
# LEF file generated by Abstract Generator version 5.5.12 on Aug 29 09:16:09 2003
#
# Contains LEF for bin Core.
# Options:   [ ] Antenna
#            [x] Geometry
#            [x] Technology

VERSION 5.3 ;
NAMESCASESENSITIVE ON ;
BUSBITCHARS "[]" ;
DIVIDERCHAR "/" ;
UNITS
  DATABASE MICRONS 1000 ;
END UNITS


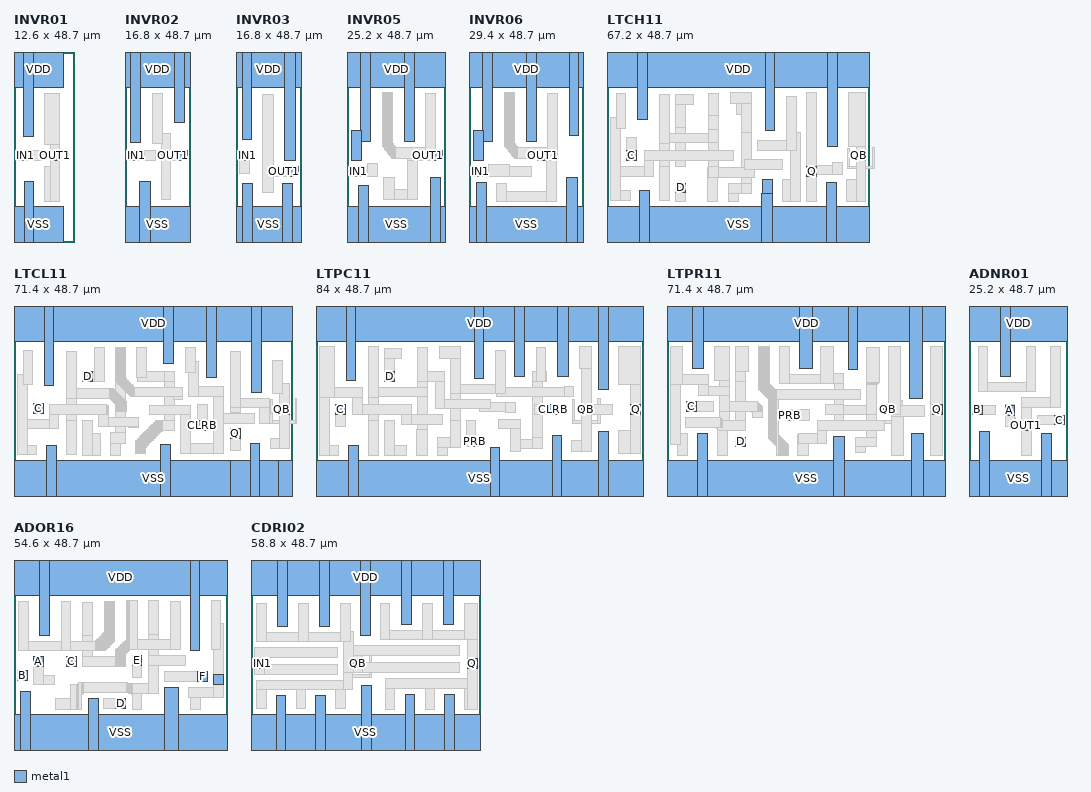
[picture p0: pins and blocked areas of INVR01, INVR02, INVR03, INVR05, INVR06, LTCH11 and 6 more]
macro INVR01
  CLASS  CORE ;
  FOREIGN INVR01 0.000 0.000 ;
  ORIGIN 0.000 0.000 ;
  SIZE 12.600 BY 48.700 ;
  SYMMETRY X Y  ;
  SITE CORE ;
  PIN OUT1
    DIRECTION OUTPUT ;
    PORT
      LAYER metal1 ;
       RECT 9.250 21.000 11.750 23.500 ;
    END
  END OUT1
  PIN VSS
    DIRECTION INOUT ;
    USE GROUND ;
    SHAPE ABUTMENT ;
    PORT
      LAYER metal1 ;
        RECT 2.600 0.000 5.100 15.550 ;
        RECT 0.000 0.000 12.600 9.000 ;
    END
  END VSS
  PIN IN1
    DIRECTION INPUT ;
    PORT
      LAYER metal1 ;
        RECT 0.850 21.000 3.350 23.500 ;
    END
  END IN1
  PIN VDD
    DIRECTION INOUT ;
    USE POWER ;
    SHAPE ABUTMENT ;
    PORT
      LAYER metal1 ;
        RECT 2.550 27.000 5.050 48.700 ;
        RECT 0.000 39.700 12.600 48.700 ;
    END
  END VDD
  OBS 
      
      LAYER metal1 ;
        RECT 0.850 21.000 7.750 23.500 ;
        RECT 7.900 10.500 11.750 19.450 ;
        RECT 9.250 10.500 11.750 38.000 ;
        RECT 7.900 25.050 11.750 38.000 ;
  END 

END INVR01

macro INVR02
  CLASS  CORE ;
  FOREIGN INVR02 0.000 0.000 ;
  ORIGIN 0.000 0.000 ;
  SIZE 16.800 BY 48.700 ;
  SYMMETRY X Y  ;
  SITE CORE ;
  PIN OUT1
    DIRECTION OUTPUT ;
    PORT
      LAYER metal1 ;
        RECT 13.450 21.000 15.950 23.500 ;
    END
  END OUT1
  PIN VSS
    DIRECTION INOUT ;
    USE GROUND ;
    SHAPE ABUTMENT ;
    PORT
      LAYER metal1 ;
        RECT 3.700 0.000 6.450 15.400 ;
        RECT 0.000 0.000 16.800 9.000 ;
    END
  END VSS
  PIN IN1
    DIRECTION INPUT ;
    PORT
      LAYER metal1 ;
        RECT 0.850 21.000 3.350 23.500 ;
    END
  END IN1
  PIN VDD
    DIRECTION INOUT ;
    USE POWER ;
    SHAPE ABUTMENT ;
    PORT
      LAYER metal1 ;
        RECT 1.400 25.600 4.100 48.700 ;
        RECT 0.000 39.700 16.800 48.700 ;
        RECT 12.700 30.600 15.300 48.700 ;
    END
  END VDD
  OBS 
     
      LAYER metal1 ;
        RECT 4.950 21.000 7.750 23.550 ;
        RECT 9.250 21.000 15.950 23.550 ;
        RECT 9.250 10.850 11.750 27.750 ;
        RECT 7.150 25.250 9.700 38.100 ;
  END 
END INVR02




macro INVR03
  CLASS  CORE ;
  FOREIGN INVR03 0.000 0.000 ;
  ORIGIN 0.000 0.000 ;
  SIZE 16.800 BY 48.700 ;
  SYMMETRY X Y  ;
  SITE CORE ;
  PIN OUT1
    DIRECTION OUTPUT ;
    PORT
      LAYER metal1 ;
        RECT 13.450 16.800 15.950 19.300 ;
    END
  END OUT1
  PIN VSS
    DIRECTION INOUT ;
    USE GROUND ;
    SHAPE ABUTMENT ;
    PORT
      LAYER metal1 ;
        RECT 1.600 0.000 4.200 15.100 ;
        RECT 0.000 0.000 16.800 9.000 ;
        RECT 11.950 0.000 14.500 15.100 ;
    END
  END VSS
  PIN IN1
    DIRECTION INPUT ;
    PORT
      LAYER metal1 ;
        RECT 0.850 21.000 3.350 23.500 ;
    END
  END IN1
  PIN VDD
    DIRECTION INOUT ;
    USE POWER ;
    SHAPE ABUTMENT ;
    PORT
      LAYER metal1 ;
        RECT 1.550 26.150 4.100 48.700 ;
        RECT 0.000 39.700 16.800 48.700 ;
        RECT 12.450 20.850 15.250 48.700 ;
    END
  END VDD
  OBS 
     
      LAYER metal1 ;
        RECT 0.850 17.600 3.550 23.500 ;
        RECT 6.800 16.800 15.950 19.300 ;
        RECT 6.800 12.700 9.500 37.850 ;
  END 
END INVR03

macro INVR05
  CLASS  CORE ;
  FOREIGN INVR05 0.000 0.000 ;
  ORIGIN 0.000 0.000 ;
  SIZE 25.200 BY 48.700 ;
  SYMMETRY X Y  ;
  SITE CORE ;
  PIN OUT1
    DIRECTION OUTPUT ;
    PORT
      LAYER metal1 ;
        RECT 21.850 21.000 24.350 23.500 ;
    END
  END OUT1
  PIN VSS
    DIRECTION INOUT ;
    USE GROUND ;
    SHAPE ABUTMENT ;
    PORT
      LAYER metal1 ;
        RECT 2.950 0.000 5.450 14.450 ;
        RECT 0.000 0.000 25.200 9.000 ;
        RECT 21.350 0.000 23.850 16.450 ;
    END
  END VSS
  PIN IN1
    DIRECTION INPUT ;
    PORT
      LAYER metal1 ;
        RECT 0.850 16.800 3.350 19.300 ;
    END
  END IN1
  PIN VDD
    DIRECTION INOUT ;
    USE POWER ;
    SHAPE ABUTMENT ;
    PORT
      LAYER metal1 ;
        RECT 0.000 39.700 25.200 48.700 ;
        RECT 14.750 25.700 17.300 48.700 ;
        RECT 3.500 25.800 6.150 48.700 ;
        RECT 1.250 20.800 3.750 28.550 ;
    END
  END VDD
  OBS 
    
      LAYER metal1 ;
        RECT 0.850 16.800 7.850 19.300 ;
        RECT 5.350 16.800 7.850 20.150 ;
        RECT 9.400 10.900 18.100 13.450 ;
        RECT 9.400 10.900 12.050 16.550 ;
        RECT 15.550 10.900 18.100 24.200 ;
        RECT 15.550 21.000 24.350 23.500 ;
        RECT 12.532 21.450 22.650 24.200 ;
        RECT 20.150 21.000 22.650 38.150 ;
        RECT 11.473 21.450 11.700 38.200 ;
        RECT 11.700 21.450 11.800 25.170 ;
        RECT 11.800 21.450 11.900 25.040 ;
        RECT 11.900 21.450 12.000 24.905 ;
        RECT 12.000 21.450 12.100 24.775 ;
        RECT 12.100 21.450 12.200 24.640 ;
        RECT 12.200 21.450 12.300 24.510 ;
        RECT 12.300 21.450 12.400 24.375 ;
        RECT 12.400 21.450 12.500 24.245 ;
        RECT 12.500 21.450 12.532 24.200 ;
        RECT 9.200 24.470 9.300 38.200 ;
        RECT 9.300 24.335 9.400 38.200 ;
        RECT 9.400 24.205 9.500 38.200 ;
        RECT 9.500 24.070 9.600 38.200 ;
        RECT 9.600 23.938 9.700 38.200 ;
        RECT 9.700 23.805 9.800 38.200 ;
        RECT 9.800 23.670 9.900 38.200 ;
        RECT 9.900 23.540 10.000 38.200 ;
        RECT 10.000 23.405 10.100 38.200 ;
        RECT 10.100 23.275 10.200 38.200 ;
        RECT 10.200 23.140 10.300 38.200 ;
        RECT 10.300 23.010 10.400 38.200 ;
        RECT 10.400 22.875 10.500 38.200 ;
        RECT 10.500 22.740 10.600 38.200 ;
        RECT 10.600 22.610 10.700 38.200 ;
        RECT 10.700 22.475 10.800 38.200 ;
        RECT 10.800 22.345 10.900 38.200 ;
        RECT 10.900 22.210 11.000 38.200 ;
        RECT 11.000 22.078 11.100 38.200 ;
        RECT 11.100 21.945 11.200 38.200 ;
        RECT 11.200 21.813 11.300 38.200 ;
        RECT 11.300 21.680 11.400 38.200 ;
        RECT 11.400 21.545 11.475 38.200 ;
  END 
END INVR05





macro INVR06
  CLASS  CORE ;
  FOREIGN INVR06 0.000 0.000 ;
  ORIGIN 0.000 0.000 ;
  SIZE 29.400 BY 48.700 ;
  SYMMETRY X Y  ;
  SITE CORE ;
  PIN OUT1
    DIRECTION OUTPUT ;
    PORT
      LAYER metal1 ;
        RECT 17.650 21.000 20.150 23.500 ;
    END
  END OUT1
  PIN VSS
    DIRECTION INOUT ;
    USE GROUND ;
    SHAPE ABUTMENT ;
    PORT
      LAYER metal1 ;
        RECT 1.950 0.000 4.450 15.300 ;
        RECT 0.000 0.000 29.400 9.000 ;
        RECT 25.100 0.000 27.900 16.650 ;
    END
  END VSS
  PIN IN1
    DIRECTION INPUT ;
    PORT
      LAYER metal1 ;
        RECT 0.850 16.800 3.350 19.300 ;
    END
  END IN1
  PIN VDD
    DIRECTION INOUT ;
    USE POWER ;
    SHAPE ABUTMENT ;
    PORT
      LAYER metal1 ;
        RECT 0.000 39.700 29.400 48.700 ;
        RECT 25.650 27.300 28.150 48.700 ;
        RECT 14.750 25.700 17.300 48.700 ;
        RECT 3.500 25.800 6.150 48.700 ;
        RECT 1.250 20.800 3.750 28.550 ;
    END
  END VDD
  OBS 
    
      LAYER metal1 ;
        RECT 0.850 16.800 16.050 19.300 ;
        RECT 4.950 16.800 16.050 19.450 ;
        RECT 4.950 16.800 10.450 19.900 ;
        RECT 7.050 10.500 22.400 13.050 ;
        RECT 7.050 10.500 9.550 15.100 ;
        RECT 17.650 21.000 22.650 24.200 ;
        RECT 19.900 10.500 22.400 24.200 ;
        RECT 12.530 21.450 22.650 24.200 ;
        RECT 20.150 21.000 22.650 38.150 ;
        RECT 11.565 21.450 11.700 38.200 ;
        RECT 11.700 21.450 11.800 25.170 ;
        RECT 11.800 21.450 11.900 25.040 ;
        RECT 11.900 21.450 12.000 24.905 ;
        RECT 12.000 21.450 12.100 24.775 ;
        RECT 12.100 21.450 12.200 24.640 ;
        RECT 12.200 21.450 12.300 24.510 ;
        RECT 12.300 21.450 12.400 24.375 ;
        RECT 12.400 21.450 12.500 24.240 ;
        RECT 12.500 21.450 12.530 24.200 ;
        RECT 9.200 24.590 9.300 38.200 ;
        RECT 9.300 24.460 9.400 38.200 ;
        RECT 9.400 24.320 9.500 38.200 ;
        RECT 9.500 24.195 9.600 38.200 ;
        RECT 9.600 24.061 9.700 38.200 ;
        RECT 9.700 23.930 9.800 38.200 ;
        RECT 9.800 23.795 9.900 38.200 ;
        RECT 9.900 23.660 10.000 38.200 ;
        RECT 10.000 23.530 10.100 38.200 ;
        RECT 10.100 23.400 10.200 38.200 ;
        RECT 10.200 23.265 10.300 38.200 ;
        RECT 10.300 23.130 10.400 38.200 ;
        RECT 10.400 22.995 10.500 38.200 ;
        RECT 10.500 22.865 10.600 38.200 ;
        RECT 10.600 22.730 10.700 38.200 ;
        RECT 10.700 22.600 10.800 38.200 ;
        RECT 10.800 22.465 10.900 38.200 ;
        RECT 10.900 22.335 11.000 38.200 ;
        RECT 11.000 22.200 11.100 38.200 ;
        RECT 11.100 22.070 11.200 38.200 ;
        RECT 11.200 21.934 11.300 38.200 ;
        RECT 11.300 21.800 11.400 38.200 ;
        RECT 11.400 21.670 11.500 38.200 ;
        RECT 11.500 21.535 11.564 38.200 ;
  END 
END INVR06

macro LTCH11
  CLASS  CORE ;
  FOREIGN LTCH11 0.000 0.000 ;
  ORIGIN 0.000 0.000 ;
  SIZE 67.200 BY 48.700 ;
  SYMMETRY X Y  ;
  SITE CORE ;
  PIN Q
    DIRECTION OUTPUT ;
    PORT
      LAYER metal1 ;
        RECT 51.250 16.800 53.750 19.300 ;
    END
  END Q
  PIN C
    DIRECTION INPUT ;
    USE CLOCK ;
    PORT
      LAYER metal1 ;
        RECT 5.050 21.000 7.550 23.500 ;
    END
  END C
  PIN D
    DIRECTION INPUT ;
    PORT
      LAYER metal1 ;
        RECT 17.650 12.600 20.150 15.100 ;
    END
  END D
  PIN QB
    DIRECTION OUTPUT ;
    PORT
      LAYER metal1 ;
        RECT 63.850 21.000 66.350 23.500 ;
    END
  END QB
  PIN VSS
    DIRECTION INOUT ;
    USE GROUND ;
    SHAPE ABUTMENT ;
    PORT
      LAYER metal1 ;
        RECT 8.350 0.000 10.850 13.100 ;
        RECT 0.000 0.000 67.200 9.000 ;
        RECT 56.350 0.000 58.850 15.300 ;
        RECT 39.850 0.000 42.350 16.100 ;
        RECT 39.550 0.000 42.350 12.400 ;
    END
  END VSS
  PIN VDD
    DIRECTION INOUT ;
    USE POWER ;
    SHAPE ABUTMENT ;
    PORT
      LAYER metal1 ;
        RECT 7.750 31.500 10.350 48.700 ;
        RECT 0.000 39.700 67.200 48.700 ;
        RECT 56.500 24.500 59.000 48.700 ;
        RECT 40.550 28.500 43.050 48.700 ;
    END
  END VDD
  OBS 
      LAYER metal2 ;
        RECT 13.450 16.800 15.950 27.700 ;
        RECT 26.050 16.800 28.550 35.600 ;
        RECT 34.450 12.600 36.950 31.900 ;
        RECT 17.650 19.303 20.150 31.900 ;
        RECT 61.550 18.800 62.150 24.050 ;
        RECT 61.600 18.800 68.050 19.300 ;
        RECT 68.050 18.800 68.500 24.140 ;
        
      LAYER via1 ;
        
        RECT 13.950 25.700 15.450 27.200 ;
        RECT 13.950 17.300 15.450 18.800 ;
        RECT 18.150 29.900 19.650 31.400 ;
        
        RECT 26.550 33.100 28.050 34.600 ;
        RECT 26.550 17.300 28.050 18.800 ;
        RECT 34.950 28.750 36.450 30.250 ;
        RECT 34.950 13.100 36.450 14.600 ;
        
       
      LAYER metal1 ;
        RECT 5.050 21.000 7.550 26.700 ;
        RECT 13.450 10.600 15.950 19.300 ;
        RECT 17.650 29.400 20.150 37.800 ;
        RECT 17.650 35.300 22.250 37.800 ;
        
        RECT 17.650 10.500 20.150 15.100 ;
        RECT 26.050 32.550 28.550 38.100 ;
        RECT 13.450 25.400 28.550 27.900 ;
        RECT 26.050 25.400 28.550 28.800 ;
        RECT 13.450 25.200 16.050 37.750 ;
        RECT 0.850 10.600 5.950 13.100 ;
        RECT 0.850 16.800 11.950 19.300 ;
        RECT 9.550 16.800 11.950 23.500 ;
        RECT 9.550 21.000 32.550 23.500 ;
        RECT 0.850 10.600 3.350 31.900 ;
        RECT 2.350 29.050 4.850 38.150 ;
        RECT 31.150 10.500 33.650 15.000 ;
        RECT 31.150 12.500 36.950 15.000 ;
        RECT 34.450 12.500 36.950 15.100 ;
        RECT 33.100 32.700 37.050 38.200 ;
        RECT 34.450 28.050 37.050 38.200 ;
        RECT 31.550 35.400 37.050 38.200 ;
        RECT 25.850 16.600 37.850 19.100 ;
        RECT 25.850 10.500 28.350 19.200 ;
        RECT 26.050 16.600 28.550 19.300 ;
        RECT 35.350 18.600 45.000 21.200 ;
        RECT 45.100 10.500 49.550 16.100 ;
        RECT 38.450 23.500 49.550 26.000 ;
        RECT 47.050 10.500 49.550 28.000 ;
        RECT 45.950 23.500 48.650 37.250 ;
        RECT 51.100 10.500 53.750 19.700 ;
        RECT 51.100 17.200 60.400 19.700 ;
        RECT 57.700 17.200 60.400 20.500 ;
        RECT 51.100 10.500 53.600 38.200 ;
        RECT 61.450 10.500 66.350 16.000 ;
        RECT 63.850 10.500 66.350 38.200 ;
        RECT 61.900 24.500 66.350 38.200 ;
  END 
END LTCH11









macro LTCL11
  CLASS  CORE ;
  FOREIGN LTCL11 0.000 0.000 ;
  ORIGIN 0.000 0.000 ;
  SIZE 71.400 BY 48.700 ;
  SYMMETRY X Y  ;
  SITE CORE ;
  PIN Q
    DIRECTION OUTPUT ;
    PORT
      LAYER metal1 ;
        RECT 55.450 14.700 57.950 17.200 ;
    END
  END Q
  PIN C
    DIRECTION INPUT ;
    USE CLOCK ;
    PORT
      LAYER metal1 ;
        RECT 5.050 21.200 7.550 23.700 ;
    END
  END C
  PIN D
    DIRECTION INPUT ;
    PORT
      LAYER metal1 ;
        RECT 17.650 29.400 20.150 31.900 ;
    END
  END D
  PIN QB
    DIRECTION OUTPUT ;
    PORT
      LAYER metal1 ;
        RECT 68.050 21.000 70.550 23.500 ;
    END
  END QB
  PIN VSS
    DIRECTION INOUT ;
    USE GROUND ;
    SHAPE ABUTMENT ;
    PORT
      LAYER metal1 ;
        RECT 8.350 0.000 10.850 13.050 ;
        RECT 0.000 0.000 71.400 9.000 ;
        RECT 55.450 0.000 67.750 9.100 ;
        RECT 60.550 0.000 63.050 13.400 ;
        RECT 37.550 0.000 40.050 13.100 ;
    END
  END VSS
  PIN VDD
    DIRECTION INOUT ;
    USE POWER ;
    SHAPE ABUTMENT ;
    PORT
      LAYER metal1 ;
        RECT 7.750 28.300 10.250 48.700 ;
        RECT 0.000 39.700 71.400 48.700 ;
        RECT 60.850 26.500 63.350 48.700 ;
        RECT 49.450 30.500 51.950 48.700 ;
        RECT 38.400 34.000 40.900 48.700 ;
    END
  END VDD
  PIN CLRB
    DIRECTION INPUT ;
    PORT
      LAYER metal1 ;
        RECT 47.050 16.800 49.550 19.300 ;
    END
  END CLRB
  OBS 
      LAYER metal2 ;
        RECT 13.450 16.800 15.950 27.600 ;
        RECT 26.050 13.500 28.550 32.000 ;
        RECT 38.650 16.800 41.150 32.000 ;
        RECT 55.450 21.400 57.950 27.700 ;
        RECT 65.750 18.700 66.350 24.850 ;
        RECT 65.750 18.700 72.250 19.300 ;
        RECT 72.250 18.700 72.530 24.880 ;
        
        
      LAYER via1 ;
     
        RECT 13.950 25.600 15.450 27.100 ;
        RECT 13.950 17.300 15.450 18.800 ;
       
        RECT 18.150 17.300 19.650 18.800 ;
        RECT 26.550 30.000 28.050 31.500 ;
        RECT 26.550 14.200 28.050 15.700 ;
        RECT 39.150 30.000 40.650 31.500 ;
        RECT 39.150 17.300 40.650 18.800 ;
        
        RECT 55.950 24.950 57.450 26.124 ;
        
      LAYER metal1 ;
        
        RECT 13.450 10.550 15.950 19.300 ;
        RECT 17.650 10.500 22.150 16.000 ;
        RECT 17.650 10.500 20.150 19.300 ;
        RECT 17.650 29.400 23.150 31.900 ;
        RECT 20.650 29.400 23.150 38.150 ;
        RECT 24.750 10.500 27.250 16.200 ;
        RECT 24.750 13.500 28.550 16.200 ;
        RECT 13.450 25.100 24.502 27.500 ;
        RECT 13.450 25.100 15.950 37.050 ;
        RECT 26.250 21.650 26.350 26.698 ;
        RECT 26.350 21.650 26.450 26.598 ;
        RECT 26.450 21.650 26.550 26.498 ;
        RECT 26.550 21.650 26.650 26.398 ;
        RECT 26.650 21.650 26.750 26.298 ;
        RECT 26.750 21.650 26.850 26.198 ;
        RECT 26.850 21.650 26.950 26.098 ;
        RECT 26.950 21.650 27.050 25.998 ;
        RECT 27.050 21.650 27.150 25.898 ;
        RECT 27.150 21.650 27.250 25.798 ;
        RECT 27.250 21.650 27.350 25.698 ;
        RECT 27.350 21.650 27.450 25.598 ;
        RECT 27.450 21.650 27.550 25.498 ;
        RECT 27.550 21.650 27.650 25.398 ;
        RECT 27.650 21.650 27.750 25.298 ;
        RECT 27.750 21.650 27.850 25.198 ;
        RECT 27.850 21.650 27.950 25.098 ;
        RECT 27.950 21.650 28.050 24.998 ;
        RECT 28.050 21.650 28.150 24.898 ;
        RECT 28.150 21.650 28.250 24.798 ;
        RECT 28.250 21.650 28.350 24.698 ;
        RECT 28.350 21.650 28.450 24.598 ;
        RECT 28.450 21.650 28.550 24.498 ;
        RECT 28.550 21.650 28.650 24.398 ;
        RECT 28.650 21.650 28.750 24.298 ;
        RECT 28.750 21.650 28.850 24.198 ;
        RECT 28.850 21.650 28.950 24.098 ;
        RECT 25.600 24.002 25.700 27.348 ;
        RECT 25.700 23.902 25.800 27.248 ;
        RECT 25.800 23.802 25.900 27.148 ;
        RECT 25.900 23.702 26.000 27.048 ;
        RECT 26.000 23.602 26.100 26.948 ;
        RECT 26.100 23.502 26.200 26.848 ;
        RECT 26.200 23.402 26.250 26.798 ;
        RECT 25.550 24.052 25.600 27.450 ;
        RECT 24.502 25.100 24.602 27.500 ;
        RECT 24.602 25.000 24.702 27.500 ;
        RECT 24.702 24.900 24.802 27.500 ;
        RECT 24.802 24.800 24.902 27.500 ;
        RECT 24.902 24.700 25.002 27.500 ;
        RECT 25.002 24.600 25.102 27.500 ;
        RECT 25.102 24.500 25.202 27.500 ;
        RECT 25.202 24.400 25.302 27.500 ;
        RECT 25.302 24.300 25.402 27.500 ;
        RECT 25.402 24.200 25.502 27.500 ;
        RECT 25.502 24.100 25.550 27.500 ;
        RECT 0.850 10.550 5.750 13.050 ;
        RECT 0.850 17.300 11.450 19.700 ;
        RECT 29.450 17.650 31.950 20.150 ;
        RECT 21.650 17.750 31.950 20.150 ;
        RECT 9.050 17.300 11.450 23.500 ;
        RECT 21.650 17.750 24.100 23.100 ;
        RECT 9.050 21.000 24.000 23.200 ;
        RECT 9.050 21.000 23.900 23.300 ;
        RECT 9.050 21.000 23.800 23.400 ;
        RECT 9.050 21.000 23.700 23.500 ;
        RECT 0.850 10.550 3.350 31.050 ;
        RECT 2.350 28.550 4.850 37.300 ;
        RECT 31.750 29.300 41.150 31.800 ;
        RECT 38.650 29.300 41.150 32.000 ;
        RECT 31.450 30.500 33.950 38.150 ;
        RECT 31.150 10.900 31.352 14.250 ;
        RECT 38.098 16.800 41.150 19.300 ;
        RECT 36.350 15.152 36.450 19.300 ;
        RECT 36.450 15.252 36.550 19.300 ;
        RECT 36.550 15.352 36.650 19.300 ;
        RECT 36.650 15.452 36.750 19.300 ;
        RECT 36.750 15.552 36.850 19.300 ;
        RECT 36.850 15.652 36.950 19.300 ;
        RECT 36.950 15.752 37.050 19.300 ;
        RECT 37.050 15.852 37.150 19.300 ;
        RECT 37.150 15.952 37.250 19.300 ;
        RECT 37.250 16.052 37.350 19.300 ;
        RECT 37.350 16.152 37.450 19.300 ;
        RECT 37.450 16.252 37.550 19.300 ;
        RECT 37.550 16.352 37.650 19.300 ;
        RECT 37.650 16.452 37.750 19.300 ;
        RECT 37.750 16.552 37.850 19.300 ;
        RECT 37.850 16.652 37.950 19.300 ;
        RECT 37.950 16.752 38.050 19.300 ;
        RECT 38.050 16.800 38.098 19.300 ;
        RECT 33.650 12.452 33.750 16.548 ;
        RECT 33.750 12.552 33.850 16.648 ;
        RECT 33.850 12.652 33.950 16.748 ;
        RECT 33.950 12.752 34.050 16.848 ;
        RECT 34.050 12.852 34.150 16.948 ;
        RECT 34.150 12.952 34.250 17.048 ;
        RECT 34.250 13.052 34.350 17.148 ;
        RECT 34.350 13.152 34.450 17.248 ;
        RECT 34.450 13.252 34.550 17.348 ;
        RECT 34.550 13.352 34.650 17.448 ;
        RECT 34.650 13.452 34.750 17.548 ;
        RECT 34.750 13.552 34.850 17.648 ;
        RECT 34.850 13.652 34.950 17.748 ;
        RECT 34.950 13.752 35.050 17.848 ;
        RECT 35.050 13.852 35.150 17.948 ;
        RECT 35.150 13.952 35.250 18.048 ;
        RECT 35.250 14.052 35.350 18.148 ;
        RECT 35.350 14.152 35.450 18.248 ;
        RECT 35.450 14.252 35.550 18.348 ;
        RECT 35.550 14.352 35.650 18.448 ;
        RECT 35.650 14.452 35.750 18.548 ;
        RECT 35.750 14.552 35.850 18.648 ;
        RECT 35.850 14.652 35.950 18.748 ;
        RECT 35.950 14.752 36.050 18.848 ;
        RECT 36.050 14.852 36.150 18.948 ;
        RECT 36.150 14.952 36.250 19.048 ;
        RECT 36.250 15.052 36.350 19.148 ;
        RECT 31.352 10.900 31.452 14.250 ;
        RECT 31.452 10.900 31.552 14.350 ;
        RECT 31.552 10.900 31.652 14.450 ;
        RECT 31.652 10.900 31.752 14.550 ;
        RECT 31.752 10.900 31.852 14.650 ;
        RECT 31.852 10.900 31.952 14.750 ;
        RECT 31.952 10.900 32.052 14.850 ;
        RECT 32.052 10.900 32.152 14.950 ;
        RECT 32.152 10.900 32.252 15.050 ;
        RECT 32.252 10.900 32.352 15.150 ;
        RECT 32.352 10.900 32.452 15.250 ;
        RECT 32.452 10.900 32.552 15.350 ;
        RECT 32.552 10.900 32.652 15.450 ;
        RECT 32.652 10.900 32.752 15.550 ;
        RECT 32.752 10.900 32.852 15.650 ;
        RECT 32.852 10.900 32.952 15.750 ;
        RECT 32.952 10.900 33.052 15.850 ;
        RECT 33.052 10.900 33.152 15.950 ;
        RECT 33.152 10.900 33.252 16.050 ;
        RECT 33.252 10.900 33.352 16.150 ;
        RECT 33.352 10.900 33.452 16.250 ;
        RECT 33.452 10.900 33.552 16.350 ;
        RECT 33.552 10.900 33.650 16.450 ;
        RECT 40.800 24.800 43.300 27.800 ;
        RECT 30.948 25.400 43.300 27.800 ;
        RECT 26.350 29.000 26.352 38.150 ;
        RECT 29.950 25.400 30.050 28.698 ;
        RECT 30.050 25.400 30.150 28.598 ;
        RECT 30.150 25.400 30.250 28.498 ;
        RECT 30.250 25.400 30.350 28.398 ;
        RECT 30.350 25.400 30.450 28.298 ;
        RECT 30.450 25.400 30.550 28.198 ;
        RECT 30.550 25.400 30.650 28.098 ;
        RECT 30.650 25.400 30.750 27.998 ;
        RECT 30.750 25.400 30.850 27.898 ;
        RECT 30.850 25.400 30.948 27.800 ;
        RECT 29.800 25.550 29.900 28.848 ;
        RECT 29.900 25.450 29.950 28.798 ;
        RECT 28.550 26.802 28.650 30.098 ;
        RECT 28.650 26.702 28.750 29.998 ;
        RECT 28.750 26.602 28.850 29.898 ;
        RECT 28.850 26.502 28.950 29.798 ;
        RECT 28.950 26.402 29.050 29.698 ;
        RECT 29.050 26.302 29.150 29.598 ;
        RECT 29.150 26.202 29.250 29.498 ;
        RECT 29.250 26.102 29.350 29.398 ;
        RECT 29.350 26.002 29.450 29.298 ;
        RECT 29.450 25.902 29.550 29.198 ;
        RECT 29.550 25.802 29.650 29.098 ;
        RECT 29.650 25.702 29.750 28.998 ;
        RECT 29.750 25.602 29.800 28.948 ;
        RECT 26.352 29.000 26.452 38.150 ;
        RECT 26.452 28.900 26.552 38.150 ;
        RECT 26.552 28.800 26.652 38.150 ;
        RECT 26.652 28.700 26.752 38.150 ;
        RECT 26.752 28.600 26.852 38.150 ;
        RECT 26.852 28.500 26.952 38.150 ;
        RECT 26.952 28.400 27.052 38.150 ;
        RECT 27.052 28.300 27.152 38.150 ;
        RECT 27.152 28.200 27.252 38.150 ;
        RECT 27.252 28.100 27.352 38.150 ;
        RECT 27.352 28.000 27.452 38.150 ;
        RECT 27.452 27.900 27.552 38.150 ;
        RECT 27.552 27.800 27.652 38.150 ;
        RECT 27.652 27.700 27.752 38.150 ;
        RECT 27.752 27.600 27.852 38.150 ;
        RECT 27.852 27.500 27.952 38.150 ;
        RECT 27.952 27.400 28.052 38.150 ;
        RECT 28.052 27.300 28.152 38.150 ;
        RECT 28.152 27.200 28.252 38.150 ;
        RECT 28.252 27.100 28.352 38.150 ;
        RECT 28.352 27.000 28.452 38.150 ;
        RECT 28.452 26.900 28.550 38.150 ;
        RECT 26.050 29.300 26.150 38.150 ;
        RECT 26.150 29.200 26.250 38.150 ;
        RECT 26.250 29.100 26.350 38.150 ;
        RECT 47.050 16.800 49.550 23.500 ;
        RECT 55.450 11.700 57.950 17.200 ;
        RECT 42.750 11.000 53.750 13.500 ;
        RECT 59.050 18.600 61.550 21.100 ;
        RECT 51.250 18.700 61.550 21.100 ;
        RECT 42.750 11.000 45.150 23.300 ;
        RECT 34.850 20.800 45.150 23.300 ;
        RECT 51.250 11.000 53.750 27.950 ;
        RECT 44.800 25.550 53.750 27.950 ;
        RECT 44.800 25.550 47.200 34.400 ;
        RECT 44.050 31.700 46.550 38.150 ;
        RECT 63.050 18.600 66.250 21.100 ;
        RECT 63.050 18.600 65.450 25.000 ;
        RECT 55.450 22.600 65.450 25.000 ;
        RECT 55.450 22.600 57.950 37.100 ;
        RECT 65.650 12.200 70.550 14.700 ;
        RECT 68.050 12.200 70.550 28.950 ;
        RECT 66.250 26.300 68.750 34.800 ;
  END 
END LTCL11











macro LTPC11
  CLASS  CORE ;
  FOREIGN LTPC11 0.000 0.000 ;
  ORIGIN 0.000 0.000 ;
  SIZE 84.000 BY 48.700 ;
  SYMMETRY X Y  ;
  SITE CORE ;
  PIN Q
    DIRECTION OUTPUT ;
    PORT
      LAYER metal1 ;
        RECT 80.650 21.000 83.150 23.500 ;
    END
  END Q
  PIN C
    DIRECTION INPUT ;
    USE CLOCK ;
    PORT
      LAYER metal1 ;
        RECT 5.050 21.000 7.550 23.500 ;
    END
  END C
  PIN D
    DIRECTION INPUT ;
    PORT
      LAYER metal1 ;
        RECT 17.650 29.400 20.150 31.900 ;
    END
  END D
  PIN QB
    DIRECTION OUTPUT ;
    PORT
      LAYER metal1 ;
        RECT 68.050 21.000 70.550 23.500 ;
    END
  END QB
  PIN VSS
    DIRECTION INOUT ;
    USE GROUND ;
    SHAPE ABUTMENT ;
    PORT
      LAYER metal1 ;
        RECT 8.350 0.000 10.850 13.050 ;
        RECT 0.000 0.000 84.000 9.000 ;
        RECT 72.500 0.000 75.050 16.550 ;
        RECT 60.550 0.000 63.050 15.500 ;
        RECT 44.650 0.000 47.150 12.500 ;
    END
  END VSS
  PIN PRB
    DIRECTION INPUT ;
    PORT
      LAYER metal1 ;
        RECT 39.550 12.600 42.050 15.100 ;
    END
  END PRB
  PIN VDD
    DIRECTION INOUT ;
    USE POWER ;
    SHAPE ABUTMENT ;
    PORT
      LAYER metal1 ;
        RECT 7.700 29.700 10.200 48.700 ;
        RECT 0.000 39.700 84.000 48.700 ;
        RECT 72.500 27.200 75.000 48.700 ;
        RECT 61.800 30.700 64.600 48.700 ;
        RECT 51.000 30.700 53.500 48.700 ;
        RECT 40.550 30.150 43.050 48.700 ;
    END
  END VDD
  PIN CLRB
    DIRECTION INPUT ;
    PORT
      LAYER metal1 ;
        RECT 59.650 21.000 62.150 23.500 ;
    END
  END CLRB
  OBS 
      LAYER metal2 ;
        RECT 13.450 16.800 15.950 27.700 ;
        RECT 26.050 13.500 28.550 31.900 ;
        RECT 34.450 16.800 36.950 31.900 ;
        RECT 55.450 12.600 57.950 31.900 ;
        RECT 55.450 29.400 59.000 31.900 ;
        RECT 65.750 18.700 66.350 24.850 ;
        RECT 65.750 18.700 72.850 19.300 ;
        RECT 72.250 18.700 72.850 24.880 ;
        
        
        
        
      LAYER via1 ;
        
        RECT 13.950 25.700 15.450 27.200 ;
        RECT 13.950 17.300 15.450 18.800 ;
       
        RECT 18.150 17.300 19.650 18.800 ;
        RECT 26.550 29.900 28.050 31.400 ;
        RECT 26.550 14.950 28.050 16.450 ;
        RECT 34.950 29.900 36.450 31.400 ;
        RECT 34.950 17.300 36.450 18.800 ;
       
        RECT 55.950 13.100 57.450 14.600 ;
        RECT 56.900 29.900 58.400 31.400 ;
       
        
        
      LAYER metal1 ;
        RECT 5.000 17.850 7.550 22.550 ;
        RECT 5.050 17.850 7.550 23.500 ;
        RECT 13.450 10.500 16.050 19.300 ;
        RECT 17.650 29.400 20.150 37.800 ;
        RECT 17.650 35.300 21.800 37.800 ;
        RECT 17.650 10.500 23.250 13.050 ;
        RECT 17.650 10.500 20.150 19.300 ;
        RECT 13.450 25.200 16.050 27.700 ;
        RECT 13.550 25.400 28.550 27.900 ;
        RECT 13.550 25.200 16.050 38.200 ;
        RECT 25.850 10.500 28.550 16.950 ;
        RECT 0.850 10.500 5.750 13.050 ;
        RECT 30.050 18.300 32.550 20.850 ;
        RECT 21.850 18.450 32.550 20.850 ;
        RECT 21.850 18.450 24.350 23.550 ;
        RECT 9.250 21.000 24.350 23.550 ;
        RECT 0.850 10.500 3.350 38.200 ;
        RECT 9.250 21.000 11.800 27.900 ;
        RECT 0.850 25.200 11.800 27.900 ;
        RECT 0.850 25.200 4.800 38.200 ;
        RECT 31.150 10.500 33.650 15.000 ;
        RECT 31.150 12.500 36.950 15.000 ;
        RECT 34.450 12.500 36.950 19.300 ;
        RECT 38.450 12.600 42.050 15.100 ;
        RECT 38.450 12.600 40.950 19.350 ;
        RECT 41.900 21.550 51.150 23.950 ;
        RECT 48.650 21.400 51.150 23.950 ;
        RECT 30.550 22.350 44.800 24.750 ;
        RECT 30.550 22.350 32.950 31.800 ;
        RECT 26.050 29.400 32.950 31.800 ;
        RECT 26.050 29.400 28.550 38.100 ;
        RECT 49.950 12.100 57.950 14.600 ;
        RECT 55.450 12.100 57.950 15.100 ;
        RECT 49.950 11.300 52.450 19.700 ;
        RECT 46.900 17.200 52.450 19.700 ;
        RECT 56.400 29.400 58.900 38.150 ;
        RECT 55.900 20.900 62.150 23.500 ;
        RECT 46.350 25.450 66.100 27.850 ;
        RECT 63.600 25.450 66.100 27.950 ;
        RECT 34.450 26.250 48.450 28.650 ;
        RECT 45.950 26.250 48.450 37.250 ;
        RECT 34.450 26.250 37.050 38.200 ;
        RECT 31.550 35.150 37.050 38.200 ;
        RECT 65.600 11.450 70.550 14.300 ;
        RECT 68.050 20.900 76.050 23.400 ;
        RECT 68.050 11.450 70.550 38.200 ;
        RECT 67.450 32.700 70.550 38.200 ;
        RECT 77.600 10.800 83.150 16.900 ;
        RECT 80.650 10.800 83.150 38.200 ;
        RECT 77.600 28.700 83.150 38.200 ;
  END 
END LTPC11





macro LTPR11
  CLASS  CORE ;
  FOREIGN LTPR11 0.000 0.000 ;
  ORIGIN 0.000 0.000 ;
  SIZE 71.400 BY 48.700 ;
  SYMMETRY X Y  ;
  SITE CORE ;
  PIN Q
    DIRECTION OUTPUT ;
    PORT
      LAYER metal1 ;
        RECT 68.050 21.000 70.550 23.500 ;
    END
  END Q
  PIN C
    DIRECTION INPUT ;
    USE CLOCK ;
    PORT
      LAYER metal1 ;
        RECT 5.050 21.600 7.550 24.100 ;
    END
  END C
  PIN D
    DIRECTION INPUT ;
    PORT
      LAYER metal1 ;
        RECT 17.650 12.600 20.150 15.100 ;
    END
  END D
  PIN QB
    DIRECTION OUTPUT ;
    PORT
      LAYER metal1 ;
        RECT 55.450 21.000 57.950 23.500 ;
    END
  END QB
  PIN VSS
    DIRECTION INOUT ;
    USE GROUND ;
    SHAPE ABUTMENT ;
    PORT
      LAYER metal1 ;
        RECT 7.850 0.000 10.500 16.000 ;
        RECT 0.000 0.000 71.400 9.000 ;
        RECT 62.550 0.000 65.750 16.050 ;
        RECT 42.700 0.000 45.450 15.350 ;
    END
  END VSS
  PIN PRB
    DIRECTION INPUT ;
    PORT
      LAYER metal1 ;
        RECT 30.250 19.345 32.750 21.845 ;
    END
  END PRB
  PIN VDD
    DIRECTION INOUT ;
    USE POWER ;
    SHAPE ABUTMENT ;
    PORT
      LAYER metal1 ;
        RECT 6.650 32.700 9.400 48.700 ;
        RECT 0.000 39.700 71.400 48.700 ;
        RECT 62.250 25.000 65.550 48.700 ;
        RECT 46.450 32.400 48.950 48.700 ;
        RECT 33.950 32.700 37.300 48.700 ;
    END
  END VDD
  OBS 
      LAYER metal2 ;
        RECT 12.123 29.700 13.450 32.200 ;
        RECT 13.450 16.800 15.950 32.200 ;
        RECT 17.649 19.350 20.150 31.900 ;
        RECT 42.850 16.850 45.350 31.300 ;
        RECT 51.250 12.600 53.750 23.350 ;
        RECT 55.450 18.700 60.250 19.300 ;
        RECT 59.650 18.700 60.250 24.480 ;
       
       
        
      LAYER via1 ;
        
        RECT 12.763 30.200 14.263 31.700 ;
        RECT 13.950 17.300 15.450 18.800 ;
        RECT 18.150 29.900 19.650 31.400 ;
       
        
        RECT 43.350 29.300 44.850 30.800 ;
        RECT 43.350 17.350 44.850 18.850 ;
        RECT 51.750 21.350 53.250 22.850 ;
        RECT 51.750 13.100 53.250 14.600 ;
        
        
      LAYER metal1 ;
        RECT 5.050 21.600 11.950 24.100 ;
        RECT 12.050 29.700 15.950 38.200 ;
        RECT 12.950 10.500 15.450 19.350 ;
        RECT 12.750 17.350 20.150 19.350 ;
        RECT 12.850 17.250 13.600 20.100 ;
        RECT 12.650 17.450 20.150 19.350 ;
        RECT 12.950 16.800 20.150 19.350 ;
        RECT 4.850 17.550 14.300 19.400 ;
        RECT 4.850 17.550 14.200 19.500 ;
        RECT 4.850 17.550 14.100 19.600 ;
        RECT 4.850 17.550 14.000 19.700 ;
        RECT 4.850 17.550 13.900 19.800 ;
        RECT 4.850 17.550 13.800 19.900 ;
        RECT 4.850 17.550 13.700 20.000 ;
        RECT 4.850 17.550 13.600 20.100 ;
        RECT 17.650 29.400 20.150 38.200 ;
        RECT 17.650 31.900 20.900 38.200 ;
        RECT 2.600 10.500 5.350 16.000 ;
        RECT 21.750 21.500 23.092 24.200 ;
        RECT 21.650 21.600 24.350 22.940 ;
        RECT 21.850 20.150 24.350 22.940 ;
        RECT 13.450 21.700 24.292 23.000 ;
        RECT 13.450 21.700 24.192 23.100 ;
        RECT 13.450 21.700 24.092 23.200 ;
        RECT 13.450 21.700 23.992 23.300 ;
        RECT 13.450 21.700 23.892 23.400 ;
        RECT 13.450 21.700 23.792 23.500 ;
        RECT 13.450 21.700 23.692 23.600 ;
        RECT 13.450 21.700 23.592 23.700 ;
        RECT 13.450 21.700 23.492 23.800 ;
        RECT 13.450 21.700 23.392 23.900 ;
        RECT 13.450 21.700 23.292 24.000 ;
        RECT 13.450 21.700 23.192 24.100 ;
        RECT 13.450 21.700 23.092 24.200 ;
        RECT 13.450 21.700 15.950 28.100 ;
        RECT 8.050 25.700 15.950 28.100 ;
        RECT 0.850 13.300 3.350 38.200 ;
        RECT 8.050 25.700 10.550 31.200 ;
        RECT 0.850 28.700 10.550 31.200 ;
        RECT 0.850 28.700 3.900 38.200 ;
       
        
        RECT 30.250 19.350 36.650 22.150 ;
        RECT 28.850 28.800 45.350 31.200 ;
        RECT 39.450 28.800 45.350 31.300 ;
        RECT 28.850 28.800 31.450 38.200 ;
        RECT 39.450 28.800 42.600 38.200 ;
        RECT 27.950 10.500 28.550 27.250 ;
        RECT 46.900 24.750 49.500 27.250 ;
        RECT 27.950 24.850 49.500 27.250 ;
        RECT 28.550 10.500 28.650 15.650 ;
        RECT 28.650 10.500 28.750 15.550 ;
        RECT 28.750 10.500 28.850 15.450 ;
        RECT 28.850 10.500 28.950 15.350 ;
        RECT 28.950 10.500 29.050 15.250 ;
        RECT 29.050 10.500 29.150 15.150 ;
        RECT 29.150 10.500 29.250 15.050 ;
        RECT 29.250 10.500 29.350 14.950 ;
        RECT 29.350 10.500 29.450 14.850 ;
        RECT 29.450 10.500 29.550 14.750 ;
        RECT 29.550 10.500 29.650 14.650 ;
        RECT 29.650 10.500 29.750 14.550 ;
        RECT 29.750 10.500 29.850 14.450 ;
        RECT 29.850 10.500 29.950 14.350 ;
        RECT 29.950 10.500 30.050 14.250 ;
        RECT 30.050 10.500 30.150 14.150 ;
        RECT 30.150 10.500 30.250 14.050 ;
        RECT 30.250 10.500 30.350 13.950 ;
        RECT 30.350 10.500 30.450 13.850 ;
        RECT 30.450 10.500 30.550 13.750 ;
        RECT 30.550 10.500 30.650 13.650 ;
        RECT 30.650 10.500 30.750 13.550 ;
        RECT 30.750 10.500 30.850 13.450 ;
        RECT 30.850 10.500 30.950 13.350 ;
        RECT 30.950 10.500 31.050 13.250 ;
        RECT 31.050 10.500 31.100 13.200 ;
        RECT 27.750 13.098 27.852 27.250 ;
        RECT 27.850 12.998 27.950 27.250 ;
        RECT 26.150 14.700 26.250 28.750 ;
        RECT 26.250 14.600 26.350 28.650 ;
        RECT 26.350 14.500 26.450 28.550 ;
        RECT 26.450 14.400 26.550 28.450 ;
        RECT 26.550 14.300 26.650 28.350 ;
        RECT 26.650 14.200 26.750 28.250 ;
        RECT 26.750 14.100 26.850 28.150 ;
        RECT 26.850 14.000 26.950 28.050 ;
        RECT 26.950 13.900 27.050 27.950 ;
        RECT 27.050 13.800 27.150 27.850 ;
        RECT 27.150 13.700 27.250 27.750 ;
        RECT 27.250 13.600 27.350 27.650 ;
        RECT 27.350 13.500 27.450 27.550 ;
        RECT 27.450 13.400 27.550 27.450 ;
        RECT 27.550 13.300 27.650 27.350 ;
        RECT 27.650 13.200 27.750 27.250 ;
        RECT 27.750 13.100 27.752 27.250 ;
        RECT 25.900 14.950 26.000 38.200 ;
        RECT 26.000 14.850 26.100 38.200 ;
        RECT 26.100 14.750 26.150 38.200 ;
        RECT 23.450 27.350 23.550 38.200 ;
        RECT 23.550 27.250 23.650 38.200 ;
        RECT 23.650 27.150 23.750 38.200 ;
        RECT 23.750 27.050 23.850 38.200 ;
        RECT 23.850 26.950 23.950 38.200 ;
        RECT 23.950 26.850 24.050 38.200 ;
        RECT 24.050 26.750 24.150 38.200 ;
        RECT 24.150 26.650 24.250 38.200 ;
        RECT 24.250 26.550 24.350 38.200 ;
        RECT 24.350 26.450 24.450 38.200 ;
        RECT 24.450 26.350 24.550 38.200 ;
        RECT 24.550 26.250 24.650 38.200 ;
        RECT 24.650 26.150 24.750 38.200 ;
        RECT 24.750 26.050 24.850 38.200 ;
        RECT 24.850 25.950 24.950 38.200 ;
        RECT 24.950 25.850 25.050 38.200 ;
        RECT 25.050 25.750 25.150 38.200 ;
        RECT 25.150 25.650 25.250 38.200 ;
        RECT 25.250 25.550 25.350 38.200 ;
        RECT 25.350 25.450 25.450 38.200 ;
        RECT 25.450 25.350 25.550 38.200 ;
        RECT 25.550 25.250 25.650 38.200 ;
        RECT 25.650 25.150 25.750 38.200 ;
        RECT 25.750 25.050 25.850 38.200 ;
        RECT 25.850 24.950 25.900 38.200 ;
        RECT 48.200 11.150 50.900 15.100 ;
        RECT 48.200 12.600 53.750 15.100 ;
        RECT 40.700 20.850 53.750 23.250 ;
        RECT 40.700 20.850 45.250 23.350 ;
        RECT 51.250 20.850 53.750 38.150 ;
        RECT 51.250 28.500 53.850 38.150 ;
        RECT 51.250 28.600 53.950 38.150 ;
        RECT 51.250 28.700 54.050 38.150 ;
        RECT 51.250 28.800 54.150 38.150 ;
        RECT 51.250 28.900 54.250 38.150 ;
        RECT 51.250 29.000 54.350 38.150 ;
        RECT 33.550 10.500 36.150 15.850 ;
        RECT 33.650 13.500 41.000 15.950 ;
        RECT 33.700 13.500 41.000 16.000 ;
        RECT 38.500 13.500 41.000 19.350 ;
        RECT 38.500 16.850 55.850 19.350 ;
        RECT 57.450 10.500 60.550 23.300 ;
        RECT 57.450 20.300 66.050 23.300 ;
        RECT 55.450 21.000 59.950 23.500 ;
        RECT 56.850 21.000 59.950 38.200 ;
        RECT 67.550 10.500 70.550 38.200 ;
  END 
END LTPR11


macro ADNR01
  CLASS  CORE ;
  FOREIGN ADNR01 0.000 0.000 ;
  ORIGIN 0.000 0.000 ;
  SIZE 25.200 BY 48.700 ;
  SYMMETRY X Y  ;
  SITE CORE ;
  PIN A
    DIRECTION INPUT ;
    PORT
      LAYER metal1 ;
        RECT 9.250 20.700 11.750 23.200 ;
    END
  END A
  PIN B
    DIRECTION INPUT ;
    PORT
      LAYER metal1 ;
        RECT 0.850 20.800 3.350 23.300 ;
    END
  END B
  PIN C
    DIRECTION INPUT ;
    PORT
      LAYER metal1 ;
        RECT 21.850 18.200 24.350 20.700 ;
    END
  END C
  PIN OUT1
    DIRECTION OUTPUT ;
    PORT
      LAYER metal1 ;
        RECT 13.450 16.800 15.950 19.300 ;
    END
  END OUT1
  PIN VSS
    DIRECTION INOUT ;
    USE GROUND ;
    SHAPE ABUTMENT ;
    PORT
      LAYER metal1 ;
        RECT 2.650 0.000 5.150 16.500 ;
        RECT 0.000 0.000 25.200 9.000 ;
        RECT 18.550 0.000 21.050 16.000 ;
    END
  END VSS
  PIN VDD
    DIRECTION INOUT ;
    USE POWER ;
    SHAPE ABUTMENT ;
    PORT
      LAYER metal1 ;
        RECT 8.050 30.700 10.550 48.700 ;
        RECT 0.000 39.700 25.200 48.700 ;
    END
  END VDD
  OBS 
     
      LAYER metal1 ;
        RECT 0.850 20.800 6.850 23.300 ;
        RECT 9.250 17.700 11.950 20.200 ;
        RECT 9.250 17.700 11.750 23.500 ;
        RECT 2.350 26.700 17.150 29.200 ;
        RECT 2.350 26.700 4.850 38.200 ;
        RECT 14.650 26.700 17.150 38.200 ;
        RECT 13.450 10.500 15.950 25.200 ;
        RECT 13.450 22.700 23.350 25.200 ;
        RECT 20.850 22.700 23.350 38.200 ;
        RECT 17.450 18.200 24.350 20.700 ;
  END 
END ADNR01








macro ADOR16
  CLASS  CORE ;
  FOREIGN ADOR16 0.000 0.000 ;
  ORIGIN 0.000 0.000 ;
  SIZE 54.600 BY 48.700 ;
  SYMMETRY X Y  ;
  SITE CORE ;
  PIN A
    DIRECTION INPUT ;
    PORT
      LAYER metal1 ;
        RECT 5.050 21.500 7.550 24.000 ;
    END
  END A
  PIN B
    DIRECTION INPUT ;
    PORT
      LAYER metal1 ;
        RECT 0.850 17.800 3.350 20.300 ;
    END
  END B
  PIN C
    DIRECTION INPUT ;
    PORT
      LAYER metal1 ;
        RECT 13.450 21.500 15.950 24.000 ;
    END
  END C
  PIN D
    DIRECTION INPUT ;
    PORT
      LAYER metal1 ;
        RECT 26.050 10.650 28.550 13.150 ;
    END
  END D
  PIN OUT1
    DIRECTION OUTPUT ;
    PORT
      LAYER metal1 ;
        RECT 51.250 16.800 53.750 19.300 ;
    END
  END OUT1
  PIN E
    DIRECTION INPUT ;
    PORT
      LAYER metal1 ;
        RECT 30.250 21.600 32.750 24.100 ;
    END
  END E
  PIN F
    DIRECTION INPUT ;
    PORT
      LAYER metal1 ;
        RECT 47.050 17.500 49.550 20.000 ;
    END
  END F
  PIN VSS
    DIRECTION INOUT ;
    USE GROUND ;
    SHAPE ABUTMENT ;
    PORT
      LAYER metal1 ;
        RECT 1.650 0.000 4.150 14.950 ;
        RECT 0.000 0.000 54.600 9.000 ;
        RECT 38.550 0.000 42.050 16.000 ;
        RECT 19.050 0.000 21.550 13.250 ;
    END
  END VSS
  PIN VDD
    DIRECTION INOUT ;
    USE POWER ;
    SHAPE ABUTMENT ;
    PORT
      LAYER metal1 ;
        RECT 6.650 29.400 9.150 48.700 ;
        RECT 0.000 39.700 54.600 48.700 ;
        RECT 45.150 25.600 47.650 48.700 ;
    END
  END VDD
  OBS 
      LAYER metal2 ;
        RECT 17.650 21.500 20.150 34.900 ;
        RECT 34.450 21.700 36.950 35.450 ;
        
      LAYER via1 ;
        
        RECT 18.150 32.900 19.650 34.400 ;
        RECT 18.150 22.000 19.650 23.500 ;
        
        RECT 34.950 33.200 36.450 34.700 ;
        RECT 34.950 22.200 36.450 23.700 ;
        
      LAYER metal1 ;
       
        RECT 5.050 16.700 10.400 19.200 ;
        RECT 5.050 16.700 7.550 24.000 ;
        
       
        RECT 17.650 29.400 20.150 37.900 ;
        RECT 1.250 25.500 20.900 27.900 ;
        RECT 12.050 25.500 14.550 38.000 ;
        RECT 1.250 25.500 3.750 38.100 ;
        RECT 23.300 25.500 23.450 38.100 ;
        RECT 23.450 25.600 23.550 38.100 ;
        RECT 23.550 25.700 23.650 38.100 ;
        RECT 23.650 25.800 23.750 38.100 ;
        RECT 23.750 25.900 23.850 38.100 ;
        RECT 23.850 26.000 23.950 38.100 ;
        RECT 23.950 26.100 24.050 38.100 ;
        RECT 24.050 26.200 24.150 38.100 ;
        RECT 24.150 26.300 24.250 38.100 ;
        RECT 24.250 26.400 24.350 38.100 ;
        RECT 24.350 26.500 24.450 38.100 ;
        RECT 24.450 26.600 24.550 38.100 ;
        RECT 24.550 26.700 24.650 38.100 ;
        RECT 24.650 26.800 24.750 38.100 ;
        RECT 24.750 26.900 24.850 38.100 ;
        RECT 24.850 27.000 24.950 38.100 ;
        RECT 24.950 27.100 25.050 38.100 ;
        RECT 25.050 27.200 25.150 38.100 ;
        RECT 25.150 27.300 25.250 38.100 ;
        RECT 25.250 27.400 25.350 38.100 ;
        RECT 25.350 27.500 25.450 38.100 ;
        RECT 25.450 27.600 25.550 38.100 ;
        RECT 25.550 27.700 25.650 38.100 ;
        RECT 25.650 27.800 25.750 38.100 ;
        RECT 25.750 27.900 25.850 38.100 ;
        RECT 20.900 25.500 21.000 27.900 ;
        RECT 21.000 25.500 21.100 28.000 ;
        RECT 21.100 25.500 21.200 28.100 ;
        RECT 21.200 25.500 21.300 28.200 ;
        RECT 21.300 25.500 21.400 28.300 ;
        RECT 21.400 25.500 21.500 28.400 ;
        RECT 21.500 25.500 21.600 28.500 ;
        RECT 21.600 25.500 21.700 28.600 ;
        RECT 21.700 25.500 21.800 28.700 ;
        RECT 21.800 25.500 21.900 28.800 ;
        RECT 21.900 25.500 22.000 28.900 ;
        RECT 22.000 25.500 22.100 29.000 ;
        RECT 22.100 25.500 22.200 29.100 ;
        RECT 22.200 25.500 22.300 29.200 ;
        RECT 22.300 25.500 22.400 29.300 ;
        RECT 22.400 25.500 22.500 29.400 ;
        RECT 22.500 25.500 22.600 29.500 ;
        RECT 22.600 25.500 22.700 29.600 ;
        RECT 22.700 25.500 22.800 29.700 ;
        RECT 22.800 25.500 22.900 29.800 ;
        RECT 22.900 25.500 23.000 29.900 ;
        RECT 23.000 25.500 23.100 30.000 ;
        RECT 23.100 25.500 23.200 30.100 ;
        RECT 23.200 25.500 23.300 30.200 ;
        RECT 23.050 10.650 28.550 13.050 ;
        RECT 23.050 10.650 28.450 13.150 ;
        RECT 30.250 18.600 32.750 24.100 ;
        RECT 34.450 29.700 36.950 38.200 ;
        RECT 17.650 21.500 26.100 24.000 ;
        RECT 29.650 25.700 42.650 28.200 ;
        RECT 40.150 25.700 42.650 38.000 ;
        RECT 29.650 25.700 31.550 38.200 ;
        RECT 28.750 24.900 28.850 38.200 ;
        RECT 28.850 25.000 28.950 38.200 ;
        RECT 28.950 25.100 29.050 38.200 ;
        RECT 29.050 25.200 29.150 38.200 ;
        RECT 29.150 25.300 29.250 38.200 ;
        RECT 29.250 25.400 29.350 38.200 ;
        RECT 29.350 25.500 29.450 38.200 ;
        RECT 29.450 25.600 29.550 38.200 ;
        RECT 29.550 25.700 29.650 38.200 ;
        RECT 28.550 24.700 28.650 28.086 ;
        RECT 28.650 24.800 28.750 28.186 ;
        RECT 26.100 21.500 26.200 25.636 ;
        RECT 26.200 21.500 26.300 25.736 ;
        RECT 26.300 21.500 26.400 25.836 ;
        RECT 26.400 21.500 26.500 25.936 ;
        RECT 26.500 21.500 26.600 26.036 ;
        RECT 26.600 21.500 26.700 26.136 ;
        RECT 26.700 21.500 26.800 26.236 ;
        RECT 26.800 21.500 26.900 26.336 ;
        RECT 26.900 21.500 27.000 26.436 ;
        RECT 27.000 21.500 27.100 26.536 ;
        RECT 27.100 21.500 27.200 26.636 ;
        RECT 27.200 21.500 27.300 26.736 ;
        RECT 27.300 21.500 27.400 26.836 ;
        RECT 27.400 21.500 27.500 26.936 ;
        RECT 27.500 21.500 27.600 27.036 ;
        RECT 27.600 21.500 27.700 27.136 ;
        RECT 27.700 21.500 27.800 27.236 ;
        RECT 27.800 21.500 27.900 27.336 ;
        RECT 27.900 21.500 28.000 27.436 ;
        RECT 28.000 21.500 28.100 27.536 ;
        RECT 28.100 21.500 28.200 27.636 ;
        RECT 28.200 21.500 28.300 27.736 ;
        RECT 28.300 21.500 28.400 27.836 ;
        RECT 28.400 21.500 28.500 27.936 ;
        RECT 28.500 21.500 28.550 28.036 ;
        RECT 10.750 10.500 16.102 13.150 ;
        RECT 30.250 10.500 32.750 16.950 ;
        RECT 14.500 10.500 16.102 16.700 ;
        RECT 30.250 14.450 36.950 16.950 ;
        RECT 16.602 10.500 17.400 17.200 ;
        RECT 17.900 14.750 28.777 17.200 ;
        RECT 34.450 14.450 36.950 24.200 ;
        RECT 34.450 21.700 43.950 24.200 ;
        RECT 30.015 14.372 30.115 16.950 ;
        RECT 30.115 14.341 30.215 16.950 ;
        RECT 30.215 14.311 30.250 16.950 ;
        RECT 29.196 14.622 29.296 17.170 ;
        RECT 29.296 14.592 29.396 17.139 ;
        RECT 29.396 14.561 29.496 17.109 ;
        RECT 29.496 14.531 29.596 17.078 ;
        RECT 29.596 14.500 29.696 17.047 ;
        RECT 29.696 14.469 29.796 17.017 ;
        RECT 29.796 14.439 29.896 16.986 ;
        RECT 29.896 14.408 29.996 16.956 ;
        RECT 29.996 14.378 30.015 16.950 ;
        RECT 28.777 14.750 28.877 17.200 ;
        RECT 28.877 14.720 28.977 17.200 ;
        RECT 28.977 14.689 29.077 17.200 ;
        RECT 29.077 14.658 29.177 17.200 ;
        RECT 29.177 14.628 29.196 17.200 ;
        RECT 17.400 14.350 17.500 17.200 ;
        RECT 17.500 14.450 17.600 17.200 ;
        RECT 17.600 14.550 17.700 17.200 ;
        RECT 17.700 14.650 17.800 17.200 ;
        RECT 17.800 14.750 17.900 17.200 ;
        RECT 16.102 10.500 16.202 16.700 ;
        RECT 16.202 10.500 16.302 16.800 ;
        RECT 16.302 10.500 16.402 16.900 ;
        RECT 16.402 10.500 16.502 17.000 ;
        RECT 16.502 10.500 16.602 17.100 ;
        RECT 38.650 17.500 49.550 20.000 ;
        RECT 45.300 10.500 47.800 16.000 ;
        RECT 44.650 13.500 53.750 16.000 ;
        RECT 51.250 13.500 53.750 32.400 ;
        RECT 50.550 25.850 53.050 38.200 ;
  END 
END ADOR16



macro CDRI02
  CLASS  CORE ;
  FOREIGN CDRI02 0.000 0.000 ;
  ORIGIN 0.000 0.000 ;
  SIZE 58.800 BY 48.700 ;
  SYMMETRY X Y  ;
  SITE CORE ;
  PIN Q
    DIRECTION OUTPUT ;
    PORT
      LAYER metal1 ;
        RECT 55.450 21.000 57.950 23.500 ;
    END
  END Q
  PIN QB
    DIRECTION OUTPUT ;
    PORT
      LAYER metal1 ;
        RECT 26.050 21.000 28.550 23.500 ;
    END
  END QB
  PIN VSS
    DIRECTION INOUT ;
    USE GROUND ;
    SHAPE ABUTMENT ;
    PORT
      LAYER metal1 ;
        RECT 6.450 0.000 8.950 13.850 ;
        RECT 0.000 0.000 58.800 9.000 ;
        RECT 49.700 0.000 52.200 14.250 ;
        RECT 39.500 0.000 42.000 14.250 ;
        RECT 28.200 0.000 30.800 16.450 ;
        RECT 16.650 0.000 19.150 13.900 ;
    END
  END VSS
  PIN IN1
    DIRECTION INPUT ;
    PORT
      LAYER metal1 ;
        RECT 0.850 21.000 3.350 23.500 ;
    END
  END IN1
  PIN VDD
    DIRECTION INOUT ;
    USE POWER ;
    SHAPE ABUTMENT ;
    PORT
      LAYER metal1 ;
        RECT 6.800 31.650 9.300 48.700 ;
        RECT 0.000 39.700 58.800 48.700 ;
        RECT 49.350 32.150 51.850 48.700 ;
        RECT 38.550 32.150 41.050 48.700 ;
        RECT 28.000 29.400 30.600 48.700 ;
        RECT 17.600 31.650 20.100 48.700 ;
    END
  END VDD
  OBS 
      
      LAYER metal2 ;
        RECT 23.750 18.700 24.350 24.230 ;
        RECT 23.750 18.700 30.850 19.300 ;
        RECT 30.250 18.700 30.850 24.250 ;
        
        
      LAYER metal1 ;
        RECT 0.850 19.300 22.050 21.800 ;
        RECT 0.850 19.300 3.350 26.150 ;
        RECT 0.850 23.650 22.050 26.150 ;
        RECT 1.350 10.550 3.850 17.800 ;
        RECT 11.550 10.550 14.050 17.800 ;
        RECT 21.750 10.550 24.250 17.800 ;
        RECT 1.350 15.400 26.050 17.800 ;
        RECT 23.650 15.400 26.050 30.250 ;
        RECT 23.650 19.800 53.500 22.400 ;
        RECT 23.650 19.800 28.550 26.700 ;
        RECT 23.650 24.200 53.550 26.700 ;
        RECT 1.350 27.700 26.200 30.100 ;
        RECT 1.350 27.700 14.700 30.150 ;
        RECT 23.650 19.800 26.200 30.250 ;
        RECT 1.350 27.700 3.850 37.650 ;
        RECT 12.200 27.700 14.700 37.650 ;
        RECT 23.000 27.700 25.500 37.650 ;
        RECT 34.400 10.500 36.900 18.200 ;
        RECT 44.600 10.500 47.100 18.200 ;
        RECT 34.400 15.750 47.100 18.200 ;
        RECT 54.800 10.500 57.950 18.200 ;
        RECT 34.400 15.800 57.950 18.200 ;
        RECT 33.100 28.200 57.950 30.600 ;
        RECT 33.100 28.200 35.600 37.650 ;
        RECT 43.950 28.200 46.450 37.650 ;
        RECT 55.450 10.500 57.950 37.650 ;
        RECT 54.750 28.200 57.950 37.650 ;
  END 
END CDRI02










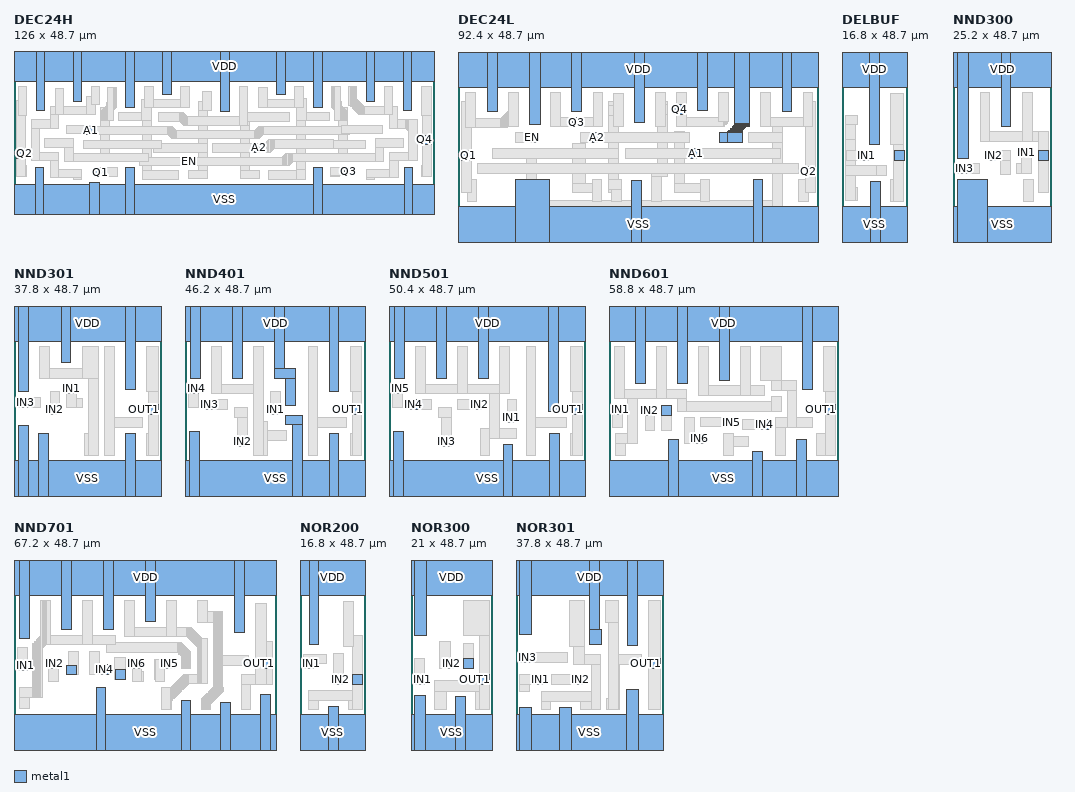
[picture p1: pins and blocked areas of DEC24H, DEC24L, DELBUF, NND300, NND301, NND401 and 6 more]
macro DEC24H
  CLASS  CORE ;
  FOREIGN DEC24H 0.000 0.000 ;
  ORIGIN 0.000 0.000 ;
  SIZE 126.000 BY 48.700 ;
  SYMMETRY X Y  ;
  SITE CORE ;
  PIN A1
    DIRECTION INPUT ;
    PORT
      LAYER metal1 ;
        RECT 21.850 23.850 24.350 26.350 ;
    END
  END A1
  PIN Q1
    DIRECTION OUTPUT ;
    PORT
      LAYER metal1 ;
        RECT 24.550 11.350 27.050 13.850 ;
    END
  END Q1
  PIN EN
    DIRECTION INPUT ;
    PORT
      LAYER metal1 ;
        RECT 51.250 14.600 53.750 17.100 ;
    END
  END EN
  PIN A2
    DIRECTION INPUT ;
    PORT
      LAYER metal1 ;
        RECT 72.250 18.595 74.750 21.095 ;
    END
  END A2
  PIN Q2
    DIRECTION OUTPUT ;
    PORT
      LAYER metal1 ;
        RECT 0.850 16.800 3.350 19.300 ;
    END
  END Q2
  PIN VSS
    DIRECTION INOUT ;
    USE GROUND ;
    SHAPE ABUTMENT ;
    PORT
      LAYER metal1 ;
        RECT 6.350 0.000 8.850 13.850 ;
        RECT 0.000 0.000 126.000 9.000 ;
        RECT 117.150 0.000 119.650 13.850 ;
        RECT 89.950 0.000 92.450 13.850 ;
        RECT 33.550 0.000 36.050 13.850 ;
        RECT 22.600 0.000 25.700 9.550 ;
    END
  END VSS
  PIN Q3
    DIRECTION OUTPUT ;
    PORT
      LAYER metal1 ;
        RECT 99.100 11.500 101.600 14.000 ;
        
    END
  END Q3
  PIN Q4
    DIRECTION OUTPUT ;
    PORT
      LAYER metal1 ;
        RECT 122.650 21.000 125.150 23.500 ;
    END
  END Q4
  PIN VDD
    DIRECTION INOUT ;
    USE POWER ;
    SHAPE ABUTMENT ;
    PORT
      LAYER metal1 ;
        RECT 6.650 31.000 9.150 48.700 ;
        RECT 0.000 39.700 126.000 48.700 ;
        RECT 116.850 31.000 119.350 48.700 ;
        RECT 105.750 33.800 108.250 48.700 ;
        RECT 89.950 32.000 92.450 48.700 ;
        RECT 78.850 35.750 81.350 48.700 ;
        RECT 62.050 30.800 64.650 48.700 ;
        RECT 44.650 35.750 47.150 48.700 ;
        RECT 33.550 32.000 36.050 48.700 ;
        RECT 17.750 33.800 20.250 48.700 ;
    END
  END VDD
  OBS 
      LAYER metal2 ;
        RECT 26.050 18.053 28.550 31.900 ;
        RECT 38.650 10.500 41.150 30.500 ;
        RECT 55.450 10.600 57.950 33.850 ;
        RECT 68.050 10.550 70.550 29.500 ;
        RECT 84.850 10.900 87.350 30.500 ;
        RECT 97.450 18.200 99.950 31.90 ;
        
      LAYER via1 ;
        
        RECT 26.550 28.550 28.050 30.050 ;
        
        RECT 39.150 28.500 40.650 30.000 ;
        RECT 39.150 11.000 40.650 12.500 ;
        
        RECT 55.950 31.700 57.450 33.200 ;
        RECT 55.950 19.100 57.450 20.600 ;
        RECT 55.950 11.100 57.450 12.600 ;
        
        RECT 68.550 27.200 70.050 28.700 ;
        RECT 68.550 11.100 70.050 12.600 ;
        
        RECT 85.350 28.500 86.850 30.000 ;
        RECT 85.350 11.400 86.850 12.900 ;
        
        RECT 97.950 28.700 99.450 30.200 ;
        
        
      LAYER metal1 ;
        RECT 0.850 11.350 3.750 14.700 ;
        RECT 0.850 11.350 3.350 33.950 ;
        RECT 1.250 29.500 3.750 38.150 ;
        RECT 17.850 10.500 20.350 13.450 ;
        RECT 10.800 10.950 20.350 13.450 ;
        RECT 10.800 10.950 13.300 18.500 ;
        RECT 5.100 15.950 13.300 18.500 ;
        RECT 5.100 15.950 7.600 28.300 ;
        RECT 5.100 25.800 13.350 28.300 ;
        RECT 10.850 25.800 13.350 32.300 ;
        RECT 10.850 29.800 24.350 32.300 ;
        RECT 21.850 29.800 24.350 35.200 ;
        RECT 12.350 29.800 14.850 37.700 ;
        RECT 23.150 32.700 25.650 38.200 ;
        RECT 29.750 31.198 29.850 37.950 ;
        RECT 29.850 31.298 29.950 37.950 ;
        RECT 29.950 31.398 30.050 37.950 ;
        RECT 30.050 31.498 30.150 37.950 ;
        RECT 30.150 31.598 30.250 37.950 ;
        RECT 30.250 31.698 30.350 37.950 ;
        RECT 30.350 31.798 30.450 37.950 ;
        RECT 30.450 31.898 30.550 37.950 ;
        RECT 30.550 31.998 30.650 37.950 ;
        RECT 27.650 28.050 27.750 33.399 ;
        RECT 27.750 28.050 27.850 33.499 ;
        RECT 27.850 28.050 27.950 33.599 ;
        RECT 27.950 28.050 28.050 33.699 ;
        RECT 28.050 28.050 28.150 33.799 ;
        RECT 26.050 28.050 26.150 30.750 ;
        RECT 26.150 28.050 26.250 30.850 ;
        RECT 26.250 28.050 26.350 30.950 ;
        RECT 26.350 28.050 26.450 31.050 ;
        RECT 26.450 28.050 26.550 31.150 ;
        RECT 26.550 28.050 26.650 31.250 ;
        RECT 26.650 28.050 26.750 31.350 ;
        RECT 26.750 28.050 26.850 31.450 ;
        RECT 26.850 28.050 26.950 31.550 ;
        RECT 26.950 28.050 27.050 31.650 ;
        RECT 27.050 28.050 27.150 31.750 ;
        RECT 27.150 28.050 27.250 31.850 ;
        RECT 27.250 28.050 27.350 31.950 ;
        RECT 27.350 28.050 27.450 32.050 ;
        RECT 27.450 28.050 27.550 32.150 ;
        RECT 27.550 28.050 27.650 32.250 ;
        RECT 28.150 28.050 29.750 37.950 ;
        RECT 24.550 11.350 30.950 13.850 ;
        RECT 38.650 10.500 49.450 13.000 ;
        RECT 31.350 28.000 41.150 30.500 ;
        RECT 38.300 31.850 52.550 34.250 ;
        RECT 38.300 28.000 41.150 34.500 ;
        RECT 39.250 31.850 41.750 38.100 ;
        RECT 50.050 31.850 52.550 38.150 ;
        RECT 41.900 18.600 57.950 21.100 ;
        RECT 20.700 19.650 44.350 22.150 ;
        RECT 52.450 10.600 57.950 13.100 ;
        RECT 55.450 31.200 59.100 33.700 ;
        RECT 56.600 31.200 59.100 36.800 ;
        RECT 68.050 10.600 73.550 13.100 ;
        RECT 51.900 26.700 70.550 29.200 ;
        RECT 43.350 27.850 49.714 30.350 ;
        RECT 67.500 27.850 82.650 30.350 ;
        RECT 67.500 26.700 70.000 38.150 ;
        RECT 50.850 26.700 50.950 30.150 ;
        RECT 50.950 26.700 51.050 30.050 ;
        RECT 51.050 26.700 51.150 29.950 ;
        RECT 51.150 26.700 51.250 29.850 ;
        RECT 51.250 26.700 51.350 29.750 ;
        RECT 51.350 26.700 51.450 29.650 ;
        RECT 51.450 26.700 51.550 29.550 ;
        RECT 51.550 26.700 51.650 29.450 ;
        RECT 51.650 26.700 51.750 29.350 ;
        RECT 51.750 26.700 51.850 29.250 ;
        RECT 51.850 26.700 51.900 29.200 ;
        RECT 50.750 26.814 50.850 30.250 ;
        RECT 49.714 27.850 49.814 30.350 ;
        RECT 49.814 27.750 49.914 30.350 ;
        RECT 49.914 27.650 50.014 30.350 ;
        RECT 50.014 27.550 50.114 30.350 ;
        RECT 50.114 27.450 50.214 30.350 ;
        RECT 50.214 27.350 50.314 30.350 ;
        RECT 50.314 27.250 50.414 30.350 ;
        RECT 50.414 27.150 50.514 30.350 ;
        RECT 50.514 27.050 50.614 30.350 ;
        RECT 50.614 26.950 50.714 30.350 ;
        RECT 50.714 26.850 50.750 30.350 ;
        RECT 76.350 10.500 87.350 13.000 ;
        RECT 84.850 10.500 87.350 13.400 ;
        RECT 84.850 28.000 94.650 30.500 ;
        RECT 73.450 31.850 87.650 34.250 ;
        RECT 84.850 28.000 87.650 34.550 ;
        RECT 73.450 31.850 75.950 38.050 ;
        RECT 84.250 31.850 86.750 38.150 ;
        RECT 98.350 28.200 98.450 32.200 ;
        RECT 98.450 28.200 98.550 32.100 ;
        RECT 98.550 28.200 98.650 32.000 ;
        RECT 98.650 28.200 98.750 31.900 ;
        RECT 98.750 28.200 98.850 31.800 ;
        RECT 98.850 28.200 98.950 31.700 ;
        RECT 98.950 28.200 99.050 31.600 ;
        RECT 99.050 28.200 99.150 31.500 ;
        RECT 99.150 28.200 99.250 31.400 ;
        RECT 99.250 28.200 99.350 31.300 ;
        RECT 99.350 28.200 99.450 31.200 ;
        RECT 99.450 28.200 99.550 31.100 ;
        RECT 99.550 28.200 99.650 31.000 ;
        RECT 99.650 28.200 99.750 30.900 ;
        RECT 99.750 28.200 99.850 30.800 ;
        RECT 99.850 28.200 99.950 30.700 ;
        RECT 97.850 28.200 97.950 33.949 ;
        RECT 97.950 28.200 98.050 33.849 ;
        RECT 98.050 28.200 98.150 33.749 ;
        RECT 98.150 28.200 98.250 33.649 ;
        RECT 98.250 28.200 98.350 33.549 ;
        RECT 95.350 31.948 95.450 38.100 ;
        RECT 95.450 31.848 95.550 38.100 ;
        RECT 95.550 31.748 95.650 38.100 ;
        RECT 95.650 31.648 95.750 38.100 ;
        RECT 95.750 31.548 95.850 38.100 ;
        RECT 95.850 31.448 95.950 38.100 ;
        RECT 95.950 31.348 96.050 38.100 ;
        RECT 96.050 31.248 96.150 38.100 ;
        RECT 96.150 31.148 96.250 38.100 ;
        RECT 96.250 28.200 97.850 38.100 ;
        RECT 95.050 11.350 97.550 14.000 ;
        RECT 95.050 11.500 101.600 14.000 ;
        RECT 59.650 18.600 75.150 21.100 ;
        RECT 78.100 19.650 105.300 22.150 ;
        RECT 76.300 18.600 77.050 22.250 ;
        RECT 78.100 19.650 95.750 22.250 ;
        RECT 77.050 18.700 77.150 22.250 ;
        RECT 77.150 18.800 77.250 22.250 ;
        RECT 77.250 18.900 77.350 22.250 ;
        RECT 77.350 19.000 77.450 22.250 ;
        RECT 77.450 19.100 77.550 22.250 ;
        RECT 77.550 19.200 77.650 22.250 ;
        RECT 77.650 19.300 77.750 22.250 ;
        RECT 77.750 19.400 77.850 22.250 ;
        RECT 77.850 19.500 77.950 22.250 ;
        RECT 77.950 19.600 78.050 22.250 ;
        RECT 78.050 19.650 78.100 22.250 ;
        RECT 75.150 18.600 75.250 21.100 ;
        RECT 75.250 18.600 75.350 21.200 ;
        RECT 75.350 18.600 75.450 21.300 ;
        RECT 75.450 18.600 75.550 21.400 ;
        RECT 75.550 18.600 75.650 21.500 ;
        RECT 75.650 18.600 75.750 21.600 ;
        RECT 75.750 18.600 75.850 21.700 ;
        RECT 75.850 18.600 75.950 21.800 ;
        RECT 75.950 18.600 76.050 21.900 ;
        RECT 76.050 18.600 76.150 22.000 ;
        RECT 76.150 18.600 76.250 22.100 ;
        RECT 76.250 18.600 76.300 22.200 ;
        RECT 48.650 22.600 72.200 25.100 ;
        RECT 20.900 23.850 46.164 26.350 ;
        RECT 73.450 22.600 73.550 26.350 ;
        RECT 74.800 23.850 100.750 26.350 ;
        RECT 15.600 24.050 23.500 26.550 ;
        RECT 98.150 24.050 110.400 26.550 ;
        RECT 73.550 22.700 73.650 26.350 ;
        RECT 73.650 22.800 73.750 26.350 ;
        RECT 73.750 22.900 73.850 26.350 ;
        RECT 73.850 23.000 73.950 26.350 ;
        RECT 73.950 23.100 74.050 26.350 ;
        RECT 74.050 23.200 74.150 26.350 ;
        RECT 74.150 23.300 74.250 26.350 ;
        RECT 74.250 23.400 74.350 26.350 ;
        RECT 74.350 23.500 74.450 26.350 ;
        RECT 74.450 23.600 74.550 26.350 ;
        RECT 74.550 23.700 74.650 26.350 ;
        RECT 74.650 23.800 74.750 26.350 ;
        RECT 74.750 23.850 74.800 26.350 ;
        RECT 72.200 22.600 72.300 25.100 ;
        RECT 72.300 22.600 72.400 25.200 ;
        RECT 72.400 22.600 72.500 25.300 ;
        RECT 72.500 22.600 72.600 25.400 ;
        RECT 72.600 22.600 72.700 25.500 ;
        RECT 72.700 22.600 72.800 25.600 ;
        RECT 72.800 22.600 72.900 25.700 ;
        RECT 72.900 22.600 73.000 25.800 ;
        RECT 73.000 22.600 73.100 25.900 ;
        RECT 73.100 22.600 73.200 26.000 ;
        RECT 73.200 22.600 73.300 26.100 ;
        RECT 73.300 22.600 73.400 26.200 ;
        RECT 73.400 22.600 73.450 26.300 ;
        RECT 47.414 22.600 47.514 26.236 ;
        RECT 47.514 22.600 47.614 26.136 ;
        RECT 47.614 22.600 47.714 26.036 ;
        RECT 47.714 22.600 47.814 25.936 ;
        RECT 47.814 22.600 47.914 25.836 ;
        RECT 47.914 22.600 48.014 25.736 ;
        RECT 48.014 22.600 48.114 25.636 ;
        RECT 48.114 22.600 48.214 25.536 ;
        RECT 48.214 22.600 48.314 25.436 ;
        RECT 48.314 22.600 48.414 25.336 ;
        RECT 48.414 22.600 48.514 25.236 ;
        RECT 48.514 22.600 48.614 25.136 ;
        RECT 48.614 22.600 48.650 25.100 ;
        RECT 47.400 22.614 47.414 26.336 ;
        RECT 46.164 23.850 46.264 26.350 ;
        RECT 46.264 23.750 46.364 26.350 ;
        RECT 46.364 23.650 46.464 26.350 ;
        RECT 46.464 23.550 46.564 26.350 ;
        RECT 46.564 23.450 46.664 26.350 ;
        RECT 46.664 23.350 46.764 26.350 ;
        RECT 46.764 23.250 46.864 26.350 ;
        RECT 46.864 23.150 46.964 26.350 ;
        RECT 46.964 23.050 47.064 26.350 ;
        RECT 47.064 22.950 47.164 26.350 ;
        RECT 47.164 22.850 47.264 26.350 ;
        RECT 47.264 22.750 47.364 26.350 ;
        RECT 47.364 22.650 47.400 26.350 ;
        RECT 37.650 14.600 80.551 17.100 ;
        RECT 15.200 15.650 40.300 18.150 ;
        RECT 81.601 14.600 82.499 18.150 ;
        RECT 83.450 15.650 110.800 18.150 ;
        RECT 108.300 15.650 110.800 22.550 ;
        RECT 15.200 15.650 17.700 22.550 ;
        RECT 9.250 20.050 17.700 22.550 ;
        RECT 108.300 20.050 116.750 22.550 ;
        RECT 82.499 14.700 82.599 18.150 ;
        RECT 82.599 14.800 82.699 18.150 ;
        RECT 82.699 14.900 82.799 18.150 ;
        RECT 82.799 15.000 82.899 18.150 ;
        RECT 82.899 15.100 82.999 18.150 ;
        RECT 82.999 15.200 83.099 18.150 ;
        RECT 83.099 15.300 83.199 18.150 ;
        RECT 83.199 15.400 83.299 18.150 ;
        RECT 83.299 15.500 83.399 18.150 ;
        RECT 83.399 15.551 83.450 18.150 ;
        RECT 80.551 14.600 80.651 17.100 ;
        RECT 80.651 14.600 80.751 17.200 ;
        RECT 80.751 14.600 80.851 17.300 ;
        RECT 80.851 14.600 80.951 17.400 ;
        RECT 80.951 14.600 81.051 17.500 ;
        RECT 81.051 14.600 81.151 17.600 ;
        RECT 81.151 14.600 81.251 17.700 ;
        RECT 81.251 14.600 81.351 17.800 ;
        RECT 81.351 14.600 81.451 17.900 ;
        RECT 81.451 14.600 81.551 18.000 ;
        RECT 81.551 14.600 81.601 18.100 ;
        RECT 105.650 10.500 108.150 13.450 ;
        RECT 105.650 10.950 115.200 13.450 ;
        RECT 112.700 10.950 115.200 18.500 ;
        RECT 112.700 15.950 120.900 18.500 ;
        RECT 112.650 25.800 117.449 28.300 ;
        RECT 118.400 15.950 120.900 28.300 ;
        RECT 105.000 29.800 115.150 32.300 ;
        RECT 112.650 25.800 115.150 32.350 ;
        RECT 100.350 32.600 100.800 38.200 ;
        RECT 111.150 29.800 113.650 38.200 ;
        RECT 117.449 25.800 117.549 28.300 ;
        RECT 117.549 25.700 117.649 28.300 ;
        RECT 117.649 25.600 117.749 28.300 ;
        RECT 117.749 25.500 117.849 28.300 ;
        RECT 117.849 25.400 117.949 28.300 ;
        RECT 117.949 25.300 118.049 28.300 ;
        RECT 118.049 25.200 118.149 28.300 ;
        RECT 118.149 25.100 118.249 28.300 ;
        RECT 118.249 25.000 118.349 28.300 ;
        RECT 118.349 24.900 118.400 28.300 ;
        RECT 103.600 29.800 103.700 33.600 ;
        RECT 103.700 29.800 103.800 33.500 ;
        RECT 103.800 29.800 103.900 33.400 ;
        RECT 103.900 29.800 104.000 33.300 ;
        RECT 104.000 29.800 104.100 33.200 ;
        RECT 104.100 29.800 104.200 33.100 ;
        RECT 104.200 29.800 104.300 33.000 ;
        RECT 104.300 29.800 104.400 32.900 ;
        RECT 104.400 29.800 104.500 32.800 ;
        RECT 104.500 29.800 104.600 32.700 ;
        RECT 104.600 29.800 104.700 32.600 ;
        RECT 104.700 29.800 104.800 32.500 ;
        RECT 104.800 29.800 104.900 32.400 ;
        RECT 104.900 29.800 105.000 32.300 ;
        RECT 102.850 30.550 102.950 34.350 ;
        RECT 102.950 30.450 103.050 34.250 ;
        RECT 103.050 30.350 103.150 34.150 ;
        RECT 103.150 30.250 103.250 34.050 ;
        RECT 103.250 30.150 103.350 33.950 ;
        RECT 103.350 30.050 103.450 33.850 ;
        RECT 103.450 29.950 103.550 33.750 ;
        RECT 103.550 29.850 103.600 33.700 ;
        RECT 100.800 32.600 100.900 38.200 ;
        RECT 100.900 32.500 101.000 38.200 ;
        RECT 101.000 32.400 101.100 38.200 ;
        RECT 101.100 32.300 101.200 38.200 ;
        RECT 101.200 32.200 101.300 38.200 ;
        RECT 101.300 32.100 101.400 38.200 ;
        RECT 101.400 32.000 101.500 38.200 ;
        RECT 101.500 31.900 101.600 38.200 ;
        RECT 101.600 31.800 101.700 38.200 ;
        RECT 101.700 31.700 101.800 38.200 ;
        RECT 101.800 31.600 101.900 38.200 ;
        RECT 101.900 31.500 102.000 38.200 ;
        RECT 102.000 31.400 102.100 38.200 ;
        RECT 102.100 31.300 102.200 38.200 ;
        RECT 102.200 31.200 102.300 38.200 ;
        RECT 102.300 31.100 102.400 38.200 ;
        RECT 102.400 31.000 102.500 38.200 ;
        RECT 102.500 30.900 102.600 38.200 ;
        RECT 102.600 30.800 102.700 38.200 ;
        RECT 102.700 30.700 102.800 38.200 ;
        RECT 102.800 30.600 102.850 38.200 ;
        RECT 122.250 11.350 125.150 14.700 ;
        RECT 122.650 11.350 125.150 38.150 ;
        RECT 122.250 29.550 125.150 38.150 ;
  END 
END DEC24H








macro DEC24L
  CLASS  CORE ;
  FOREIGN DEC24L 0.000 0.000 ;
  ORIGIN 0.000 0.000 ;
  SIZE 92.400 BY 48.700 ;
  SYMMETRY X Y  ;
  SITE CORE ;
  PIN EN
    DIRECTION INPUT ;
    PORT
      LAYER metal1 ;
        RECT 17.650 25.550 20.150 28.050 ;
    END
  END EN
  
  PIN A1
    DIRECTION INPUT ;
    PORT
      LAYER metal1 ;
        RECT 59.650 21.500 62.150 24.000 ;
    END
  END A1
  PIN Q1
    DIRECTION OUTPUT ;
    PORT
      LAYER metal1 ;
        RECT 0.850 21.000 3.350 23.500 ;
    END
  END Q1
  PIN A2
    DIRECTION INPUT ;
    PORT
      LAYER metal1 ;
        RECT 34.450 25.500 36.950 28.000 ;
    END
  END A2
  PIN Q2
    DIRECTION OUTPUT ;
    PORT
      LAYER metal1 ;
        RECT 89.050 16.800 91.550 19.300 ;
    END
  END Q2
  PIN VSS
    DIRECTION INOUT ;
    USE GROUND ;
    SHAPE ABUTMENT ;
    PORT
      LAYER metal1 ;
        RECT 14.850 0.000 23.500 16.000 ;
        RECT 0.000 0.000 92.400 9.000 ;
        RECT 75.650 0.000 78.150 16.000 ;
        RECT 44.450 0.000 46.950 15.700 ;
    END
  END VSS
  PIN Q3
    DIRECTION OUTPUT ;
    PORT
      LAYER metal1 ;
        RECT 29.250 29.500 31.750 32.000 ;
        
    END
  END Q3
  PIN Q4
    DIRECTION OUTPUT ;
    PORT
      LAYER metal1 ;
        RECT 55.450 32.700 57.950 35.200 ;
    END
  END Q4
  PIN VDD
    DIRECTION INOUT ;
    USE POWER ;
    SHAPE ABUTMENT ;
    PORT
      LAYER metal1 ;
        RECT 0.000 39.700 92.400 48.700 ;
        RECT 83.050 33.400 85.550 48.700 ;
        RECT 70.950 29.500 74.750 48.700 ;
        RECT 70.400 29.450 73.700 29.500 ;
        RECT 70.400 29.350 73.600 29.500 ;
        RECT 70.300 29.250 73.500 29.350 ;
        RECT 70.250 29.150 73.400 29.300 ;
        RECT 70.150 29.050 73.300 29.200 ;
        RECT 70.050 28.950 73.200 29.100 ;
        RECT 69.950 28.850 73.100 29.000 ;
        RECT 69.850 28.750 73.000 28.900 ;
        RECT 69.750 25.500 72.900 28.800 ;
        RECT 70.862 29.500 74.750 30.283 ;
        RECT 70.762 29.500 74.750 30.042 ;
        RECT 70.700 29.500 74.750 29.949 ;
        RECT 70.600 29.500 74.750 29.799 ;
        RECT 70.500 29.500 74.750 29.650 ;
        RECT 69.650 25.500 72.900 28.700 ;
        RECT 69.550 25.500 72.900 28.600 ;
        RECT 69.450 25.500 72.900 28.500 ;
        RECT 69.350 25.500 72.900 28.400 ;
        RECT 69.250 25.500 72.900 28.300 ;
        RECT 69.150 25.500 72.900 28.200 ;
        RECT 69.050 25.500 72.900 28.100 ;
        RECT 67.150 25.500 72.900 28.000 ;
        RECT 61.450 33.600 63.950 48.700 ;
        RECT 45.250 30.650 47.750 48.700 ;
        RECT 29.150 33.500 31.650 48.700 ;
        RECT 18.350 30.100 21.150 48.700 ;
        RECT 7.550 33.400 10.050 48.700 ;
    END
  END VDD
  OBS 
      LAYER metal2 ;
      
        RECT 17.650 8.098 20.150 21.349 ;
        RECT 17.650 8.098 83.150 10.598 ;
        RECT 29.250 12.600 32.750 25.300 ;
        RECT 80.650 8.098 83.150 31.900 ;
        RECT 38.650 32.500 41.300 35.000 ;
        RECT 38.650 12.600 41.150 36.100 ;
        RECT 51.250 16.800 53.750 36.100 ;
        RECT 55.450 12.600 57.950 28.399 ;
        
      LAYER via1 ;
        
        
        
        RECT 29.750 13.100 31.250 14.600 ;
        
        RECT 39.150 22.000 40.650 23.500 ;
        RECT 39.150 14.000 40.650 15.500 ;
        RECT 39.300 33.000 40.800 34.500 ;
        RECT 51.750 33.200 53.250 34.700 ;
        RECT 51.750 17.300 53.250 18.800 ;
       
        RECT 55.950 13.100 57.450 14.600 ;
        
        RECT 81.150 26.000 82.650 27.500 ;
      
      LAYER metal1 ;
        RECT 2.350 10.500 4.850 16.000 ;
        RECT 0.850 29.300 11.000 31.700 ;
        RECT 12.947 29.700 15.400 33.600 ;
        RECT 0.850 12.650 3.350 36.100 ;
        RECT 2.050 29.300 4.550 38.200 ;
        RECT 12.950 29.700 15.400 38.200 ;
        RECT 15.400 29.750 15.450 38.200 ;
        RECT 12.900 29.700 12.947 33.600 ;
        RECT 12.547 29.400 12.647 33.247 ;
        RECT 12.647 29.500 12.747 33.347 ;
        RECT 12.747 29.600 12.847 33.447 ;
        RECT 12.847 29.653 12.900 33.547 ;
        RECT 11.000 29.300 11.100 31.700 ;
        RECT 11.100 29.300 11.200 31.800 ;
        RECT 11.200 29.300 11.300 31.900 ;
        RECT 11.300 29.300 11.400 32.000 ;
        RECT 11.400 29.300 11.500 32.100 ;
        RECT 11.500 29.300 11.600 32.200 ;
        RECT 11.600 29.300 11.700 32.300 ;
        RECT 11.700 29.300 11.800 32.400 ;
        RECT 11.800 29.300 11.900 32.500 ;
        RECT 11.900 29.300 12.000 32.600 ;
        RECT 12.000 29.300 12.100 32.700 ;
        RECT 12.100 29.300 12.200 32.800 ;
        RECT 12.200 29.300 12.300 32.900 ;
        RECT 12.300 29.300 12.400 33.000 ;
        RECT 12.400 29.300 12.500 33.100 ;
        RECT 12.500 29.300 12.547 33.200 ;
        RECT 14.650 25.550 20.150 28.050 ;
        RECT 29.250 12.600 36.850 15.100 ;
        RECT 34.350 10.500 36.850 16.000 ;
        RECT 29.250 29.500 31.750 32.000 ;
        RECT 23.750 29.600 37.150 32.000 ;
        RECT 23.750 29.600 26.250 38.200 ;
        RECT 34.650 29.600 37.150 38.200 ;
        RECT 8.850 21.500 41.150 24.000 ;
        RECT 39.350 10.500 41.850 16.000 ;
        RECT 38.650 13.500 41.850 16.000 ;
        RECT 38.650 32.500 42.300 35.000 ;
        RECT 39.800 29.500 42.300 38.100 ;
        RECT 50.700 32.700 53.750 35.200 ;
        RECT 50.700 29.600 53.200 38.200 ;
        RECT 31.450 25.500 59.300 28.000 ;
        RECT 55.450 12.600 64.550 15.100 ;
        RECT 62.050 10.500 64.550 16.000 ;
        RECT 55.950 29.700 68.200 32.000 ;
        RECT 55.950 29.800 68.300 32.000 ;
        RECT 55.950 29.900 68.400 32.000 ;
        RECT 55.950 30.000 68.500 32.000 ;
        RECT 55.950 30.100 68.600 32.000 ;
        RECT 55.950 30.200 68.700 32.000 ;
        RECT 55.950 30.300 68.800 32.000 ;
        RECT 55.950 30.400 68.900 32.000 ;
        RECT 55.950 30.500 69.000 32.000 ;
        RECT 55.950 30.600 69.100 32.000 ;
        RECT 55.950 30.700 69.200 32.000 ;
        RECT 55.950 30.800 69.300 32.000 ;
        RECT 55.950 29.600 68.100 32.000 ;
        RECT 55.450 32.600 58.450 35.200 ;
        RECT 55.950 29.600 58.450 38.200 ;
        RECT 66.850 30.850 69.350 38.200 ;
        RECT 42.850 21.500 82.700 24.000 ;
        RECT 74.400 25.500 83.150 28.000 ;
        RECT 49.550 10.500 52.050 20.000 ;
        RECT 49.550 16.800 53.750 20.000 ;
        RECT 4.950 17.500 87.300 20.000 ;
        RECT 87.300 10.500 89.800 16.000 ;
        RECT 77.650 29.500 91.550 31.900 ;
        RECT 89.050 12.600 91.550 36.050 ;
        RECT 77.650 29.500 80.150 38.200 ;
        RECT 88.450 29.500 90.950 38.200 ;
  END 
END DEC24L















macro DELBUF
  CLASS  CORE ;
  FOREIGN DELBUF 0.000 0.000 ;
  ORIGIN 0.000 0.000 ;
  SIZE 16.800 BY 48.700 ;
  SYMMETRY X Y  ;
  SITE CORE ;
  PIN OUT1
    DIRECTION OUTPUT ;
    PORT
      LAYER metal1 ;
        RECT 13.450 21.000 15.950 23.500 ;
    END
  END OUT1
  PIN VSS
    DIRECTION INOUT ;
    USE GROUND ;
    SHAPE ABUTMENT ;
    PORT
      LAYER metal1 ;
        RECT 7.250 0.000 9.800 15.600 ;
        RECT 0.000 0.000 16.800 9.000 ;
    END
  END VSS
  PIN IN1
    DIRECTION INPUT ;
    PORT
      LAYER metal1 ;
        RECT 5.050 21.000 7.550 23.500 ;
    END
  END IN1
  PIN VDD
    DIRECTION INOUT ;
    USE POWER ;
    SHAPE ABUTMENT ;
    PORT
      LAYER metal1 ;
        RECT 7.050 25.000 9.600 48.700 ;
        RECT 0.000 39.700 16.800 48.700 ;
    END
  END VDD
  OBS 
      LAYER metal2 ;
        RECT 0.850 15.150 3.350 28.900 ;
      LAYER via1 ;
      
        RECT 1.350 26.900 2.850 28.400 ;
        RECT 1.350 15.650 2.850 17.150 ;
      LAYER metal1 ;
        RECT 0.850 26.400 3.350 32.550 ;
        RECT 0.850 30.050 3.900 32.550 ;
        RECT 1.050 21.000 7.550 23.500 ;
        RECT 0.850 10.650 4.100 13.900 ;
        RECT 0.850 10.650 3.350 19.500 ;
        RECT 0.850 17.100 11.350 19.500 ;
        RECT 8.850 17.100 11.350 19.700 ;
        RECT 12.400 10.500 15.700 16.000 ;
        RECT 13.100 21.000 15.950 23.500 ;
        RECT 13.100 10.500 15.700 38.150 ;
        RECT 12.450 24.900 15.700 38.150 ;
  END 
END DELBUF






macro NND300
  CLASS  CORE ;
  FOREIGN NND300 0.000 0.000 ;
  ORIGIN 0.000 0.000 ;
  SIZE 25.200 BY 48.700 ;
  SYMMETRY X Y  ;
  SITE CORE ;
  PIN OUT1
    DIRECTION OUTPUT ;
    PORT
      LAYER metal1 ;
        RECT 21.850 21.000 24.350 23.500 ;
    END
  END OUT1
  PIN VSS
    DIRECTION INOUT ;
    USE GROUND ;
    SHAPE ABUTMENT ;
    PORT
      LAYER metal1 ;
        RECT 1.250 0.000 8.750 16.000 ;
        RECT 0.000 0.000 25.200 9.000 ;
    END
  END VSS
  PIN IN1
    DIRECTION INPUT ;
    PORT
      LAYER metal1 ;
        RECT 17.650 21.800 20.150 24.300 ;
    END
  END IN1
  PIN IN2
    DIRECTION INPUT ;
    PORT
      LAYER metal1 ;
        RECT 9.250 21.000 11.750 23.500 ;
    END
  END IN2
  PIN IN3
    DIRECTION INPUT ;
    PORT
      LAYER metal1 ;
        RECT 0.850 17.500 3.350 20.000 ;
    END
  END IN3
  PIN VDD
    DIRECTION INOUT ;
    USE POWER ;
    SHAPE ABUTMENT ;
    PORT
      LAYER metal1 ;
        RECT 1.250 21.500 4.050 48.700 ;
        RECT 0.000 39.700 25.200 48.700 ;
        RECT 12.350 29.700 14.850 48.700 ;
    END
  END VDD
  OBS 
      
       
      LAYER metal1 ;
        RECT 0.850 17.500 6.750 20.000 ;
        RECT 12.150 17.200 14.650 23.500 ;
        RECT 9.250 21.000 14.650 23.500 ;
        RECT 16.350 17.600 20.150 20.100 ;
        RECT 17.650 17.600 20.150 24.300 ;
        RECT 18.050 10.500 20.550 16.000 ;
        
        RECT 6.950 25.800 24.350 28.200 ;
        RECT 21.850 12.600 24.350 28.300 ;
        
        RECT 6.950 25.800 9.450 38.200 ;
        RECT 17.750 25.800 20.250 38.200 ;
  END 
END NND300




macro NND301
  CLASS  CORE ;
  FOREIGN NND301 0.000 0.000 ;
  ORIGIN 0.000 0.000 ;
  SIZE 37.800 BY 48.700 ;
  SYMMETRY X Y  ;
  SITE CORE ;
  PIN OUT1
    DIRECTION OUTPUT ;
    PORT
      LAYER metal1 ;
        RECT 34.450 21.000 36.950 23.500 ;
    END
  END OUT1
  PIN VSS
    DIRECTION INOUT ;
    USE GROUND ;
    SHAPE ABUTMENT ;
    PORT
      LAYER metal1 ;
        RECT 1.250 0.000 3.750 18.050 ;
        RECT 0.000 0.000 37.800 9.000 ;
        RECT 28.550 0.000 31.050 16.000 ;
        RECT 6.250 0.000 8.750 16.000 ;
    END
  END VSS
  PIN IN1
    DIRECTION INPUT ;
    PORT
      LAYER metal1 ;
        RECT 13.450 26.200 15.950 28.700 ;
    END
  END IN1
  PIN IN2
    DIRECTION INPUT ;
    PORT
      LAYER metal1 ;
        RECT 9.250 21.000 11.750 23.500 ;
    END
  END IN2
  PIN IN3
    DIRECTION INPUT ;
    PORT
      LAYER metal1 ;
        RECT 0.850 22.700 3.350 25.200 ;
    END
  END IN3
  PIN VDD
    DIRECTION INOUT ;
    USE POWER ;
    SHAPE ABUTMENT ;
    PORT
      LAYER metal1 ;
        RECT 1.250 26.700 3.750 48.700 ;
        RECT 0.000 39.700 37.800 48.700 ;
        RECT 28.550 27.200 31.050 48.700 ;
        RECT 12.050 34.200 14.550 48.700 ;
    END
  END VDD
  OBS 
      
      LAYER metal1 ;
        RECT 0.850 22.700 6.750 25.200 ;
        RECT 9.250 21.000 11.750 26.900 ;
        RECT 13.450 22.600 17.650 25.100 ;
        RECT 13.450 22.600 15.950 28.700 ;
        RECT 18.050 10.500 21.650 16.000 ;
        RECT 6.650 30.200 21.650 32.700 ;
        RECT 6.650 30.200 9.150 38.200 ;
        RECT 19.150 10.500 21.650 38.200 ;
        RECT 17.450 30.200 21.650 38.200 ;
        RECT 23.150 17.500 32.950 20.000 ;
        RECT 23.150 10.500 25.650 38.200 ;
        RECT 33.950 10.500 36.950 16.000 ;
        RECT 34.450 10.500 36.950 38.200 ;
        RECT 33.950 26.700 36.950 38.200 ;
  END 
END NND301






macro NND401
  CLASS  CORE ;
  FOREIGN NND401 0.000 0.000 ;
  ORIGIN 0.000 0.000 ;
  SIZE 46.200 BY 48.700 ;
  SYMMETRY X Y  ;
  SITE CORE ;
  PIN OUT1
    DIRECTION OUTPUT ;
    PORT
      LAYER metal1 ;
        RECT 42.850 21.000 45.350 23.500 ;
    END
  END OUT1
  PIN VSS
    DIRECTION INOUT ;
    USE GROUND ;
    SHAPE ABUTMENT ;
    PORT
      LAYER metal1 ;
        RECT 0.000 0.000 46.200 9.000 ;
        RECT 36.950 0.000 39.450 16.000 ;
        RECT 25.850 18.200 30.050 20.700 ;
        RECT 27.550 0.000 30.050 20.700 ;
        RECT 1.250 0.000 3.750 16.500 ;
    END
  END VSS
  PIN IN1
    DIRECTION INPUT ;
    PORT
      LAYER metal1 ;
        RECT 21.850 21.000 24.350 23.500 ;
    END
  END IN1
  PIN IN2
    DIRECTION INPUT ;
    PORT
      LAYER metal1 ;
        RECT 13.450 12.600 15.950 15.100 ;
    END
  END IN2
  PIN IN3
    DIRECTION INPUT ;
    PORT
      LAYER metal1 ;
        RECT 5.050 22.200 7.550 24.700 ;
    END
  END IN3
  PIN IN4
    DIRECTION INPUT ;
    PORT
      LAYER metal1 ;
        RECT 0.850 26.200 3.350 28.700 ;
    END
  END IN4
  PIN VDD
    DIRECTION INOUT ;
    USE POWER ;
    SHAPE ABUTMENT ;
    PORT
      LAYER metal1 ;
        RECT 0.000 39.700 46.200 48.700 ;
        RECT 36.950 26.700 39.450 48.700 ;
        RECT 23.050 30.200 28.350 32.700 ;
        RECT 25.850 23.200 28.350 32.700 ;
        RECT 23.050 30.200 25.550 48.700 ;
        RECT 12.250 30.200 14.750 48.700 ;
        RECT 1.450 30.200 3.950 48.700 ;
    END
  END VDD
  OBS 
    
      LAYER metal1 ;
        RECT 0.850 22.800 3.350 28.700 ;
        RECT 5.050 22.200 10.950 24.700 ;
        RECT 13.450 12.600 15.950 22.700 ;
        RECT 12.650 20.200 15.950 22.700 ;
        RECT 21.850 21.000 24.350 26.900 ;
        RECT 17.650 14.200 26.050 16.700 ;
        RECT 17.650 10.500 21.050 19.000 ;
        RECT 6.850 26.200 20.150 28.700 ;
        RECT 6.850 26.200 9.350 38.200 ;
        RECT 17.650 10.500 20.150 38.200 ;
        RECT 31.550 17.500 41.350 20.000 ;
        RECT 31.550 10.500 34.050 38.200 ;
        RECT 42.350 10.500 45.350 16.000 ;
        RECT 42.850 10.500 45.350 38.200 ;
        RECT 42.350 26.700 45.350 38.200 ;
  END 
END NND401




macro NND501
  CLASS  CORE ;
  FOREIGN NND501 0.000 0.000 ;
  ORIGIN 0.000 0.000 ;
  SIZE 50.400 BY 48.700 ;
  SYMMETRY X Y  ;
  SITE CORE ;
  PIN OUT1
    DIRECTION OUTPUT ;
    PORT
      LAYER metal1 ;
        RECT 47.050 21.000 49.550 23.500 ;
    END
  END OUT1
  PIN VSS
    DIRECTION INOUT ;
    USE GROUND ;
    SHAPE ABUTMENT ;
    PORT
      LAYER metal1 ;
        RECT 1.250 0.000 3.750 16.450 ;
        RECT 0.000 0.000 50.400 9.000 ;
        RECT 41.150 0.000 43.650 16.000 ;
        RECT 29.250 0.000 31.750 13.300 ;
    END
  END VSS
  PIN IN1
    DIRECTION INPUT ;
    PORT
      LAYER metal1 ;
        RECT 30.250 18.800 32.750 21.300 ;
    END
  END IN1
  PIN IN2
    DIRECTION INPUT ;
    PORT
      LAYER metal1 ;
        RECT 21.850 22.200 24.350 24.700 ;
    END
  END IN2
  PIN IN3
    DIRECTION INPUT ;
    PORT
      LAYER metal1 ;
        RECT 13.450 12.600 15.950 15.100 ;
    END
  END IN3
  PIN IN4
    DIRECTION INPUT ;
    PORT
      LAYER metal1 ;
        RECT 5.050 22.200 7.550 24.700 ;
    END
  END IN4
  PIN IN5
    DIRECTION INPUT ;
    PORT
      LAYER metal1 ;
        RECT 0.850 26.200 3.350 28.700 ;
    END
  END IN5
  PIN VDD
    DIRECTION INOUT ;
    USE POWER ;
    SHAPE ABUTMENT ;
    PORT
      LAYER metal1 ;
        RECT 1.450 30.200 3.950 48.700 ;
        RECT 0.000 39.700 50.400 48.700 ;
        RECT 40.850 21.700 43.350 48.700 ;
        RECT 23.050 30.200 25.550 48.700 ;
        RECT 12.250 30.200 14.750 48.700 ;
    END
  END VDD
  OBS 
    
      LAYER metal1 ;
        RECT 0.850 22.800 3.350 28.700 ;
        RECT 5.050 22.200 10.950 24.700 ;
        RECT 13.450 12.600 15.950 22.700 ;
        RECT 12.650 20.200 15.950 22.700 ;
        RECT 17.450 22.200 24.350 24.700 ;
        RECT 30.250 18.800 32.750 24.700 ;
        RECT 23.350 14.800 32.750 17.300 ;
        RECT 23.350 10.500 25.850 17.350 ;
        RECT 25.850 14.800 28.350 28.700 ;
        RECT 6.850 26.200 30.950 28.700 ;
        RECT 6.850 26.200 9.350 38.200 ;
        RECT 17.650 26.200 20.150 38.200 ;
        RECT 28.450 26.200 30.950 38.200 ;
        RECT 35.150 17.500 45.550 20.000 ;
        RECT 35.150 10.500 37.650 38.200 ;
        RECT 46.550 10.500 49.550 16.000 ;
        RECT 47.050 10.500 49.550 38.200 ;
        RECT 46.550 26.700 49.550 38.200 ;
  END 
END NND501






macro NND601
  CLASS  CORE ;
  FOREIGN NND601 0.000 0.000 ;
  ORIGIN 0.000 0.000 ;
  SIZE 58.800 BY 48.700 ;
  SYMMETRY X Y  ;
  SITE CORE ;
  PIN OUT1
    DIRECTION OUTPUT ;
    PORT
      LAYER metal1 ;
        RECT 55.450 21.000 57.950 23.500 ;
    END
  END OUT1
  PIN VSS
    DIRECTION INOUT ;
    USE GROUND ;
    SHAPE ABUTMENT ;
    PORT
      LAYER metal1 ;
        RECT 15.350 0.000 17.850 14.500 ;
        RECT 0.000 0.000 58.800 9.000 ;
        RECT 48.050 0.000 50.550 14.500 ;
        RECT 36.850 0.000 39.350 11.500 ;
    END
  END VSS
  PIN IN1
    DIRECTION INPUT ;
    PORT
      LAYER metal1 ;
        RECT 0.850 20.900 3.350 23.400 ;
    END
  END IN1
  PIN IN2
    DIRECTION INPUT ;
    PORT
      LAYER metal1 ;
        RECT 9.250 20.600 11.750 23.100 ;
    END
  END IN2
  PIN IN3
    DIRECTION INPUT ;
    PORT
      LAYER metal1 ;
        RECT 13.450 20.600 15.950 23.100 ;
    END
  END IN3
  PIN IN4
    DIRECTION INPUT ;
    PORT
      LAYER metal1 ;
        RECT 38.650 17.000 41.150 19.500 ;
    END
  END IN4
  PIN IN5
    DIRECTION INPUT ;
    PORT
      LAYER metal1 ;
        RECT 30.250 17.700 32.750 20.200 ;
    END
  END IN5
  PIN IN6
    DIRECTION INPUT ;
    PORT
      LAYER metal1 ;
        RECT 21.850 13.500 24.350 16.000 ;
    END
  END IN6
  PIN VDD
    DIRECTION INOUT ;
    USE POWER ;
    SHAPE ABUTMENT ;
    PORT
      LAYER metal1 ;
        RECT 6.750 28.800 9.250 48.700 ;
        RECT 0.000 39.700 58.800 48.700 ;
        RECT 49.550 27.200 52.050 48.700 ;
        RECT 28.350 29.700 30.850 48.700 ;
        RECT 17.550 28.800 20.050 48.700 ;
    END
  END VDD
  OBS 
     
      LAYER metal1 ;
        RECT 0.850 17.500 3.350 23.400 ;
        RECT 9.250 16.800 11.750 23.100 ;
        RECT 13.450 16.800 15.950 23.100 ;
        RECT 19.350 13.500 24.350 16.000 ;
        RECT 19.350 13.500 21.850 20.200 ;
        RECT 23.550 17.700 32.750 20.200 ;
        RECT 29.450 12.800 35.650 15.300 ;
        RECT 29.450 10.500 31.950 16.000 ;
        RECT 22.950 25.700 39.950 28.200 ;
        RECT 22.950 25.700 25.450 38.200 ;
        RECT 33.750 25.700 36.250 38.200 ;
        RECT 34.250 17.000 41.150 19.500 ;
        RECT 1.650 10.500 4.150 16.000 ;
        RECT 1.650 13.500 7.250 16.000 ;
        RECT 17.450 21.700 44.150 24.200 ;
        RECT 4.850 13.500 7.250 27.300 ;
        RECT 41.650 21.700 44.150 25.600 ;
        RECT 17.450 21.700 19.850 27.300 ;
        RECT 1.350 24.900 19.850 27.300 ;
        RECT 1.350 24.900 3.850 38.200 ;
        RECT 12.150 24.900 14.650 38.200 ;
        RECT 42.650 10.500 45.150 20.000 ;
        RECT 42.650 17.500 52.250 20.000 ;
        RECT 45.650 17.500 48.050 29.500 ;
        RECT 41.750 27.100 48.050 29.500 ;
        RECT 41.750 27.100 44.250 38.200 ;
        RECT 38.750 29.700 44.250 38.200 ;
        RECT 53.150 10.500 57.950 16.000 ;
        RECT 55.450 10.500 57.950 38.200 ;
        RECT 54.950 26.700 57.950 38.200 ;
  END 
END NND601










macro NND701
  CLASS  CORE ;
  FOREIGN NND701 0.000 0.000 ;
  ORIGIN 0.000 0.000 ;
  SIZE 67.200 BY 48.700 ;
  SYMMETRY X Y  ;
  SITE CORE ;
  PIN OUT1
    DIRECTION OUTPUT ;
    PORT
      LAYER metal1 ;
        RECT 63.850 21.000 66.350 23.500 ;
    END
  END OUT1
  PIN VSS
    DIRECTION INOUT ;
    USE GROUND ;
    SHAPE ABUTMENT ;
    PORT
      LAYER metal1 ;
        RECT 21.050 0.000 23.550 16.050 ;
        RECT 0.000 0.000 67.200 9.000 ;
        RECT 63.200 0.000 65.700 14.250 ;
        RECT 53.050 0.000 55.550 12.250 ;
        RECT 42.850 0.000 45.350 12.600 ;
    END
  END VSS
  PIN IN1
    DIRECTION INPUT ;
    PORT
      LAYER metal1 ;
        RECT 0.850 20.400 3.350 22.900 ;
    END
  END IN1
  PIN IN2
    DIRECTION INPUT ;
    PORT
      LAYER metal1 ;
        RECT 9.250 20.900 11.750 23.400 ;
    END
  END IN2
  PIN IN3
    DIRECTION INPUT ;
    PORT
      LAYER metal1 ;
        RECT 13.450 19.250 15.950 21.750 ;
    END
  END IN3
  PIN IN4
    DIRECTION INPUT ;
    PORT
      LAYER metal1 ;
        RECT 21.850 19.300 24.350 21.800 ;
    END
  END IN4
  PIN IN5
    DIRECTION INPUT ;
    PORT
      LAYER metal1 ;
        RECT 38.650 21.000 41.150 23.500 ;
    END
  END IN5
  PIN IN6
    DIRECTION INPUT ;
    PORT
      LAYER metal1 ;
        RECT 30.250 21.000 32.750 23.500 ;
    END
  END IN6
  PIN VDD
    DIRECTION INOUT ;
    USE POWER ;
    SHAPE ABUTMENT ;
    PORT
      LAYER metal1 ;
        RECT 1.350 28.500 3.850 48.700 ;
        RECT 0.000 39.700 67.200 48.700 ;
        RECT 56.550 30.200 59.050 48.700 ;
        RECT 33.750 32.900 36.250 48.700 ;
        RECT 22.950 30.950 25.450 48.700 ;
        RECT 12.150 30.950 14.650 48.700 ;
    END
  END VDD
  PIN IN7
    DIRECTION INPUT ;
    PORT
      LAYER metal1 ;
        RECT 26.050 18.100 28.550 20.600 ;
    END
  END IN7
  OBS 
   
      LAYER metal1 ;
        RECT 0.850 20.400 3.350 26.300 ;
        RECT 8.900 17.500 11.400 22.050 ;
        RECT 9.250 20.900 11.750 23.400 ;
        RECT 13.450 19.250 16.550 21.750 ;
        RECT 14.050 19.250 16.550 25.350 ;
        RECT 19.300 19.300 24.350 21.800 ;
        RECT 19.300 19.300 21.850 23.150 ;
        RECT 19.350 19.300 21.850 25.200 ;
        RECT 25.850 18.100 28.550 23.600 ;
        RECT 30.250 17.500 33.250 20.000 ;
        RECT 30.250 17.500 32.750 23.500 ;
        RECT 35.950 18.050 38.650 23.300 ;
        RECT 36.150 17.500 38.650 23.300 ;
        RECT 38.650 20.800 41.150 23.500 ;
        RECT 1.350 10.550 3.850 16.050 ;
        RECT 1.350 13.550 4.850 16.050 ;
        RECT 45.267 20.900 45.350 25.150 ;
        RECT 23.600 25.100 41.783 27.500 ;
        RECT 42.850 20.900 42.917 27.500 ;
        RECT 8.217 27.050 26.000 29.450 ;
        RECT 6.750 13.550 7.400 38.200 ;
        RECT 8.217 27.050 9.250 38.200 ;
        RECT 17.550 27.050 20.050 38.200 ;
        RECT 42.917 20.900 43.017 27.400 ;
        RECT 43.017 20.900 43.117 27.300 ;
        RECT 43.117 20.900 43.217 27.200 ;
        RECT 43.217 20.900 43.317 27.100 ;
        RECT 43.317 20.900 43.417 27.000 ;
        RECT 43.417 20.900 43.517 26.900 ;
        RECT 43.517 20.900 43.617 26.800 ;
        RECT 43.617 20.900 43.717 26.700 ;
        RECT 43.717 20.900 43.817 26.600 ;
        RECT 43.817 20.900 43.917 26.500 ;
        RECT 43.917 20.900 44.017 26.400 ;
        RECT 44.017 20.900 44.117 26.300 ;
        RECT 44.117 20.900 44.217 26.200 ;
        RECT 44.217 20.900 44.317 26.100 ;
        RECT 44.317 20.900 44.417 26.000 ;
        RECT 44.417 20.900 44.517 25.900 ;
        RECT 44.517 20.900 44.617 25.800 ;
        RECT 44.617 20.900 44.717 25.700 ;
        RECT 44.717 20.900 44.817 25.600 ;
        RECT 44.817 20.900 44.917 25.500 ;
        RECT 44.917 20.900 45.017 25.400 ;
        RECT 45.017 20.900 45.117 25.300 ;
        RECT 45.117 20.900 45.217 25.200 ;
        RECT 45.217 20.900 45.267 25.150 ;
        RECT 41.783 25.100 41.883 27.500 ;
        RECT 41.883 25.000 41.983 27.500 ;
        RECT 41.983 24.900 42.083 27.500 ;
        RECT 42.083 24.800 42.183 27.500 ;
        RECT 42.183 24.700 42.283 27.500 ;
        RECT 42.283 24.600 42.383 27.500 ;
        RECT 42.383 24.500 42.483 27.500 ;
        RECT 42.483 24.400 42.583 27.500 ;
        RECT 42.583 24.300 42.683 27.500 ;
        RECT 42.683 24.200 42.783 27.500 ;
        RECT 42.783 24.100 42.850 27.500 ;
        RECT 7.400 26.333 7.500 38.200 ;
        RECT 7.500 26.433 7.600 38.200 ;
        RECT 7.600 26.533 7.700 38.200 ;
        RECT 7.700 26.633 7.800 38.200 ;
        RECT 7.800 26.733 7.900 38.200 ;
        RECT 7.900 26.833 8.000 38.200 ;
        RECT 8.000 26.933 8.100 38.200 ;
        RECT 8.100 27.033 8.200 38.200 ;
        RECT 8.200 27.050 8.217 38.200 ;
        RECT 4.850 13.550 4.950 27.217 ;
        RECT 4.950 13.550 5.050 27.317 ;
        RECT 5.050 13.550 5.150 27.417 ;
        RECT 5.150 13.550 5.250 27.517 ;
        RECT 5.250 13.550 5.350 27.617 ;
        RECT 5.350 13.550 5.450 27.717 ;
        RECT 5.450 13.550 5.550 27.817 ;
        RECT 5.550 13.550 5.650 27.917 ;
        RECT 5.650 13.550 5.750 28.017 ;
        RECT 5.750 13.550 5.850 28.117 ;
        RECT 5.850 13.550 5.950 28.217 ;
        RECT 5.950 13.550 6.050 28.317 ;
        RECT 6.050 13.550 6.150 28.417 ;
        RECT 6.150 13.550 6.250 28.517 ;
        RECT 6.250 13.550 6.350 28.617 ;
        RECT 6.350 13.550 6.450 28.717 ;
        RECT 6.450 13.550 6.550 28.817 ;
        RECT 6.550 13.550 6.650 28.917 ;
        RECT 6.650 13.550 6.750 29.017 ;
        RECT 37.850 10.500 40.233 16.000 ;
        RECT 44.767 17.000 47.100 19.400 ;
        RECT 48.167 21.050 49.600 23.550 ;
        RECT 48.167 17.000 49.500 28.700 ;
        RECT 28.350 29.000 44.333 31.400 ;
        RECT 28.350 29.000 30.850 38.200 ;
        RECT 39.150 29.000 41.650 38.200 ;
        RECT 47.100 17.000 47.200 29.667 ;
        RECT 47.200 17.000 47.300 29.567 ;
        RECT 47.300 17.000 47.400 29.467 ;
        RECT 47.400 17.000 47.500 29.367 ;
        RECT 47.500 17.000 47.600 29.267 ;
        RECT 47.600 17.000 47.700 29.167 ;
        RECT 47.700 17.000 47.800 29.067 ;
        RECT 47.800 17.000 47.900 28.967 ;
        RECT 47.900 17.000 48.000 28.867 ;
        RECT 48.000 17.000 48.100 28.767 ;
        RECT 48.100 17.000 48.167 28.700 ;
        RECT 45.500 27.833 45.600 31.267 ;
        RECT 45.600 27.733 45.700 31.167 ;
        RECT 45.700 27.633 45.800 31.067 ;
        RECT 45.800 27.533 45.900 30.967 ;
        RECT 45.900 27.433 46.000 30.867 ;
        RECT 46.000 27.333 46.100 30.767 ;
        RECT 46.100 27.233 46.200 30.667 ;
        RECT 46.200 27.133 46.300 30.567 ;
        RECT 46.300 27.033 46.400 30.467 ;
        RECT 46.400 26.933 46.500 30.367 ;
        RECT 46.500 26.833 46.600 30.267 ;
        RECT 46.600 26.733 46.700 30.167 ;
        RECT 46.700 26.633 46.800 30.067 ;
        RECT 46.800 26.533 46.900 29.967 ;
        RECT 46.900 26.433 47.000 29.867 ;
        RECT 47.000 26.333 47.100 29.767 ;
        RECT 44.333 29.000 44.433 31.400 ;
        RECT 44.433 28.900 44.533 31.400 ;
        RECT 44.533 28.800 44.633 31.400 ;
        RECT 44.633 28.700 44.733 31.400 ;
        RECT 44.733 28.600 44.833 31.400 ;
        RECT 44.833 28.500 44.933 31.400 ;
        RECT 44.933 28.400 45.033 31.400 ;
        RECT 45.033 28.300 45.133 31.400 ;
        RECT 45.133 28.200 45.233 31.400 ;
        RECT 45.233 28.100 45.333 31.400 ;
        RECT 45.333 28.000 45.433 31.400 ;
        RECT 45.433 27.900 45.500 31.400 ;
        RECT 43.600 15.933 43.700 19.400 ;
        RECT 43.700 16.033 43.800 19.400 ;
        RECT 43.800 16.133 43.900 19.400 ;
        RECT 43.900 16.233 44.000 19.400 ;
        RECT 44.000 16.333 44.100 19.400 ;
        RECT 44.100 16.433 44.200 19.400 ;
        RECT 44.200 16.533 44.300 19.400 ;
        RECT 44.300 16.633 44.400 19.400 ;
        RECT 44.400 16.733 44.500 19.400 ;
        RECT 44.500 16.833 44.600 19.400 ;
        RECT 44.600 16.933 44.700 19.400 ;
        RECT 44.700 17.000 44.767 19.400 ;
        RECT 40.350 12.683 40.450 16.117 ;
        RECT 40.450 12.783 40.550 16.217 ;
        RECT 40.550 12.883 40.650 16.317 ;
        RECT 40.650 12.983 40.750 16.417 ;
        RECT 40.750 13.083 40.850 16.517 ;
        RECT 40.850 13.183 40.950 16.617 ;
        RECT 40.950 13.283 41.050 16.717 ;
        RECT 41.050 13.383 41.150 16.817 ;
        RECT 41.150 13.483 41.250 16.917 ;
        RECT 41.250 13.583 41.350 17.017 ;
        RECT 41.350 13.683 41.450 17.117 ;
        RECT 41.450 13.783 41.550 17.217 ;
        RECT 41.550 13.883 41.650 17.317 ;
        RECT 41.650 13.983 41.750 17.417 ;
        RECT 41.750 14.083 41.850 17.517 ;
        RECT 41.850 14.183 41.950 17.617 ;
        RECT 41.950 14.283 42.050 17.717 ;
        RECT 42.050 14.383 42.150 17.817 ;
        RECT 42.150 14.483 42.250 17.917 ;
        RECT 42.250 14.583 42.350 18.017 ;
        RECT 42.350 14.683 42.450 18.117 ;
        RECT 42.450 14.783 42.550 18.217 ;
        RECT 42.550 14.883 42.650 18.317 ;
        RECT 42.650 14.983 42.750 18.417 ;
        RECT 42.750 15.083 42.850 18.517 ;
        RECT 42.850 15.183 42.950 18.617 ;
        RECT 42.950 15.283 43.050 18.717 ;
        RECT 43.050 15.383 43.150 18.817 ;
        RECT 43.150 15.483 43.250 18.917 ;
        RECT 43.250 15.583 43.350 19.017 ;
        RECT 43.350 15.683 43.450 19.117 ;
        RECT 43.450 15.783 43.550 19.217 ;
        RECT 43.550 15.833 43.600 19.317 ;
        RECT 40.233 10.500 40.333 16.000 ;
        RECT 40.333 10.500 40.350 16.100 ;
        RECT 47.950 10.500 48.033 13.000 ;
        RECT 53.500 21.650 60.000 24.150 ;
        RECT 47.150 32.700 51.100 35.400 ;
        RECT 47.150 32.700 49.650 38.200 ;
        RECT 53.500 15.033 53.600 15.951 ;
        RECT 53.600 15.133 53.700 15.851 ;
        RECT 51.100 12.633 51.200 35.400 ;
        RECT 51.200 12.733 51.300 35.400 ;
        RECT 51.300 12.833 51.400 35.400 ;
        RECT 51.400 12.933 51.500 35.400 ;
        RECT 51.500 13.033 51.600 35.400 ;
        RECT 51.600 13.133 51.700 35.400 ;
        RECT 51.700 13.233 51.800 35.400 ;
        RECT 51.800 13.333 51.900 35.400 ;
        RECT 51.900 13.433 52.000 35.400 ;
        RECT 52.000 13.533 52.100 35.400 ;
        RECT 52.100 13.633 52.200 35.400 ;
        RECT 52.200 13.733 52.300 35.400 ;
        RECT 52.300 13.833 52.400 35.400 ;
        RECT 52.400 13.933 52.500 35.400 ;
        RECT 52.500 14.033 52.600 35.400 ;
        RECT 52.600 14.133 52.700 35.400 ;
        RECT 52.700 14.233 52.800 35.400 ;
        RECT 52.800 14.333 52.900 35.400 ;
        RECT 52.900 14.433 53.000 35.400 ;
        RECT 53.000 14.533 53.100 35.400 ;
        RECT 53.100 14.633 53.200 35.400 ;
        RECT 53.200 14.733 53.300 35.400 ;
        RECT 53.300 14.833 53.400 35.400 ;
        RECT 53.400 14.933 53.500 35.400 ;
        RECT 50.450 11.983 50.550 15.417 ;
        RECT 50.550 12.083 50.650 15.517 ;
        RECT 50.650 12.183 50.750 15.617 ;
        RECT 50.750 12.283 50.850 15.717 ;
        RECT 50.850 12.383 50.950 15.817 ;
        RECT 50.950 12.483 51.050 15.917 ;
        RECT 51.050 12.533 51.100 16.017 ;
        RECT 48.033 10.500 48.133 13.000 ;
        RECT 48.133 10.500 48.233 13.100 ;
        RECT 48.233 10.500 48.333 13.200 ;
        RECT 48.333 10.500 48.433 13.300 ;
        RECT 48.433 10.500 48.533 13.400 ;
        RECT 48.533 10.500 48.633 13.500 ;
        RECT 48.633 10.500 48.733 13.600 ;
        RECT 48.733 10.500 48.833 13.700 ;
        RECT 48.833 10.500 48.933 13.800 ;
        RECT 48.933 10.500 49.033 13.900 ;
        RECT 49.033 10.500 49.133 14.000 ;
        RECT 49.133 10.500 49.233 14.100 ;
        RECT 49.233 10.500 49.333 14.200 ;
        RECT 49.333 10.500 49.433 14.300 ;
        RECT 49.433 10.500 49.533 14.400 ;
        RECT 49.533 10.500 49.633 14.500 ;
        RECT 49.633 10.500 49.733 14.600 ;
        RECT 49.733 10.500 49.833 14.700 ;
        RECT 49.833 10.500 49.933 14.800 ;
        RECT 49.933 10.500 50.033 14.900 ;
        RECT 50.033 10.500 50.133 15.000 ;
        RECT 50.133 10.500 50.233 15.100 ;
        RECT 50.233 10.500 50.333 15.200 ;
        RECT 50.333 10.500 50.433 15.300 ;
        RECT 50.433 10.500 50.450 15.400 ;
        RECT 58.200 10.500 60.700 19.300 ;
        RECT 58.200 16.800 66.350 19.300 ;
        RECT 61.950 16.800 66.350 27.700 ;
        RECT 61.950 16.800 64.750 37.550 ;
  END 
END NND701





macro NOR200
  CLASS  CORE ;
  FOREIGN NOR200 0.000 0.000 ;
  ORIGIN 0.000 0.000 ;
  SIZE 16.800 BY 48.700 ;
  SYMMETRY X Y  ;
  SITE CORE ;
  PIN OUT1
    DIRECTION OUTPUT ;
    PORT
      LAYER metal1 ;
        RECT 13.450 16.800 15.950 19.300 ;
    END
  END OUT1
  PIN VSS
    DIRECTION INOUT ;
    USE GROUND ;
    SHAPE ABUTMENT ;
    PORT
      LAYER metal1 ;
        RECT 7.300 0.000 9.800 11.250 ;
        RECT 0.000 0.000 16.800 9.000 ;
    END
  END VSS
  PIN IN1
    DIRECTION INPUT ;
    PORT
      LAYER metal1 ;
        RECT 0.850 21.000 3.350 23.500 ;
    END
  END IN1
  PIN IN2
    DIRECTION INPUT ;
    PORT
      LAYER metal1 ;
        RECT 9.250 16.800 11.750 19.300 ;
    END
  END IN2
  PIN VDD
    DIRECTION INOUT ;
    USE POWER ;
    SHAPE ABUTMENT ;
    PORT
      LAYER metal1 ;
        RECT 2.350 27.000 4.850 48.700 ;
        RECT 0.000 39.700 16.800 48.700 ;
    END
  END VDD
  OBS 
      
      LAYER metal1 ;
        RECT 0.850 21.000 3.350 24.600 ;
        RECT 0.850 22.100 6.850 24.600 ;
        RECT 8.550 16.800 11.750 19.300 ;
        RECT 8.550 16.800 11.050 24.800 ;
        RECT 2.200 10.500 4.700 15.200 ;
        RECT 12.400 10.500 15.950 15.200 ;
        RECT 2.200 12.800 15.950 15.200 ;
        RECT 13.450 10.500 15.950 29.450 ;
        RECT 11.250 26.500 13.750 38.000 ;
  END 
END NOR200



macro NOR300
  CLASS  CORE ;
  FOREIGN NOR300 0.000 0.000 ;
  ORIGIN 0.000 0.000 ;
  SIZE 21.000 BY 48.700 ;
  SYMMETRY X Y  ;
  SITE CORE ;
  PIN OUT1
    DIRECTION OUTPUT ;
    PORT
      LAYER metal1 ;
        RECT 17.650 16.800 20.150 19.300 ;
    END
  END OUT1
  PIN VSS
    DIRECTION INOUT ;
    USE GROUND ;
    SHAPE ABUTMENT ;
    PORT
      LAYER metal1 ;
        RECT 0.850 0.000 3.750 14.050 ;
        RECT 0.000 0.000 21.000 9.000 ;
        RECT 11.450 0.000 13.950 13.600 ;
    END
  END VSS
  PIN IN1
    DIRECTION INPUT ;
    PORT
      LAYER metal1 ;
        RECT 0.850 16.800 3.350 19.300 ;
    END
  END IN1
  PIN IN2
    DIRECTION INPUT ;
    PORT
      LAYER metal1 ;
        RECT 9.250 21.000 11.750 23.500 ;
    END
  END IN2
  PIN IN3
    DIRECTION INPUT ;
    PORT
      LAYER metal1 ;
        RECT 13.450 21.000 15.950 23.500 ;
    END
  END IN3
  PIN VDD
    DIRECTION INOUT ;
    USE POWER ;
    SHAPE ABUTMENT ;
    PORT
      LAYER metal1 ;
        RECT 0.850 29.400 4.050 48.700 ;
        RECT 0.000 39.700 21.000 48.700 ;
    END
  END VDD
  OBS 
     
      LAYER metal1 ;
        RECT 0.850 16.800 3.350 23.500 ;
        RECT 7.300 21.000 11.750 23.500 ;
        RECT 7.300 21.000 10.050 27.700 ;
        RECT 13.450 21.000 15.950 27.200 ;
        RECT 6.050 10.500 9.200 17.900 ;
        RECT 16.550 10.500 20.150 17.900 ;
        RECT 6.050 15.100 20.150 17.900 ;
        RECT 17.650 10.500 20.150 38.200 ;
        RECT 13.450 29.400 20.150 38.200 ;
  END 
END NOR300








macro NOR301
  CLASS  CORE ;
  FOREIGN NOR301 0.000 0.000 ;
  ORIGIN 0.000 0.000 ;
  SIZE 37.800 BY 48.700 ;
  SYMMETRY X Y  ;
  SITE CORE ;
  PIN OUT1
    DIRECTION OUTPUT ;
    PORT
      LAYER metal1 ;
        RECT 34.450 21.000 36.950 23.500 ;
    END
  END OUT1
  PIN VSS
    DIRECTION INOUT ;
    USE GROUND ;
    SHAPE ABUTMENT ;
    PORT
      LAYER metal1 ;
        RECT 0.850 0.000 3.850 11.000 ;
        RECT 0.000 0.000 37.800 9.000 ;
        RECT 28.400 0.000 31.350 15.500 ;
        RECT 11.250 0.000 14.300 11.000 ;
    END
  END VSS
  PIN IN1
    DIRECTION INPUT ;
    PORT
      LAYER metal1 ;
        RECT 5.050 16.800 7.550 19.300 ;
    END
  END IN1
  PIN IN2
    DIRECTION INPUT ;
    PORT
      LAYER metal1 ;
        RECT 15.300 16.800 17.800 19.300 ;
    END
  END IN2
  PIN IN3
    DIRECTION INPUT ;
    PORT
      LAYER metal1 ;
        RECT 0.850 22.550 3.350 25.050 ;
    END
  END IN3
  PIN VDD
    DIRECTION INOUT ;
    USE POWER ;
    SHAPE ABUTMENT ;
    PORT
      LAYER metal1 ;
        RECT 0.000 39.700 37.800 48.700 ;
        RECT 28.550 26.700 31.050 48.700 ;
        RECT 18.950 27.150 21.950 31.000 ;
        RECT 18.950 27.150 21.350 48.700 ;
        RECT 0.850 29.550 3.850 48.700 ;
    END
  END VDD
  OBS 
      
      LAYER metal1 ;
        RECT 0.950 14.900 3.550 19.300 ;
        RECT 0.950 16.800 7.550 19.300 ;
        RECT 0.850 22.550 13.150 25.050 ;
        RECT 9.050 16.800 17.800 19.300 ;
        RECT 6.450 10.500 8.950 15.000 ;
        RECT 16.650 10.500 21.750 15.000 ;
        RECT 6.450 12.500 21.750 15.000 ;
        RECT 19.300 10.500 21.750 24.400 ;
        RECT 14.650 21.850 21.750 24.400 ;
        RECT 14.650 21.850 17.450 38.200 ;
        RECT 13.750 26.550 17.450 38.200 ;
        RECT 23.300 10.500 26.550 13.250 ;
        RECT 23.800 10.500 26.550 24.450 ;
        RECT 23.800 21.850 32.100 24.450 ;
        RECT 23.800 10.500 26.300 38.200 ;
        RECT 22.850 32.700 26.300 38.200 ;
        RECT 33.950 10.500 36.950 38.200 ;
  END 
END NOR301




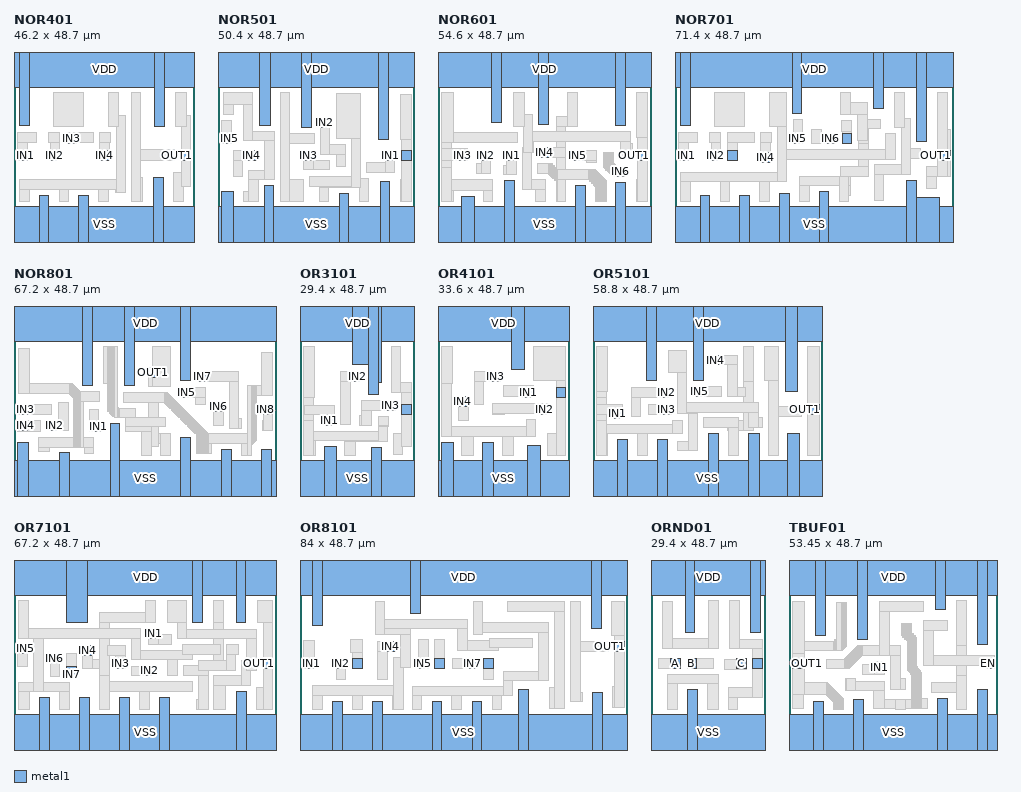
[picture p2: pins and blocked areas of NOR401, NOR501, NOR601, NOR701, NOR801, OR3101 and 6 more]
macro NOR401
  CLASS  CORE ;
  FOREIGN NOR401 0.000 0.000 ;
  ORIGIN 0.000 0.000 ;
  SIZE 46.200 BY 48.700 ;
  SYMMETRY X Y  ;
  SITE CORE ;
  PIN OUT1
    DIRECTION OUTPUT ;
    PORT
      LAYER metal1 ;
        RECT 42.850 21.000 45.350 23.500 ;
    END
  END OUT1
  PIN VSS
    DIRECTION INOUT ;
    USE GROUND ;
    SHAPE ABUTMENT ;
    PORT
      LAYER metal1 ;
        RECT 6.450 0.000 8.950 12.000 ;
        RECT 0.000 0.000 46.200 9.000 ;
        RECT 35.850 0.000 38.350 16.500 ;
        RECT 16.650 0.000 19.150 12.000 ;
    END
  END VSS
  PIN IN1
    DIRECTION INPUT ;
    PORT
      LAYER metal1 ;
        RECT 0.850 21.000 3.350 23.500 ;
    END
  END IN1
  PIN IN2
    DIRECTION INPUT ;
    PORT
      LAYER metal1 ;
        RECT 9.250 21.000 11.750 23.500 ;
    END
  END IN2
  PIN IN3
    DIRECTION INPUT ;
    PORT
      LAYER metal1 ;
        RECT 13.450 25.200 15.950 27.700 ;
    END
  END IN3
  PIN IN4
    DIRECTION INPUT ;
    PORT
      LAYER metal1 ;
        RECT 21.850 21.000 24.350 23.500 ;
    END
  END IN4
  PIN VDD
    DIRECTION INOUT ;
    USE POWER ;
    SHAPE ABUTMENT ;
    PORT
      LAYER metal1 ;
        RECT 1.350 29.750 3.850 48.700 ;
        RECT 0.000 39.700 46.200 48.700 ;
        RECT 35.950 29.700 38.450 48.700 ;
    END
  END VDD
  OBS 
      
      LAYER metal1 ;
        RECT 0.850 21.000 3.350 28.050 ;
        RECT 0.850 25.550 5.850 28.050 ;
        RECT 9.250 21.000 11.750 28.050 ;
        RECT 8.900 25.550 11.750 28.050 ;
        RECT 10.250 29.700 17.750 38.200 ;
        RECT 13.450 25.200 15.950 28.050 ;
        RECT 13.450 25.550 20.350 28.050 ;
        RECT 21.850 21.000 24.350 28.050 ;
        RECT 21.850 25.550 24.650 28.050 ;
        RECT 1.350 10.500 3.850 15.900 ;
        RECT 11.550 10.500 14.050 15.900 ;
        RECT 21.750 10.500 24.250 15.900 ;
        RECT 26.050 12.600 28.550 15.900 ;
        RECT 1.350 13.500 28.550 15.900 ;
        RECT 26.150 12.600 28.550 32.550 ;
        RECT 24.150 29.700 26.750 38.200 ;
        RECT 30.050 10.500 33.050 16.500 ;
        RECT 30.050 21.000 41.100 23.700 ;
        RECT 30.050 10.500 32.550 38.200 ;
        RECT 40.950 10.500 43.550 17.700 ;
        RECT 42.850 14.200 45.350 32.300 ;
        RECT 41.350 29.700 44.100 38.200 ;
  END 
END NOR401








macro NOR501
  CLASS  CORE ;
  FOREIGN NOR501 0.000 0.000 ;
  ORIGIN 0.000 0.000 ;
  SIZE 50.400 BY 48.700 ;
  SYMMETRY X Y  ;
  SITE CORE ;
  PIN OUT1
    DIRECTION OUTPUT ;
    PORT
      LAYER metal1 ;
        RECT 47.050 21.000 49.550 23.500 ;
    END
  END OUT1
  PIN VSS
    DIRECTION INOUT ;
    USE GROUND ;
    SHAPE ABUTMENT ;
    PORT
      LAYER metal1 ;
        RECT 0.950 0.000 3.850 13.000 ;
        RECT 0.000 0.000 50.400 9.000 ;
        RECT 41.550 0.000 44.050 15.500 ;
        RECT 31.050 0.000 33.550 12.500 ;
        RECT 11.850 0.000 14.350 14.500 ;
    END
  END VSS
  PIN IN1
    DIRECTION INPUT ;
    PORT
      LAYER metal1 ;
        RECT 42.850 21.000 45.350 23.500 ;
    END
  END IN1
  PIN IN2
    DIRECTION INPUT ;
    PORT
      LAYER metal1 ;
        RECT 26.050 29.400 28.550 31.900 ;
    END
  END IN2
  PIN IN3
    DIRECTION INPUT ;
    PORT
      LAYER metal1 ;
        RECT 21.850 21.000 24.350 23.500 ;
    END
  END IN3
  PIN IN4
    DIRECTION INPUT ;
    PORT
      LAYER metal1 ;
        RECT 7.250 21.000 9.750 23.500 ;
    END
  END IN4
  PIN IN5
    DIRECTION INPUT ;
    PORT
      LAYER metal1 ;
        RECT 0.850 25.200 3.350 27.700 ;
    END
  END IN5
  PIN VDD
    DIRECTION INOUT ;
    USE POWER ;
    SHAPE ABUTMENT ;
    PORT
      LAYER metal1 ;
        RECT 10.550 29.800 13.350 48.700 ;
        RECT 0.000 39.700 50.400 48.700 ;
        RECT 41.250 26.200 43.750 48.700 ;
        RECT 21.350 29.250 23.850 48.700 ;
    END
  END VDD
  OBS 
      
      LAYER metal1 ;
        RECT 0.850 25.200 3.350 31.100 ;
        RECT 3.850 16.800 6.350 23.500 ;
        RECT 3.850 21.000 9.750 23.500 ;
        RECT 6.450 10.500 10.300 13.000 ;
        RECT 7.900 10.500 10.300 18.400 ;
        RECT 7.900 16.000 14.450 18.400 ;
        RECT 11.950 16.000 14.450 28.300 ;
        RECT 6.450 25.900 14.450 28.300 ;
        RECT 1.350 32.700 3.850 38.200 ;
        RECT 6.450 25.900 8.950 38.200 ;
        RECT 1.350 35.300 8.950 38.200 ;
        RECT 15.950 10.500 21.950 16.000 ;
        RECT 15.950 25.200 24.650 27.750 ;
        RECT 15.950 10.500 18.450 38.200 ;
        RECT 21.850 18.500 28.550 21.000 ;
        RECT 21.850 18.500 24.350 23.500 ;
        RECT 30.250 19.300 32.750 24.900 ;
        RECT 26.150 22.500 32.750 24.900 ;
        RECT 26.150 22.500 28.550 31.900 ;
        RECT 26.050 29.400 28.550 31.900 ;
        RECT 25.950 10.500 28.450 16.700 ;
        RECT 36.150 10.500 38.650 16.400 ;
        RECT 25.950 14.000 36.650 16.700 ;
        RECT 23.450 14.200 36.650 16.700 ;
        RECT 34.250 14.000 36.650 38.100 ;
        RECT 30.250 26.600 36.650 38.100 ;
        RECT 38.150 17.900 45.350 20.400 ;
        RECT 42.850 17.900 45.350 23.500 ;
        RECT 46.650 10.500 49.550 16.000 ;
        RECT 47.050 10.500 49.550 37.700 ;
        RECT 46.650 26.200 49.550 37.700 ;
  END 
END NOR501







macro NOR601
  CLASS  CORE ;
  FOREIGN NOR601 0.000 0.000 ;
  ORIGIN 0.000 0.000 ;
  SIZE 54.600 BY 48.700 ;
  SYMMETRY X Y  ;
  SITE CORE ;
  PIN OUT1
    DIRECTION OUTPUT ;
    PORT
      LAYER metal1 ;
        RECT 51.250 21.000 53.750 23.500 ;
    END
  END OUT1
  PIN VSS
    DIRECTION INOUT ;
    USE GROUND ;
    SHAPE ABUTMENT ;
    PORT
      LAYER metal1 ;
        RECT 6.100 0.000 9.300 11.550 ;
        RECT 0.000 0.000 54.600 9.000 ;
        RECT 45.550 0.000 48.050 15.200 ;
        RECT 35.350 0.000 37.850 14.500 ;
        RECT 17.150 0.000 19.650 15.700 ;
    END
  END VSS
  PIN IN1
    DIRECTION INPUT ;
    PORT
      LAYER metal1 ;
        RECT 17.650 21.000 20.150 23.500 ;
    END
  END IN1
  PIN IN2
    DIRECTION INPUT ;
    PORT
      LAYER metal1 ;
        RECT 11.050 21.000 13.550 23.500 ;
    END
  END IN2
  PIN IN3
    DIRECTION INPUT ;
    PORT
      LAYER metal1 ;
        RECT 5.050 21.000 7.550 23.500 ;
    END
  END IN3
  PIN IN4
    DIRECTION INPUT ;
    PORT
      LAYER metal1 ;
        RECT 26.050 21.600 28.550 24.100 ;
    END
  END IN4
  PIN IN5
    DIRECTION INPUT ;
    PORT
      LAYER metal1 ;
        RECT 34.450 21.000 36.950 23.500 ;
    END
  END IN5
  PIN IN6
    DIRECTION INPUT ;
    PORT
      LAYER metal1 ;
        RECT 45.550 16.800 48.050 19.300 ;
    END
  END IN6
  PIN VDD
    DIRECTION INOUT ;
    USE POWER ;
    SHAPE ABUTMENT ;
    PORT
      LAYER metal1 ;
        RECT 13.750 30.600 16.250 48.700 ;
        RECT 0.000 39.700 54.600 48.700 ;
        RECT 45.450 29.900 48.150 48.700 ;
        RECT 25.800 30.200 28.300 48.700 ;
    END
  END VDD
  OBS 
      LAYER metal2 ;
        RECT 0.850 16.050 3.350 29.400 ;
        RECT 30.250 13.950 32.750 32.200 ;
      LAYER via1 ;
        RECT 1.350 27.200 2.850 28.700 ;
        RECT 1.350 17.000 2.850 18.500 ;
        
        
        
        
        RECT 30.750 30.200 32.250 31.700 ;
        RECT 30.750 14.450 32.250 15.950 ;
       
        
      LAYER metal1 ;
        RECT 0.850 21.000 7.550 24.000 ;
        RECT 9.900 17.500 13.550 20.000 ;
        RECT 11.050 17.500 13.550 23.500 ;
        RECT 0.850 10.500 3.850 16.000 ;
        RECT 11.550 10.500 14.050 16.000 ;
        RECT 0.850 13.250 14.050 16.000 ;
        RECT 0.850 10.500 3.350 19.000 ;
        RECT 16.750 17.200 20.150 19.700 ;
        RECT 17.650 17.200 20.150 23.500 ;
        RECT 0.850 25.500 20.350 28.000 ;
        RECT 0.850 25.500 3.850 38.200 ;
        RECT 26.050 21.600 32.750 24.100 ;
        RECT 30.250 29.700 35.800 32.200 ;
        RECT 33.300 29.700 35.800 38.200 ;
        RECT 38.150 20.500 40.650 23.500 ;
        RECT 34.450 21.000 40.650 23.500 ;
        RECT 30.550 10.500 32.750 18.700 ;
        RECT 30.550 16.000 38.550 18.700 ;
        RECT 25.550 17.500 28.300 20.000 ;
        RECT 40.450 10.500 40.550 18.350 ;
        RECT 40.550 10.500 40.650 18.250 ;
        RECT 40.650 10.500 40.750 18.150 ;
        RECT 40.750 10.500 40.850 18.050 ;
        RECT 40.850 10.500 40.950 17.950 ;
        RECT 40.950 10.500 41.050 17.850 ;
        RECT 41.050 10.500 41.150 17.750 ;
        RECT 41.150 10.500 41.250 17.650 ;
        RECT 41.250 10.500 41.350 17.550 ;
        RECT 41.350 10.500 41.450 17.450 ;
        RECT 41.450 10.500 41.550 17.350 ;
        RECT 41.550 10.500 41.650 17.250 ;
        RECT 41.650 10.500 41.750 17.150 ;
        RECT 41.750 10.500 41.850 17.050 ;
        RECT 41.850 10.500 41.950 16.950 ;
        RECT 41.950 10.500 42.050 16.850 ;
        RECT 42.050 10.500 42.150 16.750 ;
        RECT 42.150 10.500 42.250 16.650 ;
        RECT 42.250 10.500 42.350 16.550 ;
        RECT 42.350 10.500 42.450 16.450 ;
        RECT 42.450 10.500 42.550 16.350 ;
        RECT 42.550 10.500 42.650 16.250 ;
        RECT 42.650 10.500 42.750 16.150 ;
        RECT 42.750 10.500 42.850 16.050 ;
        RECT 42.850 10.500 42.950 15.950 ;
        RECT 42.950 10.500 43.050 15.850 ;
        RECT 43.050 10.500 43.150 15.750 ;
        RECT 40.200 14.350 40.300 18.600 ;
        RECT 40.300 14.250 40.400 18.500 ;
        RECT 40.400 14.150 40.450 18.450 ;
        RECT 38.550 16.000 38.650 18.700 ;
        RECT 38.650 15.900 38.750 18.700 ;
        RECT 38.750 15.800 38.850 18.700 ;
        RECT 38.850 15.700 38.950 18.700 ;
        RECT 38.950 15.600 39.050 18.700 ;
        RECT 39.050 15.500 39.150 18.700 ;
        RECT 39.150 15.400 39.250 18.700 ;
        RECT 39.250 15.300 39.350 18.700 ;
        RECT 39.350 15.200 39.450 18.700 ;
        RECT 39.450 15.100 39.550 18.700 ;
        RECT 39.550 15.000 39.650 18.700 ;
        RECT 39.650 14.900 39.750 18.700 ;
        RECT 39.750 14.800 39.850 18.700 ;
        RECT 39.850 14.700 39.950 18.700 ;
        RECT 39.950 14.600 40.050 18.700 ;
        RECT 40.050 14.500 40.150 18.700 ;
        RECT 40.150 14.400 40.200 18.700 ;
        RECT 30.250 10.500 30.350 18.900 ;
        RECT 30.350 10.500 30.450 18.800 ;
        RECT 30.450 10.500 30.550 18.700 ;
        RECT 29.250 16.550 29.350 19.900 ;
        RECT 29.350 16.450 29.450 19.800 ;
        RECT 29.450 16.350 29.550 19.700 ;
        RECT 29.550 16.250 29.650 19.600 ;
        RECT 29.650 16.150 29.750 19.500 ;
        RECT 29.750 16.050 29.850 19.400 ;
        RECT 29.850 15.950 29.950 19.300 ;
        RECT 29.950 15.850 30.050 19.200 ;
        RECT 30.050 15.750 30.150 19.100 ;
        RECT 30.150 15.650 30.250 19.000 ;
        RECT 28.300 17.500 28.400 20.000 ;
        RECT 28.400 17.400 28.500 20.000 ;
        RECT 28.500 17.300 28.600 20.000 ;
        RECT 28.600 17.200 28.700 20.000 ;
        RECT 28.700 17.100 28.800 20.000 ;
        RECT 28.800 17.000 28.900 20.000 ;
        RECT 28.900 16.900 29.000 20.000 ;
        RECT 29.000 16.800 29.100 20.000 ;
        RECT 29.100 16.700 29.200 20.000 ;
        RECT 29.200 16.600 29.250 20.000 ;
        RECT 45.900 16.800 48.100 19.300 ;
        RECT 44.700 16.800 45.000 23.050 ;
        RECT 45.000 16.800 45.100 20.100 ;
        RECT 45.100 16.800 45.200 20.000 ;
        RECT 45.200 16.800 45.300 19.900 ;
        RECT 45.300 16.800 45.400 19.800 ;
        RECT 45.400 16.800 45.500 19.700 ;
        RECT 45.500 16.800 45.600 19.600 ;
        RECT 45.600 16.800 45.700 19.500 ;
        RECT 45.700 16.800 45.800 19.400 ;
        RECT 45.800 16.800 45.900 19.300 ;
        RECT 42.350 19.150 42.450 23.050 ;
        RECT 42.450 19.050 42.550 23.050 ;
        RECT 42.550 18.950 42.650 23.050 ;
        RECT 42.650 18.850 42.750 23.050 ;
        RECT 42.750 18.750 42.850 23.050 ;
        RECT 42.850 18.650 42.950 23.050 ;
        RECT 42.950 18.550 43.050 23.050 ;
        RECT 43.050 18.450 43.150 23.050 ;
        RECT 43.150 18.350 43.250 23.050 ;
        RECT 43.250 18.250 43.350 23.050 ;
        RECT 43.350 18.150 43.450 23.050 ;
        RECT 43.450 18.050 43.550 23.050 ;
        RECT 43.550 17.950 43.650 23.050 ;
        RECT 43.650 17.850 43.750 23.050 ;
        RECT 43.750 17.750 43.850 23.050 ;
        RECT 43.850 17.650 43.950 23.050 ;
        RECT 43.950 17.550 44.050 23.050 ;
        RECT 44.050 17.450 44.150 23.050 ;
        RECT 44.150 17.350 44.250 23.050 ;
        RECT 44.250 17.250 44.350 23.050 ;
        RECT 44.350 17.150 44.450 23.050 ;
        RECT 44.450 17.050 44.550 23.050 ;
        RECT 44.550 16.950 44.650 23.050 ;
        RECT 44.650 16.850 44.700 23.050 ;
        RECT 25.000 10.500 27.650 16.000 ;
        RECT 21.650 13.500 27.650 16.000 ;
        RECT 21.650 13.500 24.050 24.300 ;
        RECT 46.900 21.300 49.750 25.350 ;
        RECT 21.850 23.000 24.350 28.200 ;
        RECT 46.900 21.300 49.300 28.200 ;
        RECT 21.850 25.700 49.300 28.200 ;
        RECT 21.850 23.000 24.300 32.750 ;
        RECT 19.450 29.700 22.150 38.200 ;
        RECT 50.850 10.500 53.750 16.000 ;
        RECT 51.250 10.500 53.750 38.200 ;
        RECT 50.850 26.700 53.750 38.200 ;
  END 
END NOR601









macro NOR701
  CLASS  CORE ;
  FOREIGN NOR701 0.000 0.000 ;
  ORIGIN 0.000 0.000 ;
  SIZE 71.400 BY 48.700 ;
  SYMMETRY X Y  ;
  SITE CORE ;
  PIN OUT1
    DIRECTION OUTPUT ;
    PORT
      LAYER metal1 ;
        RECT 68.050 21.000 70.550 23.500 ;
    END
  END OUT1
  PIN VSS
    DIRECTION INOUT ;
    USE GROUND ;
    SHAPE ABUTMENT ;
    PORT
      LAYER metal1 ;
        RECT 6.450 0.000 8.950 12.000 ;
        RECT 0.000 0.000 71.400 9.000 ;
        RECT 59.350 0.000 67.850 11.450 ;
        RECT 59.350 0.000 61.850 15.850 ;
        RECT 36.950 0.000 39.450 13.000 ;
        RECT 26.750 0.000 29.250 12.450 ;
        RECT 16.650 0.000 19.150 12.000 ;
    END
  END VSS
  PIN IN1
    DIRECTION INPUT ;
    PORT
      LAYER metal1 ;
        RECT 0.850 21.000 3.350 23.500 ;
    END
  END IN1
  PIN IN2
    DIRECTION INPUT ;
    PORT
      LAYER metal1 ;
        RECT 9.250 21.000 11.750 23.500 ;
    END
  END IN2
  PIN IN3
    DIRECTION INPUT ;
    PORT
      LAYER metal1 ;
        RECT 13.450 21.000 15.950 23.500 ;
    END
  END IN3
  PIN IN4
    DIRECTION INPUT ;
    PORT
      LAYER metal1 ;
        RECT 21.850 20.500 24.350 23.000 ;
    END
  END IN4
  PIN IN5
    DIRECTION INPUT ;
    PORT
      LAYER metal1 ;
        RECT 30.250 25.200 32.750 27.700 ;
    END
  END IN5
  PIN IN6
    DIRECTION INPUT ;
    PORT
      LAYER metal1 ;
        RECT 38.650 25.200 41.150 27.700 ;
    END
  END IN6
  PIN VDD
    DIRECTION INOUT ;
    USE POWER ;
    SHAPE ABUTMENT ;
    PORT
      LAYER metal1 ;
        RECT 1.350 29.750 3.850 48.700 ;
        RECT 0.000 39.700 71.400 48.700 ;
        RECT 61.950 25.700 64.450 48.700 ;
        RECT 50.850 34.200 53.350 48.700 ;
        RECT 30.050 32.900 32.550 48.700 ;
    END
  END VDD
  PIN IN7
    DIRECTION INPUT ;
    PORT
      LAYER metal1 ;
        RECT 42.850 25.200 45.350 27.700 ;
    END
  END IN7
  OBS 
      LAYER metal2 ;
        RECT 47.050 16.800 49.550 27.700 ;
      LAYER via1 ;       
     
        RECT 47.550 25.700 49.050 27.200 ;
        RECT 47.550 17.300 49.050 18.800 ;
        
      LAYER metal1 ;
        RECT 0.850 21.000 3.350 28.050 ;
        RECT 0.850 25.550 5.850 28.050 ;
        RECT 9.250 21.000 11.750 28.050 ;
        RECT 8.900 25.550 11.750 28.050 ;
        RECT 10.250 29.700 17.750 38.200 ;
        RECT 13.450 21.000 15.950 28.050 ;
        RECT 13.450 25.550 20.350 28.050 ;
        RECT 21.850 20.500 24.350 28.050 ;
        RECT 21.850 25.550 24.650 28.050 ;
        RECT 30.250 25.200 32.750 31.400 ;
        RECT 34.950 25.200 41.150 27.700 ;
        RECT 34.950 25.200 37.450 28.900 ;
        RECT 42.850 25.200 45.350 31.200 ;
        RECT 42.550 28.350 45.350 31.200 ;
        RECT 31.850 10.500 34.350 16.900 ;
        RECT 42.450 12.000 44.950 19.300 ;
        RECT 31.850 14.500 44.950 16.900 ;
        RECT 42.050 10.500 44.550 16.900 ;
        RECT 42.450 16.800 49.550 19.300 ;
        RECT 47.050 25.200 49.550 31.500 ;
        RECT 46.850 29.000 52.650 31.500 ;
        RECT 46.850 26.050 49.350 35.700 ;
        RECT 42.450 32.700 49.350 35.700 ;
        RECT 42.450 32.700 44.950 38.200 ;
        RECT 1.350 10.500 3.850 17.850 ;
        RECT 11.550 10.500 14.050 17.850 ;
        RECT 21.750 10.500 24.250 17.850 ;
        RECT 1.350 15.450 28.550 17.850 ;
        RECT 26.150 21.250 56.550 23.650 ;
        RECT 54.050 21.250 56.550 27.800 ;
        RECT 26.150 15.450 28.550 38.200 ;
        RECT 24.150 29.700 28.550 38.200 ;
        RECT 51.050 10.650 53.550 19.750 ;
        RECT 51.050 17.350 60.450 19.750 ;
        RECT 58.050 21.500 62.900 24.000 ;
        RECT 58.050 17.350 60.450 31.750 ;
        RECT 56.250 29.300 58.750 38.200 ;
        RECT 64.450 13.800 66.950 19.300 ;
        RECT 64.450 16.800 70.550 19.300 ;
        RECT 67.350 16.800 70.550 28.900 ;
        RECT 67.350 16.800 69.850 38.200 ;
  END 
END NOR701









macro NOR801
  CLASS  CORE ;
  FOREIGN NOR801 0.000 0.000 ;
  ORIGIN 0.000 0.000 ;
  SIZE 67.200 BY 48.700 ;
  SYMMETRY X Y  ;
  SITE CORE ;
  PIN OUT1
    DIRECTION OUTPUT ;
    PORT
      LAYER metal1 ;
        RECT 34.450 30.450 36.950 32.950 ;
        
    END
  END OUT1
  PIN VSS
    DIRECTION INOUT ;
    USE GROUND ;
    SHAPE ABUTMENT ;
    PORT
      LAYER metal1 ;
        RECT 0.850 0.000 3.750 13.800 ;
        RECT 0.000 0.000 67.200 9.000 ;
        RECT 63.450 0.000 65.950 12.000 ;
        RECT 53.250 0.000 55.750 12.000 ;
        RECT 42.750 0.000 45.250 15.000 ;
        RECT 24.650 0.000 27.150 18.500 ;
        RECT 11.750 0.000 14.250 11.050 ;
    END
  END VSS
  PIN IN1
    DIRECTION INPUT ;
    PORT
      LAYER metal1 ;
        RECT 20.450 16.500 22.950 19.000 ;
    END
  END IN1
  PIN IN2
    DIRECTION INPUT ;
    PORT
      LAYER metal1 ;
        RECT 9.250 16.800 11.750 19.300 ;
    END
  END IN2
  PIN IN3
    DIRECTION INPUT ;
    PORT
      LAYER metal1 ;
        RECT 0.850 21.000 3.350 23.500 ;
    END
  END IN3
  PIN IN4
    DIRECTION INPUT ;
    PORT
      LAYER metal1 ;
        RECT 0.850 16.800 3.350 19.300 ;
    END
  END IN4
  PIN IN5
    DIRECTION INPUT ;
    PORT
      LAYER metal1 ;
        RECT 42.850 25.200 45.350 27.700 ;
    END
  END IN5
  PIN IN6
    DIRECTION INPUT ;
    PORT
      LAYER metal1 ;
        RECT 51.250 21.600 53.750 24.100 ;
    END
  END IN6
  PIN VDD
    DIRECTION INOUT ;
    USE POWER ;
    SHAPE ABUTMENT ;
    PORT
      LAYER metal1 ;
        RECT 17.650 28.300 20.150 48.700 ;
        RECT 0.000 39.700 67.200 48.700 ;
        RECT 42.750 29.650 45.250 48.700 ;
        RECT 28.450 28.300 30.950 48.700 ;
    END
  END VDD
  PIN IN7
    DIRECTION INPUT ;
    PORT
      LAYER metal1 ;
        RECT 47.050 29.400 49.550 31.900 ;
    END
  END IN7
  PIN IN8
    DIRECTION INPUT ;
    PORT
      LAYER metal1 ;
        RECT 63.850 21.000 66.350 23.500 ;
    END
  END IN8
  OBS 
  
     LAYER metal2 ;
        RECT 34.450 12.600 36.950 26.247 ;
        RECT 36.950 13.500 40.150 16.000 ;
        
      LAYER via1 ;
        
        RECT 38.150 14.000 39.650 15.500 ;
        
      LAYER metal1 ;
        RECT 0.850 16.500 6.750 19.300 ;
        RECT 0.850 20.800 9.650 23.500 ;
        RECT 9.250 16.800 13.850 19.300 ;
        RECT 11.350 16.800 13.850 24.000 ;
        RECT 6.350 11.300 9.100 15.000 ;
        RECT 18.000 10.850 20.500 14.950 ;
        RECT 17.000 12.550 20.500 14.950 ;
        RECT 6.350 12.550 15.350 15.000 ;
        RECT 17.000 12.550 17.750 26.800 ;
        RECT 17.000 24.100 21.950 26.800 ;
        RECT 1.250 26.200 14.100 28.950 ;
        RECT 1.250 26.200 4.000 37.700 ;
        RECT 15.350 12.550 15.450 28.350 ;
        RECT 15.450 12.550 15.550 28.250 ;
        RECT 15.550 12.550 15.650 28.150 ;
        RECT 15.650 12.550 15.750 28.050 ;
        RECT 15.750 12.550 15.850 27.950 ;
        RECT 15.850 12.550 15.950 27.850 ;
        RECT 15.950 12.550 16.050 27.750 ;
        RECT 16.050 12.550 16.150 27.650 ;
        RECT 16.150 12.550 16.250 27.550 ;
        RECT 16.250 12.550 16.350 27.450 ;
        RECT 16.350 12.550 16.450 27.350 ;
        RECT 16.450 12.550 16.550 27.250 ;
        RECT 16.550 12.550 16.650 27.150 ;
        RECT 16.650 12.550 16.750 27.050 ;
        RECT 16.750 12.550 16.850 26.950 ;
        RECT 16.850 12.550 16.950 26.850 ;
        RECT 16.950 12.550 17.000 26.800 ;
        RECT 14.850 25.450 14.950 28.850 ;
        RECT 14.950 25.350 15.050 28.750 ;
        RECT 15.050 25.250 15.150 28.650 ;
        RECT 15.150 25.150 15.250 28.550 ;
        RECT 15.250 25.050 15.350 28.450 ;
        RECT 14.100 26.200 14.200 28.950 ;
        RECT 14.200 26.100 14.300 28.950 ;
        RECT 14.300 26.000 14.400 28.950 ;
        RECT 14.400 25.900 14.500 28.950 ;
        RECT 14.500 25.800 14.600 28.950 ;
        RECT 14.600 25.700 14.700 28.950 ;
        RECT 14.700 25.600 14.800 28.950 ;
        RECT 14.800 25.500 14.850 28.950 ;
        RECT 19.250 16.450 22.950 19.000 ;
        RECT 19.250 16.450 21.750 22.050 ;
        RECT 32.650 10.500 35.200 20.200 ;
        RECT 28.650 16.600 35.200 20.200 ;
        RECT 28.650 17.700 38.850 20.200 ;
        RECT 27.100 20.000 31.050 22.400 ;
        RECT 23.050 28.900 23.950 38.200 ;
        RECT 25.800 20.000 26.450 38.200 ;
        RECT 26.450 20.000 26.550 22.950 ;
        RECT 26.550 20.000 26.650 22.850 ;
        RECT 26.650 20.000 26.750 22.750 ;
        RECT 26.750 20.000 26.850 22.650 ;
        RECT 26.850 20.000 26.950 22.550 ;
        RECT 26.950 20.000 27.050 22.450 ;
        RECT 27.050 20.000 27.100 22.400 ;
        RECT 23.950 21.850 24.050 38.200 ;
        RECT 24.050 21.750 24.150 38.200 ;
        RECT 24.150 21.650 24.250 38.200 ;
        RECT 24.250 21.550 24.350 38.200 ;
        RECT 24.350 21.450 24.450 38.200 ;
        RECT 24.450 21.350 24.550 38.200 ;
        RECT 24.550 21.250 24.650 38.200 ;
        RECT 24.650 21.150 24.750 38.200 ;
        RECT 24.750 21.050 24.850 38.200 ;
        RECT 24.850 20.950 24.950 38.200 ;
        RECT 24.950 20.850 25.050 38.200 ;
        RECT 25.050 20.750 25.150 38.200 ;
        RECT 25.150 20.650 25.250 38.200 ;
        RECT 25.250 20.550 25.350 38.200 ;
        RECT 25.350 20.450 25.450 38.200 ;
        RECT 25.450 20.350 25.550 38.200 ;
        RECT 25.550 20.250 25.650 38.200 ;
        RECT 25.650 20.150 25.750 38.200 ;
        RECT 25.750 20.050 25.800 38.200 ;
        RECT 34.450 28.000 40.050 32.950 ;
        RECT 35.600 28.000 40.050 38.200 ;
        RECT 37.650 10.500 40.150 16.000 ;
        RECT 46.550 23.450 49.050 27.700 ;
        RECT 42.850 25.200 49.050 27.700 ;
        RECT 51.250 18.000 53.750 24.100 ;
        RECT 55.250 17.400 58.250 19.950 ;
        RECT 55.250 17.400 57.650 31.900 ;
        RECT 47.050 29.400 57.650 31.900 ;
        RECT 49.950 11.000 50.650 15.900 ;
        RECT 58.350 10.500 60.850 15.900 ;
        RECT 49.950 13.500 60.850 15.900 ;
        RECT 27.950 24.000 38.450 26.500 ;
        RECT 59.750 10.500 60.850 28.400 ;
        RECT 62.150 25.800 66.350 28.400 ;
        RECT 63.450 25.800 66.350 36.800 ;
        RECT 60.850 13.000 60.950 28.400 ;
        RECT 60.950 13.100 61.050 28.400 ;
        RECT 61.050 13.200 61.150 28.400 ;
        RECT 61.150 13.300 61.250 28.400 ;
        RECT 61.250 13.400 61.350 28.400 ;
        RECT 61.350 13.500 61.450 28.400 ;
        RECT 61.450 13.600 61.550 28.400 ;
        RECT 61.550 13.700 61.650 28.400 ;
        RECT 61.650 13.800 61.750 28.400 ;
        RECT 61.750 13.900 61.850 28.400 ;
        RECT 61.850 14.000 61.950 28.400 ;
        RECT 61.950 14.100 62.050 28.400 ;
        RECT 62.050 14.200 62.150 28.400 ;
        RECT 46.900 11.000 47.000 18.850 ;
        RECT 47.000 11.000 47.100 18.750 ;
        RECT 47.100 11.000 47.200 18.650 ;
        RECT 47.200 11.000 47.300 18.550 ;
        RECT 47.300 11.000 47.400 18.450 ;
        RECT 47.400 11.000 47.500 18.350 ;
        RECT 47.500 11.000 47.600 18.250 ;
        RECT 47.600 11.000 47.700 18.150 ;
        RECT 47.700 11.000 47.800 18.050 ;
        RECT 47.800 11.000 47.900 17.950 ;
        RECT 47.900 11.000 48.000 17.850 ;
        RECT 48.000 11.000 48.100 17.750 ;
        RECT 48.100 11.000 48.200 17.650 ;
        RECT 48.200 11.000 48.300 17.550 ;
        RECT 48.300 11.000 48.400 17.450 ;
        RECT 48.400 11.000 48.500 17.350 ;
        RECT 48.500 11.000 48.600 17.250 ;
        RECT 48.600 11.000 48.700 17.150 ;
        RECT 48.700 11.000 48.800 17.050 ;
        RECT 48.800 11.000 48.900 16.950 ;
        RECT 48.900 11.000 49.000 16.850 ;
        RECT 49.000 11.000 49.100 16.750 ;
        RECT 49.100 11.000 49.200 16.650 ;
        RECT 49.200 11.000 49.300 16.550 ;
        RECT 49.300 11.000 49.400 16.450 ;
        RECT 49.400 11.000 49.500 16.350 ;
        RECT 49.500 11.000 49.600 16.250 ;
        RECT 49.600 11.000 49.700 16.150 ;
        RECT 49.700 11.000 49.800 16.050 ;
        RECT 49.800 11.000 49.900 15.950 ;
        RECT 49.900 11.000 49.950 15.900 ;
        RECT 39.350 23.100 39.450 26.400 ;
        RECT 39.450 23.000 39.550 26.300 ;
        RECT 39.550 22.900 39.650 26.200 ;
        RECT 39.650 22.800 39.750 26.100 ;
        RECT 39.750 22.700 39.850 26.000 ;
        RECT 39.850 22.600 39.950 25.900 ;
        RECT 39.950 22.500 40.050 25.800 ;
        RECT 40.050 22.400 40.150 25.700 ;
        RECT 40.150 22.300 40.250 25.600 ;
        RECT 40.250 22.200 40.350 25.500 ;
        RECT 40.350 22.100 40.450 25.400 ;
        RECT 40.450 22.000 40.550 25.300 ;
        RECT 40.550 21.900 40.650 25.200 ;
        RECT 40.650 21.800 40.750 25.100 ;
        RECT 40.750 21.700 40.850 25.000 ;
        RECT 40.850 21.600 40.950 24.900 ;
        RECT 40.950 21.500 41.050 24.800 ;
        RECT 41.050 21.400 41.150 24.700 ;
        RECT 41.150 21.300 41.250 24.600 ;
        RECT 41.250 21.200 41.350 24.500 ;
        RECT 41.350 21.100 41.450 24.400 ;
        RECT 41.450 21.000 41.550 24.300 ;
        RECT 41.550 20.900 41.650 24.200 ;
        RECT 41.650 20.800 41.750 24.100 ;
        RECT 41.750 20.700 41.850 24.000 ;
        RECT 41.850 20.600 41.950 23.900 ;
        RECT 41.950 20.500 42.050 23.800 ;
        RECT 42.050 20.400 42.150 23.700 ;
        RECT 42.150 20.300 42.250 23.600 ;
        RECT 42.250 20.200 42.350 23.500 ;
        RECT 42.350 20.100 42.450 23.400 ;
        RECT 42.450 20.000 42.550 23.300 ;
        RECT 42.550 19.900 42.650 23.200 ;
        RECT 42.650 19.800 42.750 23.100 ;
        RECT 42.750 19.700 42.850 23.000 ;
        RECT 42.850 19.600 42.950 22.900 ;
        RECT 42.950 19.500 43.050 22.800 ;
        RECT 43.050 19.400 43.150 22.700 ;
        RECT 43.150 19.300 43.250 22.600 ;
        RECT 43.250 19.200 43.350 22.500 ;
        RECT 43.350 19.100 43.450 22.400 ;
        RECT 43.450 19.000 43.550 22.300 ;
        RECT 43.550 18.900 43.650 22.200 ;
        RECT 43.650 18.800 43.750 22.100 ;
        RECT 43.750 18.700 43.850 22.000 ;
        RECT 43.850 18.600 43.950 21.900 ;
        RECT 43.950 18.500 44.050 21.800 ;
        RECT 44.050 18.400 44.150 21.700 ;
        RECT 44.150 18.300 44.250 21.600 ;
        RECT 44.250 18.200 44.350 21.500 ;
        RECT 44.350 18.100 44.450 21.400 ;
        RECT 44.450 18.000 44.550 21.300 ;
        RECT 44.550 17.900 44.650 21.200 ;
        RECT 44.650 17.800 44.750 21.100 ;
        RECT 44.750 17.700 44.850 21.000 ;
        RECT 44.850 17.600 44.950 20.900 ;
        RECT 44.950 17.500 45.050 20.800 ;
        RECT 45.050 17.400 45.150 20.700 ;
        RECT 45.150 17.300 45.250 20.600 ;
        RECT 45.250 17.200 45.350 20.500 ;
        RECT 45.350 17.100 45.450 20.400 ;
        RECT 45.450 17.000 45.550 20.300 ;
        RECT 45.550 16.900 45.650 20.200 ;
        RECT 45.650 16.800 45.750 20.100 ;
        RECT 45.750 16.700 45.850 20.000 ;
        RECT 45.850 16.600 45.950 19.900 ;
        RECT 45.950 16.500 46.050 19.800 ;
        RECT 46.050 16.400 46.150 19.700 ;
        RECT 46.150 16.300 46.250 19.600 ;
        RECT 46.250 16.200 46.350 19.500 ;
        RECT 46.350 16.100 46.450 19.400 ;
        RECT 46.450 16.000 46.550 19.300 ;
        RECT 46.550 15.900 46.650 19.200 ;
        RECT 46.650 15.800 46.750 19.100 ;
        RECT 46.750 15.700 46.850 19.000 ;
        RECT 46.850 15.600 46.900 18.950 ;
        RECT 38.450 24.000 38.550 26.500 ;
        RECT 38.550 23.900 38.650 26.500 ;
        RECT 38.650 23.800 38.750 26.500 ;
        RECT 38.750 23.700 38.850 26.500 ;
        RECT 38.850 23.600 38.950 26.500 ;
        RECT 38.950 23.500 39.050 26.500 ;
        RECT 39.050 23.400 39.150 26.500 ;
        RECT 39.150 23.300 39.250 26.500 ;
        RECT 39.250 23.200 39.350 26.500 ;
        RECT 63.650 16.800 66.350 19.300 ;
        RECT 63.850 16.800 66.350 23.500 ;
  END 
END NOR801



macro OR3101
  CLASS  CORE ;
  FOREIGN OR3101 0.000 0.000 ;
  ORIGIN 0.000 0.000 ;
  SIZE 29.400 BY 48.700 ;
  SYMMETRY X Y  ;
  SITE CORE ;
  PIN OUT1
    DIRECTION OUTPUT ;
    PORT
      LAYER metal1 ;
        RECT 26.050 21.000 28.550 23.500 ;
    END
  END OUT1
  PIN VSS
    DIRECTION INOUT ;
    USE GROUND ;
    SHAPE ABUTMENT ;
    PORT
      LAYER metal1 ;
        RECT 6.350 0.000 9.250 12.600 ;
        RECT 0.000 0.000 29.400 9.000 ;
        RECT 18.350 0.000 21.000 12.550 ;
    END
  END VSS
  PIN IN1
    DIRECTION INPUT ;
    PORT
      LAYER metal1 ;
        RECT 6.350 18.000 8.850 20.500 ;
    END
  END IN1
  PIN IN2
    DIRECTION INPUT ;
    PORT
      LAYER metal1 ;
        RECT 13.450 29.400 15.950 31.900 ;
    END
  END IN2
  PIN IN3
    DIRECTION INPUT ;
    PORT
      LAYER metal1 ;
        RECT 21.850 21.950 24.350 24.450 ;
    END
  END IN3
  PIN VDD
    DIRECTION INOUT ;
    USE POWER ;
    SHAPE ABUTMENT ;
    PORT
      LAYER metal1 ;
        RECT 17.650 26.050 20.150 48.700 ;
        RECT 0.000 39.700 29.400 48.700 ;
        RECT 13.450 33.600 20.800 48.700 ;
        RECT 17.650 29.200 20.800 48.700 ;
    END
  END VDD
  OBS 
      LAYER metal2 ;
        RECT 0.850 16.800 3.350 31.900 ;
      LAYER via1 ;
        RECT 1.350 29.900 2.850 31.400 ;
        RECT 1.350 17.300 2.850 18.800 ;
       
      LAYER metal1 ;
        RECT 0.850 25.200 3.750 38.200 ;
        RECT 6.350 18.000 8.850 23.300 ;
        RECT 1.050 20.800 8.850 23.300 ;
        RECT 10.500 18.300 13.000 31.900 ;
        RECT 10.500 29.400 15.950 31.900 ;
        RECT 11.450 10.500 14.250 16.500 ;
        RECT 0.850 10.500 4.050 16.500 ;
        RECT 11.450 14.050 22.400 16.500 ;
        RECT 0.850 14.100 22.400 16.500 ;
        RECT 20.000 14.050 22.400 20.350 ;
        RECT 20.000 17.700 22.500 20.350 ;
        RECT 20.000 17.800 22.600 20.350 ;
        RECT 20.000 17.900 22.700 20.350 ;
        RECT 0.850 10.500 3.350 19.300 ;
        RECT 20.000 17.950 22.750 20.350 ;
        RECT 15.200 18.050 18.200 20.650 ;
        RECT 15.650 18.050 18.200 24.450 ;
        RECT 15.650 21.950 24.350 24.450 ;
        RECT 23.900 10.600 26.400 16.100 ;
        RECT 26.050 12.600 28.550 29.050 ;
        RECT 23.350 26.550 28.550 29.050 ;
        RECT 23.350 26.550 25.850 38.200 ;
  END 
END OR3101






macro OR4101
  CLASS  CORE ;
  FOREIGN OR4101 0.000 0.000 ;
  ORIGIN 0.000 0.000 ;
  SIZE 33.600 BY 48.700 ;
  SYMMETRY X Y  ;
  SITE CORE ;
  PIN OUT1
    DIRECTION OUTPUT ;
    PORT
      LAYER metal1 ;
        RECT 30.250 25.200 32.750 27.700 ;
    END
  END OUT1
  PIN VSS
    DIRECTION INOUT ;
    USE GROUND ;
    SHAPE ABUTMENT ;
    PORT
      LAYER metal1 ;
        RECT 0.850 0.000 4.000 13.800 ;
        RECT 0.000 0.000 33.600 9.000 ;
        RECT 23.000 0.000 26.150 13.000 ;
        RECT 11.450 0.000 14.350 13.800 ;
    END
  END VSS
  PIN IN1
    DIRECTION INPUT ;
    PORT
      LAYER metal1 ;
        RECT 21.850 25.200 24.350 27.700 ;
    END
  END IN1
  PIN IN2
    DIRECTION INPUT ;
    PORT
      LAYER metal1 ;
        RECT 26.050 21.000 28.550 23.500 ;
    END
  END IN2
  PIN IN3
    DIRECTION INPUT ;
    PORT
      LAYER metal1 ;
        RECT 13.450 29.400 15.950 31.900 ;
    END
  END IN3
  PIN IN4
    DIRECTION INPUT ;
    PORT
      LAYER metal1 ;
        RECT 5.050 23.000 7.550 25.500 ;
    END
  END IN4
  PIN VDD
    DIRECTION INOUT ;
    USE POWER ;
    SHAPE ABUTMENT ;
    PORT
      LAYER metal1 ;
        RECT 18.750 32.300 22.150 48.700 ;
        RECT 0.000 39.700 33.600 48.700 ;
    END
  END VDD
  OBS 
     
      LAYER metal1 ;
        RECT 5.250 19.300 7.750 25.500 ;
        RECT 5.050 23.000 7.750 25.500 ;
        RECT 9.250 23.500 11.750 31.900 ;
        RECT 9.250 29.400 15.950 31.900 ;
        RECT 21.400 25.200 24.350 28.200 ;
        RECT 16.850 25.600 24.350 28.200 ;
        RECT 6.150 10.500 9.100 17.800 ;
        RECT 16.550 10.500 19.400 17.800 ;
        RECT 0.850 15.300 19.400 17.800 ;
        RECT 0.850 15.350 25.100 17.800 ;
        RECT 22.600 15.350 25.100 19.700 ;
        RECT 0.850 15.300 3.350 38.200 ;
        RECT 0.850 28.800 3.750 38.200 ;
        RECT 13.850 21.000 16.950 23.650 ;
        RECT 26.050 21.000 28.550 23.650 ;
        RECT 13.850 21.250 28.550 23.650 ;
        RECT 28.100 10.500 32.750 16.000 ;
        RECT 30.250 10.500 32.750 38.200 ;
        RECT 24.550 29.700 32.750 38.200 ;
  END 
END OR4101









macro OR5101
  CLASS  CORE ;
  FOREIGN OR5101 0.000 0.000 ;
  ORIGIN 0.000 0.000 ;
  SIZE 58.800 BY 48.700 ;
  SYMMETRY X Y  ;
  SITE CORE ;
  PIN OUT1
    DIRECTION OUTPUT ;
    PORT
      LAYER metal1 ;
        RECT 55.450 21.000 57.950 23.500 ;
    END
  END OUT1
  PIN VSS
    DIRECTION INOUT ;
    USE GROUND ;
    SHAPE ABUTMENT ;
    PORT
      LAYER metal1 ;
        RECT 6.350 0.000 8.850 14.500 ;
        RECT 0.000 0.000 58.800 9.000 ;
        RECT 49.900 0.000 52.950 16.100 ;
        RECT 39.850 0.000 42.750 16.000 ;
        RECT 29.650 0.000 32.150 16.000 ;
        RECT 16.550 0.000 19.050 14.500 ;
    END
  END VSS
  PIN IN1
    DIRECTION INPUT ;
    PORT
      LAYER metal1 ;
        RECT 5.050 19.900 7.550 22.400 ;
    END
  END IN1
  PIN IN2
    DIRECTION INPUT ;
    PORT
      LAYER metal1 ;
        RECT 17.650 25.200 20.150 27.700 ;
    END
  END IN2
  PIN IN3
    DIRECTION INPUT ;
    PORT
      LAYER metal1 ;
        RECT 17.650 21.000 20.150 23.500 ;
    END
  END IN3
  PIN IN4
    DIRECTION INPUT ;
    PORT
      LAYER metal1 ;
        RECT 30.250 33.600 32.750 36.100 ;
    END
  END IN4
  PIN IN5
    DIRECTION INPUT ;
    PORT
      LAYER metal1 ;
        RECT 26.050 25.600 28.550 28.100 ;
    END
  END IN5
  PIN VDD
    DIRECTION INOUT ;
    USE POWER ;
    SHAPE ABUTMENT ;
    PORT
      LAYER metal1 ;
        RECT 13.650 29.700 16.150 48.700 ;
        RECT 0.000 39.700 58.800 48.700 ;
        RECT 49.350 26.700 52.350 48.700 ;
        RECT 25.850 29.700 28.350 48.700 ;
    END
  END VDD
  OBS 
      LAYER metal2 ;
        RECT 0.850 16.800 3.350 28.250 ;
        RECT 34.450 16.800 41.150 19.300 ;
        RECT 38.650 16.800 41.150 31.900 ;
      LAYER via1 ;
        RECT 1.350 26.250 2.850 27.750 ;
        RECT 1.350 17.300 2.850 18.800 ;
      
        RECT 35.250 17.300 36.750 18.800 ;
        RECT 39.150 29.900 40.650 31.400 ;
        
      LAYER metal1 ;
        RECT 0.850 25.200 3.350 38.200 ;
        RECT 0.850 26.700 3.750 38.200 ;
        RECT 5.050 19.900 7.550 23.500 ;
        RECT 0.850 21.000 7.550 23.500 ;
        RECT 9.750 20.500 12.250 27.700 ;
        RECT 9.750 25.200 20.150 27.700 ;
        RECT 14.150 21.000 20.150 23.500 ;
        RECT 0.850 10.500 3.750 18.400 ;
        RECT 11.450 10.500 13.950 18.400 ;
        RECT 0.850 16.000 22.850 18.400 ;
        RECT 0.850 10.500 3.350 19.300 ;
        RECT 20.350 16.000 22.850 19.300 ;
        RECT 26.050 25.600 33.050 28.100 ;
        RECT 34.750 10.500 37.250 20.000 ;
        RECT 28.250 17.500 37.250 20.000 ;
        RECT 34.600 25.400 39.150 27.900 ;
        RECT 34.600 25.400 37.150 36.100 ;
        RECT 30.250 33.600 37.150 36.100 ;
        RECT 38.650 29.400 41.150 38.200 ;
        RECT 21.550 11.550 26.750 14.050 ;
        RECT 39.950 17.500 43.350 20.000 ;
        RECT 24.350 11.550 26.750 23.900 ;
        RECT 21.650 21.050 26.750 23.900 ;
        RECT 39.950 17.500 42.450 23.900 ;
        RECT 21.650 21.500 42.450 23.900 ;
        RECT 21.650 21.050 24.050 37.200 ;
        RECT 19.350 31.700 24.050 37.200 ;
        RECT 44.950 20.400 53.450 23.000 ;
        RECT 44.950 10.500 47.450 38.200 ;
        RECT 43.950 29.600 47.450 38.200 ;
        RECT 55.050 10.500 57.950 38.200 ;
  END 
END OR5101





macro OR7101
  CLASS  CORE ;
  FOREIGN OR7101 0.000 0.000 ;
  ORIGIN 0.000 0.000 ;
  SIZE 67.200 BY 48.700 ;
  SYMMETRY X Y  ;
  SITE CORE ;
  PIN OUT1
    DIRECTION OUTPUT ;
    PORT
      LAYER metal1 ;
        RECT 63.850 21.000 66.350 23.500 ;
    END
  END OUT1
  PIN VSS
    DIRECTION INOUT ;
    USE GROUND ;
    SHAPE ABUTMENT ;
    PORT
      LAYER metal1 ;
        RECT 6.550 0.000 9.050 13.500 ;
        RECT 0.000 0.000 67.200 9.000 ;
        RECT 57.050 0.000 59.550 15.000 ;
        RECT 37.350 0.000 39.850 13.500 ;
        RECT 27.150 0.000 29.650 13.500 ;
        RECT 16.750 0.000 19.250 13.500 ;
    END
  END VSS
  PIN IN1
    DIRECTION INPUT ;
    PORT
      LAYER metal1 ;
        RECT 34.450 28.700 36.950 31.200 ;
        
    END
  END IN1
  PIN IN2
    DIRECTION INPUT ;
    PORT
      LAYER metal1 ;
        RECT 33.450 19.000 35.950 21.500 ;
       
    END
  END IN2
  PIN IN3
    DIRECTION INPUT ;
    PORT
      LAYER metal1 ;
        RECT 26.050 20.800 28.550 23.300 ;
    END
  END IN3
  PIN IN4
    DIRECTION INPUT ;
    PORT
      LAYER metal1 ;
        RECT 17.650 24.200 20.150 26.700 ;
    END
  END IN4
  PIN IN5
    DIRECTION INPUT ;
    PORT
      LAYER metal1 ;
        RECT 0.850 24.700 3.350 27.200 ;
    END
  END IN5
  PIN IN6
    DIRECTION INPUT ;
    PORT
      LAYER metal1 ;
        RECT 9.250 22.300 11.750 24.800 ;
    END
  END IN6
  PIN VDD
    DIRECTION INOUT ;
    USE POWER ;
    SHAPE ABUTMENT ;
    PORT
      LAYER metal1 ;
        RECT 13.450 32.700 18.950 48.700 ;
        RECT 0.000 39.700 67.200 48.700 ;
        RECT 56.950 32.700 59.450 48.700 ;
        RECT 45.750 32.700 48.250 48.700 ;
    END
  END VDD
  PIN IN7
    DIRECTION INPUT ;
    PORT
      LAYER metal1 ;
        RECT 13.450 18.900 15.950 21.400 ;
    END
  END IN7
  OBS 
      LAYER metal2 ;
        RECT 21.850 16.500 24.350 35.200 ;
        RECT 51.250 20.500 53.750 35.200 ;
      LAYER via1 ;
        
        RECT 22.350 33.200 23.850 34.700 ;
        RECT 22.350 17.000 23.850 18.500 ;
        
        
        RECT 51.750 33.200 53.250 34.700 ;
        RECT 51.750 21.000 53.250 22.500 ;
       
      LAYER metal1 ;
        RECT 0.850 21.300 3.350 27.200 ;
        RECT 9.250 18.900 11.750 24.800 ;
        RECT 13.450 18.900 15.950 24.800 ;
        RECT 17.650 20.800 21.850 23.300 ;
        RECT 17.650 20.800 20.150 26.700 ;
        RECT 26.050 20.800 28.550 26.700 ;
        RECT 23.850 24.200 28.550 26.700 ;
        RECT 30.050 19.000 35.950 21.500 ;
        RECT 21.850 32.700 36.250 35.200 ;
        RECT 33.750 32.700 36.250 38.200 ;
        RECT 34.450 27.100 40.350 29.600 ;
        RECT 34.450 27.100 36.950 31.200 ;
        RECT 32.250 10.500 34.750 17.500 ;
        RECT 21.850 15.000 45.750 17.500 ;
        RECT 21.850 10.500 24.350 19.000 ;
        RECT 1.250 10.500 3.950 17.400 ;
        RECT 11.650 10.500 14.150 17.400 ;
        RECT 1.250 15.000 14.150 17.400 ;
        RECT 39.350 19.000 41.850 25.600 ;
        RECT 30.050 23.200 45.750 25.600 ;
        RECT 43.250 24.500 52.850 27.000 ;
        RECT 5.050 15.000 7.550 31.200 ;
        RECT 30.050 23.200 32.550 31.200 ;
        RECT 1.250 28.700 32.550 31.200 ;
        RECT 1.250 28.700 3.750 38.200 ;
        RECT 51.250 32.700 53.750 38.200 ;
        RECT 46.650 10.500 49.750 13.000 ;
        RECT 47.250 10.500 49.750 23.000 ;
        RECT 43.550 19.200 49.750 21.700 ;
        RECT 47.250 20.500 56.750 23.000 ;
        RECT 54.350 20.500 56.750 27.000 ;
        RECT 54.350 24.500 57.550 27.000 ;
        RECT 51.250 10.500 54.150 19.000 ;
        RECT 51.250 16.500 60.650 19.000 ;
        RECT 58.250 16.500 60.650 23.000 ;
        RECT 59.550 20.500 62.050 31.000 ;
        RECT 41.850 28.500 62.050 31.000 ;
        RECT 41.850 28.500 44.250 38.200 ;
        RECT 39.450 32.700 44.250 38.200 ;
        RECT 62.150 10.500 66.350 16.000 ;
        RECT 63.850 10.500 66.350 38.200 ;
        RECT 62.350 32.700 66.350 38.200 ;
  END 
END OR7101



macro OR8101
  CLASS  CORE ;
  FOREIGN OR8101 0.000 0.000 ;
  ORIGIN 0.000 0.000 ;
  SIZE 84.000 BY 48.700 ;
  SYMMETRY X Y  ;
  SITE CORE ;
  PIN OUT1
    DIRECTION OUTPUT ;
    PORT
      LAYER metal1 ;
        RECT 80.650 25.200 83.150 27.700 ;
    END
  END OUT1
  PIN VSS
    DIRECTION INOUT ;
    USE GROUND ;
    SHAPE ABUTMENT ;
    PORT
      LAYER metal1 ;
        RECT 8.350 0.000 10.850 12.500 ;
        RECT 0.000 0.000 84.000 9.000 ;
        RECT 75.050 0.000 77.550 14.700 ;
        RECT 56.000 0.000 58.500 15.550 ;
        RECT 44.100 0.000 46.600 12.500 ;
        RECT 33.850 0.000 36.350 12.500 ;
        RECT 18.600 0.000 21.100 12.500 ;
    END
  END VSS
  PIN IN1
    DIRECTION INPUT ;
    PORT
      LAYER metal1 ;
        RECT 0.850 21.000 3.350 23.500 ;
    END
  END IN1
  PIN IN2
    DIRECTION INPUT ;
    PORT
      LAYER metal1 ;
        RECT 9.250 21.000 11.750 23.500 ;
    END
  END IN2
  PIN IN3
    DIRECTION INPUT ;
    PORT
      LAYER metal1 ;
        RECT 13.450 21.000 15.950 23.500 ;
    END
  END IN3
  PIN IN4
    DIRECTION INPUT ;
    PORT
      LAYER metal1 ;
        RECT 21.850 25.200 24.350 27.700 ;
    END
  END IN4
  PIN IN5
    DIRECTION INPUT ;
    PORT
      LAYER metal1 ;
        RECT 30.250 21.000 32.750 23.500 ;
    END
  END IN5
  PIN IN6
    DIRECTION INPUT ;
    PORT
      LAYER metal1 ;
        RECT 34.450 21.000 36.950 23.500 ;
    END
  END IN6
  PIN VDD
    DIRECTION INOUT ;
    USE POWER ;
    SHAPE ABUTMENT ;
    PORT
      LAYER metal1 ;
        RECT 3.250 32.000 5.750 48.700 ;
        RECT 0.000 39.700 84.000 48.700 ;
        RECT 74.700 31.100 77.200 48.700 ;
        RECT 28.400 35.000 30.900 48.700 ;
    END
  END VDD
  PIN IN7
    DIRECTION INPUT ;
    PORT
      LAYER metal1 ;
        RECT 42.850 21.000 45.350 23.500 ;
    END
  END IN7
  PIN IN8
    DIRECTION INPUT ;
    PORT
      LAYER metal1 ;
        RECT 47.050 21.000 49.550 23.500 ;
    END
  END IN8
  OBS 
      
      LAYER metal1 ;
        RECT 0.850 21.000 3.600 28.150 ;
        RECT 9.250 18.000 11.750 23.500 ;
        RECT 13.450 21.000 15.950 28.300 ;
        RECT 12.950 25.100 15.950 28.300 ;
        RECT 19.900 18.050 22.400 27.700 ;
        RECT 19.900 25.200 24.350 27.700 ;
        RECT 30.250 21.000 32.900 28.300 ;
        RECT 34.450 21.000 37.100 23.500 ;
        RECT 34.600 21.000 37.100 28.250 ;
        RECT 39.150 21.000 45.350 23.500 ;
        RECT 47.050 18.000 49.550 23.500 ;
        RECT 3.250 10.500 5.750 16.450 ;
        RECT 13.450 10.500 15.950 16.450 ;
        RECT 23.750 10.500 26.500 16.450 ;
        RECT 3.250 14.050 26.500 16.450 ;
        RECT 24.000 10.500 26.500 23.700 ;
        RECT 40.400 25.550 50.950 27.950 ;
        RECT 48.450 26.150 59.650 28.650 ;
        RECT 25.850 21.250 28.350 33.450 ;
        RECT 19.250 29.500 28.350 33.450 ;
        RECT 40.400 25.550 42.850 33.450 ;
        RECT 19.250 31.050 42.850 33.450 ;
        RECT 19.250 29.500 21.750 38.000 ;
        RECT 28.750 10.500 31.250 16.400 ;
        RECT 38.950 10.500 41.450 16.400 ;
        RECT 49.250 10.500 51.750 16.400 ;
        RECT 28.750 14.000 54.450 16.400 ;
        RECT 52.050 14.000 54.450 20.100 ;
        RECT 52.050 17.700 63.750 20.100 ;
        RECT 61.250 17.700 63.750 32.600 ;
        RECT 44.400 30.150 63.750 32.600 ;
        RECT 44.400 29.500 46.900 38.000 ;
        RECT 64.000 10.550 67.800 16.100 ;
        RECT 65.250 10.550 67.800 38.100 ;
        RECT 53.300 35.400 67.800 38.100 ;
        RECT 69.300 12.350 72.400 14.850 ;
        RECT 69.300 25.200 78.950 27.700 ;
        RECT 69.300 12.350 71.800 38.100 ;
        RECT 80.150 10.850 83.150 16.350 ;
        RECT 80.650 10.850 83.150 38.100 ;
        RECT 79.900 29.250 83.150 38.100 ;
  END 
END OR8101









macro ORND01
  CLASS  CORE ;
  FOREIGN ORND01 0.000 0.000 ;
  ORIGIN 0.000 0.000 ;
  SIZE 29.400 BY 48.700 ;
  SYMMETRY X Y  ;
  SITE CORE ;
  PIN A
    DIRECTION INPUT ;
    PORT
      LAYER metal1 ;
        RECT 5.050 21.000 7.550 23.500 ;
    END
  END A
  PIN B
    DIRECTION INPUT ;
    PORT
      LAYER metal1 ;
        RECT 9.250 21.000 11.750 23.500 ;
    END
  END B
  PIN C
    DIRECTION INPUT ;
    PORT
      LAYER metal1 ;
        RECT 21.850 21.000 24.350 23.500 ;
    END
  END C
  PIN OUT1
    DIRECTION OUTPUT ;
    PORT
      LAYER metal1 ;
        RECT 26.050 21.000 28.550 23.500 ;
    END
  END OUT1
  PIN VSS
    DIRECTION INOUT ;
    USE GROUND ;
    SHAPE ABUTMENT ;
    PORT
      LAYER metal1 ;
        RECT 9.350 0.000 11.950 15.500 ;
        RECT 0.000 0.000 29.400 9.000 ;
    END
  END VSS
  PIN VDD
    DIRECTION INOUT ;
    USE POWER ;
    SHAPE ABUTMENT ;
    PORT
      LAYER metal1 ;
        RECT 8.750 30.000 11.250 48.700 ;
        RECT 0.000 39.700 29.400 48.700 ;
        RECT 25.550 30.000 28.050 48.700 ;
    END
  END VDD
  OBS 
      
      LAYER metal1 ;
        RECT 1.950 21.000 7.550 23.500 ;
        RECT 9.250 21.000 16.000 23.500 ;
        RECT 4.250 10.500 6.750 19.400 ;
        RECT 14.600 10.500 17.200 19.400 ;
        RECT 4.250 17.000 17.200 19.400 ;
        RECT 3.050 26.100 17.250 28.500 ;
        RECT 3.050 26.100 5.550 38.100 ;
        RECT 14.750 26.100 17.250 38.200 ;
        RECT 18.800 20.600 24.350 23.100 ;
        RECT 21.850 20.600 24.350 23.500 ;
        RECT 19.750 10.500 22.250 16.050 ;
        RECT 19.750 13.450 28.550 16.050 ;
        RECT 26.050 13.450 28.550 28.400 ;
        RECT 20.150 26.000 28.550 28.400 ;
        RECT 20.150 26.000 22.650 38.200 ;
  END 
END ORND01





macro TBUF01
  CLASS  CORE ;
  FOREIGN TBUF01 0.000 0.000 ;
  ORIGIN 0.000 0.000 ;
  SIZE 53.450 BY 48.700 ;
  SYMMETRY X Y  ;
  SITE CORE ;
  PIN OUT1
    DIRECTION OUTPUT TRISTATE ;
    PORT
      LAYER metal1 ;
        RECT 0.850 21.000 3.350 23.500 ;
    END
  END OUT1
  PIN EN
    DIRECTION INPUT ;
    PORT
      LAYER metal1 ;
        RECT 50.100 21.000 52.600 23.500 ;
    END
  END EN
  PIN VSS
    DIRECTION INOUT ;
    USE GROUND ;
    SHAPE ABUTMENT ;
    PORT
      LAYER metal1 ;
        RECT 6.350 0.000 8.850 12.450 ;
        RECT 0.000 0.000 53.450 9.000 ;
        RECT 48.350 0.000 50.850 15.550 ;
        RECT 38.000 0.000 40.500 13.100 ;
        RECT 16.500 0.000 19.050 13.000 ;
    END
  END VSS
  PIN IN1
    DIRECTION INPUT ;
    PORT
      LAYER metal1 ;
        RECT 21.850 20.000 24.350 22.500 ;
    END
  END IN1
  PIN VDD
    DIRECTION INOUT ;
    USE POWER ;
    SHAPE ABUTMENT ;
    PORT
      LAYER metal1 ;
        RECT 6.800 29.400 9.300 48.700 ;
        RECT 0.000 39.700 53.450 48.700 ;
        RECT 48.400 27.000 50.900 48.700 ;
        RECT 37.500 36.000 40.000 48.700 ;
        RECT 17.600 28.200 20.100 48.700 ;
    END
  END VDD
  OBS 
      LAYER metal2 ;
        RECT 43.000 16.500 45.550 26.700 ;
        RECT 43.000 16.500 45.500 29.200 ;
      LAYER via1 ;
        
        RECT 43.500 27.200 45.000 28.700 ;
        RECT 43.550 17.000 45.050 18.500 ;
        
      LAYER metal1 ;
        RECT 0.850 10.700 3.750 38.050 ;
        RECT 0.850 14.200 9.500 17.350 ;
        RECT 0.850 14.200 3.850 38.050 ;
        RECT 0.850 25.400 11.448 27.900 ;
        RECT 12.200 25.400 13.500 37.700 ;
        RECT 0.850 24.800 3.900 38.050 ;
        RECT 13.500 25.500 13.600 37.700 ;
        RECT 13.600 25.600 13.700 37.700 ;
        RECT 13.700 25.700 13.800 37.700 ;
        RECT 13.800 25.800 13.900 37.700 ;
        RECT 13.900 25.900 14.000 37.700 ;
        RECT 14.000 26.000 14.100 37.700 ;
        RECT 14.100 26.100 14.200 37.700 ;
        RECT 14.200 26.200 14.300 37.700 ;
        RECT 14.300 26.300 14.400 37.700 ;
        RECT 14.400 26.400 14.500 37.700 ;
        RECT 14.500 26.500 14.600 37.700 ;
        RECT 14.600 26.600 14.700 37.700 ;
        RECT 11.450 10.500 11.550 15.550 ;
        RECT 11.550 10.500 11.650 15.450 ;
        RECT 11.650 10.500 11.750 15.350 ;
        RECT 11.750 10.500 11.850 15.250 ;
        RECT 11.850 10.500 11.950 15.150 ;
        RECT 11.950 10.500 12.050 15.050 ;
        RECT 12.050 10.500 12.150 14.950 ;
        RECT 12.150 10.500 12.250 14.850 ;
        RECT 12.250 10.500 12.350 14.750 ;
        RECT 12.350 10.500 12.450 14.650 ;
        RECT 12.450 10.500 12.550 14.550 ;
        RECT 12.550 10.500 12.650 14.450 ;
        RECT 12.650 10.500 12.750 14.350 ;
        RECT 12.750 10.500 12.850 14.250 ;
        RECT 12.850 10.500 12.950 14.150 ;
        RECT 12.950 10.500 13.050 14.050 ;
        RECT 13.050 10.500 13.150 13.950 ;
        RECT 13.150 10.500 13.250 13.850 ;
        RECT 13.250 10.500 13.350 13.750 ;
        RECT 13.350 10.500 13.450 13.650 ;
        RECT 13.450 10.500 13.550 13.550 ;
        RECT 13.550 10.500 13.650 13.450 ;
        RECT 13.650 10.500 13.750 13.350 ;
        RECT 13.750 10.500 13.850 13.250 ;
        RECT 13.850 10.500 13.950 13.150 ;
        RECT 11.448 25.400 11.548 27.900 ;
        RECT 11.548 25.400 11.648 28.000 ;
        RECT 11.648 25.400 11.748 28.100 ;
        RECT 11.748 25.400 11.848 28.200 ;
        RECT 11.848 25.400 11.948 28.300 ;
        RECT 11.948 25.400 12.048 28.400 ;
        RECT 12.048 25.400 12.148 28.500 ;
        RECT 12.148 25.400 12.200 28.600 ;
        RECT 9.750 13.950 9.850 17.250 ;
        RECT 9.850 13.850 9.950 17.150 ;
        RECT 9.950 13.750 10.050 17.050 ;
        RECT 10.050 13.650 10.150 16.950 ;
        RECT 10.150 13.550 10.250 16.850 ;
        RECT 10.250 13.450 10.350 16.750 ;
        RECT 10.350 13.350 10.450 16.650 ;
        RECT 10.450 13.250 10.550 16.550 ;
        RECT 10.550 13.150 10.650 16.450 ;
        RECT 10.650 13.050 10.750 16.350 ;
        RECT 10.750 12.950 10.850 16.250 ;
        RECT 10.850 12.850 10.950 16.150 ;
        RECT 10.950 12.750 11.050 16.050 ;
        RECT 11.050 12.650 11.150 15.950 ;
        RECT 11.150 12.550 11.250 15.850 ;
        RECT 11.250 12.450 11.350 15.750 ;
        RECT 11.350 12.350 11.450 15.650 ;
        RECT 9.500 14.200 9.600 17.350 ;
        RECT 9.600 14.100 9.700 17.350 ;
        RECT 9.700 14.000 9.750 17.350 ;
        RECT 18.800 19.450 24.350 21.950 ;
        RECT 21.850 19.450 24.350 22.600 ;
        RECT 26.050 15.600 29.850 18.200 ;
        RECT 9.600 20.800 14.200 23.300 ;
        RECT 26.050 15.600 28.550 26.700 ;
        RECT 18.801 24.300 28.550 26.700 ;
        RECT 23.300 24.300 25.800 38.100 ;
        RECT 23.300 35.600 34.600 38.100 ;
        RECT 17.600 23.199 17.700 26.700 ;
        RECT 17.700 23.299 17.800 26.700 ;
        RECT 17.800 23.399 17.900 26.700 ;
        RECT 17.900 23.499 18.000 26.700 ;
        RECT 18.000 23.599 18.100 26.700 ;
        RECT 18.100 23.699 18.200 26.700 ;
        RECT 18.200 23.799 18.300 26.700 ;
        RECT 18.300 23.899 18.400 26.700 ;
        RECT 18.400 23.999 18.500 26.700 ;
        RECT 18.500 24.099 18.600 26.700 ;
        RECT 18.600 24.199 18.700 26.700 ;
        RECT 18.700 24.299 18.800 26.700 ;
        RECT 18.800 24.300 18.801 26.700 ;
        RECT 15.301 20.900 15.401 24.401 ;
        RECT 15.401 21.000 15.501 24.501 ;
        RECT 15.501 21.100 15.601 24.601 ;
        RECT 15.601 21.200 15.701 24.701 ;
        RECT 15.701 21.300 15.801 24.801 ;
        RECT 15.801 21.400 15.901 24.901 ;
        RECT 15.901 21.500 16.001 25.001 ;
        RECT 16.001 21.600 16.101 25.101 ;
        RECT 16.101 21.700 16.201 25.201 ;
        RECT 16.201 21.800 16.301 25.301 ;
        RECT 16.301 21.900 16.401 25.401 ;
        RECT 16.401 22.000 16.501 25.501 ;
        RECT 16.501 22.100 16.601 25.601 ;
        RECT 16.601 22.200 16.701 25.701 ;
        RECT 16.701 22.300 16.801 25.801 ;
        RECT 16.801 22.400 16.901 25.901 ;
        RECT 16.901 22.500 17.001 26.001 ;
        RECT 17.001 22.600 17.101 26.101 ;
        RECT 17.101 22.700 17.201 26.201 ;
        RECT 17.201 22.800 17.301 26.301 ;
        RECT 17.301 22.900 17.401 26.401 ;
        RECT 17.401 23.000 17.501 26.501 ;
        RECT 17.501 23.099 17.600 26.601 ;
        RECT 14.200 20.800 14.300 23.300 ;
        RECT 14.300 20.800 14.400 23.400 ;
        RECT 14.400 20.800 14.500 23.500 ;
        RECT 14.500 20.800 14.600 23.600 ;
        RECT 14.600 20.800 14.700 23.700 ;
        RECT 14.700 20.800 14.800 23.800 ;
        RECT 14.800 20.800 14.900 23.900 ;
        RECT 14.900 20.800 15.000 24.000 ;
        RECT 15.000 20.800 15.100 24.100 ;
        RECT 15.100 20.800 15.200 24.200 ;
        RECT 15.200 20.800 15.300 24.300 ;
        RECT 15.300 20.800 15.301 24.400 ;
        RECT 21.550 10.550 31.500 12.950 ;
        RECT 27.300 10.500 29.800 13.000 ;
        RECT 33.867 10.600 35.400 13.100 ;
        RECT 21.550 10.550 24.450 17.650 ;
        RECT 14.650 15.150 24.450 17.650 ;
        RECT 14.650 15.150 16.950 18.350 ;
        RECT 33.867 10.600 34.000 19.950 ;
        RECT 32.950 10.600 33.050 21.116 ;
        RECT 33.050 10.600 33.150 20.974 ;
        RECT 33.150 10.600 33.250 20.831 ;
        RECT 33.250 10.600 33.350 20.688 ;
        RECT 33.350 10.600 33.450 20.545 ;
        RECT 33.450 10.600 33.550 20.403 ;
        RECT 33.550 10.600 33.650 20.260 ;
        RECT 33.650 10.600 33.750 20.117 ;
        RECT 33.750 10.600 33.850 19.974 ;
        RECT 33.850 10.600 33.867 19.950 ;
        RECT 32.750 10.550 32.850 21.402 ;
        RECT 32.850 10.550 32.950 21.259 ;
        RECT 31.500 10.550 31.600 29.950 ;
        RECT 31.600 10.550 31.700 29.850 ;
        RECT 31.700 10.550 31.800 29.750 ;
        RECT 31.800 10.550 31.900 29.650 ;
        RECT 31.900 10.550 32.000 29.550 ;
        RECT 32.000 10.550 32.100 29.450 ;
        RECT 32.100 10.550 32.200 29.350 ;
        RECT 32.200 10.550 32.300 29.250 ;
        RECT 32.300 10.550 32.400 29.150 ;
        RECT 32.400 10.550 32.500 29.050 ;
        RECT 32.500 10.550 32.600 28.950 ;
        RECT 32.600 10.550 32.700 28.850 ;
        RECT 32.700 10.550 32.750 28.800 ;
        RECT 31.300 19.257 31.400 30.150 ;
        RECT 31.400 19.114 31.500 30.050 ;
        RECT 30.250 20.756 30.350 32.400 ;
        RECT 30.350 20.613 30.450 32.400 ;
        RECT 30.450 20.471 30.550 32.400 ;
        RECT 30.550 20.328 30.650 32.400 ;
        RECT 30.650 20.185 30.750 32.400 ;
        RECT 30.750 20.042 30.850 32.400 ;
        RECT 30.850 19.900 30.950 32.400 ;
        RECT 30.950 19.757 31.050 32.400 ;
        RECT 31.050 19.614 31.150 32.400 ;
        RECT 31.150 19.471 31.250 32.400 ;
        RECT 31.250 19.329 31.300 32.400 ;
        RECT 28.800 29.350 28.900 32.400 ;
        RECT 28.900 29.250 29.000 32.400 ;
        RECT 29.000 29.150 29.100 32.400 ;
        RECT 29.100 29.050 29.200 32.400 ;
        RECT 29.200 28.950 29.300 32.400 ;
        RECT 29.300 28.850 29.400 32.400 ;
        RECT 29.400 28.750 29.500 32.400 ;
        RECT 29.500 28.650 29.600 32.400 ;
        RECT 29.600 28.550 29.700 32.400 ;
        RECT 29.700 28.450 29.800 32.400 ;
        RECT 29.800 28.350 29.900 32.400 ;
        RECT 29.900 28.250 30.000 32.400 ;
        RECT 30.000 28.150 30.100 32.400 ;
        RECT 30.100 28.050 30.200 32.400 ;
        RECT 30.200 27.950 30.250 32.400 ;
        RECT 14.450 15.350 14.550 18.350 ;
        RECT 14.550 15.250 14.650 18.350 ;
        RECT 43.000 26.700 45.550 38.200 ;
        RECT 36.650 14.700 45.550 17.250 ;
        RECT 43.000 10.500 45.550 19.000 ;
        RECT 50.100 21.000 52.600 24.250 ;
        RECT 34.450 21.750 52.600 24.250 ;
        RECT 34.450 21.750 36.950 33.100 ;
        RECT 34.450 30.600 40.600 33.100 ;
  END 
END TBUF01








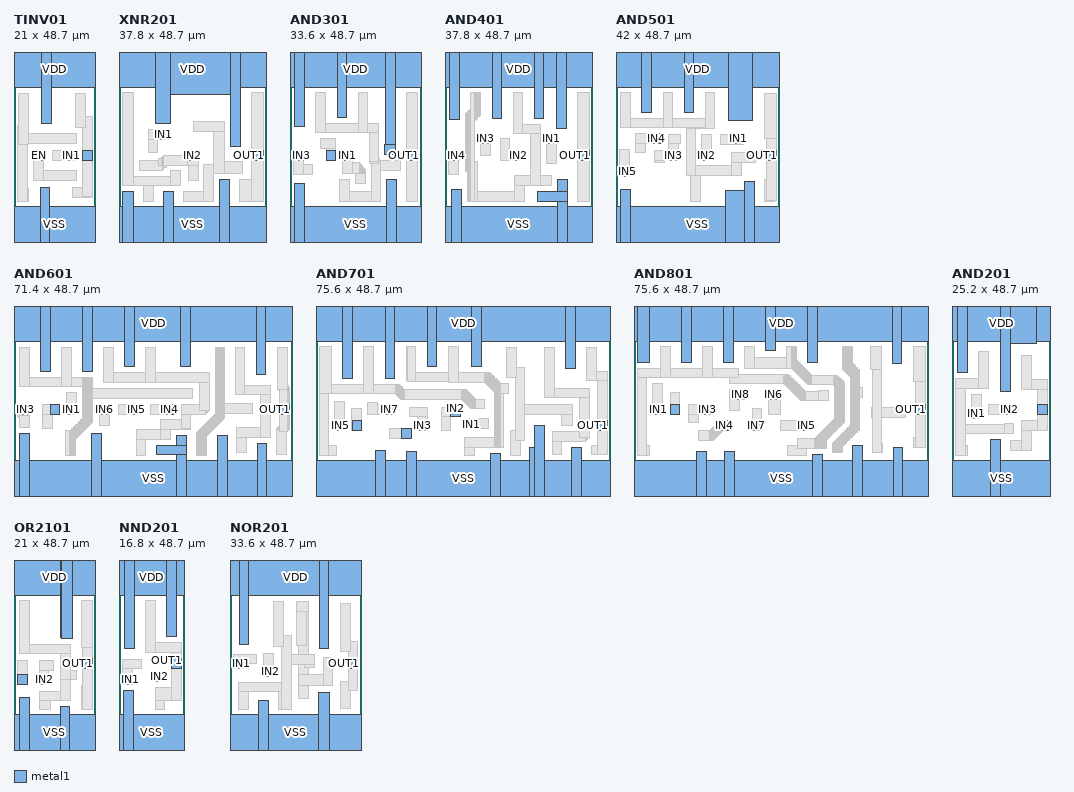
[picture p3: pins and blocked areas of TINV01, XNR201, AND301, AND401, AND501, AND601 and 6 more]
macro TINV01
  CLASS  CORE ;
  FOREIGN TINV01 0.000 0.000 ;
  ORIGIN 0.000 0.000 ;
  SIZE 21.000 BY 48.700 ;
  SYMMETRY X Y  ;
  SITE CORE ;
  PIN OUT1
    DIRECTION OUTPUT TRISTATE ;
    PORT
      LAYER metal1 ;
        RECT 17.650 21.000 20.150 23.500 ;
    END
  END OUT1
  PIN EN
    DIRECTION INPUT ;
    PORT
      LAYER metal1 ;
        RECT 5.050 21.000 7.550 23.500 ;
    END
  END EN
  PIN VSS
    DIRECTION INOUT ;
    USE GROUND ;
    SHAPE ABUTMENT ;
    PORT
      LAYER metal1 ;
        RECT 6.700 0.000 9.200 14.050 ;
        RECT 0.000 0.000 21.000 9.000 ;
    END
  END VSS
  PIN IN1
    DIRECTION INPUT ;
    PORT
      LAYER metal1 ;
        RECT 13.450 21.000 15.950 23.500 ;
    END
  END IN1
  PIN VDD
    DIRECTION INOUT ;
    USE POWER ;
    SHAPE ABUTMENT ;
    PORT
      LAYER metal1 ;
        RECT 7.000 30.300 9.500 48.700 ;
        RECT 0.000 39.700 21.000 48.700 ;
    END
  END VDD
  OBS 
      
      LAYER metal1 ;
        RECT 0.800 10.500 3.750 13.650 ;
        RECT 0.800 25.200 15.950 27.700 ;
        RECT 0.800 10.500 3.350 29.750 ;
        RECT 1.250 25.050 3.750 38.000 ;
        RECT 9.950 21.000 15.950 23.500 ;
        RECT 5.050 15.700 15.950 18.200 ;
        RECT 5.050 15.700 7.550 23.500 ;
        RECT 15.000 11.500 20.100 14.000 ;
        RECT 17.650 11.700 20.150 32.100 ;
        RECT 15.700 29.400 18.200 38.000 ;
  END 
END TINV01




macro XNR201
  CLASS  CORE ;
  FOREIGN XNR201 0.000 0.000 ;
  ORIGIN 0.000 0.000 ;
  SIZE 37.800 BY 48.700 ;
  SYMMETRY X Y  ;
  SITE CORE ;
  PIN OUT1
    DIRECTION OUTPUT ;
    PORT
      LAYER metal1 ;
        RECT 34.450 21.000 36.950 23.500 ;
    END
  END OUT1
  PIN VSS
    DIRECTION INOUT ;
    USE GROUND ;
    SHAPE ABUTMENT ;
    PORT
      LAYER metal1 ;
        RECT 0.850 0.000 3.750 13.000 ;
        RECT 0.000 0.000 37.800 9.000 ;
        RECT 25.750 0.000 28.250 16.000 ;
        RECT 11.450 0.000 13.950 13.000 ;
    END
  END VSS
  PIN IN1
    DIRECTION INPUT ;
    PORT
      LAYER metal1 ;
        RECT 10.150 26.400 12.650 28.900 ;
    END
  END IN1
  PIN IN2
    DIRECTION INPUT ;
    PORT
      LAYER metal1 ;
        RECT 17.650 21.000 20.150 23.500 ;
    END
  END IN2
  PIN VDD
    DIRECTION INOUT ;
    USE POWER ;
    SHAPE ABUTMENT ;
    PORT
      LAYER metal1 ;
        RECT 9.400 30.400 13.300 48.700 ;
        RECT 0.000 39.700 37.800 48.700 ;
        RECT 9.400 37.900 31.150 48.700 ;
        RECT 28.650 24.500 31.150 48.700 ;
    END
  END VDD
  OBS
      
      LAYER metal1 ;
        RECT 7.450 23.000 9.950 28.900 ;
        RECT 7.450 26.400 12.650 28.900 ;
        RECT 6.350 10.500 8.850 16.900 ;
        RECT 0.850 14.500 15.650 16.900 ;
        RECT 13.150 14.500 15.650 18.200 ;
        RECT 0.850 14.500 3.750 38.200 ;
        RECT 5.300 19.200 12.250 20.900 ;
        RECT 5.300 19.650 12.350 20.900 ;
        RECT 5.300 18.400 11.050 20.900 ;
        RECT 10.150 19.700 20.250 21.300 ;
        RECT 10.950 19.700 20.250 21.750 ;
        RECT 11.050 18.600 11.450 22.000 ;
        RECT 11.450 19.700 20.250 22.200 ;
        RECT 17.700 15.700 20.250 23.500 ;
        RECT 17.650 19.700 20.250 23.500 ;
        RECT 16.550 10.500 24.250 13.000 ;
        RECT 21.750 10.500 24.250 19.900 ;
        RECT 24.200 17.500 31.650 20.750 ;
        RECT 24.200 17.500 27.100 30.800 ;
        RECT 19.100 28.250 27.100 30.800 ;
        RECT 30.850 10.500 36.950 16.000 ;
        RECT 33.850 10.500 36.950 38.200 ;
  END
END XNR201

macro AND301
  CLASS  CORE ;
  FOREIGN AND301 0.000 0.000 ;
  ORIGIN 0.000 0.000 ;
  SIZE 33.600 BY 48.700 ;
  SYMMETRY X Y  ;
  SITE CORE ;
  PIN OUT1
    DIRECTION OUTPUT ;
    PORT
      LAYER metal1 ;
        RECT 30.250 21.000 32.750 23.500 ;
    END
  END OUT1
  PIN VSS
    DIRECTION INOUT ;
    USE GROUND ;
    SHAPE ABUTMENT ;
    PORT
      LAYER metal1 ;
        RECT 1.250 0.000 3.750 14.900 ;
        RECT 0.000 0.000 33.600 9.000 ;
        RECT 24.750 0.000 27.250 16.000 ;
    END
  END VSS
  PIN IN1
    DIRECTION INPUT ;
    PORT
      LAYER metal1 ;
        RECT 13.450 21.000 15.950 23.500 ;
    END
  END IN1
  PIN IN2
    DIRECTION INPUT ;
    PORT
      LAYER metal1 ;
        RECT 9.250 21.000 11.750 23.500 ;
    END
  END IN2
  PIN IN3
    DIRECTION INPUT ;
    PORT
      LAYER metal1 ;
        RECT 0.850 21.000 3.350 23.500 ;
    END
  END IN3
  PIN VDD
    DIRECTION INOUT ;
    USE POWER ;
    SHAPE ABUTMENT ;
    PORT
      LAYER metal1 ;
        RECT 0.000 39.700 33.600 48.700 ;
        RECT 24.450 22.500 26.950 48.700 ;
        RECT 24.150 22.500 26.950 25.000 ;
        RECT 12.050 31.900 14.550 48.700 ;
        RECT 1.250 29.700 3.800 48.700 ;
    END
  END VDD
  OBS 
      
      LAYER metal1 ;
        RECT 0.850 17.250 5.750 19.750 ;
        RECT 0.850 17.250 3.350 23.500 ;
        RECT 9.250 21.000 11.750 26.500 ;
        RECT 7.850 24.000 11.750 26.500 ;
        RECT 16.750 15.000 19.250 18.699 ;
        RECT 13.450 17.500 19.211 18.741 ;
        RECT 13.450 17.500 19.111 18.848 ;
        RECT 13.450 17.500 19.011 18.956 ;
        RECT 13.450 17.500 18.911 19.063 ;
        RECT 13.450 17.500 18.811 19.170 ;
        RECT 13.450 17.500 18.711 19.277 ;
        RECT 13.450 17.500 18.611 19.385 ;
        RECT 13.450 17.500 18.511 19.492 ;
        RECT 13.450 17.500 18.411 19.599 ;
        RECT 13.450 17.500 18.311 19.706 ;
        RECT 13.450 17.500 18.211 19.814 ;
        RECT 13.450 17.500 18.111 19.921 ;
        RECT 13.450 17.500 18.011 20.028 ;
        RECT 13.450 17.500 17.911 20.136 ;
        RECT 13.450 17.500 17.811 20.243 ;
        RECT 13.450 17.500 17.711 20.350 ;
        RECT 13.450 17.500 15.950 23.500 ;
        RECT 12.750 10.500 23.250 13.000 ;
        RECT 12.750 10.500 15.250 16.000 ;
        RECT 20.553 20.242 22.650 30.400 ;
        RECT 20.453 20.362 28.350 20.800 ;
        RECT 20.653 20.123 22.650 30.400 ;
        RECT 20.353 20.481 28.350 20.800 ;
        RECT 20.850 18.300 28.350 20.800 ;
        RECT 20.850 10.500 23.250 20.886 ;
        RECT 20.250 20.600 23.150 21.005 ;
        RECT 20.250 20.600 23.050 21.124 ;
        RECT 20.250 20.600 22.950 21.243 ;
        RECT 20.250 20.600 22.850 21.362 ;
        RECT 20.250 20.600 22.750 21.481 ;
        RECT 20.753 20.004 22.650 30.400 ;
        RECT 20.250 20.600 22.650 30.400 ;
        RECT 6.650 28.000 22.650 30.400 ;
        RECT 6.650 28.000 9.150 38.200 ;
        RECT 17.450 28.000 19.950 38.200 ;
        RECT 29.850 10.500 32.750 38.200 ;
  END 
END AND301


macro AND401
  CLASS  CORE ;
  FOREIGN AND401 0.000 0.000 ;
  ORIGIN 0.000 0.000 ;
  SIZE 37.800 BY 48.700 ;
  SYMMETRY X Y  ;
  SITE CORE ;
  PIN OUT1
    DIRECTION OUTPUT ;
    PORT
      LAYER metal1 ;
        RECT 34.450 21.000 36.950 23.500 ;
    END
  END OUT1
  PIN VSS
    DIRECTION INOUT ;
    USE GROUND ;
    SHAPE ABUTMENT ;
    PORT
      LAYER metal1 ;
        RECT 0.000 0.000 37.800 9.000 ;
        RECT 28.850 0.000 31.350 16.000 ;
        RECT 23.800 10.500 31.350 13.000 ;
        RECT 1.750 0.000 4.250 13.500 ;
    END
  END VSS
  PIN IN1
    DIRECTION INPUT ;
    PORT
      LAYER metal1 ;
        RECT 26.050 25.200 28.550 27.700 ;
    END
  END IN1
  PIN IN2
    DIRECTION INPUT ;
    PORT
      LAYER metal1 ;
        RECT 17.650 21.000 20.150 23.500 ;
    END
  END IN2
  PIN IN3
    DIRECTION INPUT ;
    PORT
      LAYER metal1 ;
        RECT 9.250 25.200 11.750 27.700 ;
    END
  END IN3
  PIN IN4
    DIRECTION INPUT ;
    PORT
      LAYER metal1 ;
        RECT 0.850 21.000 3.350 23.500 ;
    END
  END IN4
  PIN VDD
    DIRECTION INOUT ;
    USE POWER ;
    SHAPE ABUTMENT ;
    PORT
      LAYER metal1 ;
        RECT 1.250 31.450 3.750 48.700 ;
        RECT 0.000 39.700 37.800 48.700 ;
        RECT 28.550 29.200 31.050 48.700 ;
        RECT 22.850 31.700 25.350 48.700 ;
        RECT 12.050 31.700 14.550 48.700 ;
    END
  END VDD
  OBS 
     
      LAYER metal1 ;
        RECT 0.850 17.300 3.350 23.500 ;
        RECT 9.150 22.150 11.750 27.700 ;
        RECT 14.100 21.000 20.150 23.500 ;
        RECT 14.100 21.000 16.600 26.500 ;
        RECT 6.650 10.500 20.350 13.000 ;
        RECT 17.850 10.500 20.350 17.100 ;
        RECT 17.850 14.500 27.350 17.100 ;
        RECT 6.650 10.500 8.250 20.550 ;
        RECT 21.850 14.500 24.350 30.200 ;
        RECT 17.450 27.800 24.350 30.200 ;
        RECT 6.650 10.500 7.650 38.200 ;
        RECT 17.450 27.800 19.950 38.200 ;
        RECT 7.650 31.247 7.750 38.200 ;
        RECT 7.750 31.347 7.850 38.200 ;
        RECT 7.850 31.447 7.950 38.200 ;
        RECT 7.950 31.547 8.050 38.200 ;
        RECT 8.050 31.647 8.150 38.200 ;
        RECT 8.150 31.747 8.250 38.200 ;
        RECT 8.250 31.847 8.350 38.200 ;
        RECT 8.350 31.947 8.450 38.200 ;
        RECT 8.450 32.047 8.550 38.200 ;
        RECT 8.550 32.147 8.650 38.200 ;
        RECT 8.650 32.247 8.750 38.200 ;
        RECT 8.750 32.347 8.850 38.200 ;
        RECT 8.850 32.447 8.950 38.200 ;
        RECT 8.950 32.547 9.050 38.200 ;
        RECT 9.050 32.647 9.150 38.200 ;
        RECT 5.800 10.500 5.900 33.450 ;
        RECT 5.900 10.500 6.000 33.550 ;
        RECT 6.000 10.500 6.100 33.650 ;
        RECT 6.100 10.500 6.200 33.750 ;
        RECT 6.200 10.500 6.300 33.850 ;
        RECT 6.300 10.500 6.400 33.950 ;
        RECT 6.400 10.500 6.500 34.050 ;
        RECT 6.500 10.500 6.600 34.150 ;
        RECT 6.600 10.500 6.650 34.250 ;
        RECT 5.250 18.050 5.350 32.900 ;
        RECT 5.350 18.050 5.450 33.000 ;
        RECT 5.450 18.050 5.550 33.100 ;
        RECT 5.550 18.050 5.650 33.200 ;
        RECT 5.650 18.050 5.750 33.300 ;
        RECT 5.750 18.050 5.800 33.400 ;
        RECT 26.050 20.200 28.550 27.700 ;
        RECT 33.950 10.500 36.950 38.200 ;
  END 
END AND401



macro AND501
  CLASS  CORE ;
  FOREIGN AND501 0.000 0.000 ;
  ORIGIN 0.000 0.000 ;
  SIZE 42.000 BY 48.700 ;
  SYMMETRY X Y  ;
  SITE CORE ;
  PIN OUT1
    DIRECTION OUTPUT ;
    PORT
      LAYER metal1 ;
        RECT 38.650 21.000 41.150 23.500 ;
    END
  END OUT1
  PIN VSS
    DIRECTION INOUT ;
    USE GROUND ;
    SHAPE ABUTMENT ;
    PORT
      LAYER metal1 ;
        RECT 1.250 0.000 3.800 13.500 ;
        RECT 0.000 0.000 42.000 9.000 ;
        RECT 33.050 0.000 35.550 15.550 ;
        RECT 27.950 0.000 35.550 13.100 ;
    END
  END VSS
  PIN IN1
    DIRECTION INPUT ;
    PORT
      LAYER metal1 ;
        RECT 30.250 25.200 32.750 27.700 ;
    END
  END IN1
  PIN IN2
    DIRECTION INPUT ;
    PORT
      LAYER metal1 ;
        RECT 21.850 21.000 24.350 23.500 ;
    END
  END IN2
  PIN IN3
    DIRECTION INPUT ;
    PORT
      LAYER metal1 ;
        RECT 13.450 21.000 15.950 23.500 ;
    END
  END IN3
  PIN IN4
    DIRECTION INPUT ;
    PORT
      LAYER metal1 ;
        RECT 9.250 25.200 11.750 27.700 ;
    END
  END IN4
  PIN IN5
    DIRECTION INPUT ;
    PORT
      LAYER metal1 ;
        RECT 0.850 16.800 3.350 19.300 ;
    END
  END IN5
  PIN VDD
    DIRECTION INOUT ;
    USE POWER ;
    SHAPE ABUTMENT ;
    PORT
      LAYER metal1 ;
        RECT 6.650 33.200 9.150 48.700 ;
        RECT 0.000 39.700 42.000 48.700 ;
        RECT 28.850 31.250 34.950 48.700 ;
        RECT 17.450 33.150 19.950 48.700 ;
    END
  END VDD
  OBS 
      
      LAYER metal1 ;
        RECT 0.850 16.800 3.350 23.700 ;
        RECT 5.100 22.950 7.600 27.700 ;
        RECT 5.100 25.200 11.750 27.700 ;
        RECT 9.900 20.400 12.400 23.500 ;
        RECT 9.900 21.000 15.950 23.500 ;
        RECT 13.450 21.000 15.950 27.650 ;
        RECT 13.450 25.150 16.450 27.650 ;
        RECT 21.850 21.000 24.350 27.500 ;
        RECT 26.850 25.000 32.750 27.500 ;
        RECT 30.250 25.000 32.750 27.700 ;
        RECT 19.150 10.500 21.650 19.500 ;
        RECT 17.950 17.100 32.050 19.500 ;
        RECT 29.550 17.100 32.050 22.900 ;
        RECT 29.550 20.400 35.850 22.900 ;
        RECT 17.950 17.100 20.350 31.650 ;
        RECT 17.950 29.150 25.350 31.650 ;
        RECT 1.250 29.250 25.350 31.650 ;
        RECT 1.250 29.250 3.750 38.200 ;
        RECT 12.050 29.250 14.550 38.200 ;
        RECT 22.850 29.150 25.350 38.200 ;
        RECT 38.150 10.500 40.650 16.100 ;
        RECT 38.650 10.550 41.150 38.150 ;
        RECT 38.150 26.650 41.150 38.150 ;
  END 
END AND501



macro AND601
  CLASS  CORE ;
  FOREIGN AND601 0.000 0.000 ;
  ORIGIN 0.000 0.000 ;
  SIZE 71.400 BY 48.700 ;
  SYMMETRY X Y  ;
  SITE CORE ;
  PIN OUT1
    DIRECTION OUTPUT ;
    PORT
      LAYER metal1 ;
        RECT 68.050 21.000 70.550 23.500 ;
    END
  END OUT1
  PIN VSS
    DIRECTION INOUT ;
    USE GROUND ;
    SHAPE ABUTMENT ;
    PORT
      LAYER metal1 ;
        RECT 0.000 0.000 71.400 9.000 ;
        RECT 62.300 0.000 64.800 13.550 ;
        RECT 52.150 0.000 54.650 15.500 ;
        RECT 41.650 0.000 44.150 15.500 ;
        RECT 36.550 10.550 44.150 13.050 ;
        RECT 19.800 0.000 22.300 16.000 ;
        RECT 1.350 0.000 3.850 16.000 ;
    END
  END VSS
  PIN IN1
    DIRECTION INPUT ;
    PORT
      LAYER metal1 ;
        RECT 13.450 21.000 15.950 23.500 ;
    END
  END IN1
  PIN IN2
    DIRECTION INPUT ;
    PORT
      LAYER metal1 ;
        RECT 9.250 21.000 11.750 23.500 ;
    END
  END IN2
  PIN IN3
    DIRECTION INPUT ;
    PORT
      LAYER metal1 ;
        RECT 0.850 21.000 3.350 23.500 ;
    END
  END IN3
  PIN IN4
    DIRECTION INPUT ;
    PORT
      LAYER metal1 ;
        RECT 38.650 21.000 41.150 23.500 ;
    END
  END IN4
  PIN IN5
    DIRECTION INPUT ;
    PORT
      LAYER metal1 ;
        RECT 30.250 21.000 32.750 23.500 ;
    END
  END IN5
  PIN IN6
    DIRECTION INPUT ;
    PORT
      LAYER metal1 ;
        RECT 21.850 21.000 24.350 23.500 ;
    END
  END IN6
  PIN VDD
    DIRECTION INOUT ;
    USE POWER ;
    SHAPE ABUTMENT ;
    PORT
      LAYER metal1 ;
        RECT 6.800 32.000 9.300 48.700 ;
        RECT 0.000 39.700 71.400 48.700 ;
        RECT 62.050 31.150 64.550 48.700 ;
        RECT 42.650 33.150 45.150 48.700 ;
        RECT 28.400 33.150 30.900 48.700 ;
        RECT 17.600 32.000 20.100 48.700 ;
    END
  END VDD
  OBS 
     
      LAYER metal1 ;
        RECT 1.150 20.250 3.900 21.036 ;
        RECT 1.250 20.150 3.350 23.500 ;
        RECT 1.050 20.350 3.900 21.036 ;
        RECT 1.350 20.050 3.350 23.500 ;
        RECT 0.950 20.450 3.900 21.036 ;
        RECT 1.400 17.600 3.900 21.036 ;
        RECT 0.850 20.550 3.850 21.086 ;
        RECT 0.850 20.550 3.750 21.186 ;
        RECT 0.850 20.550 3.650 21.286 ;
        RECT 0.850 20.550 3.550 21.386 ;
        RECT 0.850 20.550 3.450 21.486 ;
        RECT 0.850 20.550 3.350 23.500 ;
        RECT 7.250 17.200 9.750 23.500 ;
        RECT 7.250 21.000 11.750 23.500 ;
        RECT 13.450 21.000 15.950 26.550 ;
        RECT 21.850 17.950 24.350 23.500 ;
        RECT 26.850 21.000 32.750 23.500 ;
        RECT 35.000 21.000 41.150 23.500 ;
        RECT 13.150 10.500 14.350 16.700 ;
        RECT 20.150 25.050 45.650 27.550 ;
        RECT 1.350 28.050 17.650 30.450 ;
        RECT 1.350 28.050 3.850 38.150 ;
        RECT 12.200 28.050 14.700 38.150 ;
        RECT 17.650 16.494 17.750 30.450 ;
        RECT 17.750 16.594 17.850 30.450 ;
        RECT 17.850 16.694 17.950 30.450 ;
        RECT 17.950 16.794 18.050 30.450 ;
        RECT 18.050 16.894 18.150 30.450 ;
        RECT 18.150 16.994 18.250 30.450 ;
        RECT 18.250 17.094 18.350 30.450 ;
        RECT 18.350 17.194 18.450 30.450 ;
        RECT 18.450 17.294 18.550 30.450 ;
        RECT 18.550 17.394 18.650 30.450 ;
        RECT 18.650 17.494 18.750 30.450 ;
        RECT 18.750 17.594 18.850 30.450 ;
        RECT 18.850 17.694 18.950 30.450 ;
        RECT 18.950 17.794 19.050 30.450 ;
        RECT 19.050 17.894 19.150 30.450 ;
        RECT 19.150 17.994 19.250 30.450 ;
        RECT 19.250 18.094 19.350 30.450 ;
        RECT 19.350 18.194 19.450 30.450 ;
        RECT 19.450 18.294 19.550 30.450 ;
        RECT 19.550 18.394 19.650 30.450 ;
        RECT 19.650 18.494 19.750 30.450 ;
        RECT 19.750 18.594 19.850 30.450 ;
        RECT 19.850 18.694 19.950 30.450 ;
        RECT 19.950 18.794 20.050 30.450 ;
        RECT 20.050 18.894 20.150 30.450 ;
        RECT 15.650 14.494 15.750 18.000 ;
        RECT 15.750 14.594 15.850 18.100 ;
        RECT 15.850 14.694 15.950 18.200 ;
        RECT 15.950 14.794 16.050 18.300 ;
        RECT 16.050 14.894 16.150 18.400 ;
        RECT 16.150 14.994 16.250 18.500 ;
        RECT 16.250 15.094 16.350 18.600 ;
        RECT 16.350 15.194 16.450 18.700 ;
        RECT 16.450 15.294 16.550 18.800 ;
        RECT 16.550 15.394 16.650 18.900 ;
        RECT 16.650 15.494 16.750 19.000 ;
        RECT 16.750 15.594 16.850 19.100 ;
        RECT 16.850 15.694 16.950 19.200 ;
        RECT 16.950 15.794 17.050 19.300 ;
        RECT 17.050 15.894 17.150 19.400 ;
        RECT 17.150 15.994 17.250 19.500 ;
        RECT 17.250 16.094 17.350 19.600 ;
        RECT 17.350 16.194 17.450 19.700 ;
        RECT 17.450 16.294 17.550 19.800 ;
        RECT 17.550 16.394 17.650 19.900 ;
        RECT 14.350 10.500 14.450 16.700 ;
        RECT 14.450 10.500 14.550 16.800 ;
        RECT 14.550 10.500 14.650 16.900 ;
        RECT 14.650 10.500 14.750 17.000 ;
        RECT 14.750 10.500 14.850 17.100 ;
        RECT 14.850 10.500 14.950 17.200 ;
        RECT 14.950 10.500 15.050 17.300 ;
        RECT 15.050 10.500 15.150 17.400 ;
        RECT 15.150 10.500 15.250 17.500 ;
        RECT 15.250 10.500 15.350 17.600 ;
        RECT 15.350 10.500 15.450 17.700 ;
        RECT 15.450 10.500 15.550 17.800 ;
        RECT 15.550 10.500 15.650 17.900 ;
        RECT 31.300 10.500 33.800 17.000 ;
        RECT 31.300 14.600 40.100 17.000 ;
        RECT 37.650 14.600 40.100 19.500 ;
        RECT 37.650 17.200 45.286 19.500 ;
        RECT 37.650 17.100 45.186 19.500 ;
        RECT 42.850 17.264 45.350 23.400 ;
        RECT 42.850 21.100 49.186 23.400 ;
        RECT 42.850 21.200 49.286 23.400 ;
        RECT 42.850 21.300 49.386 23.400 ;
        RECT 42.850 21.400 49.486 23.400 ;
        RECT 42.850 21.500 49.586 23.400 ;
        RECT 42.850 21.600 49.686 23.400 ;
        RECT 42.850 21.700 49.786 23.400 ;
        RECT 42.850 21.800 49.886 23.400 ;
        RECT 42.850 21.900 49.986 23.400 ;
        RECT 42.850 21.000 49.086 23.400 ;
        RECT 47.550 21.964 50.050 31.550 ;
        RECT 23.000 29.050 50.050 31.550 ;
        RECT 23.000 29.050 25.500 38.150 ;
        RECT 33.800 29.050 36.300 38.150 ;
        RECT 51.550 17.564 51.650 38.150 ;
        RECT 51.650 17.664 51.750 38.150 ;
        RECT 51.750 17.764 51.850 38.150 ;
        RECT 51.850 17.864 51.950 38.150 ;
        RECT 51.950 17.964 52.050 38.150 ;
        RECT 52.050 18.064 52.150 38.150 ;
        RECT 52.150 18.164 52.250 38.150 ;
        RECT 52.250 18.264 52.350 38.150 ;
        RECT 52.350 18.364 52.450 38.150 ;
        RECT 52.450 18.464 52.550 38.150 ;
        RECT 52.550 18.564 52.650 38.150 ;
        RECT 52.650 18.664 52.750 38.150 ;
        RECT 52.750 18.764 52.850 38.150 ;
        RECT 52.850 18.864 52.950 38.150 ;
        RECT 52.950 18.964 53.050 38.150 ;
        RECT 53.050 19.064 53.150 38.150 ;
        RECT 53.150 19.164 53.250 38.150 ;
        RECT 53.250 19.264 53.350 38.150 ;
        RECT 53.350 19.364 53.450 38.150 ;
        RECT 53.450 19.464 53.550 38.150 ;
        RECT 53.550 19.564 53.650 38.150 ;
        RECT 53.650 19.664 53.750 38.150 ;
        RECT 53.750 19.764 53.850 38.150 ;
        RECT 53.850 19.864 53.950 38.150 ;
        RECT 53.950 19.964 54.050 38.150 ;
        RECT 49.250 15.264 49.350 18.700 ;
        RECT 49.350 15.364 49.450 18.800 ;
        RECT 49.450 15.464 49.550 18.900 ;
        RECT 49.550 15.564 49.650 19.000 ;
        RECT 49.650 15.664 49.750 19.100 ;
        RECT 49.750 15.764 49.850 19.200 ;
        RECT 49.850 15.864 49.950 19.300 ;
        RECT 49.950 15.964 50.050 19.400 ;
        RECT 50.050 16.064 50.150 19.500 ;
        RECT 50.150 16.164 50.250 19.600 ;
        RECT 50.250 16.264 50.350 19.700 ;
        RECT 50.350 16.364 50.450 19.800 ;
        RECT 50.450 16.464 50.550 19.900 ;
        RECT 50.550 16.564 50.650 20.000 ;
        RECT 50.650 16.664 50.750 20.100 ;
        RECT 50.750 16.764 50.850 20.200 ;
        RECT 50.850 16.864 50.950 20.300 ;
        RECT 50.950 16.964 51.050 20.400 ;
        RECT 51.050 17.064 51.150 20.500 ;
        RECT 51.150 17.164 51.250 20.600 ;
        RECT 51.250 17.264 51.350 20.700 ;
        RECT 51.350 17.364 51.450 20.800 ;
        RECT 51.450 17.464 51.550 20.900 ;
        RECT 46.750 10.500 46.850 16.200 ;
        RECT 46.850 10.500 46.950 16.300 ;
        RECT 46.950 10.500 47.050 16.400 ;
        RECT 47.050 10.500 47.150 16.500 ;
        RECT 47.150 10.500 47.250 16.600 ;
        RECT 47.250 10.500 47.350 16.700 ;
        RECT 47.350 10.500 47.450 16.800 ;
        RECT 47.450 10.500 47.550 16.900 ;
        RECT 47.550 10.500 47.650 17.000 ;
        RECT 47.650 10.500 47.750 17.100 ;
        RECT 47.750 10.500 47.850 17.200 ;
        RECT 47.850 10.500 47.950 17.300 ;
        RECT 47.950 10.500 48.050 17.400 ;
        RECT 48.050 10.500 48.150 17.500 ;
        RECT 48.150 10.500 48.250 17.600 ;
        RECT 48.250 10.500 48.350 17.700 ;
        RECT 48.350 10.500 48.450 17.800 ;
        RECT 48.450 10.500 48.550 17.900 ;
        RECT 48.550 10.500 48.650 18.000 ;
        RECT 48.650 10.500 48.750 18.100 ;
        RECT 48.750 10.500 48.850 18.200 ;
        RECT 48.850 10.500 48.950 18.300 ;
        RECT 48.950 10.500 49.050 18.400 ;
        RECT 49.050 10.500 49.150 18.500 ;
        RECT 49.150 10.500 49.250 18.600 ;
        RECT 54.050 21.200 61.100 23.750 ;
        RECT 57.150 11.150 59.650 17.500 ;
        RECT 57.150 15.100 65.750 17.500 ;
        RECT 63.250 15.100 65.750 28.450 ;
        RECT 56.650 25.950 65.750 28.450 ;
        RECT 56.650 25.950 59.150 38.150 ;
        RECT 67.400 16.564 70.000 17.350 ;
        RECT 67.400 10.650 69.900 17.350 ;
        RECT 67.500 17.114 70.550 17.450 ;
        RECT 67.600 17.114 70.550 17.550 ;
        RECT 67.700 17.114 70.550 17.650 ;
        RECT 67.800 17.114 70.550 17.750 ;
        RECT 67.900 17.114 70.550 17.850 ;
        RECT 68.000 17.114 70.550 17.950 ;
        RECT 67.850 27.100 70.050 38.150 ;
        RECT 67.750 27.200 70.550 27.936 ;
        RECT 67.950 27.000 70.050 38.150 ;
        RECT 67.650 27.300 70.550 27.936 ;
        RECT 68.050 17.114 70.550 27.936 ;
        RECT 68.050 17.014 70.450 28.036 ;
        RECT 68.050 16.914 70.350 28.136 ;
        RECT 68.050 16.814 70.250 28.236 ;
        RECT 68.050 16.714 70.150 28.336 ;
        RECT 68.050 16.614 70.050 38.150 ;
        RECT 67.550 27.400 70.050 38.150 ;
  END 
END AND601





macro AND701
  CLASS  CORE ;
  FOREIGN AND701 0.000 0.000 ;
  ORIGIN 0.000 0.000 ;
  SIZE 75.600 BY 48.700 ;
  SYMMETRY X Y  ;
  SITE CORE ;
  PIN OUT1
    DIRECTION OUTPUT ;
    PORT
      LAYER metal1 ;
        RECT 72.250 16.800 74.750 19.300 ;
    END
  END OUT1
  PIN VSS
    DIRECTION INOUT ;
    USE GROUND ;
    SHAPE ABUTMENT ;
    PORT
      LAYER metal1 ;
        RECT 15.300 0.000 17.900 11.600 ;
        RECT 0.000 0.000 75.600 9.000 ;
        RECT 65.600 0.000 68.100 12.550 ;
        RECT 56.050 0.000 58.550 18.050 ;
        RECT 54.600 0.000 58.550 12.550 ;
        RECT 44.800 0.000 47.300 10.850 ;
        RECT 23.150 0.000 25.650 11.500 ;
    END
  END VSS
  PIN IN1
    DIRECTION INPUT ;
    PORT
      LAYER metal1 ;
        RECT 38.650 17.200 41.150 19.700 ;
    END
  END IN1
  PIN IN2
    DIRECTION INPUT ;
    PORT
      LAYER metal1 ;
        RECT 34.450 20.300 36.950 22.800 ;
    END
  END IN2
  PIN IN3
    DIRECTION INPUT ;
    PORT
      LAYER metal1 ;
        RECT 26.050 16.800 28.550 19.300 ;
    END
  END IN3
  PIN IN4
    DIRECTION INPUT ;
    PORT
      LAYER metal1 ;
        RECT 21.850 14.750 24.350 17.250 ;
    END
  END IN4
  PIN IN5
    DIRECTION INPUT ;
    PORT
      LAYER metal1 ;
        RECT 5.050 16.800 7.550 19.300 ;
    END
  END IN5
  PIN IN6
    DIRECTION INPUT ;
    PORT
      LAYER metal1 ;
        RECT 9.250 16.800 11.750 19.300 ;
    END
  END IN6
  PIN VDD
    DIRECTION INOUT ;
    USE POWER ;
    SHAPE ABUTMENT ;
    PORT
      LAYER metal1 ;
        RECT 6.900 30.200 9.400 48.700 ;
        RECT 0.000 39.700 75.600 48.700 ;
        RECT 64.050 32.650 66.550 48.700 ;
        RECT 39.900 33.150 42.400 48.700 ;
        RECT 28.500 33.200 31.000 48.700 ;
        RECT 17.700 30.200 20.200 48.700 ;
    END
  END VDD
  PIN IN7
    DIRECTION INPUT ;
    PORT
      LAYER metal1 ;
        RECT 17.650 21.000 20.150 23.500 ;
    END
  END IN7
  OBS 
    
      LAYER metal1 ;
        RECT 4.800 16.800 7.550 19.300 ;
        RECT 4.800 16.800 7.300 24.200 ;
        RECT 9.100 16.800 11.750 19.600 ;
        RECT 9.100 16.800 11.600 22.350 ;
        RECT 13.200 21.000 20.150 23.500 ;
        RECT 13.200 21.000 15.800 24.000 ;
        RECT 18.850 14.750 24.350 17.250 ;
        RECT 26.050 16.800 28.550 22.800 ;
        RECT 23.950 20.300 28.550 22.800 ;
        RECT 32.050 16.800 34.550 22.800 ;
        RECT 32.050 20.250 36.950 22.800 ;
        RECT 0.850 10.500 5.350 13.050 ;
        RECT 40.894 22.350 43.300 24.850 ;
        RECT 0.850 10.500 3.250 38.200 ;
        RECT 22.794 24.800 37.300 27.200 ;
        RECT 0.850 26.300 20.250 28.700 ;
        RECT 0.850 26.300 4.000 38.200 ;
        RECT 12.300 26.300 14.800 38.200 ;
        RECT 39.750 22.350 39.850 25.894 ;
        RECT 39.850 22.350 39.950 25.794 ;
        RECT 39.950 22.350 40.050 25.694 ;
        RECT 40.050 22.350 40.150 25.594 ;
        RECT 40.150 22.350 40.250 25.494 ;
        RECT 40.250 22.350 40.350 25.394 ;
        RECT 40.350 22.350 40.450 25.294 ;
        RECT 40.450 22.350 40.550 25.194 ;
        RECT 40.550 22.350 40.650 25.094 ;
        RECT 40.650 22.350 40.750 24.994 ;
        RECT 40.750 22.350 40.850 24.894 ;
        RECT 40.850 22.350 40.894 24.850 ;
        RECT 38.544 23.556 38.644 27.100 ;
        RECT 38.644 23.456 38.744 27.000 ;
        RECT 38.744 23.356 38.844 26.900 ;
        RECT 38.844 23.256 38.944 26.800 ;
        RECT 38.944 23.156 39.044 26.700 ;
        RECT 39.044 23.056 39.144 26.600 ;
        RECT 39.144 22.956 39.244 26.500 ;
        RECT 39.244 22.856 39.344 26.400 ;
        RECT 39.344 22.756 39.444 26.300 ;
        RECT 39.444 22.656 39.544 26.200 ;
        RECT 39.544 22.556 39.644 26.100 ;
        RECT 39.644 22.456 39.744 26.000 ;
        RECT 39.744 22.356 39.750 25.994 ;
        RECT 37.300 24.800 37.400 27.200 ;
        RECT 37.400 24.700 37.500 27.200 ;
        RECT 37.500 24.600 37.600 27.200 ;
        RECT 37.600 24.500 37.700 27.200 ;
        RECT 37.700 24.400 37.800 27.200 ;
        RECT 37.800 24.300 37.900 27.200 ;
        RECT 37.900 24.200 38.000 27.200 ;
        RECT 38.000 24.100 38.100 27.200 ;
        RECT 38.100 24.000 38.200 27.200 ;
        RECT 38.200 23.900 38.300 27.200 ;
        RECT 38.300 23.800 38.400 27.200 ;
        RECT 38.400 23.700 38.500 27.200 ;
        RECT 38.500 23.600 38.544 27.200 ;
        RECT 21.750 24.800 21.850 28.144 ;
        RECT 21.850 24.800 21.950 28.044 ;
        RECT 21.950 24.800 22.050 27.944 ;
        RECT 22.050 24.800 22.150 27.844 ;
        RECT 22.150 24.800 22.250 27.744 ;
        RECT 22.250 24.800 22.350 27.644 ;
        RECT 22.350 24.800 22.450 27.544 ;
        RECT 22.450 24.800 22.550 27.444 ;
        RECT 22.550 24.800 22.650 27.344 ;
        RECT 22.650 24.800 22.750 27.244 ;
        RECT 22.750 24.800 22.794 27.200 ;
        RECT 21.294 25.256 21.394 28.600 ;
        RECT 21.394 25.156 21.494 28.500 ;
        RECT 21.494 25.056 21.594 28.400 ;
        RECT 21.594 24.956 21.694 28.300 ;
        RECT 21.694 24.856 21.750 28.244 ;
        RECT 20.250 26.300 20.350 28.700 ;
        RECT 20.350 26.200 20.450 28.700 ;
        RECT 20.450 26.100 20.550 28.700 ;
        RECT 20.550 26.000 20.650 28.700 ;
        RECT 20.650 25.900 20.750 28.700 ;
        RECT 20.750 25.800 20.850 28.700 ;
        RECT 20.850 25.700 20.950 28.700 ;
        RECT 20.950 25.600 21.050 28.700 ;
        RECT 21.050 25.500 21.150 28.700 ;
        RECT 21.150 25.400 21.250 28.700 ;
        RECT 21.250 25.300 21.294 28.700 ;
        RECT 38.650 17.200 44.150 19.750 ;
        RECT 38.000 10.500 40.600 14.950 ;
        RECT 38.000 12.450 45.650 14.950 ;
        RECT 47.286 12.450 48.050 28.900 ;
        RECT 47.286 26.400 49.450 28.900 ;
        RECT 33.900 29.200 43.200 31.600 ;
        RECT 23.550 29.250 36.400 31.700 ;
        RECT 23.550 29.250 25.600 38.200 ;
        RECT 33.900 29.200 36.400 38.200 ;
        RECT 45.650 12.450 45.750 30.436 ;
        RECT 45.750 12.450 45.850 30.336 ;
        RECT 45.850 12.450 45.950 30.236 ;
        RECT 45.950 12.450 46.050 30.136 ;
        RECT 46.050 12.450 46.150 30.036 ;
        RECT 46.150 12.450 46.250 29.936 ;
        RECT 46.250 12.450 46.350 29.836 ;
        RECT 46.350 12.450 46.450 29.736 ;
        RECT 46.450 12.450 46.550 29.636 ;
        RECT 46.550 12.450 46.650 29.536 ;
        RECT 46.650 12.450 46.750 29.436 ;
        RECT 46.750 12.450 46.850 29.336 ;
        RECT 46.850 12.450 46.950 29.236 ;
        RECT 46.950 12.450 47.050 29.136 ;
        RECT 47.050 12.450 47.150 29.036 ;
        RECT 47.150 12.450 47.250 28.936 ;
        RECT 47.250 12.450 47.286 28.900 ;
        RECT 44.586 27.814 44.686 31.500 ;
        RECT 44.686 27.714 44.786 31.400 ;
        RECT 44.786 27.614 44.886 31.300 ;
        RECT 44.886 27.514 44.986 31.200 ;
        RECT 44.986 27.414 45.086 31.100 ;
        RECT 45.086 27.314 45.186 31.000 ;
        RECT 45.186 27.214 45.286 30.900 ;
        RECT 45.286 27.114 45.386 30.800 ;
        RECT 45.386 27.014 45.486 30.700 ;
        RECT 45.486 26.914 45.586 30.600 ;
        RECT 45.586 26.814 45.650 30.536 ;
        RECT 43.200 29.200 43.300 31.600 ;
        RECT 43.300 29.100 43.400 31.600 ;
        RECT 43.400 29.000 43.500 31.600 ;
        RECT 43.500 28.900 43.600 31.600 ;
        RECT 43.600 28.800 43.700 31.600 ;
        RECT 43.700 28.700 43.800 31.600 ;
        RECT 43.800 28.600 43.900 31.600 ;
        RECT 43.900 28.500 44.000 31.600 ;
        RECT 44.000 28.400 44.100 31.600 ;
        RECT 44.100 28.300 44.200 31.600 ;
        RECT 44.200 28.200 44.300 31.600 ;
        RECT 44.300 28.100 44.400 31.600 ;
        RECT 44.400 28.000 44.500 31.600 ;
        RECT 44.500 27.900 44.586 31.600 ;
        RECT 23.100 29.700 23.200 38.200 ;
        RECT 23.200 29.600 23.300 38.200 ;
        RECT 23.300 29.500 23.400 38.200 ;
        RECT 23.400 29.400 23.500 38.200 ;
        RECT 23.500 29.300 23.550 38.200 ;
        RECT 49.900 10.500 52.400 16.750 ;
        RECT 62.800 17.950 65.800 23.500 ;
        RECT 51.100 21.000 65.800 23.500 ;
        RECT 51.100 14.300 53.550 32.900 ;
        RECT 48.800 30.400 51.300 38.150 ;
        RECT 60.500 10.550 63.000 16.450 ;
        RECT 60.500 14.150 69.094 16.450 ;
        RECT 60.500 14.250 69.194 16.450 ;
        RECT 60.500 14.350 69.294 16.450 ;
        RECT 60.500 14.450 69.394 16.450 ;
        RECT 60.500 14.550 69.494 16.450 ;
        RECT 60.500 14.650 69.594 16.450 ;
        RECT 60.500 14.750 69.694 16.450 ;
        RECT 60.500 14.850 69.794 16.450 ;
        RECT 60.500 14.950 69.894 16.450 ;
        RECT 60.500 15.050 69.994 16.450 ;
        RECT 60.500 14.050 68.994 16.450 ;
        RECT 67.450 15.056 70.000 27.650 ;
        RECT 58.600 25.150 70.000 27.650 ;
        RECT 58.600 25.150 61.150 38.150 ;
        RECT 70.700 10.550 74.750 13.050 ;
        RECT 72.250 10.550 74.750 31.900 ;
        RECT 69.450 29.500 74.750 31.900 ;
        RECT 69.450 29.500 71.950 38.150 ;
  END 
END AND701



macro AND801
  CLASS  CORE ;
  FOREIGN AND801 0.000 0.000 ;
  ORIGIN 0.000 0.000 ;
  SIZE 75.600 BY 48.700 ;
  SYMMETRY X Y  ;
  SITE CORE ;
  PIN OUT1
    DIRECTION OUTPUT ;
    PORT
      LAYER metal1 ;
        RECT 72.250 21.000 74.750 23.500 ;
    END
  END OUT1
  PIN VSS
    DIRECTION INOUT ;
    USE GROUND ;
    SHAPE ABUTMENT ;
    PORT
      LAYER metal1 ;
        RECT 16.050 0.000 18.550 11.500 ;
        RECT 0.000 0.000 75.600 9.000 ;
        RECT 66.400 0.000 68.900 12.550 ;
        RECT 56.000 0.000 58.500 13.050 ;
        RECT 45.750 0.000 48.250 10.700 ;
        RECT 23.200 0.000 25.700 11.500 ;
    END
  END VSS
  PIN IN1
    DIRECTION INPUT ;
    PORT
      LAYER metal1 ;
        RECT 5.050 21.000 7.550 23.500 ;
    END
  END IN1
  PIN IN2
    DIRECTION INPUT ;
    PORT
      LAYER metal1 ;
        RECT 9.250 21.000 11.750 23.500 ;
    END
  END IN2
  PIN IN3
    DIRECTION INPUT ;
    PORT
      LAYER metal1 ;
        RECT 17.650 21.000 20.150 23.500 ;
    END
  END IN3
  PIN IN4
    DIRECTION INPUT ;
    PORT
      LAYER metal1 ;
        RECT 21.850 16.800 24.350 19.300 ;
    END
  END IN4
  PIN IN5
    DIRECTION INPUT ;
    PORT
      LAYER metal1 ;
        RECT 42.850 16.800 45.350 19.300 ;
    END
  END IN5
  PIN IN6
    DIRECTION INPUT ;
    PORT
      LAYER metal1 ;
        RECT 34.450 24.700 36.950 27.200 ;
    END
  END IN6
  PIN VDD
    DIRECTION INOUT ;
    USE POWER ;
    SHAPE ABUTMENT ;
    PORT
      LAYER metal1 ;
        RECT 0.850 34.300 3.850 48.700 ;
        RECT 0.000 39.700 75.600 48.700 ;
        RECT 66.150 33.850 68.650 48.700 ;
        RECT 44.550 34.300 47.050 48.700 ;
        RECT 33.750 37.250 36.300 48.700 ;
        RECT 22.950 34.300 25.450 48.700 ;
        RECT 12.150 34.300 14.650 48.700 ;
    END
  END VDD
  PIN IN7
    DIRECTION INPUT ;
    PORT
      LAYER metal1 ;
        RECT 30.250 16.800 32.750 19.300 ;
    END
  END IN7
  PIN IN8
    DIRECTION INPUT ;
    PORT
      LAYER metal1 ;
        RECT 26.050 24.800 28.550 27.300 ;
    END
  END IN8
  OBS 
    
      LAYER metal1 ;
        RECT 4.800 21.000 7.550 23.500 ;
        RECT 4.800 21.000 7.300 28.850 ;
        RECT 9.250 21.000 11.750 26.500 ;
        RECT 14.000 18.750 16.500 23.500 ;
        RECT 14.000 21.000 20.150 23.500 ;
        RECT 16.600 14.250 19.350 16.750 ;
        RECT 22.936 16.800 24.350 19.300 ;
        RECT 21.850 15.814 21.950 19.300 ;
        RECT 21.950 15.914 22.050 19.300 ;
        RECT 22.050 16.014 22.150 19.300 ;
        RECT 22.150 16.114 22.250 19.300 ;
        RECT 22.250 16.214 22.350 19.300 ;
        RECT 22.350 16.314 22.450 19.300 ;
        RECT 22.450 16.414 22.550 19.300 ;
        RECT 22.550 16.514 22.650 19.300 ;
        RECT 22.650 16.614 22.750 19.300 ;
        RECT 22.750 16.714 22.850 19.300 ;
        RECT 22.850 16.800 22.936 19.300 ;
        RECT 20.386 14.350 20.486 17.786 ;
        RECT 20.486 14.450 20.586 17.886 ;
        RECT 20.586 14.550 20.686 17.986 ;
        RECT 20.686 14.650 20.786 18.086 ;
        RECT 20.786 14.750 20.886 18.186 ;
        RECT 20.886 14.850 20.986 18.286 ;
        RECT 20.986 14.950 21.086 18.386 ;
        RECT 21.086 15.050 21.186 18.486 ;
        RECT 21.186 15.150 21.286 18.586 ;
        RECT 21.286 15.250 21.386 18.686 ;
        RECT 21.386 15.350 21.486 18.786 ;
        RECT 21.486 15.450 21.586 18.886 ;
        RECT 21.586 15.550 21.686 18.986 ;
        RECT 21.686 15.650 21.786 19.086 ;
        RECT 21.786 15.714 21.850 19.186 ;
        RECT 19.350 14.250 19.450 16.750 ;
        RECT 19.450 14.250 19.550 16.850 ;
        RECT 19.550 14.250 19.650 16.950 ;
        RECT 19.650 14.250 19.750 17.050 ;
        RECT 19.750 14.250 19.850 17.150 ;
        RECT 19.850 14.250 19.950 17.250 ;
        RECT 19.950 14.250 20.050 17.350 ;
        RECT 20.050 14.250 20.150 17.450 ;
        RECT 20.150 14.250 20.250 17.550 ;
        RECT 20.250 14.250 20.350 17.650 ;
        RECT 20.350 14.250 20.386 17.750 ;
        RECT 24.500 21.800 27.000 27.300 ;
        RECT 24.500 24.800 28.550 27.300 ;
        RECT 30.250 16.800 32.750 22.350 ;
        RECT 34.450 21.000 37.450 27.250 ;
        RECT 37.600 16.800 45.350 19.300 ;
        RECT 0.850 10.500 3.850 13.000 ;
        RECT 43.894 24.500 49.750 26.900 ;
        RECT 47.250 24.450 49.750 26.950 ;
        RECT 0.850 10.500 3.250 32.800 ;
        RECT 24.400 28.800 38.393 31.200 ;
        RECT 0.850 30.400 26.850 32.800 ;
        RECT 6.750 30.400 9.250 38.200 ;
        RECT 17.550 30.400 20.050 38.200 ;
        RECT 42.693 24.500 42.793 28.001 ;
        RECT 42.793 24.500 42.893 27.901 ;
        RECT 42.893 24.500 42.993 27.801 ;
        RECT 42.993 24.500 43.093 27.701 ;
        RECT 43.093 24.500 43.193 27.601 ;
        RECT 43.193 24.500 43.293 27.501 ;
        RECT 43.293 24.500 43.393 27.401 ;
        RECT 43.393 24.500 43.493 27.301 ;
        RECT 43.493 24.500 43.593 27.201 ;
        RECT 43.593 24.500 43.693 27.101 ;
        RECT 43.693 24.500 43.793 27.001 ;
        RECT 43.793 24.500 43.893 26.901 ;
        RECT 43.893 24.500 43.894 26.900 ;
        RECT 39.594 27.599 39.694 31.100 ;
        RECT 39.694 27.499 39.794 31.000 ;
        RECT 39.794 27.399 39.894 30.900 ;
        RECT 39.894 27.299 39.994 30.800 ;
        RECT 39.994 27.199 40.094 30.700 ;
        RECT 40.094 27.099 40.194 30.600 ;
        RECT 40.194 26.999 40.294 30.500 ;
        RECT 40.294 26.899 40.394 30.400 ;
        RECT 40.394 26.799 40.494 30.300 ;
        RECT 40.494 26.699 40.594 30.200 ;
        RECT 40.594 26.599 40.694 30.100 ;
        RECT 40.694 26.499 40.794 30.000 ;
        RECT 40.794 26.399 40.894 29.900 ;
        RECT 40.894 26.299 40.994 29.800 ;
        RECT 40.994 26.199 41.094 29.700 ;
        RECT 41.094 26.099 41.194 29.600 ;
        RECT 41.194 25.999 41.294 29.500 ;
        RECT 41.294 25.899 41.394 29.400 ;
        RECT 41.394 25.799 41.494 29.300 ;
        RECT 41.494 25.699 41.594 29.200 ;
        RECT 41.594 25.599 41.694 29.100 ;
        RECT 41.694 25.499 41.794 29.000 ;
        RECT 41.794 25.399 41.894 28.900 ;
        RECT 41.894 25.299 41.994 28.800 ;
        RECT 41.994 25.199 42.094 28.700 ;
        RECT 42.094 25.099 42.194 28.600 ;
        RECT 42.194 24.999 42.294 28.500 ;
        RECT 42.294 24.899 42.394 28.400 ;
        RECT 42.394 24.799 42.494 28.300 ;
        RECT 42.494 24.699 42.594 28.200 ;
        RECT 42.594 24.599 42.693 28.101 ;
        RECT 38.393 28.800 38.493 31.200 ;
        RECT 38.493 28.700 38.593 31.200 ;
        RECT 38.593 28.600 38.693 31.200 ;
        RECT 38.693 28.500 38.793 31.200 ;
        RECT 38.793 28.400 38.893 31.200 ;
        RECT 38.893 28.300 38.993 31.200 ;
        RECT 38.993 28.200 39.093 31.200 ;
        RECT 39.093 28.100 39.193 31.200 ;
        RECT 39.193 28.000 39.293 31.200 ;
        RECT 39.293 27.900 39.393 31.200 ;
        RECT 39.393 27.800 39.493 31.200 ;
        RECT 39.493 27.700 39.593 31.200 ;
        RECT 39.593 27.600 39.594 31.200 ;
        RECT 39.350 10.500 44.200 13.000 ;
        RECT 41.800 12.200 46.182 14.650 ;
        RECT 45.606 28.500 51.050 30.900 ;
        RECT 28.350 32.700 40.400 35.550 ;
        RECT 28.350 32.700 30.850 38.200 ;
        RECT 39.150 32.700 40.400 38.200 ;
        RECT 53.936 19.000 53.950 29.150 ;
        RECT 52.186 17.336 52.286 30.800 ;
        RECT 52.286 17.436 52.386 30.700 ;
        RECT 52.386 17.536 52.486 30.600 ;
        RECT 52.486 17.636 52.586 30.500 ;
        RECT 52.586 17.736 52.686 30.400 ;
        RECT 52.686 17.836 52.786 30.300 ;
        RECT 52.786 17.936 52.886 30.200 ;
        RECT 52.886 18.036 52.986 30.100 ;
        RECT 52.986 18.136 53.086 30.000 ;
        RECT 53.086 18.236 53.186 29.900 ;
        RECT 53.186 18.336 53.286 29.800 ;
        RECT 53.286 18.436 53.386 29.700 ;
        RECT 53.386 18.536 53.486 29.600 ;
        RECT 53.486 18.636 53.586 29.500 ;
        RECT 53.586 18.736 53.686 29.400 ;
        RECT 53.686 18.836 53.786 29.300 ;
        RECT 53.786 18.936 53.886 29.200 ;
        RECT 53.886 18.986 53.936 29.150 ;
        RECT 51.450 16.600 51.550 30.900 ;
        RECT 51.550 16.700 51.650 30.900 ;
        RECT 51.650 16.800 51.750 30.900 ;
        RECT 51.750 16.900 51.850 30.900 ;
        RECT 51.850 17.000 51.950 30.900 ;
        RECT 51.950 17.100 52.050 30.900 ;
        RECT 52.050 17.200 52.150 30.900 ;
        RECT 52.150 17.236 52.186 30.900 ;
        RECT 49.300 14.450 49.400 17.768 ;
        RECT 49.400 14.550 49.500 17.868 ;
        RECT 49.500 14.650 49.600 17.968 ;
        RECT 49.600 14.750 49.700 18.068 ;
        RECT 49.700 14.850 49.800 18.168 ;
        RECT 49.800 14.950 49.900 18.268 ;
        RECT 49.900 15.050 50.000 18.368 ;
        RECT 50.000 15.150 50.100 18.468 ;
        RECT 50.100 15.250 50.200 18.568 ;
        RECT 50.200 15.350 50.300 18.668 ;
        RECT 50.300 15.450 50.400 18.768 ;
        RECT 50.400 15.550 50.500 18.868 ;
        RECT 50.500 15.650 50.600 18.968 ;
        RECT 50.600 15.750 50.700 19.068 ;
        RECT 50.700 15.850 50.800 19.168 ;
        RECT 50.800 15.950 50.900 19.268 ;
        RECT 50.900 16.050 51.000 19.368 ;
        RECT 51.000 16.150 51.100 19.468 ;
        RECT 51.100 16.250 51.200 19.568 ;
        RECT 51.200 16.350 51.300 19.668 ;
        RECT 51.300 16.450 51.400 19.768 ;
        RECT 51.400 16.500 51.450 19.868 ;
        RECT 51.050 28.500 51.150 30.900 ;
        RECT 51.150 28.400 51.250 30.900 ;
        RECT 51.250 28.300 51.350 30.900 ;
        RECT 51.350 28.200 51.450 30.900 ;
        RECT 46.182 12.200 46.282 14.650 ;
        RECT 46.282 12.200 46.382 14.750 ;
        RECT 46.382 12.200 46.482 14.850 ;
        RECT 46.482 12.200 46.582 14.950 ;
        RECT 46.582 12.200 46.682 15.050 ;
        RECT 46.682 12.200 46.782 15.150 ;
        RECT 46.782 12.200 46.882 15.250 ;
        RECT 46.882 12.200 46.982 15.350 ;
        RECT 46.982 12.200 47.082 15.450 ;
        RECT 47.082 12.200 47.182 15.550 ;
        RECT 47.182 12.200 47.282 15.650 ;
        RECT 47.282 12.200 47.382 15.750 ;
        RECT 47.382 12.200 47.482 15.850 ;
        RECT 47.482 12.200 47.582 15.950 ;
        RECT 47.582 12.200 47.682 16.050 ;
        RECT 47.682 12.200 47.782 16.150 ;
        RECT 47.782 12.200 47.882 16.250 ;
        RECT 47.882 12.200 47.982 16.350 ;
        RECT 47.982 12.200 48.082 16.450 ;
        RECT 48.082 12.200 48.182 16.550 ;
        RECT 48.182 12.200 48.282 16.650 ;
        RECT 48.282 12.200 48.382 16.750 ;
        RECT 48.382 12.200 48.482 16.850 ;
        RECT 48.482 12.200 48.582 16.950 ;
        RECT 48.582 12.200 48.682 17.050 ;
        RECT 48.682 12.200 48.782 17.150 ;
        RECT 48.782 12.200 48.882 17.250 ;
        RECT 48.882 12.200 48.982 17.350 ;
        RECT 48.982 12.200 49.082 17.450 ;
        RECT 49.082 12.200 49.182 17.550 ;
        RECT 49.182 12.200 49.282 17.650 ;
        RECT 49.282 12.200 49.300 17.750 ;
        RECT 44.600 28.500 44.700 31.806 ;
        RECT 44.700 28.500 44.800 31.706 ;
        RECT 44.800 28.500 44.900 31.606 ;
        RECT 44.900 28.500 45.000 31.506 ;
        RECT 45.000 28.500 45.100 31.406 ;
        RECT 45.100 28.500 45.200 31.306 ;
        RECT 45.200 28.500 45.300 31.206 ;
        RECT 45.300 28.500 45.400 31.106 ;
        RECT 45.400 28.500 45.500 31.006 ;
        RECT 45.500 28.500 45.600 30.906 ;
        RECT 45.600 28.500 45.606 30.900 ;
        RECT 41.650 31.450 41.750 34.756 ;
        RECT 41.750 31.350 41.850 34.656 ;
        RECT 41.850 31.250 41.950 34.556 ;
        RECT 41.950 31.150 42.050 34.456 ;
        RECT 42.050 31.050 42.150 34.356 ;
        RECT 42.150 30.950 42.250 34.256 ;
        RECT 42.250 30.850 42.350 34.156 ;
        RECT 42.350 30.750 42.450 34.056 ;
        RECT 42.450 30.650 42.550 33.956 ;
        RECT 42.550 30.550 42.650 33.856 ;
        RECT 42.650 30.450 42.750 33.756 ;
        RECT 42.750 30.350 42.850 33.656 ;
        RECT 42.850 30.250 42.950 33.556 ;
        RECT 42.950 30.150 43.050 33.456 ;
        RECT 43.050 30.050 43.150 33.356 ;
        RECT 43.150 29.950 43.250 33.256 ;
        RECT 43.250 29.850 43.350 33.156 ;
        RECT 43.350 29.750 43.450 33.056 ;
        RECT 43.450 29.650 43.550 32.956 ;
        RECT 43.550 29.550 43.650 32.856 ;
        RECT 43.650 29.450 43.750 32.756 ;
        RECT 43.750 29.350 43.850 32.656 ;
        RECT 43.850 29.250 43.950 32.556 ;
        RECT 43.950 29.150 44.050 32.456 ;
        RECT 44.050 29.050 44.150 32.356 ;
        RECT 44.150 28.950 44.250 32.256 ;
        RECT 44.250 28.850 44.350 32.156 ;
        RECT 44.350 28.750 44.450 32.056 ;
        RECT 44.450 28.650 44.550 31.956 ;
        RECT 44.550 28.550 44.600 31.906 ;
        RECT 40.400 32.700 40.500 38.200 ;
        RECT 40.500 32.600 40.600 38.200 ;
        RECT 40.600 32.500 40.700 38.200 ;
        RECT 40.700 32.400 40.800 38.200 ;
        RECT 40.800 32.300 40.900 38.200 ;
        RECT 40.900 32.200 41.000 38.200 ;
        RECT 41.000 32.100 41.100 38.200 ;
        RECT 41.100 32.000 41.200 38.200 ;
        RECT 41.200 31.900 41.300 38.200 ;
        RECT 41.300 31.800 41.400 38.200 ;
        RECT 41.400 31.700 41.500 38.200 ;
        RECT 41.500 31.600 41.600 38.200 ;
        RECT 41.600 31.500 41.650 38.200 ;
        RECT 50.850 11.050 50.920 13.550 ;
        RECT 57.900 25.200 58.450 27.700 ;
        RECT 56.000 15.300 56.100 33.944 ;
        RECT 56.100 15.400 56.200 33.844 ;
        RECT 56.200 15.500 56.300 33.744 ;
        RECT 56.300 15.600 56.400 33.644 ;
        RECT 56.400 15.700 56.500 33.544 ;
        RECT 56.500 15.800 56.600 33.444 ;
        RECT 56.600 15.900 56.700 33.344 ;
        RECT 56.700 16.000 56.800 33.244 ;
        RECT 56.800 16.100 56.900 33.144 ;
        RECT 56.900 16.200 57.000 33.044 ;
        RECT 57.000 16.300 57.100 32.944 ;
        RECT 57.100 16.400 57.200 32.844 ;
        RECT 57.200 16.500 57.300 32.744 ;
        RECT 57.300 16.600 57.400 32.644 ;
        RECT 57.400 16.700 57.500 32.544 ;
        RECT 57.500 16.800 57.600 32.444 ;
        RECT 57.600 16.900 57.700 32.344 ;
        RECT 57.700 17.000 57.800 32.244 ;
        RECT 57.800 17.100 57.900 32.144 ;
        RECT 55.500 14.800 55.600 38.200 ;
        RECT 55.600 14.900 55.700 38.200 ;
        RECT 55.700 15.000 55.800 38.200 ;
        RECT 55.800 15.100 55.900 38.200 ;
        RECT 55.900 15.200 56.000 38.200 ;
        RECT 53.350 12.650 53.450 15.980 ;
        RECT 53.450 12.750 53.550 16.080 ;
        RECT 53.550 12.850 53.650 16.180 ;
        RECT 53.650 12.950 53.750 16.280 ;
        RECT 53.750 13.050 53.850 16.380 ;
        RECT 53.850 13.150 53.950 16.480 ;
        RECT 53.950 13.250 54.050 16.580 ;
        RECT 54.050 13.350 54.150 16.680 ;
        RECT 54.150 13.450 54.250 16.780 ;
        RECT 54.250 13.550 54.350 16.880 ;
        RECT 54.350 13.650 54.450 16.980 ;
        RECT 54.450 13.750 54.550 17.080 ;
        RECT 54.550 13.850 54.650 17.180 ;
        RECT 54.650 13.950 54.750 17.280 ;
        RECT 54.750 14.050 54.850 17.380 ;
        RECT 54.850 14.150 54.950 17.480 ;
        RECT 54.950 14.250 55.050 17.580 ;
        RECT 55.050 14.350 55.150 17.680 ;
        RECT 55.150 14.450 55.250 17.780 ;
        RECT 55.250 14.550 55.350 17.880 ;
        RECT 55.350 14.650 55.450 17.980 ;
        RECT 55.450 14.700 55.500 18.080 ;
        RECT 53.500 32.450 53.600 38.200 ;
        RECT 53.600 32.350 53.700 38.200 ;
        RECT 53.700 32.250 53.800 38.200 ;
        RECT 53.800 32.150 53.900 38.200 ;
        RECT 53.900 32.050 54.000 38.200 ;
        RECT 54.000 31.950 54.100 38.200 ;
        RECT 54.100 31.850 54.200 38.200 ;
        RECT 54.200 31.750 54.300 38.200 ;
        RECT 54.300 31.650 54.400 38.200 ;
        RECT 54.400 31.550 54.500 38.200 ;
        RECT 54.500 31.450 54.600 38.200 ;
        RECT 54.600 31.350 54.700 38.200 ;
        RECT 54.700 31.250 54.800 38.200 ;
        RECT 54.800 31.150 54.900 38.200 ;
        RECT 54.900 31.050 55.000 38.200 ;
        RECT 55.000 30.950 55.100 38.200 ;
        RECT 55.100 30.850 55.200 38.200 ;
        RECT 55.200 30.750 55.300 38.200 ;
        RECT 55.300 30.650 55.400 38.200 ;
        RECT 55.400 30.550 55.500 38.200 ;
        RECT 50.920 11.050 51.020 13.550 ;
        RECT 51.020 11.050 51.120 13.650 ;
        RECT 51.120 11.050 51.220 13.750 ;
        RECT 51.220 11.050 51.320 13.850 ;
        RECT 51.320 11.050 51.420 13.950 ;
        RECT 51.420 11.050 51.520 14.050 ;
        RECT 51.520 11.050 51.620 14.150 ;
        RECT 51.620 11.050 51.720 14.250 ;
        RECT 51.720 11.050 51.820 14.350 ;
        RECT 51.820 11.050 51.920 14.450 ;
        RECT 51.920 11.050 52.020 14.550 ;
        RECT 52.020 11.050 52.120 14.650 ;
        RECT 52.120 11.050 52.220 14.750 ;
        RECT 52.220 11.050 52.320 14.850 ;
        RECT 52.320 11.050 52.420 14.950 ;
        RECT 52.420 11.050 52.520 15.050 ;
        RECT 52.520 11.050 52.620 15.150 ;
        RECT 52.620 11.050 52.720 15.250 ;
        RECT 52.720 11.050 52.820 15.350 ;
        RECT 52.820 11.050 52.920 15.450 ;
        RECT 52.920 11.050 53.020 15.550 ;
        RECT 53.020 11.050 53.120 15.650 ;
        RECT 53.120 11.050 53.220 15.750 ;
        RECT 53.220 11.050 53.320 15.850 ;
        RECT 53.320 11.050 53.350 15.950 ;
        RECT 61.050 11.050 63.800 13.550 ;
        RECT 61.000 20.150 69.700 22.650 ;
        RECT 61.050 11.050 63.550 38.200 ;
        RECT 60.700 32.300 63.550 38.200 ;
        RECT 71.600 12.550 74.750 15.050 ;
        RECT 72.250 12.550 74.750 38.200 ;
        RECT 71.600 29.450 74.750 38.200 ;
  END 
END AND801





macro AND201
  CLASS  CORE ;
  FOREIGN AND201 0.000 0.000 ;
  ORIGIN 0.000 0.000 ;
  SIZE 25.200 BY 48.700 ;
  SYMMETRY X Y  ;
  SITE CORE ;
  PIN OUT1
    DIRECTION OUTPUT ;
    PORT
      LAYER metal1 ;
        RECT 21.850 21.000 24.350 23.500 ;
    END
  END OUT1
  PIN VSS
    DIRECTION INOUT ;
    USE GROUND ;
    SHAPE ABUTMENT ;
    PORT
      LAYER metal1 ;
        RECT 9.950 0.000 12.450 14.450 ;
        RECT 0.000 0.000 25.200 9.000 ;
    END
  END VSS
  PIN IN1
    DIRECTION INPUT ;
    PORT
      LAYER metal1 ;
        RECT 5.050 19.850 7.550 22.350 ;
    END
  END IN1
  PIN IN2
    DIRECTION INPUT ;
    PORT
      LAYER metal1 ;
        RECT 13.450 21.000 15.950 23.500 ;
    END
  END IN2
  PIN VDD
    DIRECTION INOUT ;
    USE POWER ;
    SHAPE ABUTMENT ;
    PORT
      LAYER metal1 ;
        RECT 1.350 31.550 3.850 48.700 ;
        RECT 0.000 39.700 25.200 48.700 ;
        RECT 12.450 39.150 21.750 48.700 ;
        RECT 12.450 26.750 14.950 48.700 ;
    END
  END VDD
  OBS 
      
      LAYER metal1 ;
        RECT 5.050 19.850 7.550 25.950 ;
        RECT 0.850 10.500 3.850 13.000 ;
        RECT 0.850 15.950 15.850 18.350 ;
        RECT 13.350 15.950 15.850 18.650 ;
        RECT 0.850 10.500 3.350 30.050 ;
        RECT 0.850 27.650 9.250 30.050 ;
        RECT 6.750 27.650 9.250 37.100 ;
        RECT 9.250 21.000 15.950 23.500 ;
        RECT 15.050 11.700 20.350 14.200 ;
        RECT 17.850 11.700 20.350 19.300 ;
        RECT 17.850 16.800 24.350 19.300 ;
        RECT 21.850 16.800 24.350 29.950 ;
        RECT 17.850 27.300 24.350 29.950 ;
        RECT 17.850 27.300 20.350 35.900 ;
  END 
END AND201

macro OR2101
  CLASS  CORE ;
  FOREIGN OR2101 0.000 0.000 ;
  ORIGIN 0.000 0.000 ;
  SIZE 21.000 BY 48.700 ;
  SYMMETRY X Y  ;
  SITE CORE ;
  PIN OUT1
    DIRECTION OUTPUT ;
    PORT
      LAYER metal1 ;
        RECT 17.650 21.000 20.150 23.500 ;
    END
  END OUT1
  PIN VSS
    DIRECTION INOUT ;
    USE GROUND ;
    SHAPE ABUTMENT ;
    PORT
      LAYER metal1 ;
        RECT 1.350 0.000 3.850 13.500 ;
        RECT 0.000 0.000 21.000 9.000 ;
        RECT 11.850 0.000 14.350 11.100 ;
    END
  END VSS
  PIN IN1
    DIRECTION INPUT ;
    PORT
      LAYER metal1 ;
        RECT 0.850 16.800 3.350 19.300 ;
    END
  END IN1
  PIN IN2
    DIRECTION INPUT ;
    PORT
      LAYER metal1 ;
        RECT 6.450 16.800 8.950 19.300 ;
    END
  END IN2
  PIN VDD
    DIRECTION INOUT ;
    USE POWER ;
    SHAPE ABUTMENT ;
    PORT
      LAYER metal1 ;
        RECT 12.050 28.754 14.950 48.700 ;
        RECT 0.000 39.700 21.000 48.700 ;
        RECT 11.850 28.954 14.950 48.700 ;
        RECT 12.104 28.700 14.950 48.700 ;
        RECT 11.950 28.854 14.950 48.700 ;
    END
  END VDD
  OBS 
      
      LAYER metal1 ;
        RECT 0.850 16.800 3.350 23.000 ;
        RECT 6.450 16.800 8.950 22.850 ;
        RECT 6.450 20.350 10.050 22.850 ;
        RECT 6.450 10.500 9.250 15.100 ;
        RECT 6.450 12.600 14.400 15.100 ;
        RECT 11.950 12.600 14.400 27.100 ;
        RECT 11.950 18.000 16.000 20.500 ;
        RECT 11.950 18.000 14.450 27.100 ;
        RECT 1.350 24.700 14.450 27.100 ;
        RECT 1.350 24.700 3.850 38.200 ;
        RECT 17.250 10.500 20.150 16.450 ;
        RECT 17.650 10.500 20.150 38.200 ;
        RECT 17.250 26.400 20.150 38.200 ;
  END 
END OR2101

macro NND201
  CLASS  CORE ;
  FOREIGN NND201 0.000 0.000 ;
  ORIGIN 0.000 0.000 ;
  SIZE 16.800 BY 48.700 ;
  SYMMETRY X Y  ;
  SITE CORE ;
  PIN OUT1
    DIRECTION OUTPUT ;
    PORT
      LAYER metal1 ;
        RECT 13.450 21.000 15.950 23.500 ;
    END
  END OUT1
  PIN VSS
    DIRECTION INOUT ;
    USE GROUND ;
    SHAPE ABUTMENT ;
    PORT
      LAYER metal1 ;
        RECT 1.250 0.000 3.750 15.300 ;
        RECT 0.000 0.000 16.800 9.000 ;
    END
  END VSS
  PIN IN1
    DIRECTION INPUT ;
    PORT
      LAYER metal1 ;
        RECT 0.850 16.800 3.350 19.300 ;
    END
  END IN1
  PIN IN2
    DIRECTION INPUT ;
    PORT
      LAYER metal1 ;
        RECT 9.250 17.500 11.750 20.000 ;
    END
  END IN2
  PIN VDD
    DIRECTION INOUT ;
    USE POWER ;
    SHAPE ABUTMENT ;
    PORT
      LAYER metal1 ;
        RECT 1.350 26.000 3.850 48.700 ;
        RECT 0.000 39.700 16.800 48.700 ;
        RECT 12.150 29.000 14.650 48.700 ;
    END
  END VDD
  OBS 
     
      LAYER metal1 ;
        RECT 0.850 16.800 3.350 23.300 ;
        RECT 0.850 20.800 5.850 23.300 ;
        RECT 9.250 10.500 11.750 16.000 ;
        RECT 9.250 12.600 15.950 16.000 ;
        RECT 13.450 12.600 15.950 27.500 ;
        RECT 6.750 25.000 15.950 27.500 ;
        RECT 6.750 25.000 9.250 38.200 ;
        
  END 
END NND201


macro NOR201
  CLASS  CORE ;
  FOREIGN NOR201 0.000 0.000 ;
  ORIGIN 0.000 0.000 ;
  SIZE 33.600 BY 48.700 ;
  SYMMETRY X Y  ;
  SITE CORE ;
  PIN OUT1
    DIRECTION OUTPUT ;
    PORT
      LAYER metal1 ;
        RECT 30.250 21.000 32.750 23.500 ;
    END
  END OUT1
  PIN VSS
    DIRECTION INOUT ;
    USE GROUND ;
    SHAPE ABUTMENT ;
    PORT
      LAYER metal1 ;
        RECT 7.300 0.000 9.800 12.750 ;
        RECT 0.000 0.000 33.600 9.000 ;
        RECT 22.750 0.000 25.600 14.650 ;
    END
  END VSS
  PIN IN1
    DIRECTION INPUT ;
    PORT
      LAYER metal1 ;
        RECT 0.850 21.000 3.350 23.500 ;
    END
  END IN1
  PIN IN2
    DIRECTION INPUT ;
    PORT
      LAYER metal1 ;
        RECT 9.250 18.800 11.750 21.300 ;
    END
  END IN2
  PIN VDD
    DIRECTION INOUT ;
    USE POWER ;
    SHAPE ABUTMENT ;
    PORT
      LAYER metal1 ;
        RECT 2.350 27.000 4.850 48.700 ;
        RECT 0.000 39.700 33.600 48.700 ;
        RECT 22.850 26.050 25.350 48.700 ;
    END
  END VDD
  OBS 
      LAYER metal2 ;
        RECT 17.650 15.750 20.150 38.100 ;
      LAYER via1 ;
      
        RECT 18.150 36.100 19.650 37.600 ;
        RECT 18.150 17.450 19.650 18.950 ;
        
      LAYER metal1 ;
        RECT 0.850 21.000 3.350 24.600 ;
        RECT 0.850 22.100 6.850 24.600 ;
        RECT 8.550 18.800 11.750 21.300 ;
        RECT 8.550 18.800 11.050 24.800 ;
        RECT 17.150 26.800 19.650 38.100 ;
        RECT 17.150 35.600 20.150 38.100 ;
        RECT 2.200 10.500 4.700 17.300 ;
        RECT 12.400 10.500 15.650 17.300 ;
        RECT 2.200 14.900 15.650 17.300 ;
        RECT 19.150 21.150 21.650 24.500 ;
        RECT 13.250 22.000 21.650 24.500 ;
        RECT 13.250 10.500 15.650 29.350 ;
        RECT 11.250 26.500 13.750 38.000 ;
        RECT 17.600 13.200 20.150 19.450 ;
        RECT 17.600 16.550 26.400 19.450 ;
        RECT 23.900 16.550 26.400 23.700 ;
        RECT 28.300 10.650 31.000 17.500 ;
        RECT 30.250 15.150 32.750 27.700 ;
        RECT 28.250 25.250 30.950 37.500 ;
  END 
END NOR201

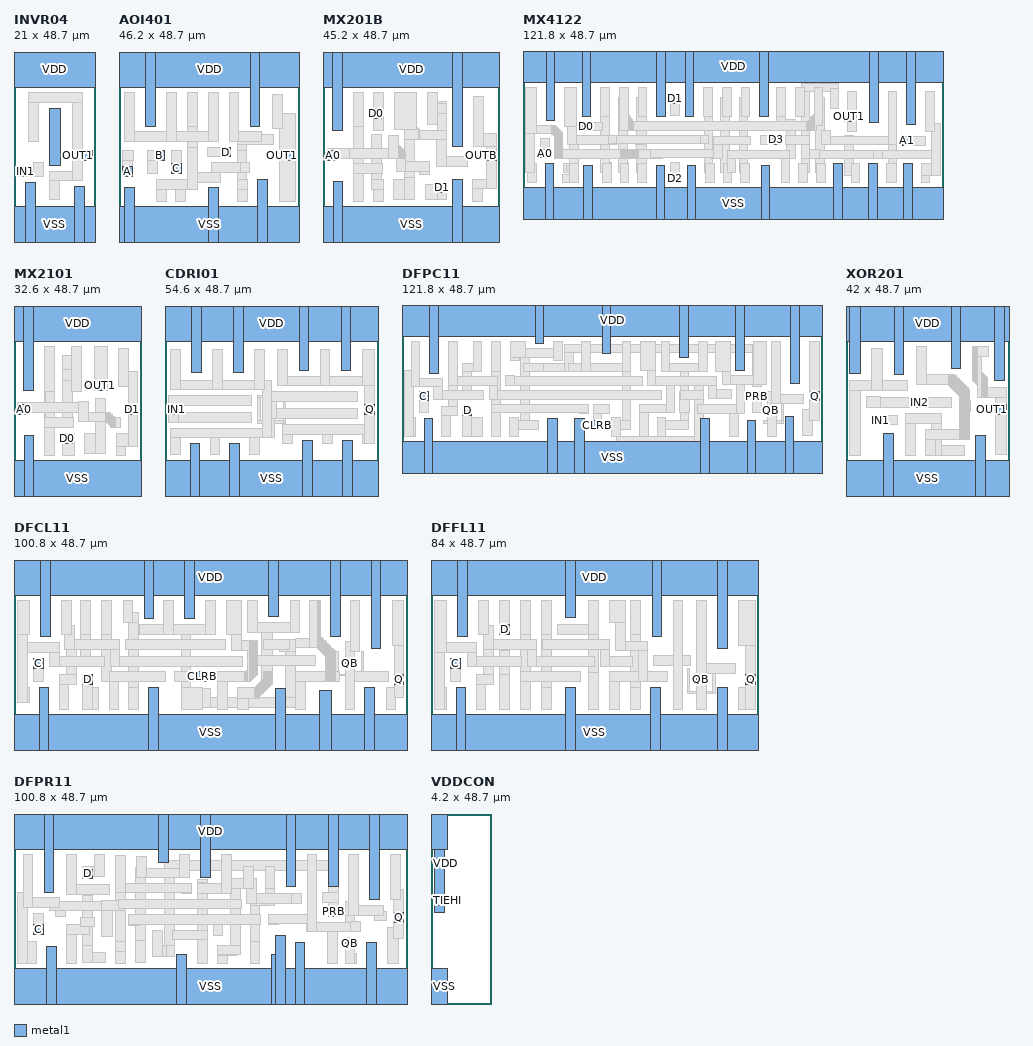
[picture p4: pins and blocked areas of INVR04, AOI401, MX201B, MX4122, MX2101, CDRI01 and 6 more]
macro INVR04
  CLASS  CORE ;
  FOREIGN INVR04 0.000 0.000 ;
  ORIGIN 0.000 0.000 ;
  SIZE 21.000 BY 48.700 ;
  SYMMETRY X Y  ;
  SITE CORE ;
  PIN OUT1
    DIRECTION OUTPUT ;
    PORT
      LAYER metal1 ;
        RECT 17.650 21.000 20.150 23.500 ;
    END
  END OUT1
  PIN VSS
    DIRECTION INOUT ;
    USE GROUND ;
    SHAPE ABUTMENT ;
    PORT
      LAYER metal1 ;
        RECT 2.950 0.000 5.450 15.300 ;
        RECT 0.000 0.000 21.000 9.000 ;
        RECT 15.500 0.000 18.000 14.250 ;
    END
  END VSS
  PIN IN1
    DIRECTION INPUT ;
    PORT
      LAYER metal1 ;
        RECT 0.850 16.800 3.350 19.300 ;
    END
  END IN1
  PIN VDD
    DIRECTION INOUT ;
    USE POWER ;
    SHAPE ABUTMENT ;
    PORT
      LAYER metal1 ;
        RECT 9.200 19.650 11.850 34.200 ;
        RECT 0.000 39.700 21.000 48.700 ;
    END
  END VDD
  OBS 
      
      LAYER metal1 ;
        RECT 0.850 16.800 7.650 19.300 ;
        RECT 4.900 16.800 7.650 20.350 ;
        RECT 9.200 10.950 11.700 18.150 ;
        RECT 9.200 15.750 17.600 18.150 ;
        RECT 15.100 21.000 20.150 23.500 ;
        RECT 3.700 25.650 6.200 38.200 ;
        RECT 15.100 15.750 17.600 38.200 ;
        RECT 3.700 35.700 17.600 38.200 ;
  END 
END INVR04

macro AOI401
  CLASS  CORE ;
  FOREIGN AOI401 0.000 0.000 ;
  ORIGIN 0.000 0.000 ;
  SIZE 46.200 BY 48.700 ;
  SYMMETRY X Y  ;
  SITE CORE ;
  PIN A
    DIRECTION INPUT ;
    PORT
      LAYER metal1 ;
        RECT 0.850 16.800 3.350 19.300 ;
    END
  END A
  PIN B
    DIRECTION INPUT ;
    PORT
      LAYER metal1 ;
        RECT 9.250 21.000 11.750 23.500 ;
    END
  END B
  PIN C
    DIRECTION INPUT ;
    PORT
      LAYER metal1 ;
        RECT 13.450 17.500 15.950 20.000 ;
    END
  END C
  PIN D
    DIRECTION INPUT ;
    PORT
      LAYER metal1 ;
        RECT 26.050 21.800 28.550 24.300 ;
    END
  END D
  PIN OUT1
    DIRECTION OUTPUT ;
    PORT
      LAYER metal1 ;
        RECT 42.850 21.000 45.350 23.500 ;
    END
  END OUT1
  PIN VSS
    DIRECTION INOUT ;
    USE GROUND ;
    SHAPE ABUTMENT ;
    PORT
      LAYER metal1 ;
        RECT 1.350 0.000 3.850 13.850 ;
        RECT 0.000 0.000 46.200 9.000 ;
        RECT 35.450 0.000 37.950 16.000 ;
        RECT 22.950 0.000 25.450 13.850 ;
    END
  END VSS
  PIN VDD
    DIRECTION INOUT ;
    USE POWER ;
    SHAPE ABUTMENT ;
    PORT
      LAYER metal1 ;
        RECT 6.850 29.700 9.350 48.700 ;
        RECT 0.000 39.700 46.200 48.700 ;
        RECT 33.600 29.700 36.100 48.700 ;
    END
  END VDD
  OBS 
     LAYER metal2 ;
        RECT 17.650 21.800 20.150 35.200 ;
        RECT 30.250 13.500 32.750 26.050 ;
      LAYER via1 ;
      
        RECT 18.150 33.200 19.650 34.700 ;
        RECT 18.150 22.300 19.650 23.800 ;
        
        RECT 30.750 24.050 32.250 25.550 ;
        RECT 30.750 14.000 32.250 15.500 ;
        
      LAYER metal1 ;
        RECT 0.850 16.800 3.350 23.500 ;
        RECT 0.850 21.000 3.600 23.500 ;
        RECT 7.300 17.550 9.800 20.050 ;
        RECT 7.350 17.550 9.800 23.500 ;
        RECT 7.350 21.000 11.750 23.500 ;
        RECT 13.450 17.500 15.950 23.500 ;
        RECT 17.650 29.700 20.150 38.200 ;
        RECT 1.450 25.800 25.550 28.200 ;
        RECT 1.450 25.800 3.950 38.200 ;
        RECT 12.250 25.800 14.750 38.200 ;
        RECT 23.050 25.800 25.550 38.200 ;
        RECT 22.650 21.800 28.550 24.300 ;
        RECT 30.350 10.500 32.850 16.000 ;
        RECT 30.250 13.500 32.850 16.000 ;
        RECT 9.650 10.500 12.150 16.000 ;
        RECT 14.600 10.500 17.150 16.000 ;
        RECT 9.650 13.500 20.150 16.000 ;
        RECT 17.650 15.350 26.050 17.900 ;
        RECT 23.650 17.900 33.550 20.300 ;
        RECT 31.050 17.900 33.550 20.450 ;
        RECT 17.650 13.500 20.150 24.300 ;
        RECT 30.250 23.550 32.750 28.200 ;
        RECT 30.250 25.000 39.500 27.500 ;
        RECT 28.200 25.800 36.650 28.200 ;
        RECT 28.200 25.800 30.700 38.200 ;
        RECT 41.050 10.500 45.350 32.900 ;
        RECT 39.300 29.200 41.800 37.700 ;
  END 
END AOI401



macro MX201B
  CLASS  CORE ;
  FOREIGN MX201B 0.000 0.000 ;
  ORIGIN 0.000 0.000 ;
  SIZE 45.200 BY 48.700 ;
  SYMMETRY X Y  ;
  SITE CORE ;
  PIN D0
    DIRECTION INPUT ;
    PORT
      LAYER metal1 ;
        RECT 12.450 31.700 14.950 34.200 ;
    END
  END D0
  PIN D1
    DIRECTION INPUT ;
    PORT
      LAYER metal1 ;
        RECT 29.250 12.600 31.750 15.100 ; 
    END
  END D1
  PIN A0
    DIRECTION INPUT ;
    PORT
      LAYER metal1 ;
        RECT 0.850 21.000 3.350 23.500 ;
    END
  END A0
  PIN OUTB
    DIRECTION OUTPUT ;
    PORT
      LAYER metal1 ;
        RECT 41.850 21.000 44.350 23.500 ;
    END
  END OUTB
  PIN VSS
    DIRECTION INOUT ;
    USE GROUND ;
    SHAPE ABUTMENT ;
    PORT
      LAYER metal1 ;
        RECT 2.600 0.000 5.100 15.550 ;
        RECT 0.000 0.000 45.200 9.000 ;
        RECT 33.300 0.000 35.800 16.000 ;
    END
  END VSS
  PIN VDD
    DIRECTION INOUT ;
    USE POWER ;
    SHAPE ABUTMENT ;
    PORT
      LAYER metal1 ;
        RECT 2.550 28.650 5.050 48.700 ;
        RECT 0.000 39.700 45.200 48.700 ;
        RECT 33.250 24.500 35.750 48.700 ;
    END
  END VDD
  OBS 
      LAYER metal2 ;
        RECT 7.900 16.500 10.400 32.200 ;
        RECT 7.900 29.700 10.450 32.200 ;
        RECT 12.450 13.500 14.950 27.502 ;
        RECT 20.850 14.150 23.350 28.650 ;
        RECT 29.250 19.298 31.75 36.100 ;
        
        
      LAYER via1 ;
      
        RECT 8.400 17.000 9.900 18.500 ;
        RECT 8.450 30.200 9.950 31.700 ;
        
        RECT 12.950 14.000 14.450 15.500 ;
        RECT 21.350 26.650 22.850 28.150 ;
        RECT 21.350 14.650 22.850 16.150 ;
        RECT 29.750 33.500 31.250 35.000 ;
        
        
      LAYER metal1 ;
        RECT 7.900 29.700 10.450 38.200 ;
        RECT 7.900 10.500 10.450 20.000 ;
        RECT 7.900 17.500 15.350 20.000 ;
        RECT 12.450 31.700 15.450 34.200 ;
        RECT 12.950 28.700 15.450 38.200 ;
        RECT 12.950 10.500 15.450 16.000 ;
        RECT 12.450 13.500 15.450 16.000 ;
        RECT 18.050 10.950 23.550 14.550 ;
        RECT 18.050 10.950 23.350 16.000 ;
        RECT 20.850 10.950 23.350 16.650 ;
        RECT 24.850 17.200 27.350 20.550 ;
        RECT 18.850 18.150 27.350 20.550 ;
        RECT 0.850 21.000 3.350 23.500 ;
        RECT 18.850 18.150 21.250 23.000 ;
        RECT 0.850 21.500 21.150 23.100 ;
        RECT 0.850 21.500 21.050 23.200 ;
        RECT 0.850 21.500 20.950 23.300 ;
        RECT 0.850 21.500 20.850 23.400 ;
        RECT 0.850 21.500 20.750 23.500 ;
        RECT 1.200 21.500 20.650 23.600 ;
        RECT 1.200 21.500 20.550 23.700 ;
        RECT 1.200 21.500 20.450 23.800 ;
        RECT 1.200 21.500 20.350 23.900 ;
        RECT 1.200 21.500 6.750 24.000 ;
        RECT 16.850 21.500 20.250 24.000 ;
        RECT 16.850 21.500 20.150 24.100 ;
        RECT 16.850 21.500 20.050 24.200 ;
        RECT 16.850 21.500 19.950 24.300 ;
        RECT 16.850 21.500 19.850 24.400 ;
        RECT 16.850 21.500 19.750 24.500 ;
        RECT 16.850 21.500 19.650 24.600 ;
        RECT 16.850 21.500 19.550 24.700 ;
        RECT 16.850 21.500 19.450 24.800 ;
        RECT 16.850 21.500 19.350 27.350 ;
        RECT 26.750 33.000 31.750 35.500 ;
        RECT 26.750 30.050 29.250 38.200 ;
        RECT 26.150 11.000 31.750 14.650 ;
        RECT 29.250 11.000 31.750 15.100 ;
        RECT 34.650 19.300 37.150 21.800 ;
        RECT 29.050 19.400 37.150 21.800 ;
        RECT 29.050 19.400 31.750 28.550 ;
        RECT 20.850 26.150 31.750 28.550 ;
        RECT 20.850 26.150 24.850 28.600 ;
        RECT 20.850 26.150 24.750 28.700 ;
        RECT 20.850 26.150 24.650 28.800 ;
        RECT 20.850 26.150 24.550 28.900 ;
        RECT 18.350 28.850 24.450 29.000 ;
        RECT 18.350 28.850 24.350 29.100 ;
        RECT 18.350 28.850 24.250 29.200 ;
        RECT 18.350 28.850 24.150 29.300 ;
        RECT 18.350 28.850 24.050 29.400 ;
        RECT 18.350 28.850 23.950 29.500 ;
        RECT 18.350 28.850 23.850 38.200 ;
        RECT 38.400 10.500 40.900 16.000 ;
        RECT 38.400 13.600 44.350 16.000 ;
        RECT 41.850 13.600 44.350 27.700 ;
        RECT 38.650 24.500 44.350 27.700 ;
        RECT 38.650 24.500 41.150 37.200 ;
  END 
END MX201B


macro MX4122
  CLASS  CORE ;
  FOREIGN MX4122 0.000 0.000 ;
  ORIGIN 0.000 0.000 ;
  SIZE 121.800 BY 48.700 ;
  SYMMETRY X Y  ;
  SITE CORE ;
  PIN D0
    DIRECTION INPUT ;
    PORT
      LAYER metal1 ;
        RECT 17.150 25.600 19.650 28.100 ;
        
    END
  END D0
  PIN OUT1
    DIRECTION OUTPUT ;
    PORT
      LAYER metal1 ;
        RECT 93.250 28.400 95.750 30.900 ;
        
    END
  END OUT1
  PIN A0
    DIRECTION INPUT ;
    PORT
      LAYER metal1 ;
        RECT 5.050 17.800 7.550 20.300 ;
    END
  END A0
  PIN D1
    DIRECTION INPUT ;
    PORT
      LAYER metal1 ;
        RECT 42.850 33.600 45.350 36.100 ;
    END
  END D1
  PIN D2
    DIRECTION INPUT ;
    PORT
      LAYER metal1 ;
        RECT 42.850 10.500 45.350 13.000 ;
    END
  END D2
  PIN A1
    DIRECTION INPUT ;
    PORT
      LAYER metal1 ;
        RECT 110.050 21.400 112.550 23.900 ;
    END
  END A1
  PIN D3
    DIRECTION INPUT ;
    PORT
      LAYER metal1 ;
       
        RECT 72.250 21.700 74.750 24.200 ;
    END
  END D3
  PIN VSS
    DIRECTION INOUT ;
    USE GROUND ;
    SHAPE ABUTMENT ;
    PORT
      LAYER metal1 ;
        RECT 6.450 0.000 8.950 16.000 ;
        RECT 0.000 0.000 121.800 9.000 ;
        RECT 110.400 0.000 112.900 16.000 ;
        RECT 100.300 0.000 102.800 16.000 ;
        RECT 90.100 0.000 92.600 16.000 ;
        RECT 69.050 0.000 71.550 15.550 ;
        RECT 47.600 0.000 50.100 15.550 ;
        RECT 38.650 0.000 41.150 15.550 ;
        RECT 17.650 0.000 20.150 15.550 ;
    END
  END VSS
  PIN VDD
    DIRECTION INOUT ;
    USE POWER ;
    SHAPE ABUTMENT ;
    PORT
      LAYER metal1 ;
        RECT 6.750 28.700 9.250 48.700 ;
        RECT 0.000 39.700 121.800 48.700 ;
        RECT 111.300 27.350 113.800 48.700 ;
        RECT 100.450 27.900 102.950 48.700 ;
        RECT 68.650 29.700 71.150 48.700 ;
        RECT 47.050 29.700 49.550 48.700 ;
        RECT 38.750 29.700 41.250 48.700 ;
        RECT 17.150 29.600 19.650 48.700 ;
    END
  END VDD
  OBS 
      LAYER metal2 ;
        RECT 11.803 13.550 13.450 16.050 ;
        RECT 13.450 13.550 15.950 24.100 ;
        RECT 22.600 13.500 25.550 16.250 ;
        RECT 22.600 13.500 25.100 35.100 ;
        RECT 22.550 32.100 25.100 35.100 ;
        RECT 27.700 13.500 30.650 16.250 ;
        RECT 27.700 13.500 30.200 35.200 ;
        RECT 27.700 32.700 30.450 35.200 ;
        RECT 32.800 13.500 35.750 35.100 ;
        RECT 33.350 32.700 35.850 35.200 ;
        RECT 52.500 13.500 55.500 16.000 ;
        RECT 52.500 13.500 55.000 35.200 ;
        RECT 52.450 32.100 55.000 35.200 ;
        RECT 57.300 13.500 60.600 16.000 ;
        RECT 57.300 13.500 59.800 35.200 ;
        RECT 57.300 32.700 60.350 35.200 ;
        RECT 62.700 13.500 65.700 16.000 ;
        RECT 62.700 13.500 65.200 35.200 ;
        RECT 62.700 32.700 65.750 35.200 ;
        RECT 74.900 13.500 77.400 20.000 ;
        RECT 76.450 17.500 78.950 28.800 ;
        RECT 73.650 26.300 78.950 28.800 ;
        RECT 73.650 26.300 76.150 35.200 ;
        RECT 84.850 13.500 87.600 16.000 ;
        RECT 84.850 13.500 87.350 35.200 ;
        RECT 80.000 13.600 83.150 16.100 ;
        RECT 79.050 32.700 83.150 35.200 ;
        RECT 80.650 13.600 83.150 39.400 ;
        RECT 89.050 35.400 91.550 39.400 ;
        RECT 80.650 36.900 91.550 39.400 ;
        
        RECT 93.250 12.600 95.750 24.199 ;
        RECT 95.750 13.500 97.700 16.000 ;
        
        RECT 105.850 13.500 108.350 30.900 ;
      LAYER via1 ;
        
        RECT 13.950 22.100 15.450 23.600 ;
        RECT 12.533 14.050 14.033 15.550 ;
        
        RECT 23.050 33.100 24.550 34.600 ;
        RECT 23.550 14.000 25.050 15.500 ;
        RECT 28.450 33.200 29.950 34.700 ;
        RECT 28.650 14.000 30.150 15.500 ;
        RECT 33.750 14.000 35.250 15.500 ;
        RECT 33.850 33.200 35.350 34.700 ;
       
        
        RECT 52.950 33.200 54.450 34.700 ;
        RECT 53.500 14.000 55.000 15.500 ;
        RECT 58.350 33.200 59.850 34.700 ;
        RECT 58.600 14.000 60.100 15.500 ;
        RECT 63.700 14.000 65.200 15.500 ;
        RECT 63.750 33.200 65.250 34.700 ;
      
        RECT 74.150 33.200 75.650 34.700 ;
        RECT 75.400 14.000 76.900 15.500 ;
        RECT 79.550 33.200 81.050 34.700 ;
        RECT 80.500 14.100 82.000 15.600 ;
        RECT 85.350 33.200 86.850 34.700 ;
        RECT 85.600 14.000 87.100 15.500 ;
        RECT 89.550 35.900 91.050 37.400 ;
      
        RECT 95.700 14.000 97.200 15.500 ;
        RECT 106.350 28.900 107.850 30.400 ;
        RECT 106.350 14.000 107.850 15.500 ;
        
      LAYER metal1 ;
        RECT 5.050 17.800 7.550 23.300 ;
        RECT 11.550 10.500 15.950 13.000 ;
        RECT 13.450 10.500 15.950 16.050 ;
        RECT 17.150 25.600 23.050 28.100 ;
        RECT 22.550 29.600 25.050 38.100 ;
        RECT 23.050 10.500 25.550 16.000 ;
        RECT 28.150 10.500 30.650 16.000 ;
        RECT 33.250 10.500 35.750 16.000 ;
        RECT 33.350 29.700 35.850 38.200 ;
        RECT 42.850 30.150 45.350 36.100 ;
        RECT 42.850 10.500 45.350 16.400 ;
        RECT 32.700 21.700 35.200 24.200 ;
        RECT 12.950 21.600 27.050 24.100 ;
        RECT 24.650 21.800 53.850 24.200 ;
        RECT 24.650 21.800 27.150 24.300 ;
        RECT 51.350 21.800 53.850 24.300 ;
        RECT 12.950 21.600 15.450 38.200 ;
        RECT 12.150 26.700 15.450 38.200 ;
        RECT 52.450 29.700 54.950 38.200 ;
        RECT 53.000 10.500 55.500 16.000 ;
        RECT 57.850 29.700 60.350 38.200 ;
        RECT 63.200 10.500 65.700 16.000 ;
        RECT 63.250 29.700 65.750 38.200 ;
        RECT 1.350 10.500 3.850 16.000 ;
        RECT 33.600 17.600 40.500 20.098 ;
        RECT 11.450 17.600 28.250 20.100 ;
        RECT 54.450 17.600 57.750 20.300 ;
        RECT 37.000 17.900 57.750 20.300 ;
        RECT 55.350 17.600 57.750 24.050 ;
        RECT 55.350 21.550 65.950 24.050 ;
        RECT 0.850 13.500 3.400 38.200 ;
        RECT 0.850 24.800 8.202 27.200 ;
        RECT 9.050 17.600 9.350 27.200 ;
        RECT 0.850 24.800 3.850 38.200 ;
        RECT 28.250 17.596 28.350 20.098 ;
        RECT 28.350 17.596 28.450 20.098 ;
        RECT 28.450 17.596 28.550 20.098 ;
        RECT 28.550 17.596 28.650 20.098 ;
        RECT 28.650 17.596 28.750 20.098 ;
        RECT 28.750 17.596 28.850 20.098 ;
        RECT 28.850 17.596 28.950 20.098 ;
        RECT 28.950 17.596 29.050 20.098 ;
        RECT 29.050 17.596 29.150 20.098 ;
        RECT 29.150 17.596 29.250 20.098 ;
        RECT 29.250 17.596 29.350 20.098 ;
        RECT 29.350 17.596 29.450 20.098 ;
        RECT 29.450 17.596 29.550 20.098 ;
        RECT 29.550 17.596 29.650 20.098 ;
        RECT 29.650 17.596 29.750 20.098 ;
        RECT 29.750 17.596 29.850 20.098 ;
        RECT 29.850 17.596 29.950 20.098 ;
        RECT 29.950 17.596 30.050 20.098 ;
        RECT 30.050 17.596 30.150 20.098 ;
        RECT 30.150 17.596 30.250 20.098 ;
        RECT 30.250 17.597 30.350 20.098 ;
        RECT 30.350 17.597 30.450 20.098 ;
        RECT 30.450 17.597 30.550 20.098 ;
        RECT 30.550 17.597 30.650 20.098 ;
        RECT 30.650 17.597 30.750 20.098 ;
        RECT 30.750 17.597 30.850 20.098 ;
        RECT 30.850 17.597 30.950 20.098 ;
        RECT 30.950 17.597 31.050 20.098 ;
        RECT 31.050 17.597 31.150 20.098 ;
        RECT 31.150 17.597 31.250 20.098 ;
        RECT 31.250 17.597 31.350 20.098 ;
        RECT 31.350 17.597 31.450 20.098 ;
        RECT 31.450 17.597 31.550 20.098 ;
        RECT 31.550 17.597 31.650 20.098 ;
        RECT 31.650 17.597 31.750 20.098 ;
        RECT 31.750 17.597 31.850 20.098 ;
        RECT 31.850 17.597 31.950 20.098 ;
        RECT 31.950 17.597 32.050 20.098 ;
        RECT 32.050 17.597 32.150 20.098 ;
        RECT 32.150 17.597 32.250 20.098 ;
        RECT 32.250 17.597 32.350 20.098 ;
        RECT 32.350 17.597 32.450 20.098 ;
        RECT 32.450 17.597 32.550 20.098 ;
        RECT 32.550 17.597 32.650 20.098 ;
        RECT 32.650 17.597 32.750 20.098 ;
        RECT 32.750 17.597 32.850 20.098 ;
        RECT 32.850 17.597 32.950 20.098 ;
        RECT 32.950 17.597 33.050 20.098 ;
        RECT 33.050 17.597 33.150 20.098 ;
        RECT 33.150 17.597 33.250 20.098 ;
        RECT 33.250 17.597 33.350 20.098 ;
        RECT 33.350 17.597 33.450 20.098 ;
        RECT 33.450 17.597 33.550 20.098 ;
        RECT 33.550 17.597 33.600 20.098 ;
        RECT 9.350 17.600 9.450 26.948 ;
        RECT 9.450 17.600 9.550 26.848 ;
        RECT 9.550 17.600 9.650 26.748 ;
        RECT 9.650 17.600 9.750 26.648 ;
        RECT 9.750 17.600 9.850 26.548 ;
        RECT 9.850 17.600 9.950 26.448 ;
        RECT 9.950 17.600 10.050 26.348 ;
        RECT 10.050 17.600 10.150 26.248 ;
        RECT 10.150 17.600 10.250 26.148 ;
        RECT 10.250 17.600 10.350 26.048 ;
        RECT 10.350 17.600 10.450 25.948 ;
        RECT 10.450 17.600 10.550 25.848 ;
        RECT 10.550 17.600 10.650 25.748 ;
        RECT 10.650 17.600 10.750 25.648 ;
        RECT 10.750 17.600 10.850 25.548 ;
        RECT 10.850 17.600 10.950 25.448 ;
        RECT 10.950 17.600 11.050 25.348 ;
        RECT 11.050 17.600 11.150 25.248 ;
        RECT 11.150 17.600 11.250 25.148 ;
        RECT 11.250 17.600 11.350 25.048 ;
        RECT 11.350 17.600 11.450 24.948 ;
        RECT 8.202 24.800 8.302 27.200 ;
        RECT 8.302 24.700 8.402 27.200 ;
        RECT 8.402 24.600 8.502 27.200 ;
        RECT 8.502 24.500 8.602 27.200 ;
        RECT 8.602 24.400 8.702 27.200 ;
        RECT 8.702 24.300 8.802 27.200 ;
        RECT 8.802 24.200 8.902 27.200 ;
        RECT 8.902 24.100 9.002 27.200 ;
        RECT 9.002 24.000 9.050 27.200 ;
        RECT 68.850 21.700 74.750 24.200 ;
        RECT 73.650 29.700 76.150 38.200 ;
        RECT 58.100 10.500 60.600 16.000 ;
        RECT 59.300 13.500 61.700 19.900 ;
        RECT 74.900 10.500 77.400 19.900 ;
        RECT 59.300 17.500 77.400 19.900 ;
        RECT 79.050 29.700 81.550 38.200 ;
        RECT 80.000 10.500 82.500 16.100 ;
        RECT 84.450 25.800 85.050 38.200 ;
        RECT 32.102 25.800 82.352 28.200 ;
        RECT 84.450 32.700 87.350 35.200 ;
        RECT 27.950 25.800 30.450 38.200 ;
        RECT 84.450 27.250 86.950 38.200 ;
        RECT 82.352 25.800 82.452 28.200 ;
        RECT 82.452 25.800 82.552 28.300 ;
        RECT 82.552 25.800 82.652 28.400 ;
        RECT 82.652 25.800 82.752 28.500 ;
        RECT 82.752 25.800 82.852 28.600 ;
        RECT 82.852 25.800 82.952 28.700 ;
        RECT 82.952 25.800 83.052 28.800 ;
        RECT 83.052 25.800 83.152 28.900 ;
        RECT 83.152 25.800 83.252 29.000 ;
        RECT 83.252 25.800 83.352 29.100 ;
        RECT 83.352 25.800 83.452 29.200 ;
        RECT 83.452 25.800 83.552 29.300 ;
        RECT 83.552 25.800 83.652 29.400 ;
        RECT 83.652 25.800 83.752 29.500 ;
        RECT 83.752 25.800 83.852 29.600 ;
        RECT 83.852 25.800 83.952 29.700 ;
        RECT 83.952 25.800 84.052 29.800 ;
        RECT 84.052 25.800 84.152 29.900 ;
        RECT 84.152 25.800 84.252 30.000 ;
        RECT 84.252 25.800 84.352 30.100 ;
        RECT 84.352 25.800 84.450 30.200 ;
        RECT 30.450 25.800 30.550 30.412 ;
        RECT 30.550 25.800 30.650 30.269 ;
        RECT 30.650 25.800 30.750 30.127 ;
        RECT 30.750 25.800 30.850 29.984 ;
        RECT 30.850 25.800 30.950 29.842 ;
        RECT 30.950 25.800 31.050 29.699 ;
        RECT 31.050 25.800 31.150 29.557 ;
        RECT 31.150 25.800 31.250 29.414 ;
        RECT 31.250 25.800 31.350 29.272 ;
        RECT 31.350 25.800 31.450 29.129 ;
        RECT 31.450 25.800 31.550 28.987 ;
        RECT 31.550 25.800 31.650 28.844 ;
        RECT 31.650 25.800 31.750 28.702 ;
        RECT 31.750 25.800 31.850 28.559 ;
        RECT 31.850 25.800 31.950 28.417 ;
        RECT 31.950 25.800 32.050 28.274 ;
        RECT 32.050 25.800 32.102 28.200 ;
        RECT 85.100 10.500 87.600 16.000 ;
        RECT 89.050 32.000 91.550 37.900 ;
        RECT 93.250 28.400 96.650 30.900 ;
        RECT 94.150 25.400 96.650 36.900 ;
        RECT 95.200 10.500 97.700 16.000 ;
        RECT 86.550 21.500 108.350 23.900 ;
        RECT 86.550 21.500 89.050 25.750 ;
        RECT 105.850 21.500 108.350 36.900 ;
        RECT 105.400 10.500 108.350 16.000 ;
        RECT 110.050 21.400 116.700 23.900 ;
        RECT 115.500 10.500 118.000 16.000 ;
        RECT 115.500 12.600 120.950 16.000 ;
        RECT 83.400 17.500 120.950 19.900 ;
        RECT 101.650 17.500 104.150 20.000 ;
        RECT 80.650 17.650 85.900 20.100 ;
        RECT 80.650 17.650 83.050 24.200 ;
        RECT 76.250 21.700 83.050 24.200 ;
        RECT 118.450 12.600 120.950 27.700 ;
        RECT 116.700 25.400 119.200 36.900 ;
  END 
END MX4122







macro MX2101
  CLASS  CORE ;
  FOREIGN MX2101 0.000 0.000 ;
  ORIGIN 0.000 0.000 ;
  SIZE 32.600 BY 48.700 ;
  SYMMETRY X Y  ;
  SITE CORE ;
  PIN D0
    DIRECTION INPUT ;
    PORT
      LAYER metal1 ;
        RECT 12.450 13.500 14.950 16.000 ;
    END
  END D0
  PIN OUT1
    DIRECTION OUTPUT ;
    PORT
      LAYER metal1 ;
        RECT 20.850 27.000 23.350 29.500 ;
    END
  END OUT1
  PIN A0
    DIRECTION INPUT ;
    PORT
      LAYER metal1 ;
        RECT 0.850 21.000 3.350 23.500 ;
    END
  END A0
  PIN D1
    DIRECTION INPUT ;
    PORT
      LAYER metal1 ;
        RECT 29.250 21.000 31.750 23.500 ;
    END
  END D1
  PIN VSS
    DIRECTION INOUT ;
    USE GROUND ;
    SHAPE ABUTMENT ;
    PORT
      LAYER metal1 ;
        RECT 2.600 0.000 5.100 15.550 ;
        RECT 0.000 0.000 32.600 9.000 ;
    END
  END VSS
  PIN VDD
    DIRECTION INOUT ;
    USE POWER ;
    SHAPE ABUTMENT ;
    PORT
      LAYER metal1 ;
        RECT 2.550 27.000 5.050 48.700 ;
        RECT 0.000 39.700 32.600 48.700 ;
    END
  END VDD
  OBS 
      LAYER metal2 ;
        RECT 7.900 16.500 10.450 26.700 ;
        RECT 7.950 16.500 10.450 29.200 ;
       
        RECT 12.450 20.198 14.950 36.100 ;
        RECT 20.850 12.600 23.350 25.000 ;
        
        
      LAYER via1 ;
        
        RECT 8.400 17.000 9.900 18.500 ;
        RECT 8.450 27.200 9.950 28.700 ;
        RECT 12.950 30.200 14.450 31.700 ;
        RECT 21.350 14.950 22.850 16.450 ;
        
      LAYER metal1 ;
        RECT 7.900 26.700 10.450 38.200 ;
        RECT 7.900 10.500 10.450 20.000 ;
        RECT 7.900 17.500 15.150 20.000 ;
        RECT 12.450 10.500 15.450 16.000 ;
        RECT 12.450 29.700 17.200 32.450 ;
        RECT 14.700 26.700 17.200 38.200 ;
        RECT 18.050 10.950 23.550 14.550 ;
        RECT 18.050 10.950 23.350 16.000 ;
        RECT 20.850 10.950 23.350 25.050 ;
        RECT 20.750 27.000 23.850 38.200 ;
        RECT 25.948 17.500 27.350 20.000 ;
        RECT 0.850 21.000 3.350 24.000 ;
        RECT 16.650 19.100 23.452 21.500 ;
        RECT 0.850 21.500 19.200 24.000 ;
        RECT 16.650 19.100 19.200 24.200 ;
        RECT 24.850 17.500 24.950 20.998 ;
        RECT 24.950 17.500 25.050 20.898 ;
        RECT 25.050 17.500 25.150 20.798 ;
        RECT 25.150 17.500 25.250 20.698 ;
        RECT 25.250 17.500 25.350 20.598 ;
        RECT 25.350 17.500 25.450 20.498 ;
        RECT 25.450 17.500 25.550 20.398 ;
        RECT 25.550 17.500 25.650 20.298 ;
        RECT 25.650 17.500 25.750 20.198 ;
        RECT 25.750 17.500 25.850 20.098 ;
        RECT 25.850 17.500 25.948 20.000 ;
        RECT 24.700 17.852 24.800 21.148 ;
        RECT 24.800 17.752 24.850 21.098 ;
        RECT 23.452 19.100 23.552 21.500 ;
        RECT 23.552 19.000 23.652 21.500 ;
        RECT 23.652 18.900 23.752 21.500 ;
        RECT 23.752 18.800 23.852 21.500 ;
        RECT 23.852 18.700 23.952 21.500 ;
        RECT 23.952 18.600 24.052 21.500 ;
        RECT 24.052 18.500 24.152 21.500 ;
        RECT 24.152 18.400 24.252 21.500 ;
        RECT 24.252 18.300 24.352 21.500 ;
        RECT 24.352 18.200 24.452 21.500 ;
        RECT 24.452 18.100 24.552 21.500 ;
        RECT 24.552 18.000 24.652 21.500 ;
        RECT 24.652 17.900 24.700 21.500 ;
        RECT 26.150 10.500 28.650 16.000 ;
        RECT 26.150 12.600 31.750 16.000 ;
        RECT 29.250 12.600 31.750 31.900 ;
        RECT 26.750 28.150 29.250 37.700 ;
  END 
END MX2101



macro CDRI01
  CLASS  CORE ;
  FOREIGN CDRI01 0.000 0.000 ;
  ORIGIN 0.000 0.000 ;
  SIZE 54.600 BY 48.700 ;
  SYMMETRY X Y  ;
  SITE CORE ;
  PIN Q
    DIRECTION OUTPUT ;
    PORT
      LAYER metal1 ;
        RECT 51.250 21.000 53.750 23.500 ;
    END
  END Q

  PIN VSS
    DIRECTION INOUT ;
    USE GROUND ;
    SHAPE ABUTMENT ;
    PORT
      LAYER metal1 ;
        RECT 6.450 0.000 8.950 13.350 ;
        RECT 0.000 0.000 54.600 9.000 ;
        RECT 45.500 0.000 48.000 14.250 ;
        RECT 35.300 0.000 37.800 14.250 ;
        RECT 16.650 0.000 19.150 13.400 ;
    END
  END VSS
  PIN IN1
    DIRECTION INPUT ;
    PORT
      LAYER metal1 ;
        RECT 0.850 21.000 3.350 23.500 ;
    END
  END IN1
  PIN VDD
    DIRECTION INOUT ;
    USE POWER ;
    SHAPE ABUTMENT ;
    PORT
      LAYER metal1 ;
        RECT 6.800 31.650 9.300 48.700 ;
        RECT 0.000 39.700 54.600 48.700 ;
        RECT 45.150 32.150 47.650 48.700 ;
        RECT 34.350 32.150 36.850 48.700 ;
        RECT 17.600 31.650 20.100 48.700 ;
    END
  END VDD
  OBS 
     
      LAYER metal2 ;
        RECT 23.750 18.700 24.350 25.800 ;
        RECT 23.750 18.700 30.850 19.300 ;
        RECT 30.250 18.700 30.850 25.800 ;
        RECT 23.750 25.200 30.850 25.800 ;
    
     
      LAYER metal1 ;
        RECT 0.850 18.800 22.050 21.300 ;
        RECT 0.850 18.800 3.350 25.650 ;
        RECT 0.850 23.150 22.050 25.650 ;
        RECT 1.350 10.550 3.850 17.300 ;
        RECT 11.550 10.550 14.050 17.300 ;
        RECT 21.750 10.550 24.250 17.300 ;
        RECT 1.350 14.900 28.000 17.300 ;
        RECT 24.950 14.900 28.000 26.700 ;
        RECT 24.950 19.800 49.350 22.400 ;
        RECT 24.950 19.800 28.550 26.700 ;
        RECT 24.950 24.200 49.350 26.700 ;
        RECT 1.350 27.200 27.350 29.600 ;
        RECT 24.950 14.900 27.350 29.700 ;
        RECT 1.350 27.200 3.850 37.650 ;
        RECT 12.200 27.200 14.700 37.650 ;
        RECT 23.000 27.200 25.500 37.650 ;
        RECT 30.200 13.450 32.700 18.200 ;
        RECT 40.400 13.450 42.900 18.200 ;
        RECT 30.200 15.750 42.900 18.200 ;
        RECT 50.600 13.500 53.750 18.200 ;
        RECT 30.200 15.800 53.750 18.200 ;
        RECT 28.900 28.200 53.750 30.600 ;
        RECT 28.900 28.200 31.400 37.650 ;
        RECT 39.750 28.200 42.250 37.650 ;
        RECT 51.250 13.500 53.750 37.650 ;
        RECT 50.550 28.200 53.750 37.650 ;
  END 
END CDRI01



macro DFPC11
  CLASS  CORE ;
  FOREIGN DFPC11 0.000 0.000 ;
  ORIGIN 0.000 0.000 ;
  SIZE 121.800 BY 48.700 ;
  SYMMETRY X Y  ;
  SITE CORE ;
  PIN Q
    DIRECTION OUTPUT ;
    PORT
      LAYER metal1 ;
        RECT 118.450 21.000 120.950 23.500 ;
    END
  END Q
  PIN C
    DIRECTION INPUT ;
    USE CLOCK ;
    PORT
      LAYER metal1 ;
        RECT 5.050 21.000 7.550 23.500 ;
    END
  END C
  PIN D
    DIRECTION INPUT ;
    PORT
      LAYER metal1 ;
        RECT 17.650 16.800 20.150 19.300 ;
    END
  END D
  PIN QB
    DIRECTION OUTPUT ;
    PORT
      LAYER metal1 ;
        RECT 105.850 16.800 108.350 19.300 ;
    END
  END QB
  PIN PRB
    DIRECTION INPUT ;
    PORT
      LAYER metal1 ;
        RECT 101.650 21.000 104.150 23.500 ;
    END
  END PRB
  PIN VSS
    DIRECTION INOUT ;
    USE GROUND ;
    SHAPE ABUTMENT ;
    PORT
      LAYER metal1 ;
        RECT 6.450 0.000 8.950 15.900 ;
        RECT 0.000 0.000 121.800 9.000 ;
        RECT 111.150 0.000 113.650 16.500 ;
        RECT 100.150 0.000 102.650 15.200 ;
        RECT 86.650 0.000 89.150 15.900 ;
        RECT 50.100 0.000 52.800 15.900 ;
        RECT 42.300 0.000 45.100 15.900 ;
    END
  END VSS
  PIN CLRB
    DIRECTION INPUT ;
    PORT
      LAYER metal1 ;
        RECT 55.450 12.600 57.950 15.100 ;
    END
  END CLRB

  PIN VDD
    DIRECTION INOUT ;
    USE POWER ;
    SHAPE ABUTMENT ;
    PORT
      LAYER metal1 ;
        RECT 8.050 29.000 10.550 48.700 ;
        RECT 0.000 39.700 121.800 48.700 ;
        RECT 112.650 26.100 115.150 48.700 ;
        RECT 96.750 29.700 99.250 48.700 ;
        RECT 80.550 33.400 83.050 48.700 ;
        RECT 58.050 34.800 60.550 48.700 ;
        RECT 38.650 37.600 41.150 48.700 ;
    END
  END VDD
  OBS 
      LAYER metal2 ;
        RECT 13.450 16.800 15.950 27.950 ;
        RECT 17.650 23.500 20.150 31.900 ;
        RECT 26.050 16.800 28.550 36.100 ;
        RECT 34.450 12.600 39.650 15.100 ;
        RECT 34.450 12.600 36.950 36.100 ;
        RECT 34.450 33.600 41.150 36.100 ;
        RECT 38.650 29.400 47.153 31.900 ;
        RECT 47.151 29.400 49.641 34.830 ;
        RECT 47.151 34.830 104.150 37.330 ;
        RECT 62.204 8.097 84.850 10.597 ;
        RECT 63.850 12.600 66.350 31.900 ;
        RECT 80.650 12.600 83.150 31.900 ;
        RECT 84.850 8.097 87.350 27.700 ;
        RECT 101.650 25.200 104.15 37.330 ;
        RECT 104.920 14.500 110.670 15.100 ;
        RECT 110.050 14.490 110.670 21.000 ;
             
       
      LAYER metal1 ;
        RECT 5.050 17.600 7.550 23.500 ;
        RECT 11.550 10.500 14.050 19.300 ;
        RECT 11.550 16.800 15.950 19.300 ;
        RECT 17.650 29.400 23.150 31.900 ;
        RECT 20.650 29.400 23.150 38.200 ;
        RECT 17.650 10.500 23.450 16.000 ;
        RECT 17.650 10.500 20.150 16.800 ;
        RECT 0.850 10.500 3.850 16.000 ;
        RECT 9.250 21.400 23.750 23.900 ;
        RECT 9.250 21.400 11.750 27.500 ;
        RECT 0.850 25.000 11.750 27.500 ;
        RECT 0.850 10.500 3.350 29.700 ;
        RECT 2.650 25.000 5.150 38.200 ;
        RECT 26.050 29.400 28.550 38.200 ;
        RECT 31.150 12.600 39.650 15.100 ;
        RECT 31.150 10.500 33.650 16.000 ;
        RECT 35.250 29.400 41.150 31.900 ;
        RECT 31.450 32.700 33.950 38.200 ;
        RECT 31.450 33.600 46.550 36.100 ;
        RECT 31.450 33.600 35.750 38.200 ;
        RECT 44.050 32.500 46.550 38.200 ;
        RECT 26.050 10.500 28.550 19.900 ;
        RECT 51.450 17.400 53.950 19.900 ;
        RECT 26.050 17.500 53.950 19.900 ;
        RECT 55.450 12.600 57.950 19.900 ;
        RECT 55.450 17.400 60.250 19.900 ;
        RECT 48.350 29.400 66.350 31.900 ;
        RECT 52.050 29.400 54.550 38.200 ;
        RECT 63.850 29.400 66.350 38.200 ;
        RECT 60.850 12.600 66.350 15.100 ;
        RECT 60.850 10.500 63.350 16.000 ;
        RECT 29.950 25.400 69.750 27.900 ;
        RECT 29.950 25.400 32.650 28.400 ;
        RECT 25.250 21.400 75.150 23.900 ;
        RECT 25.250 21.400 27.750 27.900 ;
        RECT 13.450 25.400 27.750 27.900 ;
        RECT 13.450 25.400 15.950 38.200 ;
        RECT 74.050 12.600 83.150 15.100 ;
        RECT 74.050 10.500 76.550 16.000 ;
        RECT 80.550 17.500 83.350 23.500 ;
        RECT 80.650 21.400 87.350 23.900 ;
        RECT 75.150 29.400 88.550 31.900 ;
        RECT 75.150 29.400 77.650 38.200 ;
        RECT 86.050 29.400 88.550 38.200 ;
        RECT 68.950 10.500 71.450 19.900 ;
        RECT 68.950 17.500 79.050 19.900 ;
        RECT 88.850 21.600 95.450 24.100 ;
        RECT 76.650 17.500 79.050 27.900 ;
        RECT 88.850 21.600 91.250 27.900 ;
        RECT 71.250 25.400 91.250 27.900 ;
        RECT 71.250 25.400 73.650 38.200 ;
        RECT 69.250 29.700 73.650 38.200 ;
        RECT 101.650 17.500 104.150 23.500 ;
        RECT 94.950 10.500 97.450 19.900 ;
        RECT 85.550 17.400 99.350 19.900 ;
        RECT 96.950 17.400 99.350 28.200 ;
        RECT 92.850 25.700 105.750 28.200 ;
        RECT 92.850 25.700 95.250 38.200 ;
        RECT 91.050 29.400 95.250 38.200 ;
        RECT 102.050 25.700 105.750 38.200 ;
        RECT 105.850 20.200 116.550 22.700 ;
        RECT 105.850 10.500 108.550 23.600 ;
        RECT 107.250 20.200 109.750 38.200 ;
        RECT 116.250 11.000 118.900 18.300 ;
        RECT 118.050 15.200 120.950 38.200 ;
  END 
END DFPC11


macro XOR201
  CLASS  CORE ;
  FOREIGN XOR201 0.000 0.000 ;
  ORIGIN 0.000 0.000 ;
  SIZE 42.000 BY 48.700 ;
  SYMMETRY X Y  ;
  SITE CORE ;
  PIN OUT1
    DIRECTION OUTPUT ;
    PORT
      LAYER metal1 ;
        RECT 38.650 21.000 41.150 23.500 ;
    END
  END OUT1
  PIN VSS
    DIRECTION INOUT ;
    USE GROUND ;
    SHAPE ABUTMENT ;
    PORT
      LAYER metal1 ;
        RECT 9.550 0.000 12.050 16.000 ;
        RECT 0.000 0.000 42.000 9.000 ;
        RECT 33.150 0.000 35.650 15.500 ;
    END
  END VSS
  PIN IN1
    DIRECTION INPUT ;
    PORT
      LAYER metal1 ;
        RECT 7.650 18.200 10.150 20.700 ;
    END
  END IN1
  PIN IN2
    DIRECTION INPUT ;
    PORT
      LAYER metal1 ;
        RECT 17.650 22.700 20.150 25.200 ;
    END
  END IN2
  PIN VDD
    DIRECTION INOUT ;
    USE POWER ;
    SHAPE ABUTMENT ;
    PORT
      LAYER metal1 ;
        RECT 0.850 31.500 3.750 48.700 ;
        RECT 0.000 39.700 42.000 48.700 ;
        RECT 38.150 29.650 40.650 48.700 ;
        RECT 26.950 32.750 29.450 48.700 ;
        RECT 12.350 31.100 14.850 48.700 ;
    END
  END VDD
  OBS 
      LAYER metal2 ;
        RECT 21.850 10.500 26.850 13.000 ;
        RECT 21.850 10.500 24.350 21.200 ;
      LAYER via1 ;
        RECT 22.350 19.200 23.850 20.700 ;
        RECT 24.850 11.000 26.350 12.500 ;
      LAYER metal1 ;
        RECT 7.650 18.200 13.150 20.700 ;
        RECT 0.850 10.500 3.750 29.600 ;
        RECT 0.850 27.100 15.850 29.600 ;
        RECT 6.650 27.100 9.250 37.800 ;
        RECT 15.250 10.500 17.750 21.200 ;
        RECT 15.250 18.700 24.350 21.200 ;
        RECT 5.350 22.700 27.150 25.200 ;
        RECT 5.350 22.700 8.900 25.600 ;
        RECT 24.350 10.500 30.250 13.000 ;
        RECT 20.350 10.500 22.850 17.000 ;
        RECT 20.350 14.500 29.100 17.000 ;
        RECT 31.650 21.750 31.800 24.600 ;
        RECT 18.050 28.550 26.200 31.200 ;
        RECT 18.050 28.550 20.550 38.200 ;
        RECT 29.100 14.500 29.200 29.800 ;
        RECT 29.200 14.500 29.300 29.700 ;
        RECT 29.300 14.500 29.400 29.600 ;
        RECT 29.400 14.500 29.500 29.500 ;
        RECT 29.500 14.500 29.600 29.400 ;
        RECT 29.600 14.500 29.700 29.300 ;
        RECT 29.700 14.500 29.800 29.200 ;
        RECT 29.800 14.500 29.900 29.100 ;
        RECT 29.900 14.500 30.000 29.000 ;
        RECT 30.000 14.500 30.100 28.900 ;
        RECT 30.100 14.500 30.200 28.800 ;
        RECT 30.200 14.500 30.300 28.700 ;
        RECT 30.300 14.500 30.400 28.600 ;
        RECT 30.400 14.500 30.500 28.500 ;
        RECT 30.500 14.500 30.600 28.400 ;
        RECT 30.600 14.500 30.700 28.300 ;
        RECT 30.700 14.500 30.800 28.200 ;
        RECT 30.800 14.500 30.900 28.100 ;
        RECT 30.900 14.500 31.000 28.000 ;
        RECT 31.000 14.500 31.100 27.900 ;
        RECT 31.100 14.500 31.200 27.800 ;
        RECT 31.200 14.500 31.300 27.700 ;
        RECT 31.300 14.500 31.400 27.600 ;
        RECT 31.400 14.500 31.500 27.500 ;
        RECT 31.500 14.500 31.600 27.400 ;
        RECT 31.600 14.500 31.650 27.350 ;
        RECT 27.800 26.950 27.900 31.100 ;
        RECT 27.900 26.850 28.000 31.000 ;
        RECT 28.000 26.750 28.100 30.900 ;
        RECT 28.100 26.650 28.200 30.800 ;
        RECT 28.200 26.550 28.300 30.700 ;
        RECT 28.300 26.450 28.400 30.600 ;
        RECT 28.400 26.350 28.500 30.500 ;
        RECT 28.500 26.250 28.600 30.400 ;
        RECT 28.600 26.150 28.700 30.300 ;
        RECT 28.700 26.050 28.800 30.200 ;
        RECT 28.800 25.950 28.900 30.100 ;
        RECT 28.900 25.850 29.000 30.000 ;
        RECT 29.000 25.750 29.100 29.900 ;
        RECT 26.200 28.550 26.300 31.200 ;
        RECT 26.300 28.450 26.400 31.200 ;
        RECT 26.400 28.350 26.500 31.200 ;
        RECT 26.500 28.250 26.600 31.200 ;
        RECT 26.600 28.150 26.700 31.200 ;
        RECT 26.700 28.050 26.800 31.200 ;
        RECT 26.800 27.950 26.900 31.200 ;
        RECT 26.900 27.850 27.000 31.200 ;
        RECT 27.000 27.750 27.100 31.200 ;
        RECT 27.100 27.650 27.200 31.200 ;
        RECT 27.200 27.550 27.300 31.200 ;
        RECT 27.300 27.450 27.400 31.200 ;
        RECT 27.400 27.350 27.500 31.200 ;
        RECT 27.500 27.250 27.600 31.200 ;
        RECT 27.600 27.150 27.700 31.200 ;
        RECT 27.700 27.050 27.800 31.200 ;
        RECT 38.250 10.550 41.150 27.700 ;
        RECT 36.300 25.150 41.150 27.700 ;
        RECT 33.650 25.150 34.850 38.200 ;
        RECT 33.650 35.700 36.550 38.200 ;
        RECT 34.850 25.150 34.950 31.550 ;
        RECT 34.950 25.150 35.050 31.450 ;
        RECT 35.050 25.150 35.150 31.350 ;
        RECT 35.150 25.150 35.250 31.250 ;
        RECT 35.250 25.150 35.350 31.150 ;
        RECT 35.350 25.150 35.450 31.050 ;
        RECT 35.450 25.150 35.550 30.950 ;
        RECT 35.550 25.150 35.650 30.850 ;
        RECT 35.650 25.150 35.750 30.750 ;
        RECT 35.750 25.150 35.850 30.650 ;
        RECT 35.850 25.150 35.950 30.550 ;
        RECT 35.950 25.150 36.050 30.450 ;
        RECT 36.050 25.150 36.150 30.350 ;
        RECT 36.150 25.150 36.250 30.250 ;
        RECT 36.250 25.150 36.300 30.200 ;
        RECT 32.350 29.750 32.450 38.200 ;
        RECT 32.450 29.650 32.550 38.200 ;
        RECT 32.550 29.550 32.650 38.200 ;
        RECT 32.650 29.450 32.750 38.200 ;
        RECT 32.750 29.350 32.850 38.200 ;
        RECT 32.850 29.250 32.950 38.200 ;
        RECT 32.950 29.150 33.050 38.200 ;
        RECT 33.050 29.050 33.150 38.200 ;
        RECT 33.150 28.950 33.250 38.200 ;
        RECT 33.250 28.850 33.350 38.200 ;
        RECT 33.350 28.750 33.450 38.200 ;
        RECT 33.450 28.650 33.550 38.200 ;
        RECT 33.550 28.550 33.650 38.200 ;
  END 
END XOR201

macro DFCL11
  CLASS  CORE ;
  FOREIGN DFCL11 0.000 0.000 ;
  ORIGIN 0.000 0.000 ;
  SIZE 100.800 BY 48.700 ;
  SYMMETRY X Y  ;
  SITE CORE ;
  PIN Q
    DIRECTION OUTPUT ;
    PORT
      LAYER metal1 ;
        RECT 97.450 16.800 99.950 19.300 ;
    END
  END Q
  PIN C
    DIRECTION INPUT ;
    USE CLOCK ;
    PORT
      LAYER metal1 ;
        RECT 5.050 21.000 7.550 23.500 ;
    END
  END C
  PIN D
    DIRECTION INPUT ;
    PORT
      LAYER metal1 ;
       
        RECT 17.650 16.800 20.150 19.300 ;
    END
  END D
  PIN QB
    DIRECTION OUTPUT ;
    PORT
      LAYER metal1 ;
        RECT 84.850 21.000 87.350 23.500 ;
    END
  END QB
  PIN VSS
    DIRECTION INOUT ;
    USE GROUND ;
    SHAPE ABUTMENT ;
    PORT
      LAYER metal1 ;
        RECT 6.450 0.000 8.950 15.900 ;
        RECT 0.000 0.000 100.800 9.000 ;
        RECT 89.950 0.000 92.450 16.000 ;
        RECT 78.350 0.000 81.450 15.150 ;
        RECT 67.150 0.000 69.650 15.650 ;
        RECT 34.550 0.000 37.050 16.000 ;
    END
  END VSS
  PIN CLRB
    DIRECTION INPUT ;
    PORT
      LAYER metal1 ;
        RECT 47.050 17.500 49.550 20.000 ;
        
    END
  END CLRB
 
  PIN VDD
    DIRECTION INOUT ;
    USE POWER ;
    SHAPE ABUTMENT ;
    PORT
      LAYER metal1 ;
        RECT 6.750 29.000 9.250 48.700 ;
        RECT 0.000 39.700 100.800 48.700 ;
        RECT 91.550 26.100 94.050 48.700 ;
        RECT 81.150 29.200 83.650 48.700 ;
        RECT 65.350 34.200 67.850 48.700 ;
        RECT 43.750 33.700 46.250 48.700 ;
        RECT 33.350 33.700 35.850 48.700 ;
    END
  END VDD
  OBS 
      LAYER metal2 ;
        RECT 13.450 16.800 15.950 28.200 ;
        RECT 22.550 17.500 26.850 20.000 ;
        RECT 22.550 17.500 25.050 32.200 ;
        RECT 29.450 13.500 31.950 35.200 ;
        RECT 27.950 32.700 31.950 35.200 ;
        RECT 42.850 13.500 45.350 32.200 ;
        RECT 42.850 29.700 46.250 32.200 ;
        RECT 47.050 10.860 72.100 13.360 ;
        RECT 69.600 13.360 72.100 25.200 ;
        RECT 68.050 25.200 72.100 28.200 ;
        RECT 53.050 17.500 54.600 20.000 ;
        RECT 47.050 10.890 50.450 15.750 ;
        RECT 17.150 22.150 19.650 32.200 ;
        RECT 63.500 17.700 66.350 32.700 ;
        RECT 66.350 30.200 67.850 32.700 ;
        RECT 82.495 18.990 83.100 25.200 ;
        RECT 82.495 18.990 89.670 19.300 ;
        RECT 89.050 18.990 89.670 25.200 ;
      LAYER via1 ;
        RECT 13.950 26.200 15.450 27.700 ;
        RECT 13.950 17.300 15.450 18.800 ;
        RECT 17.650 30.200 19.150 31.700 ;
        RECT 23.050 30.200 24.550 31.700 ;
        RECT 24.850 18.000 26.350 19.500 ;
        RECT 28.450 33.200 29.950 34.700 ;
        RECT 29.950 14.000 31.450 15.500 ;
        RECT 43.350 14.000 44.850 15.500 ;
        RECT 44.250 30.200 45.750 31.700 ;
        RECT 64.350 18.200 65.850 19.700 ;
        RECT 65.850 30.700 67.350 32.200 ;
        RECT 68.550 26.200 70.050 27.700 ;
      LAYER metal1 ;
        RECT 5.050 17.600 7.550 23.500 ;
        RECT 11.550 10.500 14.050 19.300 ;
        RECT 11.550 16.800 15.950 19.300 ;
        RECT 17.150 29.700 19.650 38.200 ;
        RECT 17.650 10.500 21.750 16.000 ;
        RECT 17.650 10.500 20.150 19.300 ;
        RECT 0.850 12.250 3.850 16.000 ;
        RECT 9.050 21.500 23.250 24.000 ;
        RECT 9.050 21.500 11.550 27.500 ;
        RECT 0.850 25.000 11.550 27.500 ;
        RECT 0.850 12.250 3.350 38.200 ;
        RECT 0.850 29.700 3.850 38.200 ;
        RECT 22.550 29.700 25.050 38.200 ;
        RECT 27.950 32.700 30.450 38.200 ;
        RECT 29.450 10.500 31.950 16.000 ;
        RECT 24.350 10.500 26.850 20.000 ;
        RECT 24.350 17.500 38.750 20.000 ;
        RECT 42.850 10.500 48.350 16.000 ;
        RECT 41.150 17.500 49.550 20.000 ;
        RECT 32.250 29.700 51.650 32.200 ;
        RECT 38.350 29.700 40.850 38.200 ;
        RECT 49.150 29.700 51.650 38.200 ;
        RECT 28.650 25.700 54.250 28.200 ;
        RECT 24.750 21.500 58.450 24.000 ;
        RECT 24.750 21.500 27.150 28.200 ;
        RECT 13.050 25.700 27.150 28.200 ;
        RECT 13.050 25.700 15.550 31.900 ;
        RECT 12.150 29.700 14.650 38.200 ;
        RECT 57.250 10.500 60.100 16.000 ;
        RECT 57.250 13.300 61.700 16.000 ;
        RECT 63.850 14.701 63.950 20.200 ;
        RECT 63.950 14.801 64.050 20.200 ;
        RECT 64.050 14.901 64.150 20.200 ;
        RECT 64.150 15.001 64.250 20.200 ;
        RECT 64.250 15.101 64.350 20.200 ;
        RECT 64.350 15.201 64.450 20.200 ;
        RECT 64.450 15.301 64.550 20.200 ;
        RECT 64.550 15.401 64.650 20.200 ;
        RECT 64.650 15.501 64.750 20.200 ;
        RECT 64.750 15.601 64.850 20.200 ;
        RECT 64.850 15.701 64.950 20.200 ;
        RECT 64.950 15.801 65.050 20.200 ;
        RECT 65.050 15.901 65.150 20.200 ;
        RECT 65.150 16.001 65.250 20.200 ;
        RECT 65.250 16.101 65.350 20.200 ;
        RECT 65.350 16.201 65.450 20.200 ;
        RECT 65.450 16.301 65.550 20.200 ;
        RECT 65.550 16.401 65.650 20.200 ;
        RECT 65.650 16.501 65.750 20.200 ;
        RECT 65.750 16.601 65.850 20.200 ;
        RECT 65.850 16.701 65.950 20.200 ;
        RECT 65.950 16.801 66.050 20.200 ;
        RECT 66.050 16.901 66.150 20.200 ;
        RECT 66.150 17.001 66.250 20.200 ;
        RECT 66.250 17.101 66.350 20.200 ;
        RECT 62.549 13.400 62.649 16.849 ;
        RECT 62.649 13.500 62.749 16.949 ;
        RECT 62.749 13.600 62.849 17.049 ;
        RECT 62.849 13.700 62.949 17.149 ;
        RECT 62.949 13.800 63.049 17.249 ;
        RECT 63.049 13.900 63.149 17.349 ;
        RECT 63.149 14.000 63.249 17.449 ;
        RECT 63.249 14.100 63.349 17.549 ;
        RECT 63.349 14.200 63.449 17.649 ;
        RECT 63.449 14.300 63.549 17.749 ;
        RECT 63.549 14.400 63.649 17.849 ;
        RECT 63.649 14.500 63.749 17.949 ;
        RECT 63.749 14.600 63.849 18.049 ;
        RECT 63.849 14.601 63.850 18.149 ;
        RECT 61.700 13.300 61.800 16.000 ;
        RECT 61.800 13.300 61.900 16.100 ;
        RECT 61.900 13.300 62.000 16.200 ;
        RECT 62.000 13.300 62.100 16.300 ;
        RECT 62.100 13.300 62.200 16.400 ;
        RECT 62.200 13.300 62.300 16.500 ;
        RECT 62.300 13.300 62.400 16.600 ;
        RECT 62.400 13.300 62.500 16.700 ;
        RECT 62.500 13.300 62.549 16.800 ;
        RECT 63.850 25.700 70.550 28.200 ;
        RECT 59.950 30.200 73.250 32.700 ;
        RECT 59.950 30.200 62.450 38.200 ;
        RECT 70.750 30.200 73.250 38.200 ;
        RECT 52.150 10.500 54.650 20.000 ;
        RECT 52.150 17.500 59.193 20.000 ;
        RECT 62.350 21.700 77.350 24.200 ;
        RECT 59.950 17.500 60.450 28.000 ;
        RECT 55.750 25.500 60.450 28.000 ;
        RECT 55.750 25.500 58.250 38.200 ;
        RECT 54.550 29.700 58.250 38.200 ;
        RECT 60.450 17.600 60.550 28.000 ;
        RECT 60.550 17.700 60.650 28.000 ;
        RECT 60.650 17.800 60.750 28.000 ;
        RECT 60.750 17.900 60.850 28.000 ;
        RECT 60.850 18.000 60.950 28.000 ;
        RECT 60.950 18.100 61.050 28.000 ;
        RECT 61.050 18.200 61.150 28.000 ;
        RECT 61.150 18.300 61.250 28.000 ;
        RECT 61.250 18.400 61.350 28.000 ;
        RECT 61.350 18.500 61.450 28.000 ;
        RECT 61.450 18.600 61.550 28.000 ;
        RECT 61.550 18.700 61.650 28.000 ;
        RECT 61.650 18.800 61.750 28.000 ;
        RECT 61.750 18.900 61.850 28.000 ;
        RECT 61.850 19.000 61.950 28.000 ;
        RECT 61.950 19.100 62.050 28.000 ;
        RECT 62.050 19.200 62.150 28.000 ;
        RECT 62.150 19.300 62.250 28.000 ;
        RECT 62.250 19.400 62.350 28.000 ;
        RECT 59.193 17.500 59.293 20.000 ;
        RECT 59.293 17.500 59.393 20.100 ;
        RECT 59.393 17.500 59.493 20.200 ;
        RECT 59.493 17.500 59.593 20.300 ;
        RECT 59.593 17.500 59.693 20.400 ;
        RECT 59.693 17.500 59.793 20.500 ;
        RECT 59.793 17.500 59.893 20.600 ;
        RECT 59.893 17.500 59.950 20.700 ;
        RECT 72.250 10.500 74.750 20.000 ;
        RECT 72.250 17.500 79.800 20.000 ;
        RECT 82.300 17.500 83.350 20.000 ;
        RECT 72.200 26.150 77.750 28.650 ;
        RECT 75.750 26.150 77.750 38.200 ;
        RECT 79.800 17.500 79.900 27.800 ;
        RECT 79.900 17.500 80.000 27.700 ;
        RECT 80.000 17.500 80.100 27.600 ;
        RECT 80.100 17.500 80.200 27.500 ;
        RECT 80.200 17.500 80.300 27.400 ;
        RECT 80.300 17.500 80.400 27.300 ;
        RECT 80.400 17.500 80.500 27.200 ;
        RECT 80.500 17.500 80.600 27.100 ;
        RECT 80.600 17.500 80.700 27.000 ;
        RECT 80.700 17.500 80.800 26.900 ;
        RECT 80.800 17.500 80.900 26.800 ;
        RECT 80.900 17.500 81.000 26.700 ;
        RECT 81.000 17.500 81.100 26.600 ;
        RECT 81.100 17.500 81.200 26.500 ;
        RECT 81.200 17.500 81.300 26.400 ;
        RECT 81.300 17.500 81.400 26.300 ;
        RECT 81.400 17.500 81.500 26.200 ;
        RECT 81.500 17.500 81.600 26.100 ;
        RECT 81.600 17.500 81.700 26.000 ;
        RECT 81.700 17.500 81.800 25.900 ;
        RECT 81.800 17.500 81.900 25.800 ;
        RECT 81.900 17.500 82.000 25.700 ;
        RECT 82.000 17.500 82.100 25.600 ;
        RECT 82.100 17.500 82.200 25.500 ;
        RECT 82.200 17.500 82.300 25.400 ;
        RECT 78.550 25.350 78.650 29.050 ;
        RECT 78.650 25.250 78.750 28.950 ;
        RECT 78.750 25.150 78.850 28.850 ;
        RECT 78.850 25.050 78.950 28.750 ;
        RECT 78.950 24.950 79.050 28.650 ;
        RECT 79.050 24.850 79.150 28.550 ;
        RECT 79.150 24.750 79.250 28.450 ;
        RECT 79.250 24.650 79.350 28.350 ;
        RECT 79.350 24.550 79.450 28.250 ;
        RECT 79.450 24.450 79.550 28.150 ;
        RECT 79.550 24.350 79.650 28.050 ;
        RECT 79.650 24.250 79.750 27.950 ;
        RECT 79.750 24.150 79.800 27.900 ;
        RECT 77.750 26.150 77.850 38.200 ;
        RECT 77.850 26.050 77.950 38.200 ;
        RECT 77.950 25.950 78.050 38.200 ;
        RECT 78.050 25.850 78.150 38.200 ;
        RECT 78.150 25.750 78.250 38.200 ;
        RECT 78.250 25.650 78.350 38.200 ;
        RECT 78.350 25.550 78.450 38.200 ;
        RECT 78.450 25.450 78.550 38.200 ;
        RECT 84.850 17.500 95.950 20.000 ;
        RECT 84.850 10.500 87.350 27.700 ;
        RECT 86.150 25.200 88.650 38.200 ;
        RECT 95.350 10.500 97.850 16.000 ;
        RECT 97.450 13.500 99.950 38.200 ;
        RECT 96.950 26.700 99.950 38.200 ;
  END 
END DFCL11


macro DFFL11
  CLASS  CORE ;
  FOREIGN DFFL11 0.000 0.000 ;
  ORIGIN 0.000 0.000 ;
  SIZE 84.000 BY 48.700 ;
  SYMMETRY X Y  ;
  SITE CORE ;
  PIN Q
    DIRECTION OUTPUT ;
    PORT
      LAYER metal1 ;
        RECT 80.650 16.800 83.150 19.300 ;
    END
  END Q
  PIN C
    DIRECTION INPUT ;
    USE CLOCK ;
    PORT
      LAYER metal1 ;
        RECT 5.050 21.000 7.550 23.500 ;
    END
  END C
  PIN D
    DIRECTION INPUT ;
    PORT
      LAYER metal1 ;
        RECT 17.650 29.700 20.150 32.200 ;
    END
  END D
  PIN QB
    DIRECTION OUTPUT ;
    PORT
      LAYER metal1 ;
        RECT 68.050 16.800 70.550 19.300 ;
    END
  END QB
  PIN VSS
    DIRECTION INOUT ;
    USE GROUND ;
    SHAPE ABUTMENT ;
    PORT
      LAYER metal1 ;
        RECT 6.450 0.000 8.950 15.900 ;
        RECT 0.000 0.000 84.000 9.000 ;
        RECT 73.450 0.000 75.950 15.900 ;
        RECT 56.350 0.000 58.850 16.000 ;
        RECT 34.550 0.000 37.050 16.000 ;
    END
  END VSS
  PIN VDD
    DIRECTION INOUT ;
    USE POWER ;
    SHAPE ABUTMENT ;
    PORT
      LAYER metal1 ;
        RECT 6.750 29.000 9.250 48.700 ;
        RECT 0.000 39.700 84.000 48.700 ;
        RECT 73.450 26.000 75.950 48.700 ;
        RECT 56.650 29.000 59.150 48.700 ;
        RECT 34.450 33.900 36.950 48.700 ;
    END
  END VDD
  OBS 
      LAYER metal2 ;
        RECT 13.450 16.800 15.950 28.200 ;
        RECT 23.050 17.500 25.550 32.200 ;
        RECT 28.450 13.500 30.950 32.200 ;
        RECT 40.450 17.300 42.950 32.200 ;
        RECT 51.250 13.500 53.750 32.200 ;
        RECT 17.650 16.800 20.150 25.496 ;
        
        RECT 65.750 14.500 66.350 21.000 ;
        RECT 65.750 14.500 72.850 15.100 ;
        RECT 72.250 14.500 72.850 21.000 ;
        
      LAYER via1 ;
        
        RECT 13.950 26.200 15.450 27.700 ;
        RECT 13.950 17.300 15.450 18.800 ;
       
        RECT 18.150 17.300 19.650 18.800 ;
        RECT 23.550 30.200 25.050 31.700 ;
        RECT 23.550 18.000 25.050 19.500 ;
        RECT 28.950 30.200 30.450 31.700 ;
        RECT 28.950 14.000 30.450 15.500 ;
        RECT 40.950 30.200 42.450 31.700 ;
        RECT 40.950 17.800 42.450 19.300 ;
        RECT 51.750 30.200 53.250 31.700 ;
        RECT 51.750 14.000 53.250 15.500 ;
        
      LAYER metal1 ;
        RECT 5.050 17.600 7.550 23.500 ;
        RECT 11.550 10.500 14.050 19.300 ;
        RECT 11.550 16.800 15.950 19.300 ;
        RECT 17.650 29.700 20.150 38.200 ;
        RECT 17.650 10.500 20.150 19.300 ;
        RECT 0.850 10.500 3.850 16.000 ;
        RECT 9.250 21.500 23.250 24.000 ;
        RECT 0.850 10.500 3.350 38.200 ;
        RECT 9.250 21.500 11.750 27.500 ;
        RECT 0.850 25.000 11.750 27.500 ;
        RECT 0.850 25.000 3.850 38.200 ;
        RECT 23.050 29.700 25.550 38.200 ;
        RECT 28.450 29.700 30.950 38.200 ;
        RECT 28.450 10.500 30.950 16.000 ;
        RECT 23.050 10.500 25.550 20.000 ;
        RECT 23.050 17.500 38.350 20.000 ;
        RECT 24.750 21.500 41.950 24.000 ;
        RECT 24.750 21.500 27.150 28.200 ;
        RECT 13.450 25.700 27.150 28.200 ;
        RECT 13.450 25.700 15.950 31.900 ;
        RECT 12.150 29.700 14.650 38.200 ;
        RECT 32.450 29.700 42.950 32.200 ;
        RECT 40.450 29.700 42.950 38.200 ;
        RECT 40.450 10.500 42.950 19.800 ;
        RECT 43.450 21.500 51.650 24.000 ;
        RECT 43.450 21.500 45.850 28.200 ;
        RECT 28.650 25.700 45.850 28.200 ;
        RECT 51.250 29.700 53.750 38.200 ;
        RECT 51.250 10.500 53.750 16.000 ;
        RECT 45.750 10.500 48.250 20.000 ;
        RECT 45.750 17.500 60.550 20.000 ;
        RECT 53.150 17.500 55.550 27.900 ;
        RECT 47.350 25.500 55.550 27.900 ;
        RECT 47.350 25.500 49.750 38.200 ;
        RECT 45.850 32.700 49.750 38.200 ;
        RECT 57.050 21.700 66.550 24.200 ;
        RECT 62.050 10.500 64.550 38.200 ;
        RECT 68.050 19.700 77.950 22.200 ;
        RECT 68.050 10.500 70.550 38.200 ;
        RECT 78.850 10.500 83.150 16.000 ;
        RECT 80.650 10.500 83.150 38.200 ;
        RECT 78.850 26.700 83.150 38.200 ;
  END 
END DFFL11


macro DFPR11
  CLASS  CORE ;
  FOREIGN DFPR11 0.000 0.000 ;
  ORIGIN 0.000 0.000 ;
  SIZE 100.800 BY 48.700 ;
  SYMMETRY X Y  ;
  SITE CORE ;
  PIN Q
    DIRECTION OUTPUT ;
    PORT
      LAYER metal1 ;
        RECT 97.450 21.000 99.950 23.500 ;
    END
  END Q
  PIN C
    DIRECTION INPUT ;
    USE CLOCK ;
    PORT
      LAYER metal1 ;
        RECT 5.050 17.800 7.550 20.300 ;
    END
  END C
  PIN D
    DIRECTION INPUT ;
    PORT
      LAYER metal1 ;
        RECT 17.650 32.100 20.150 34.600 ;
    END
  END D
  PIN QB
    DIRECTION OUTPUT ;
    PORT
      LAYER metal1 ;
        RECT 84.850 14.150 87.350 16.650 ;
    END
  END QB
  PIN PRB
    DIRECTION INPUT ;
    PORT
      LAYER metal1 ;
        RECT 80.650 22.450 83.150 24.950 ;
    END
  END PRB
  
  PIN VSS
    DIRECTION INOUT ;
    USE GROUND ;
    SHAPE ABUTMENT ;
    PORT
      LAYER metal1 ;
        RECT 8.350 0.000 10.850 14.650 ;
        RECT 0.000 0.000 100.800 9.000 ;
        RECT 90.450 0.000 92.950 15.650 ;
        RECT 72.050 0.000 74.550 15.650 ;
        RECT 67.050 0.000 69.550 17.650 ;
        RECT 65.950 0.000 69.550 12.650 ;
        RECT 41.650 0.000 44.150 12.650 ;
    END
  END VSS
  PIN VDD
    DIRECTION INOUT ;
    USE POWER ;
    SHAPE ABUTMENT ;
    PORT
      LAYER metal1 ;
        RECT 7.750 28.700 10.250 48.700 ;
        RECT 0.000 39.700 100.800 48.700 ;
        RECT 91.150 26.900 93.650 48.700 ;
        RECT 80.550 30.000 83.050 48.700 ;
        RECT 69.750 30.100 72.250 48.700 ;
        RECT 47.800 32.400 50.300 48.700 ;
        RECT 37.150 36.300 39.650 48.700 ;
    END
  END VDD
  OBS 
      LAYER metal2 ;
      
        RECT 17.650 12.600 20.150 27.899 ;
       
        RECT 26.050 13.450 28.550 31.050 ;
        RECT 31.150 13.650 33.650 34.900 ;
        RECT 31.150 32.400 33.950 34.900 ;
        RECT 38.650 34.205 80.600 36.705 ;
        RECT 38.650 15.100 41.150 34.205 ;
        RECT 36.550 12.150 41.150 15.100 ;
        RECT 47.050 13.500 49.550 31.789 ;
        RECT 55.450 12.600 57.950 32.200 ;
        RECT 55.450 29.700 61.450 32.200 ;
        RECT 60.550 13.500 63.050 27.700 ;
        RECT 60.550 25.200 66.850 27.700 ;
        RECT 64.350 25.200 66.850 32.200 ;
        RECT 84.850 20.851 87.350 26.200 ;
        RECT 80.550 26.800 83.050 36.705 ;

    LAYER via1 ;
        
        
        RECT 18.150 13.100 19.650 14.600 ;
        RECT 26.550 29.000 28.050 30.500 ;
        RECT 26.550 14.000 28.050 15.500 ;
        RECT 31.650 14.150 33.150 15.650 ;
        RECT 31.950 32.900 33.450 34.400 ;
        RECT 37.050 12.650 38.550 14.150 ;
        RECT 47.550 29.612 49.050 31.112 ;
        RECT 47.550 14.000 49.050 15.500 ;
        RECT 55.950 13.100 57.450 14.600 ;
        RECT 59.450 30.200 60.950 31.700 ;
        RECT 61.050 14.000 62.550 15.500 ;
        RECT 64.850 30.200 66.350 31.700 ;
       
        RECT 85.350 23.400 86.850 24.900 ;
        
        
        
      LAYER metal1 ;
        RECT 5.050 17.750 7.550 23.300 ;
        RECT 13.450 10.500 15.950 20.400 ;
        RECT 13.450 17.900 19.450 20.400 ;
        RECT 17.100 19.750 20.750 22.250 ;
        RECT 17.650 32.100 20.150 35.200 ;
        RECT 17.650 32.700 23.150 35.200 ;
        RECT 20.650 32.700 23.150 38.200 ;
        RECT 17.650 10.650 23.450 13.150 ;
        RECT 17.650 10.650 20.150 15.100 ;
        RECT 13.450 28.100 24.550 30.600 ;
        RECT 13.450 28.100 15.950 38.200 ;
        RECT 26.050 10.500 28.550 16.000 ;
        RECT 26.050 13.450 28.650 16.000 ;
        RECT 31.150 10.650 33.650 16.150 ;
        RECT 35.550 12.150 39.050 15.100 ;
        RECT 35.550 12.150 38.050 18.950 ;
        RECT 31.450 32.400 45.000 34.800 ;
        RECT 31.450 32.400 33.950 37.900 ;
        RECT 42.500 32.550 45.050 38.200 ;
        RECT 43.050 28.400 45.550 30.900 ;
        RECT 26.050 28.500 45.550 30.900 ;
        RECT 26.050 28.500 28.550 38.150 ;
        RECT 47.050 10.500 49.550 18.950 ;
        RECT 40.550 16.450 49.550 18.950 ;
        RECT 47.050 28.400 55.750 30.900 ;
        RECT 53.250 28.400 55.750 38.200 ;
        RECT 52.150 10.500 54.650 15.100 ;
        RECT 52.150 12.550 57.100 15.100 ;
        RECT 52.150 12.600 57.950 15.100 ;
        RECT 0.850 10.500 5.750 16.000 ;
        RECT 22.500 17.200 25.150 26.600 ;
        RECT 10.750 22.300 13.250 26.400 ;
        RECT 9.050 24.000 27.950 26.400 ;
        RECT 22.500 23.850 27.950 26.600 ;
        RECT 26.850 24.400 58.200 26.900 ;
        RECT 0.850 24.800 11.550 27.200 ;
        RECT 0.850 10.500 3.350 28.500 ;
        RECT 2.350 24.800 4.850 38.200 ;
        RECT 60.550 10.500 63.050 16.000 ;
        RECT 29.450 20.200 31.950 22.900 ;
        RECT 51.050 17.550 53.550 22.900 ;
        RECT 29.450 20.450 53.550 22.900 ;
        RECT 60.550 20.400 63.100 22.900 ;
        RECT 29.450 20.500 63.100 22.900 ;
        RECT 64.350 29.700 66.850 35.200 ;
        RECT 59.700 25.800 73.650 28.200 ;
        RECT 71.150 25.750 73.650 28.250 ;
        RECT 59.700 25.800 62.100 32.150 ;
        RECT 58.950 29.700 61.450 35.200 ;
        RECT 80.650 22.450 83.150 28.500 ;
        RECT 79.150 26.000 83.150 28.500 ;
        RECT 84.850 10.500 87.850 13.000 ;
        RECT 84.850 10.500 87.350 17.050 ;
        RECT 80.350 10.500 82.850 20.950 ;
        RECT 65.200 20.500 67.700 23.000 ;
        RECT 75.100 18.550 88.700 20.950 ;
        RECT 86.200 18.550 88.700 21.050 ;
        RECT 65.200 20.600 77.650 23.000 ;
        RECT 75.150 18.550 77.650 38.200 ;
        RECT 92.400 21.300 95.450 23.800 ;
        RECT 84.850 22.600 94.800 25.200 ;
        RECT 84.850 22.600 88.250 26.200 ;
        RECT 85.750 22.600 88.250 38.200 ;
        RECT 95.850 10.500 98.550 19.650 ;
        RECT 97.350 16.800 99.950 29.350 ;
        RECT 96.550 26.700 99.050 38.200 ;
  END 
END DFPR11









macro VDDCON
  CLASS  CORE ;
  FOREIGN VDDCON 0.000 0.000 ;
  ORIGIN 0.000 0.000 ;
  SIZE 4.200 BY 48.700 ;
  SYMMETRY X Y  ;
  SITE CORE ;
  PIN VSS
    DIRECTION INOUT ;
    USE GROUND ;
    SHAPE ABUTMENT ;
    PORT
      LAYER metal1 ;
        RECT 0.000 0.000 4.200 9.000 ;
    END
  END VSS
  PIN TIEHI
    DIRECTION INOUT ;
    USE SIGNAL ;
    SHAPE ABUTMENT ;
    PORT
      LAYER metal1 ;
        RECT 0.850 25.200 3.350 27.700 ;
      
    END 
  END TIEHI
  PIN VDD
    DIRECTION INOUT ;
    USE POWER ;
    SHAPE ABUTMENT ;
    PORT
      
      LAYER metal1 ;
        RECT 0.850 23.350 3.350 48.700 ;
        RECT 0.000 39.700 4.200 48.700 ;
    END
  END VDD
 
 
END VDDCON

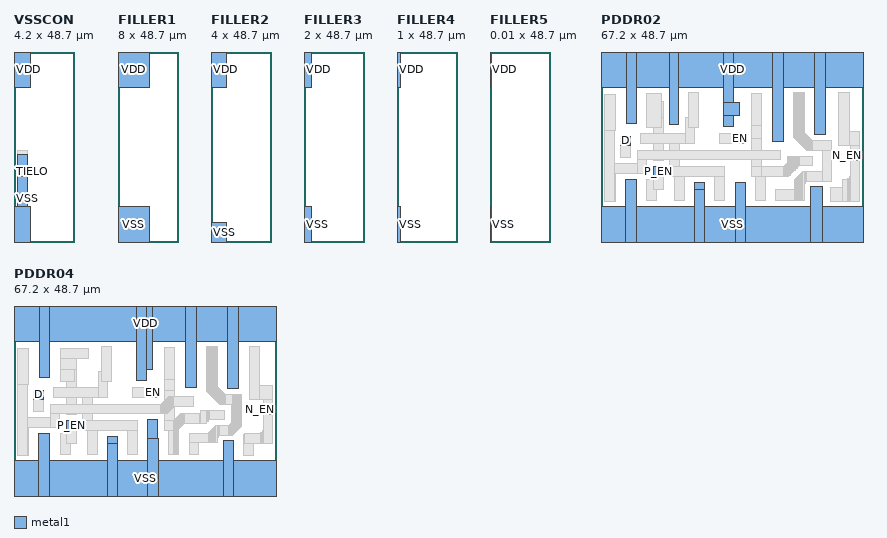
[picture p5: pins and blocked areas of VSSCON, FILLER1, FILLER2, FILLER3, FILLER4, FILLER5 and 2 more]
macro VSSCON
  CLASS  CORE ;
  FOREIGN VSSCON 0.000 0.000 ;
  ORIGIN 0.000 0.000 ;
  SIZE 4.200 BY 48.700 ;
  SYMMETRY X Y  ;
  SITE CORE ;
  PIN VSS
    DIRECTION INOUT ;
    USE GROUND ;
    SHAPE ABUTMENT ;
    PORT
      LAYER metal1 ;
        RECT 0.850 0.000 3.350 22.500 ;
        RECT 0.000 0.000 4.200 9.000 ;
    END
  END VSS
   PIN TIELO
    DIRECTION INOUT ;
    USE SIGNAL ;
    SHAPE ABUTMENT ;
    PORT
      LAYER metal1 ;
        RECT 0.850 16.800 3.350 19.300 ;
      
    END 
  END TIELO
  PIN VDD
    DIRECTION INOUT ;
    USE POWER ;
    SHAPE ABUTMENT ;
    PORT
      LAYER metal1 ;
        RECT 0.000 39.700 4.200 48.700 ;
    END
  END VDD
  OBS 
      LAYER metal1 ;
        RECT 0.850 16.800 3.350 23.500 ;
     
  END 
END VSSCON


macro FILLER1
  CLASS  CORE ;
  FOREIGN FILLER1 0.000 0.000 ;
  ORIGIN 0.000 0.000 ;
  SIZE 8.000 BY 48.700 ;
  SYMMETRY X Y  ;
  SITE CORE ;
  PIN VSS
    DIRECTION INOUT ;
    USE GROUND ;
    SHAPE ABUTMENT ;
    PORT
      LAYER metal1 ;
        RECT 0.000 0.000 8.000 9.000 ;
    END
  END VSS
  PIN VDD
    DIRECTION INOUT ;
    USE POWER ;
    SHAPE ABUTMENT ;
    PORT
      LAYER metal1 ;
        RECT 0.000 39.700 8.000 48.700 ;
    END
  END VDD
END FILLER1

macro FILLER2
  CLASS  CORE ;
  FOREIGN FILLER2 0.000 0.000 ;
  ORIGIN 0.000 0.000 ;
  SIZE 4.000 BY 48.700 ;
  SYMMETRY X Y  ;
  SITE CORE ;
  PIN VSS
    DIRECTION INOUT ;
    USE GROUND ;
    SHAPE ABUTMENT ;
    PORT
      LAYER metal1 ;
        RECT 0.000 0.000 4.000 5.000 ;
    END
  END VSS
  PIN VDD
    DIRECTION INOUT ;
    USE POWER ;
    SHAPE ABUTMENT ;
    PORT
      LAYER metal1 ;
        RECT 0.000 39.700 4.000 48.700 ;
    END
  END VDD
END FILLER2

macro FILLER3
  CLASS  CORE ;
  FOREIGN FILLER3 0.000 0.000 ;
  ORIGIN 0.000 0.000 ;
  SIZE 2.000 BY 48.700 ;
  SYMMETRY X Y  ;
  SITE CORE ;
  PIN VSS
    DIRECTION INOUT ;
    USE GROUND ;
    SHAPE ABUTMENT ;
    PORT
      LAYER metal1 ;
        RECT 0.000 0.000 2.000 9.000 ;
    END
  END VSS
  PIN VDD
    DIRECTION INOUT ;
    USE POWER ;
    SHAPE ABUTMENT ;
    PORT
      LAYER metal1 ;
        RECT 0.000 39.700 2.000 48.700 ;
    END
  END VDD
END FILLER3

macro FILLER4
  CLASS  CORE ;
  FOREIGN FILLER4 0.000 0.000 ;
  ORIGIN 0.000 0.000 ;
  SIZE 1.000 BY 48.700 ;
  SYMMETRY X Y  ;
  SITE CORE ;
  PIN VSS
    DIRECTION INOUT ;
    USE GROUND ;
    SHAPE ABUTMENT ;
    PORT
      LAYER metal1 ;
        RECT 0.000 0.000 1.000 9.000 ;
    END
  END VSS
  PIN VDD
    DIRECTION INOUT ;
    USE POWER ;
    SHAPE ABUTMENT ;
    PORT
      LAYER metal1 ;
        RECT 0.000 39.700 1.000 48.700 ;
    END
  END VDD
END FILLER4

macro FILLER5
  CLASS  CORE ;
  FOREIGN FILLER5 0.000 0.000 ;
  ORIGIN 0.000 0.000 ;
  SIZE 0.01 BY 48.700 ;
  SYMMETRY X Y  ;
  SITE CORE ;
  PIN VSS
    DIRECTION INOUT ;
    USE GROUND ;
    SHAPE ABUTMENT ;
    PORT
      LAYER metal1 ;
        RECT 0.000 0.000 0.050 9.000 ;
    END
  END VSS
  PIN VDD
    DIRECTION INOUT ;
    USE POWER ;
    SHAPE ABUTMENT ;
    PORT
      LAYER metal1 ;
        RECT 0.000 39.700 0.050 48.700 ;
    END
  END VDD
END FILLER5
macro PDDR02
  CLASS  CORE ;
  FOREIGN PDDR02 0.000 0.000 ;
  ORIGIN 0.000 0.000 ;
  SIZE 67.200 BY 48.700 ;
  SYMMETRY X Y  ;
  SITE CORE ;
  PIN D
    DIRECTION INPUT ;
    PORT
      LAYER metal1 ;
        RECT 5.050 24.650 7.550 27.150 ;
    END
  END D
  PIN N_EN
    DIRECTION OUTPUT ;
    PORT
      LAYER metal1 ;
        RECT 63.850 21.000 66.350 23.500 ;
    END
  END N_EN
  PIN EN
    DIRECTION INPUT ;
    PORT
      LAYER metal1 ;
        RECT 34.450 25.200 36.950 27.700 ;
    END
  END EN
  PIN VSS
    DIRECTION INOUT ;
    USE GROUND ;
    SHAPE ABUTMENT ;
    PORT
      LAYER metal1 ;
        RECT 6.350 0.000 9.000 16.050 ;
        RECT 0.000 0.000 67.200 9.000 ;
        RECT 53.700 0.000 56.700 14.100 ;
        RECT 34.450 0.000 36.950 15.300 ;
        RECT 24.000 0.000 26.500 15.300 ;
        RECT 23.900 0.000 26.500 13.450 ;
    END
  END VSS
  PIN VDD
    DIRECTION INOUT ;
    USE POWER ;
    SHAPE ABUTMENT ;
    PORT
      LAYER metal1 ;
        RECT 0.000 39.700 67.200 48.700 ;
        RECT 54.800 27.500 57.550 48.700 ;
        RECT 44.000 25.850 46.700 48.700 ;
        RECT 31.500 32.550 35.600 35.750 ;
        RECT 31.500 29.550 34.000 48.700 ;
        RECT 17.450 30.150 19.950 48.700 ;
        RECT 6.650 30.350 9.150 48.700 ;
    END
  END VDD
  PIN P_EN
    DIRECTION OUTPUT ;
    PORT
      LAYER metal1 ;
        
        RECT 13.450 16.800 15.950 19.300 ;
    END
  END P_EN
  OBS 
      LAYER metal2 ;
        RECT 17.650 16.800 20.150 27.700 ;
        RECT 38.650 16.800 41.150 29.100 ;
        RECT 13.450 21.000 15.950 36.100 ;
        RECT 12.000 31.950 15.950 36.100 ;
      LAYER via1 ;
        
        RECT 12.550 32.850 14.050 34.350 ;
       
        RECT 18.150 25.700 19.650 27.200 ;
        RECT 18.150 17.300 19.650 18.800 ;
        
        RECT 39.150 27.100 40.650 28.600 ;
        RECT 39.150 17.300 40.650 18.800 ;
       
      LAYER metal1 ;
        RECT 5.050 21.650 7.550 27.150 ;
        RECT 11.550 29.300 15.550 37.950 ;
        RECT 11.600 10.600 14.200 16.100 ;
        RECT 13.450 13.350 15.950 19.300 ;
        RECT 10.150 25.200 24.050 27.700 ;
        RECT 21.550 25.200 24.050 31.900 ;
        RECT 22.450 29.450 24.950 38.200 ;
        RECT 18.900 10.600 21.500 19.300 ;
        RECT 29.050 10.600 31.650 19.300 ;
        RECT 17.650 16.800 31.650 19.300 ;
        RECT 30.250 25.200 36.950 27.700 ;
        RECT 38.650 26.600 41.150 30.000 ;
        RECT 38.600 29.900 41.100 38.150 ;
        RECT 0.850 10.500 3.750 20.050 ;
        RECT 0.850 17.650 11.700 20.050 ;
        RECT 9.300 17.650 11.700 23.550 ;
        RECT 9.300 21.050 46.100 23.550 ;
        RECT 0.850 10.500 3.350 37.900 ;
        RECT 0.850 28.700 3.750 37.900 ;
        RECT 39.600 10.750 42.100 19.250 ;
        RECT 38.650 16.750 46.800 19.250 ;
        RECT 38.650 16.750 41.150 19.300 ;
        RECT 47.800 16.750 48.050 22.000 ;
        RECT 50.800 19.500 54.100 22.000 ;
        RECT 48.050 16.850 48.150 22.000 ;
        RECT 48.150 16.950 48.250 22.000 ;
        RECT 48.250 17.050 48.350 22.000 ;
        RECT 48.350 17.150 48.450 22.000 ;
        RECT 48.450 17.250 48.550 22.000 ;
        RECT 48.550 17.350 48.650 22.000 ;
        RECT 48.650 17.450 48.750 22.000 ;
        RECT 48.750 17.550 48.850 22.000 ;
        RECT 48.850 17.650 48.950 22.000 ;
        RECT 48.950 17.750 49.050 22.000 ;
        RECT 49.050 17.850 49.150 22.000 ;
        RECT 49.150 17.950 49.250 22.000 ;
        RECT 49.250 18.050 49.350 22.000 ;
        RECT 49.350 18.150 49.450 22.000 ;
        RECT 49.450 18.250 49.550 22.000 ;
        RECT 49.550 18.350 49.650 22.000 ;
        RECT 49.650 18.450 49.750 22.000 ;
        RECT 49.750 18.550 49.850 22.000 ;
        RECT 49.850 18.650 49.950 22.000 ;
        RECT 49.950 18.750 50.050 22.000 ;
        RECT 50.050 18.850 50.150 22.000 ;
        RECT 50.150 18.950 50.250 22.000 ;
        RECT 50.250 19.050 50.350 22.000 ;
        RECT 50.350 19.150 50.450 22.000 ;
        RECT 50.450 19.250 50.550 22.000 ;
        RECT 50.550 19.350 50.650 22.000 ;
        RECT 50.650 19.450 50.750 22.000 ;
        RECT 50.750 19.500 50.800 22.000 ;
        RECT 46.800 16.750 46.900 19.250 ;
        RECT 46.900 16.750 47.000 19.350 ;
        RECT 47.000 16.750 47.100 19.450 ;
        RECT 47.100 16.750 47.200 19.550 ;
        RECT 47.200 16.750 47.300 19.650 ;
        RECT 47.300 16.750 47.400 19.750 ;
        RECT 47.400 16.750 47.500 19.850 ;
        RECT 47.500 16.750 47.600 19.950 ;
        RECT 47.600 16.750 47.700 20.050 ;
        RECT 47.700 16.750 47.800 20.150 ;
        RECT 44.600 10.700 49.700 13.350 ;
        RECT 51.700 10.700 52.100 18.000 ;
        RECT 52.800 15.600 59.200 18.000 ;
        RECT 56.700 15.600 59.200 25.950 ;
        RECT 54.151 23.550 59.200 25.950 ;
        RECT 52.600 23.550 52.700 27.401 ;
        RECT 52.700 23.550 52.800 27.301 ;
        RECT 52.800 23.550 52.900 27.201 ;
        RECT 52.900 23.550 53.000 27.101 ;
        RECT 53.000 23.550 53.100 27.001 ;
        RECT 53.100 23.550 53.200 26.901 ;
        RECT 53.200 23.550 53.300 26.801 ;
        RECT 53.300 23.550 53.400 26.701 ;
        RECT 53.400 23.550 53.500 26.601 ;
        RECT 53.500 23.550 53.600 26.501 ;
        RECT 53.600 23.550 53.700 26.401 ;
        RECT 53.700 23.550 53.800 26.301 ;
        RECT 53.800 23.550 53.900 26.201 ;
        RECT 53.900 23.550 54.000 26.101 ;
        RECT 54.000 23.550 54.100 26.001 ;
        RECT 54.100 23.550 54.151 25.950 ;
        RECT 52.100 15.000 52.200 18.000 ;
        RECT 52.200 15.100 52.300 18.000 ;
        RECT 52.300 15.200 52.400 18.000 ;
        RECT 52.400 15.300 52.500 18.000 ;
        RECT 52.500 15.400 52.600 18.000 ;
        RECT 52.600 15.500 52.700 18.000 ;
        RECT 52.700 15.600 52.800 18.000 ;
        RECT 52.150 24.000 52.250 27.851 ;
        RECT 52.250 23.900 52.350 27.751 ;
        RECT 52.350 23.800 52.450 27.651 ;
        RECT 52.450 23.700 52.550 27.551 ;
        RECT 52.550 23.600 52.600 27.501 ;
        RECT 49.400 26.750 49.500 38.200 ;
        RECT 49.500 26.650 49.600 38.200 ;
        RECT 49.600 26.550 49.700 38.200 ;
        RECT 49.700 26.450 49.800 38.200 ;
        RECT 49.800 26.350 49.900 38.200 ;
        RECT 49.900 26.250 50.000 38.200 ;
        RECT 50.000 26.150 50.100 38.200 ;
        RECT 50.100 26.050 50.200 38.200 ;
        RECT 50.200 25.950 50.300 38.200 ;
        RECT 50.300 25.850 50.400 38.200 ;
        RECT 50.400 25.750 50.500 38.200 ;
        RECT 50.500 25.650 50.600 38.200 ;
        RECT 50.600 25.550 50.700 38.200 ;
        RECT 50.700 25.450 50.800 38.200 ;
        RECT 50.800 25.350 50.900 38.200 ;
        RECT 50.900 25.250 51.000 38.200 ;
        RECT 51.000 25.150 51.100 38.200 ;
        RECT 51.100 25.050 51.200 38.200 ;
        RECT 51.200 24.950 51.300 38.200 ;
        RECT 51.300 24.850 51.400 38.200 ;
        RECT 51.400 24.750 51.500 38.200 ;
        RECT 51.500 24.650 51.600 38.200 ;
        RECT 51.600 24.550 51.700 38.200 ;
        RECT 51.700 24.450 51.800 38.200 ;
        RECT 51.800 24.350 51.900 38.200 ;
        RECT 51.900 24.250 52.000 38.200 ;
        RECT 52.000 24.150 52.100 38.200 ;
        RECT 52.100 24.050 52.150 38.200 ;
        RECT 49.700 10.700 49.800 16.000 ;
        RECT 49.800 10.700 49.900 16.100 ;
        RECT 49.900 10.700 50.000 16.200 ;
        RECT 50.000 10.700 50.100 16.300 ;
        RECT 50.100 10.700 50.200 16.400 ;
        RECT 50.200 10.700 50.300 16.500 ;
        RECT 50.300 10.700 50.400 16.600 ;
        RECT 50.400 10.700 50.500 16.700 ;
        RECT 50.500 10.700 50.600 16.800 ;
        RECT 50.600 10.700 50.700 16.900 ;
        RECT 50.700 10.700 50.800 17.000 ;
        RECT 50.800 10.700 50.900 17.100 ;
        RECT 50.900 10.700 51.000 17.200 ;
        RECT 51.000 10.700 51.100 17.300 ;
        RECT 51.100 10.700 51.200 17.400 ;
        RECT 51.200 10.700 51.300 17.500 ;
        RECT 51.300 10.700 51.400 17.600 ;
        RECT 51.400 10.700 51.500 17.700 ;
        RECT 51.500 10.700 51.600 17.800 ;
        RECT 51.600 10.700 51.700 17.900 ;
        RECT 58.800 10.500 66.350 14.050 ;
        RECT 61.800 10.500 66.350 15.800 ;
        RECT 61.900 10.500 66.350 15.900 ;
        RECT 62.000 10.500 66.350 16.000 ;
        RECT 63.200 10.500 66.350 16.100 ;
        RECT 63.300 10.500 66.350 16.200 ;
        RECT 63.400 10.500 66.350 16.300 ;
        RECT 63.500 10.500 66.350 16.400 ;
        RECT 63.600 10.500 66.350 16.500 ;
        RECT 63.700 10.500 66.350 16.600 ;
        RECT 63.800 10.500 66.350 16.700 ;
        RECT 63.850 10.500 66.350 28.200 ;
        RECT 60.950 24.850 66.350 28.200 ;
        RECT 60.950 24.850 63.600 38.200 ;
  END 
END PDDR02

macro PDDR04
  CLASS  CORE ;
  FOREIGN PDDR04 0.000 0.000 ;
  ORIGIN 0.000 0.000 ;
  SIZE 67.200 BY 48.700 ;
  SYMMETRY X Y  ;
  SITE CORE ;
  PIN D
    DIRECTION INPUT ;
    PORT
      LAYER metal1 ;
        RECT 5.050 24.650 7.550 27.150 ;
    END
  END D
  PIN N_EN
    DIRECTION OUTPUT ;
    PORT
      LAYER metal1 ;
        RECT 63.850 21.000 66.350 23.500 ;
    END
  END N_EN
  PIN EN
    DIRECTION INPUT ;
    PORT
      LAYER metal1 ;
        RECT 34.450 25.200 36.950 27.700 ;
    END
  END EN
  PIN VSS
    DIRECTION INOUT ;
    USE GROUND ;
    SHAPE ABUTMENT ;
    PORT
      LAYER metal1 ;
        RECT 6.350 0.000 9.000 16.050 ;
        RECT 0.000 0.000 67.200 9.000 ;
        RECT 53.700 0.000 56.350 14.100 ;
        RECT 34.200 0.000 36.950 14.800 ;
        RECT 34.200 0.000 36.700 19.500 ;
        RECT 24.000 0.000 26.500 15.300 ;
        RECT 23.900 0.000 26.500 13.450 ;
    END
  END VSS
  PIN VDD
    DIRECTION INOUT ;
    USE POWER ;
    SHAPE ABUTMENT ;
    PORT
      LAYER metal1 ;
        RECT 6.650 30.350 9.150 48.700 ;
        RECT 0.000 39.700 67.200 48.700 ;
        RECT 54.800 27.500 57.550 48.700 ;
        RECT 44.000 27.700 46.700 48.700 ;
        RECT 31.500 32.550 35.600 48.700 ;
        RECT 31.500 29.550 34.000 48.700 ;
    END
  END VDD
  PIN P_EN
    DIRECTION OUTPUT ;
    PORT
      LAYER metal1 ;
        RECT 13.450 16.800 15.950 19.300 ;
    END
  END P_EN
  OBS 
      LAYER metal2 ;
        RECT 17.650 16.800 20.150 27.700 ;
        RECT 38.650 16.800 41.150 29.650 ;
        RECT 13.450 21.000 15.950 36.100 ;
      LAYER via1 ;
       
        
        RECT 13.950 32.850 15.450 34.350 ;
        RECT 18.150 25.700 19.650 27.200 ;
        RECT 18.150 17.300 19.650 18.800 ;
       
        RECT 39.150 27.650 40.650 29.150 ;
        RECT 39.150 17.300 40.650 18.800 ;
      
      LAYER metal1 ;
        RECT 5.050 21.650 7.550 27.150 ;
        RECT 11.800 10.600 14.400 16.100 ;
        RECT 13.450 13.350 15.950 19.300 ;
        RECT 12.000 29.300 15.550 37.850 ;
        RECT 12.000 32.350 15.950 37.850 ;
        RECT 12.000 35.350 19.200 37.850 ;
        RECT 10.150 25.200 24.050 27.700 ;
        RECT 21.550 25.200 24.050 31.900 ;
        RECT 22.450 29.450 24.950 38.200 ;
        RECT 18.900 10.600 21.500 19.300 ;
        RECT 17.650 16.800 21.500 19.300 ;
        RECT 29.050 10.600 31.650 19.300 ;
        RECT 17.650 16.900 31.650 19.300 ;
        RECT 30.250 25.200 36.950 27.700 ;
        RECT 38.650 27.150 41.150 30.000 ;
        RECT 38.600 29.900 41.100 38.150 ;
        RECT 0.850 10.500 3.750 20.050 ;
        RECT 0.850 17.650 11.700 20.050 ;
        RECT 9.300 17.650 11.700 23.550 ;
        RECT 9.300 21.050 37.649 23.550 ;
        RECT 40.950 22.850 46.100 25.550 ;
        RECT 0.850 10.500 3.350 37.900 ;
        RECT 0.850 28.700 3.750 37.900 ;
        RECT 39.649 21.649 39.749 25.550 ;
        RECT 39.749 21.749 39.849 25.550 ;
        RECT 39.849 21.849 39.949 25.550 ;
        RECT 39.949 21.949 40.049 25.550 ;
        RECT 40.049 22.049 40.149 25.550 ;
        RECT 40.149 22.149 40.249 25.550 ;
        RECT 40.249 22.249 40.349 25.550 ;
        RECT 40.349 22.349 40.449 25.550 ;
        RECT 40.449 22.449 40.549 25.550 ;
        RECT 40.549 22.549 40.649 25.550 ;
        RECT 40.649 22.649 40.749 25.550 ;
        RECT 40.749 22.749 40.849 25.550 ;
        RECT 40.849 22.849 40.949 25.550 ;
        RECT 40.949 22.850 40.950 25.550 ;
        RECT 39.150 21.150 39.250 25.051 ;
        RECT 39.250 21.250 39.350 25.151 ;
        RECT 39.350 21.350 39.450 25.251 ;
        RECT 39.450 21.450 39.550 25.351 ;
        RECT 39.550 21.549 39.649 25.451 ;
        RECT 37.649 21.050 37.749 23.550 ;
        RECT 37.749 21.050 37.849 23.650 ;
        RECT 37.849 21.050 37.949 23.750 ;
        RECT 37.949 21.050 38.049 23.850 ;
        RECT 38.049 21.050 38.149 23.950 ;
        RECT 38.149 21.050 38.249 24.050 ;
        RECT 38.249 21.050 38.349 24.150 ;
        RECT 38.349 21.050 38.449 24.250 ;
        RECT 38.449 21.050 38.549 24.350 ;
        RECT 38.549 21.050 38.649 24.450 ;
        RECT 38.649 21.050 38.749 24.550 ;
        RECT 38.749 21.050 38.849 24.650 ;
        RECT 38.849 21.050 38.949 24.750 ;
        RECT 38.949 21.050 39.049 24.850 ;
        RECT 39.049 21.050 39.149 24.950 ;
        RECT 39.149 21.050 39.150 25.050 ;
        RECT 39.600 10.750 40.850 19.300 ;
        RECT 38.650 16.750 40.850 19.300 ;
        RECT 43.786 18.700 47.650 21.200 ;
        RECT 47.800 18.700 49.250 22.000 ;
        RECT 50.050 19.500 53.950 22.000 ;
        RECT 49.250 18.800 49.350 22.000 ;
        RECT 49.350 18.900 49.450 22.000 ;
        RECT 49.450 19.000 49.550 22.000 ;
        RECT 49.550 19.100 49.650 22.000 ;
        RECT 49.650 19.200 49.750 22.000 ;
        RECT 49.750 19.300 49.850 22.000 ;
        RECT 49.850 19.400 49.950 22.000 ;
        RECT 49.950 19.500 50.050 22.000 ;
        RECT 47.650 18.700 47.750 21.200 ;
        RECT 47.750 18.700 47.800 21.300 ;
        RECT 42.750 17.764 42.850 21.200 ;
        RECT 42.850 17.864 42.950 21.200 ;
        RECT 42.950 17.964 43.050 21.200 ;
        RECT 43.050 18.064 43.150 21.200 ;
        RECT 43.150 18.164 43.250 21.200 ;
        RECT 43.250 18.264 43.350 21.200 ;
        RECT 43.350 18.364 43.450 21.200 ;
        RECT 43.450 18.464 43.550 21.200 ;
        RECT 43.550 18.564 43.650 21.200 ;
        RECT 43.650 18.664 43.750 21.200 ;
        RECT 43.750 18.700 43.786 21.200 ;
        RECT 42.100 17.114 42.200 20.550 ;
        RECT 42.200 17.214 42.300 20.650 ;
        RECT 42.300 17.314 42.400 20.750 ;
        RECT 42.400 17.414 42.500 20.850 ;
        RECT 42.500 17.514 42.600 20.950 ;
        RECT 42.600 17.614 42.700 21.050 ;
        RECT 42.700 17.664 42.750 21.150 ;
        RECT 40.850 10.750 40.950 19.300 ;
        RECT 40.950 10.750 41.050 19.400 ;
        RECT 41.050 10.750 41.150 19.500 ;
        RECT 41.150 10.750 41.250 19.600 ;
        RECT 41.250 10.750 41.350 19.700 ;
        RECT 41.350 10.750 41.450 19.800 ;
        RECT 41.450 10.750 41.550 19.900 ;
        RECT 41.550 10.750 41.650 20.000 ;
        RECT 41.650 10.750 41.750 20.100 ;
        RECT 41.750 10.750 41.850 20.200 ;
        RECT 41.850 10.750 41.950 20.300 ;
        RECT 41.950 10.750 42.050 20.400 ;
        RECT 42.050 10.750 42.100 20.500 ;
        RECT 44.900 10.600 47.400 16.100 ;
        RECT 44.900 13.600 49.850 16.100 ;
        RECT 51.700 13.600 52.100 18.000 ;
        RECT 52.800 15.600 54.950 18.000 ;
        RECT 55.850 15.600 56.050 25.950 ;
        RECT 54.151 23.550 56.050 25.950 ;
        RECT 56.050 15.700 56.150 25.950 ;
        RECT 56.150 15.800 56.250 25.950 ;
        RECT 56.250 15.900 56.350 25.950 ;
        RECT 56.350 16.000 56.450 25.950 ;
        RECT 56.450 16.100 56.550 25.950 ;
        RECT 56.550 16.200 56.650 25.950 ;
        RECT 56.650 16.300 56.750 25.950 ;
        RECT 56.750 16.400 56.850 25.950 ;
        RECT 56.850 16.500 56.950 25.950 ;
        RECT 56.950 16.600 57.050 25.950 ;
        RECT 57.050 16.700 57.150 25.950 ;
        RECT 57.150 16.800 57.250 25.950 ;
        RECT 57.250 16.900 57.350 25.950 ;
        RECT 57.350 17.000 57.450 25.950 ;
        RECT 57.450 17.100 57.550 25.950 ;
        RECT 57.550 17.200 57.650 25.950 ;
        RECT 57.650 17.300 57.750 25.950 ;
        RECT 57.750 17.400 57.850 25.950 ;
        RECT 57.850 17.500 57.950 25.950 ;
        RECT 57.950 17.600 58.050 25.950 ;
        RECT 58.050 17.700 58.150 25.950 ;
        RECT 58.150 17.800 58.250 25.950 ;
        RECT 58.250 17.900 58.350 25.950 ;
        RECT 54.950 15.600 55.050 18.000 ;
        RECT 55.050 15.600 55.150 18.100 ;
        RECT 55.150 15.600 55.250 18.200 ;
        RECT 55.250 15.600 55.350 18.300 ;
        RECT 55.350 15.600 55.450 18.400 ;
        RECT 55.450 15.600 55.550 18.500 ;
        RECT 55.550 15.600 55.650 18.600 ;
        RECT 55.650 15.600 55.750 18.700 ;
        RECT 55.750 15.600 55.850 18.800 ;
        RECT 52.600 23.550 52.700 27.401 ;
        RECT 52.700 23.550 52.800 27.301 ;
        RECT 52.800 23.550 52.900 27.201 ;
        RECT 52.900 23.550 53.000 27.101 ;
        RECT 53.000 23.550 53.100 27.001 ;
        RECT 53.100 23.550 53.200 26.901 ;
        RECT 53.200 23.550 53.300 26.801 ;
        RECT 53.300 23.550 53.400 26.701 ;
        RECT 53.400 23.550 53.500 26.601 ;
        RECT 53.500 23.550 53.600 26.501 ;
        RECT 53.600 23.550 53.700 26.401 ;
        RECT 53.700 23.550 53.800 26.301 ;
        RECT 53.800 23.550 53.900 26.201 ;
        RECT 53.900 23.550 54.000 26.101 ;
        RECT 54.000 23.550 54.100 26.001 ;
        RECT 54.100 23.550 54.151 25.950 ;
        RECT 52.100 15.000 52.200 18.000 ;
        RECT 52.200 15.100 52.300 18.000 ;
        RECT 52.300 15.200 52.400 18.000 ;
        RECT 52.400 15.300 52.500 18.000 ;
        RECT 52.500 15.400 52.600 18.000 ;
        RECT 52.600 15.500 52.700 18.000 ;
        RECT 52.700 15.600 52.800 18.000 ;
        RECT 52.150 24.000 52.250 27.851 ;
        RECT 52.250 23.900 52.350 27.751 ;
        RECT 52.350 23.800 52.450 27.651 ;
        RECT 52.450 23.700 52.550 27.551 ;
        RECT 52.550 23.600 52.600 27.501 ;
        RECT 49.400 26.750 49.500 38.200 ;
        RECT 49.500 26.650 49.600 38.200 ;
        RECT 49.600 26.550 49.700 38.200 ;
        RECT 49.700 26.450 49.800 38.200 ;
        RECT 49.800 26.350 49.900 38.200 ;
        RECT 49.900 26.250 50.000 38.200 ;
        RECT 50.000 26.150 50.100 38.200 ;
        RECT 50.100 26.050 50.200 38.200 ;
        RECT 50.200 25.950 50.300 38.200 ;
        RECT 50.300 25.850 50.400 38.200 ;
        RECT 50.400 25.750 50.500 38.200 ;
        RECT 50.500 25.650 50.600 38.200 ;
        RECT 50.600 25.550 50.700 38.200 ;
        RECT 50.700 25.450 50.800 38.200 ;
        RECT 50.800 25.350 50.900 38.200 ;
        RECT 50.900 25.250 51.000 38.200 ;
        RECT 51.000 25.150 51.100 38.200 ;
        RECT 51.100 25.050 51.200 38.200 ;
        RECT 51.200 24.950 51.300 38.200 ;
        RECT 51.300 24.850 51.400 38.200 ;
        RECT 51.400 24.750 51.500 38.200 ;
        RECT 51.500 24.650 51.600 38.200 ;
        RECT 51.600 24.550 51.700 38.200 ;
        RECT 51.700 24.450 51.800 38.200 ;
        RECT 51.800 24.350 51.900 38.200 ;
        RECT 51.900 24.250 52.000 38.200 ;
        RECT 52.000 24.150 52.100 38.200 ;
        RECT 52.100 24.050 52.150 38.200 ;
        RECT 49.850 13.600 49.950 16.150 ;
        RECT 49.950 13.600 50.050 16.250 ;
        RECT 50.050 13.600 50.150 16.350 ;
        RECT 50.150 13.600 50.250 16.450 ;
        RECT 50.250 13.600 50.350 16.550 ;
        RECT 50.350 13.600 50.450 16.650 ;
        RECT 50.450 13.600 50.550 16.750 ;
        RECT 50.550 13.600 50.650 16.850 ;
        RECT 50.650 13.600 50.750 16.950 ;
        RECT 50.750 13.600 50.850 17.050 ;
        RECT 50.850 13.600 50.950 17.150 ;
        RECT 50.950 13.600 51.050 17.250 ;
        RECT 51.050 13.600 51.150 17.350 ;
        RECT 51.150 13.600 51.250 17.450 ;
        RECT 51.250 13.600 51.350 17.550 ;
        RECT 51.350 13.600 51.450 17.650 ;
        RECT 51.450 13.600 51.550 17.750 ;
        RECT 51.550 13.600 51.650 17.850 ;
        RECT 51.650 13.600 51.700 17.950 ;
        RECT 58.800 10.500 61.300 15.745 ;
        RECT 58.900 13.400 66.350 15.845 ;
        RECT 59.000 13.400 66.350 15.945 ;
        RECT 59.055 13.400 66.350 16.000 ;
        RECT 63.200 13.400 66.350 16.100 ;
        RECT 63.300 13.400 66.350 16.200 ;
        RECT 63.400 13.400 66.350 16.300 ;
        RECT 63.500 13.400 66.350 16.400 ;
        RECT 63.600 13.400 66.350 16.500 ;
        RECT 63.700 13.400 66.350 16.600 ;
        RECT 63.800 13.400 66.350 16.700 ;
        RECT 63.850 13.400 66.350 28.200 ;
        RECT 60.300 24.850 66.350 28.200 ;
        RECT 60.300 24.850 62.950 38.200 ;
  END 
END PDDR04

END LIBRARY
